UNITS
  DATABASE MICRONS 1000 ;
END UNITS


VERSION 5.7 ;
NAMESCASESENSITIVE ON ;
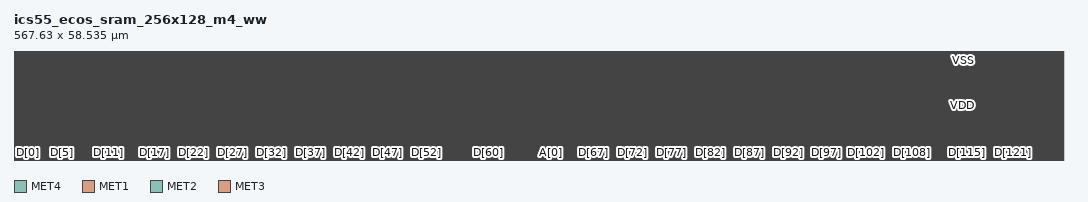
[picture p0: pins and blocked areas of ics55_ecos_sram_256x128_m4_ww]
MACRO ics55_ecos_sram_256x128_m4_ww
CLASS BLOCK ;
FOREIGN ics55_ecos_sram_256x128_m4_ww 0.000 0.000 ;
ORIGIN 0.000 0.000 ;
SIZE 567.630 BY 58.535 ;
SYMMETRY X Y R90 ;

PIN VDD
  DIRECTION INOUT ;
  USE POWER ;
  PORT
    LAYER MET4 ;
    RECT 0.605 0.000 1.015 58.535 ;
    RECT 1.735 0.000 2.145 58.535 ;
    RECT 2.335 0.000 2.745 58.535 ;
    RECT 3.535 0.000 3.945 58.535 ;
    RECT 4.135 0.000 4.545 58.535 ;
    RECT 4.735 0.000 5.145 58.535 ;
    RECT 5.935 0.000 6.345 58.535 ;
    RECT 6.535 0.000 6.945 58.535 ;
    RECT 7.735 0.000 8.145 58.535 ;
    RECT 8.335 0.000 8.745 58.535 ;
    RECT 8.935 0.000 9.345 58.535 ;
    RECT 10.135 0.000 10.545 58.535 ;
    RECT 10.735 0.000 11.145 58.535 ;
    RECT 11.935 0.000 12.345 58.535 ;
    RECT 12.535 0.000 12.945 58.535 ;
    RECT 13.135 0.000 13.545 58.535 ;
    RECT 14.335 0.000 14.745 58.535 ;
    RECT 14.935 0.000 15.345 58.535 ;
    RECT 16.135 0.000 16.545 58.535 ;
    RECT 16.735 0.000 17.145 58.535 ;
    RECT 17.335 0.000 17.745 58.535 ;
    RECT 18.535 0.000 18.945 58.535 ;
    RECT 19.135 0.000 19.545 58.535 ;
    RECT 20.335 0.000 20.745 58.535 ;
    RECT 20.935 0.000 21.345 58.535 ;
    RECT 21.535 0.000 21.945 58.535 ;
    RECT 22.735 0.000 23.145 58.535 ;
    RECT 23.335 0.000 23.745 58.535 ;
    RECT 24.535 0.000 24.945 58.535 ;
    RECT 25.135 0.000 25.545 58.535 ;
    RECT 25.735 0.000 26.145 58.535 ;
    RECT 26.935 0.000 27.345 58.535 ;
    RECT 27.535 0.000 27.945 58.535 ;
    RECT 28.735 0.000 29.145 58.535 ;
    RECT 29.335 0.000 29.745 58.535 ;
    RECT 29.935 0.000 30.345 58.535 ;
    RECT 31.135 0.000 31.545 58.535 ;
    RECT 31.735 0.000 32.145 58.535 ;
    RECT 32.935 0.000 33.345 58.535 ;
    RECT 33.535 0.000 33.945 58.535 ;
    RECT 34.135 0.000 34.545 58.535 ;
    RECT 35.335 0.000 35.745 58.535 ;
    RECT 35.935 0.000 36.345 58.535 ;
    RECT 37.135 0.000 37.545 58.535 ;
    RECT 37.735 0.000 38.145 58.535 ;
    RECT 38.335 0.000 38.745 58.535 ;
    RECT 39.535 0.000 39.945 58.535 ;
    RECT 40.135 0.000 40.545 58.535 ;
    RECT 41.335 0.000 41.745 58.535 ;
    RECT 41.935 0.000 42.345 58.535 ;
    RECT 42.535 0.000 42.945 58.535 ;
    RECT 43.735 0.000 44.145 58.535 ;
    RECT 44.335 0.000 44.745 58.535 ;
    RECT 45.535 0.000 45.945 58.535 ;
    RECT 46.135 0.000 46.545 58.535 ;
    RECT 46.735 0.000 47.145 58.535 ;
    RECT 47.935 0.000 48.345 58.535 ;
    RECT 48.535 0.000 48.945 58.535 ;
    RECT 49.735 0.000 50.145 58.535 ;
    RECT 50.335 0.000 50.745 58.535 ;
    RECT 50.935 0.000 51.345 58.535 ;
    RECT 52.135 0.000 52.545 58.535 ;
    RECT 52.735 0.000 53.145 58.535 ;
    RECT 53.935 0.000 54.345 58.535 ;
    RECT 54.535 0.000 54.945 58.535 ;
    RECT 55.135 0.000 55.545 58.535 ;
    RECT 56.335 0.000 56.745 58.535 ;
    RECT 56.935 0.000 57.345 58.535 ;
    RECT 58.135 0.000 58.545 58.535 ;
    RECT 58.735 0.000 59.145 58.535 ;
    RECT 59.335 0.000 59.745 58.535 ;
    RECT 60.535 0.000 60.945 58.535 ;
    RECT 61.135 0.000 61.545 58.535 ;
    RECT 62.335 0.000 62.745 58.535 ;
    RECT 62.935 0.000 63.345 58.535 ;
    RECT 63.535 0.000 63.945 58.535 ;
    RECT 64.735 0.000 65.145 58.535 ;
    RECT 65.335 0.000 65.745 58.535 ;
    RECT 66.535 0.000 66.945 58.535 ;
    RECT 67.135 0.000 67.545 58.535 ;
    RECT 67.735 0.000 68.145 58.535 ;
    RECT 68.935 0.000 69.345 58.535 ;
    RECT 69.535 0.000 69.945 58.535 ;
    RECT 70.735 0.000 71.145 58.535 ;
    RECT 71.335 0.000 71.745 58.535 ;
    RECT 71.935 0.000 72.345 58.535 ;
    RECT 73.135 0.000 73.545 58.535 ;
    RECT 73.735 0.000 74.145 58.535 ;
    RECT 74.935 0.000 75.345 58.535 ;
    RECT 75.535 0.000 75.945 58.535 ;
    RECT 76.135 0.000 76.545 58.535 ;
    RECT 77.335 0.000 77.745 58.535 ;
    RECT 77.935 0.000 78.345 58.535 ;
    RECT 79.135 0.000 79.545 58.535 ;
    RECT 79.735 0.000 80.145 58.535 ;
    RECT 80.335 0.000 80.745 58.535 ;
    RECT 81.535 0.000 81.945 58.535 ;
    RECT 82.135 0.000 82.545 58.535 ;
    RECT 83.335 0.000 83.745 58.535 ;
    RECT 83.935 0.000 84.345 58.535 ;
    RECT 84.535 0.000 84.945 58.535 ;
    RECT 85.735 0.000 86.145 58.535 ;
    RECT 86.335 0.000 86.745 58.535 ;
    RECT 87.535 0.000 87.945 58.535 ;
    RECT 88.135 0.000 88.545 58.535 ;
    RECT 88.735 0.000 89.145 58.535 ;
    RECT 89.935 0.000 90.345 58.535 ;
    RECT 90.535 0.000 90.945 58.535 ;
    RECT 91.735 0.000 92.145 58.535 ;
    RECT 92.335 0.000 92.745 58.535 ;
    RECT 92.935 0.000 93.345 58.535 ;
    RECT 94.135 0.000 94.545 58.535 ;
    RECT 94.735 0.000 95.145 58.535 ;
    RECT 95.935 0.000 96.345 58.535 ;
    RECT 96.535 0.000 96.945 58.535 ;
    RECT 97.135 0.000 97.545 58.535 ;
    RECT 98.335 0.000 98.745 58.535 ;
    RECT 98.935 0.000 99.345 58.535 ;
    RECT 100.135 0.000 100.545 58.535 ;
    RECT 100.735 0.000 101.145 58.535 ;
    RECT 101.335 0.000 101.745 58.535 ;
    RECT 102.535 0.000 102.945 58.535 ;
    RECT 103.135 0.000 103.545 58.535 ;
    RECT 104.335 0.000 104.745 58.535 ;
    RECT 104.935 0.000 105.345 58.535 ;
    RECT 105.535 0.000 105.945 58.535 ;
    RECT 106.735 0.000 107.145 58.535 ;
    RECT 107.335 0.000 107.745 58.535 ;
    RECT 108.535 0.000 108.945 58.535 ;
    RECT 109.135 0.000 109.545 58.535 ;
    RECT 109.735 0.000 110.145 58.535 ;
    RECT 110.935 0.000 111.345 58.535 ;
    RECT 111.535 0.000 111.945 58.535 ;
    RECT 112.735 0.000 113.145 58.535 ;
    RECT 113.335 0.000 113.745 58.535 ;
    RECT 113.935 0.000 114.345 58.535 ;
    RECT 115.135 0.000 115.545 58.535 ;
    RECT 115.735 0.000 116.145 58.535 ;
    RECT 116.935 0.000 117.345 58.535 ;
    RECT 117.535 0.000 117.945 58.535 ;
    RECT 118.135 0.000 118.545 58.535 ;
    RECT 119.335 0.000 119.745 58.535 ;
    RECT 119.935 0.000 120.345 58.535 ;
    RECT 121.135 0.000 121.545 58.535 ;
    RECT 121.735 0.000 122.145 58.535 ;
    RECT 122.335 0.000 122.745 58.535 ;
    RECT 123.535 0.000 123.945 58.535 ;
    RECT 124.135 0.000 124.545 58.535 ;
    RECT 125.335 0.000 125.745 58.535 ;
    RECT 125.935 0.000 126.345 58.535 ;
    RECT 126.535 0.000 126.945 58.535 ;
    RECT 127.735 0.000 128.145 58.535 ;
    RECT 128.335 0.000 128.745 58.535 ;
    RECT 129.535 0.000 129.945 58.535 ;
    RECT 130.135 0.000 130.545 58.535 ;
    RECT 130.735 0.000 131.145 58.535 ;
    RECT 131.935 0.000 132.345 58.535 ;
    RECT 132.535 0.000 132.945 58.535 ;
    RECT 133.735 0.000 134.145 58.535 ;
    RECT 134.335 0.000 134.745 58.535 ;
    RECT 134.935 0.000 135.345 58.535 ;
    RECT 136.135 0.000 136.545 58.535 ;
    RECT 136.735 0.000 137.145 58.535 ;
    RECT 137.935 0.000 138.345 58.535 ;
    RECT 138.535 0.000 138.945 58.535 ;
    RECT 139.135 0.000 139.545 58.535 ;
    RECT 140.335 0.000 140.745 58.535 ;
    RECT 140.935 0.000 141.345 58.535 ;
    RECT 142.135 0.000 142.545 58.535 ;
    RECT 142.735 0.000 143.145 58.535 ;
    RECT 143.335 0.000 143.745 58.535 ;
    RECT 144.535 0.000 144.945 58.535 ;
    RECT 145.135 0.000 145.545 58.535 ;
    RECT 146.335 0.000 146.745 58.535 ;
    RECT 146.935 0.000 147.345 58.535 ;
    RECT 147.535 0.000 147.945 58.535 ;
    RECT 148.735 0.000 149.145 58.535 ;
    RECT 149.335 0.000 149.745 58.535 ;
    RECT 150.535 0.000 150.945 58.535 ;
    RECT 151.135 0.000 151.545 58.535 ;
    RECT 151.735 0.000 152.145 58.535 ;
    RECT 152.935 0.000 153.345 58.535 ;
    RECT 153.535 0.000 153.945 58.535 ;
    RECT 154.735 0.000 155.145 58.535 ;
    RECT 155.335 0.000 155.745 58.535 ;
    RECT 155.935 0.000 156.345 58.535 ;
    RECT 157.135 0.000 157.545 58.535 ;
    RECT 157.735 0.000 158.145 58.535 ;
    RECT 158.935 0.000 159.345 58.535 ;
    RECT 159.535 0.000 159.945 58.535 ;
    RECT 160.135 0.000 160.545 58.535 ;
    RECT 161.335 0.000 161.745 58.535 ;
    RECT 161.935 0.000 162.345 58.535 ;
    RECT 163.135 0.000 163.545 58.535 ;
    RECT 163.735 0.000 164.145 58.535 ;
    RECT 164.335 0.000 164.745 58.535 ;
    RECT 165.535 0.000 165.945 58.535 ;
    RECT 166.135 0.000 166.545 58.535 ;
    RECT 167.335 0.000 167.745 58.535 ;
    RECT 167.935 0.000 168.345 58.535 ;
    RECT 168.535 0.000 168.945 58.535 ;
    RECT 169.735 0.000 170.145 58.535 ;
    RECT 170.335 0.000 170.745 58.535 ;
    RECT 171.535 0.000 171.945 58.535 ;
    RECT 172.135 0.000 172.545 58.535 ;
    RECT 172.735 0.000 173.145 58.535 ;
    RECT 173.935 0.000 174.345 58.535 ;
    RECT 174.535 0.000 174.945 58.535 ;
    RECT 175.735 0.000 176.145 58.535 ;
    RECT 176.335 0.000 176.745 58.535 ;
    RECT 176.935 0.000 177.345 58.535 ;
    RECT 178.135 0.000 178.545 58.535 ;
    RECT 178.735 0.000 179.145 58.535 ;
    RECT 179.935 0.000 180.345 58.535 ;
    RECT 180.535 0.000 180.945 58.535 ;
    RECT 181.135 0.000 181.545 58.535 ;
    RECT 182.335 0.000 182.745 58.535 ;
    RECT 182.935 0.000 183.345 58.535 ;
    RECT 184.135 0.000 184.545 58.535 ;
    RECT 184.735 0.000 185.145 58.535 ;
    RECT 185.335 0.000 185.745 58.535 ;
    RECT 186.535 0.000 186.945 58.535 ;
    RECT 187.135 0.000 187.545 58.535 ;
    RECT 188.335 0.000 188.745 58.535 ;
    RECT 188.935 0.000 189.345 58.535 ;
    RECT 189.535 0.000 189.945 58.535 ;
    RECT 190.735 0.000 191.145 58.535 ;
    RECT 191.335 0.000 191.745 58.535 ;
    RECT 192.535 0.000 192.945 58.535 ;
    RECT 193.135 0.000 193.545 58.535 ;
    RECT 193.735 0.000 194.145 58.535 ;
    RECT 194.935 0.000 195.345 58.535 ;
    RECT 195.535 0.000 195.945 58.535 ;
    RECT 196.735 0.000 197.145 58.535 ;
    RECT 197.335 0.000 197.745 58.535 ;
    RECT 197.935 0.000 198.345 58.535 ;
    RECT 199.135 0.000 199.545 58.535 ;
    RECT 199.735 0.000 200.145 58.535 ;
    RECT 200.935 0.000 201.345 58.535 ;
    RECT 201.535 0.000 201.945 58.535 ;
    RECT 202.135 0.000 202.545 58.535 ;
    RECT 203.335 0.000 203.745 58.535 ;
    RECT 203.935 0.000 204.345 58.535 ;
    RECT 205.135 0.000 205.545 58.535 ;
    RECT 205.735 0.000 206.145 58.535 ;
    RECT 206.335 0.000 206.745 58.535 ;
    RECT 207.535 0.000 207.945 58.535 ;
    RECT 208.135 0.000 208.545 58.535 ;
    RECT 209.335 0.000 209.745 58.535 ;
    RECT 209.935 0.000 210.345 58.535 ;
    RECT 210.535 0.000 210.945 58.535 ;
    RECT 211.735 0.000 212.145 58.535 ;
    RECT 212.335 0.000 212.745 58.535 ;
    RECT 213.535 0.000 213.945 58.535 ;
    RECT 214.135 0.000 214.545 58.535 ;
    RECT 214.735 0.000 215.145 58.535 ;
    RECT 215.935 0.000 216.345 58.535 ;
    RECT 216.535 0.000 216.945 58.535 ;
    RECT 217.735 0.000 218.145 58.535 ;
    RECT 218.335 0.000 218.745 58.535 ;
    RECT 218.935 0.000 219.345 58.535 ;
    RECT 220.135 0.000 220.545 58.535 ;
    RECT 220.735 0.000 221.145 58.535 ;
    RECT 221.935 0.000 222.345 58.535 ;
    RECT 222.535 0.000 222.945 58.535 ;
    RECT 223.135 0.000 223.545 58.535 ;
    RECT 224.335 0.000 224.745 58.535 ;
    RECT 224.935 0.000 225.345 58.535 ;
    RECT 226.135 0.000 226.545 58.535 ;
    RECT 226.735 0.000 227.145 58.535 ;
    RECT 227.335 0.000 227.745 58.535 ;
    RECT 228.535 0.000 228.945 58.535 ;
    RECT 229.135 0.000 229.545 58.535 ;
    RECT 230.335 0.000 230.745 58.535 ;
    RECT 230.935 0.000 231.345 58.535 ;
    RECT 231.535 0.000 231.945 58.535 ;
    RECT 232.735 0.000 233.145 58.535 ;
    RECT 233.335 0.000 233.745 58.535 ;
    RECT 234.535 0.000 234.945 58.535 ;
    RECT 235.135 0.000 235.545 58.535 ;
    RECT 235.735 0.000 236.145 58.535 ;
    RECT 236.935 0.000 237.345 58.535 ;
    RECT 237.535 0.000 237.945 58.535 ;
    RECT 238.735 0.000 239.145 58.535 ;
    RECT 239.335 0.000 239.745 58.535 ;
    RECT 239.935 0.000 240.345 58.535 ;
    RECT 241.135 0.000 241.545 58.535 ;
    RECT 241.735 0.000 242.145 58.535 ;
    RECT 242.935 0.000 243.345 58.535 ;
    RECT 243.535 0.000 243.945 58.535 ;
    RECT 244.135 0.000 244.545 58.535 ;
    RECT 245.335 0.000 245.745 58.535 ;
    RECT 245.935 0.000 246.345 58.535 ;
    RECT 247.135 0.000 247.545 58.535 ;
    RECT 247.735 0.000 248.145 58.535 ;
    RECT 248.335 0.000 248.745 58.535 ;
    RECT 249.535 0.000 249.945 58.535 ;
    RECT 250.135 0.000 250.545 58.535 ;
    RECT 251.335 0.000 251.745 58.535 ;
    RECT 251.935 0.000 252.345 58.535 ;
    RECT 252.535 0.000 252.945 58.535 ;
    RECT 253.735 0.000 254.145 58.535 ;
    RECT 254.335 0.000 254.745 58.535 ;
    RECT 255.535 0.000 255.945 58.535 ;
    RECT 256.135 0.000 256.545 58.535 ;
    RECT 256.735 0.000 257.145 58.535 ;
    RECT 257.935 0.000 258.345 58.535 ;
    RECT 258.535 0.000 258.945 58.535 ;
    RECT 259.735 0.000 260.145 58.535 ;
    RECT 260.335 0.000 260.745 58.535 ;
    RECT 260.935 0.000 261.345 58.535 ;
    RECT 262.135 0.000 262.545 58.535 ;
    RECT 262.735 0.000 263.145 58.535 ;
    RECT 263.935 0.000 264.345 58.535 ;
    RECT 264.535 0.000 264.945 58.535 ;
    RECT 265.135 0.000 265.545 58.535 ;
    RECT 266.335 0.000 266.745 58.535 ;
    RECT 266.935 0.000 267.345 58.535 ;
    RECT 268.135 0.000 268.545 58.535 ;
    RECT 268.735 0.000 269.145 58.535 ;
    RECT 269.335 0.000 269.745 58.535 ;
    RECT 270.465 0.000 270.875 58.535 ;
    RECT 272.360 0.000 272.770 58.535 ;
    RECT 272.890 0.000 273.300 58.535 ;
    RECT 273.950 0.000 274.360 58.535 ;
    RECT 274.480 0.000 274.890 58.535 ;
    RECT 275.540 0.000 275.950 58.535 ;
    RECT 276.070 0.000 276.480 58.535 ;
    RECT 277.130 0.000 277.540 58.535 ;
    RECT 277.660 0.000 278.070 58.535 ;
    RECT 278.720 0.000 279.130 58.535 ;
    RECT 279.250 0.000 279.660 58.535 ;
    RECT 280.310 0.000 280.720 58.535 ;
    RECT 280.840 0.000 281.250 58.535 ;
    RECT 281.900 0.000 282.310 58.535 ;
    RECT 282.430 0.000 282.840 58.535 ;
    RECT 283.490 0.000 283.900 58.535 ;
    RECT 284.020 0.000 284.430 58.535 ;
    RECT 285.080 0.000 285.490 58.535 ;
    RECT 285.610 0.000 286.020 58.535 ;
    RECT 286.670 0.000 287.080 58.535 ;
    RECT 287.200 0.000 287.610 58.535 ;
    RECT 288.260 0.000 288.670 58.535 ;
    RECT 288.790 0.000 289.200 58.535 ;
    RECT 289.850 0.000 290.260 58.535 ;
    RECT 290.380 0.000 290.790 58.535 ;
    RECT 291.440 0.000 291.850 58.535 ;
    RECT 291.970 0.000 292.380 58.535 ;
    RECT 293.030 0.000 293.440 58.535 ;
    RECT 293.560 0.000 293.970 58.535 ;
    RECT 294.620 0.000 295.030 58.535 ;
    RECT 295.150 0.000 295.560 58.535 ;
    RECT 296.755 0.000 297.165 58.535 ;
    RECT 297.885 0.000 298.295 58.535 ;
    RECT 298.485 0.000 298.895 58.535 ;
    RECT 299.685 0.000 300.095 58.535 ;
    RECT 300.285 0.000 300.695 58.535 ;
    RECT 300.885 0.000 301.295 58.535 ;
    RECT 302.085 0.000 302.495 58.535 ;
    RECT 302.685 0.000 303.095 58.535 ;
    RECT 303.885 0.000 304.295 58.535 ;
    RECT 304.485 0.000 304.895 58.535 ;
    RECT 305.085 0.000 305.495 58.535 ;
    RECT 306.285 0.000 306.695 58.535 ;
    RECT 306.885 0.000 307.295 58.535 ;
    RECT 308.085 0.000 308.495 58.535 ;
    RECT 308.685 0.000 309.095 58.535 ;
    RECT 309.285 0.000 309.695 58.535 ;
    RECT 310.485 0.000 310.895 58.535 ;
    RECT 311.085 0.000 311.495 58.535 ;
    RECT 312.285 0.000 312.695 58.535 ;
    RECT 312.885 0.000 313.295 58.535 ;
    RECT 313.485 0.000 313.895 58.535 ;
    RECT 314.685 0.000 315.095 58.535 ;
    RECT 315.285 0.000 315.695 58.535 ;
    RECT 316.485 0.000 316.895 58.535 ;
    RECT 317.085 0.000 317.495 58.535 ;
    RECT 317.685 0.000 318.095 58.535 ;
    RECT 318.885 0.000 319.295 58.535 ;
    RECT 319.485 0.000 319.895 58.535 ;
    RECT 320.685 0.000 321.095 58.535 ;
    RECT 321.285 0.000 321.695 58.535 ;
    RECT 321.885 0.000 322.295 58.535 ;
    RECT 323.085 0.000 323.495 58.535 ;
    RECT 323.685 0.000 324.095 58.535 ;
    RECT 324.885 0.000 325.295 58.535 ;
    RECT 325.485 0.000 325.895 58.535 ;
    RECT 326.085 0.000 326.495 58.535 ;
    RECT 327.285 0.000 327.695 58.535 ;
    RECT 327.885 0.000 328.295 58.535 ;
    RECT 329.085 0.000 329.495 58.535 ;
    RECT 329.685 0.000 330.095 58.535 ;
    RECT 330.285 0.000 330.695 58.535 ;
    RECT 331.485 0.000 331.895 58.535 ;
    RECT 332.085 0.000 332.495 58.535 ;
    RECT 333.285 0.000 333.695 58.535 ;
    RECT 333.885 0.000 334.295 58.535 ;
    RECT 334.485 0.000 334.895 58.535 ;
    RECT 335.685 0.000 336.095 58.535 ;
    RECT 336.285 0.000 336.695 58.535 ;
    RECT 337.485 0.000 337.895 58.535 ;
    RECT 338.085 0.000 338.495 58.535 ;
    RECT 338.685 0.000 339.095 58.535 ;
    RECT 339.885 0.000 340.295 58.535 ;
    RECT 340.485 0.000 340.895 58.535 ;
    RECT 341.685 0.000 342.095 58.535 ;
    RECT 342.285 0.000 342.695 58.535 ;
    RECT 342.885 0.000 343.295 58.535 ;
    RECT 344.085 0.000 344.495 58.535 ;
    RECT 344.685 0.000 345.095 58.535 ;
    RECT 345.885 0.000 346.295 58.535 ;
    RECT 346.485 0.000 346.895 58.535 ;
    RECT 347.085 0.000 347.495 58.535 ;
    RECT 348.285 0.000 348.695 58.535 ;
    RECT 348.885 0.000 349.295 58.535 ;
    RECT 350.085 0.000 350.495 58.535 ;
    RECT 350.685 0.000 351.095 58.535 ;
    RECT 351.285 0.000 351.695 58.535 ;
    RECT 352.485 0.000 352.895 58.535 ;
    RECT 353.085 0.000 353.495 58.535 ;
    RECT 354.285 0.000 354.695 58.535 ;
    RECT 354.885 0.000 355.295 58.535 ;
    RECT 355.485 0.000 355.895 58.535 ;
    RECT 356.685 0.000 357.095 58.535 ;
    RECT 357.285 0.000 357.695 58.535 ;
    RECT 358.485 0.000 358.895 58.535 ;
    RECT 359.085 0.000 359.495 58.535 ;
    RECT 359.685 0.000 360.095 58.535 ;
    RECT 360.885 0.000 361.295 58.535 ;
    RECT 361.485 0.000 361.895 58.535 ;
    RECT 362.685 0.000 363.095 58.535 ;
    RECT 363.285 0.000 363.695 58.535 ;
    RECT 363.885 0.000 364.295 58.535 ;
    RECT 365.085 0.000 365.495 58.535 ;
    RECT 365.685 0.000 366.095 58.535 ;
    RECT 366.885 0.000 367.295 58.535 ;
    RECT 367.485 0.000 367.895 58.535 ;
    RECT 368.085 0.000 368.495 58.535 ;
    RECT 369.285 0.000 369.695 58.535 ;
    RECT 369.885 0.000 370.295 58.535 ;
    RECT 371.085 0.000 371.495 58.535 ;
    RECT 371.685 0.000 372.095 58.535 ;
    RECT 372.285 0.000 372.695 58.535 ;
    RECT 373.485 0.000 373.895 58.535 ;
    RECT 374.085 0.000 374.495 58.535 ;
    RECT 375.285 0.000 375.695 58.535 ;
    RECT 375.885 0.000 376.295 58.535 ;
    RECT 376.485 0.000 376.895 58.535 ;
    RECT 377.685 0.000 378.095 58.535 ;
    RECT 378.285 0.000 378.695 58.535 ;
    RECT 379.485 0.000 379.895 58.535 ;
    RECT 380.085 0.000 380.495 58.535 ;
    RECT 380.685 0.000 381.095 58.535 ;
    RECT 381.885 0.000 382.295 58.535 ;
    RECT 382.485 0.000 382.895 58.535 ;
    RECT 383.685 0.000 384.095 58.535 ;
    RECT 384.285 0.000 384.695 58.535 ;
    RECT 384.885 0.000 385.295 58.535 ;
    RECT 386.085 0.000 386.495 58.535 ;
    RECT 386.685 0.000 387.095 58.535 ;
    RECT 387.885 0.000 388.295 58.535 ;
    RECT 388.485 0.000 388.895 58.535 ;
    RECT 389.085 0.000 389.495 58.535 ;
    RECT 390.285 0.000 390.695 58.535 ;
    RECT 390.885 0.000 391.295 58.535 ;
    RECT 392.085 0.000 392.495 58.535 ;
    RECT 392.685 0.000 393.095 58.535 ;
    RECT 393.285 0.000 393.695 58.535 ;
    RECT 394.485 0.000 394.895 58.535 ;
    RECT 395.085 0.000 395.495 58.535 ;
    RECT 396.285 0.000 396.695 58.535 ;
    RECT 396.885 0.000 397.295 58.535 ;
    RECT 397.485 0.000 397.895 58.535 ;
    RECT 398.685 0.000 399.095 58.535 ;
    RECT 399.285 0.000 399.695 58.535 ;
    RECT 400.485 0.000 400.895 58.535 ;
    RECT 401.085 0.000 401.495 58.535 ;
    RECT 401.685 0.000 402.095 58.535 ;
    RECT 402.885 0.000 403.295 58.535 ;
    RECT 403.485 0.000 403.895 58.535 ;
    RECT 404.685 0.000 405.095 58.535 ;
    RECT 405.285 0.000 405.695 58.535 ;
    RECT 405.885 0.000 406.295 58.535 ;
    RECT 407.085 0.000 407.495 58.535 ;
    RECT 407.685 0.000 408.095 58.535 ;
    RECT 408.885 0.000 409.295 58.535 ;
    RECT 409.485 0.000 409.895 58.535 ;
    RECT 410.085 0.000 410.495 58.535 ;
    RECT 411.285 0.000 411.695 58.535 ;
    RECT 411.885 0.000 412.295 58.535 ;
    RECT 413.085 0.000 413.495 58.535 ;
    RECT 413.685 0.000 414.095 58.535 ;
    RECT 414.285 0.000 414.695 58.535 ;
    RECT 415.485 0.000 415.895 58.535 ;
    RECT 416.085 0.000 416.495 58.535 ;
    RECT 417.285 0.000 417.695 58.535 ;
    RECT 417.885 0.000 418.295 58.535 ;
    RECT 418.485 0.000 418.895 58.535 ;
    RECT 419.685 0.000 420.095 58.535 ;
    RECT 420.285 0.000 420.695 58.535 ;
    RECT 421.485 0.000 421.895 58.535 ;
    RECT 422.085 0.000 422.495 58.535 ;
    RECT 422.685 0.000 423.095 58.535 ;
    RECT 423.885 0.000 424.295 58.535 ;
    RECT 424.485 0.000 424.895 58.535 ;
    RECT 425.685 0.000 426.095 58.535 ;
    RECT 426.285 0.000 426.695 58.535 ;
    RECT 426.885 0.000 427.295 58.535 ;
    RECT 428.085 0.000 428.495 58.535 ;
    RECT 428.685 0.000 429.095 58.535 ;
    RECT 429.885 0.000 430.295 58.535 ;
    RECT 430.485 0.000 430.895 58.535 ;
    RECT 431.085 0.000 431.495 58.535 ;
    RECT 432.285 0.000 432.695 58.535 ;
    RECT 432.885 0.000 433.295 58.535 ;
    RECT 434.085 0.000 434.495 58.535 ;
    RECT 434.685 0.000 435.095 58.535 ;
    RECT 435.285 0.000 435.695 58.535 ;
    RECT 436.485 0.000 436.895 58.535 ;
    RECT 437.085 0.000 437.495 58.535 ;
    RECT 438.285 0.000 438.695 58.535 ;
    RECT 438.885 0.000 439.295 58.535 ;
    RECT 439.485 0.000 439.895 58.535 ;
    RECT 440.685 0.000 441.095 58.535 ;
    RECT 441.285 0.000 441.695 58.535 ;
    RECT 442.485 0.000 442.895 58.535 ;
    RECT 443.085 0.000 443.495 58.535 ;
    RECT 443.685 0.000 444.095 58.535 ;
    RECT 444.885 0.000 445.295 58.535 ;
    RECT 445.485 0.000 445.895 58.535 ;
    RECT 446.685 0.000 447.095 58.535 ;
    RECT 447.285 0.000 447.695 58.535 ;
    RECT 447.885 0.000 448.295 58.535 ;
    RECT 449.085 0.000 449.495 58.535 ;
    RECT 449.685 0.000 450.095 58.535 ;
    RECT 450.885 0.000 451.295 58.535 ;
    RECT 451.485 0.000 451.895 58.535 ;
    RECT 452.085 0.000 452.495 58.535 ;
    RECT 453.285 0.000 453.695 58.535 ;
    RECT 453.885 0.000 454.295 58.535 ;
    RECT 455.085 0.000 455.495 58.535 ;
    RECT 455.685 0.000 456.095 58.535 ;
    RECT 456.285 0.000 456.695 58.535 ;
    RECT 457.485 0.000 457.895 58.535 ;
    RECT 458.085 0.000 458.495 58.535 ;
    RECT 459.285 0.000 459.695 58.535 ;
    RECT 459.885 0.000 460.295 58.535 ;
    RECT 460.485 0.000 460.895 58.535 ;
    RECT 461.685 0.000 462.095 58.535 ;
    RECT 462.285 0.000 462.695 58.535 ;
    RECT 463.485 0.000 463.895 58.535 ;
    RECT 464.085 0.000 464.495 58.535 ;
    RECT 464.685 0.000 465.095 58.535 ;
    RECT 465.885 0.000 466.295 58.535 ;
    RECT 466.485 0.000 466.895 58.535 ;
    RECT 467.685 0.000 468.095 58.535 ;
    RECT 468.285 0.000 468.695 58.535 ;
    RECT 468.885 0.000 469.295 58.535 ;
    RECT 470.085 0.000 470.495 58.535 ;
    RECT 470.685 0.000 471.095 58.535 ;
    RECT 471.885 0.000 472.295 58.535 ;
    RECT 472.485 0.000 472.895 58.535 ;
    RECT 473.085 0.000 473.495 58.535 ;
    RECT 474.285 0.000 474.695 58.535 ;
    RECT 474.885 0.000 475.295 58.535 ;
    RECT 476.085 0.000 476.495 58.535 ;
    RECT 476.685 0.000 477.095 58.535 ;
    RECT 477.285 0.000 477.695 58.535 ;
    RECT 478.485 0.000 478.895 58.535 ;
    RECT 479.085 0.000 479.495 58.535 ;
    RECT 480.285 0.000 480.695 58.535 ;
    RECT 480.885 0.000 481.295 58.535 ;
    RECT 481.485 0.000 481.895 58.535 ;
    RECT 482.685 0.000 483.095 58.535 ;
    RECT 483.285 0.000 483.695 58.535 ;
    RECT 484.485 0.000 484.895 58.535 ;
    RECT 485.085 0.000 485.495 58.535 ;
    RECT 485.685 0.000 486.095 58.535 ;
    RECT 486.885 0.000 487.295 58.535 ;
    RECT 487.485 0.000 487.895 58.535 ;
    RECT 488.685 0.000 489.095 58.535 ;
    RECT 489.285 0.000 489.695 58.535 ;
    RECT 489.885 0.000 490.295 58.535 ;
    RECT 491.085 0.000 491.495 58.535 ;
    RECT 491.685 0.000 492.095 58.535 ;
    RECT 492.885 0.000 493.295 58.535 ;
    RECT 493.485 0.000 493.895 58.535 ;
    RECT 494.085 0.000 494.495 58.535 ;
    RECT 495.285 0.000 495.695 58.535 ;
    RECT 495.885 0.000 496.295 58.535 ;
    RECT 497.085 0.000 497.495 58.535 ;
    RECT 497.685 0.000 498.095 58.535 ;
    RECT 498.285 0.000 498.695 58.535 ;
    RECT 499.485 0.000 499.895 58.535 ;
    RECT 500.085 0.000 500.495 58.535 ;
    RECT 501.285 0.000 501.695 58.535 ;
    RECT 501.885 0.000 502.295 58.535 ;
    RECT 502.485 0.000 502.895 58.535 ;
    RECT 503.685 0.000 504.095 58.535 ;
    RECT 504.285 0.000 504.695 58.535 ;
    RECT 505.485 0.000 505.895 58.535 ;
    RECT 506.085 0.000 506.495 58.535 ;
    RECT 506.685 0.000 507.095 58.535 ;
    RECT 507.885 0.000 508.295 58.535 ;
    RECT 508.485 0.000 508.895 58.535 ;
    RECT 509.685 0.000 510.095 58.535 ;
    RECT 510.285 0.000 510.695 58.535 ;
    RECT 510.885 0.000 511.295 58.535 ;
    RECT 512.085 0.000 512.495 58.535 ;
    RECT 512.685 0.000 513.095 58.535 ;
    RECT 513.885 0.000 514.295 58.535 ;
    RECT 514.485 0.000 514.895 58.535 ;
    RECT 515.085 0.000 515.495 58.535 ;
    RECT 516.285 0.000 516.695 58.535 ;
    RECT 516.885 0.000 517.295 58.535 ;
    RECT 518.085 0.000 518.495 58.535 ;
    RECT 518.685 0.000 519.095 58.535 ;
    RECT 519.285 0.000 519.695 58.535 ;
    RECT 520.485 0.000 520.895 58.535 ;
    RECT 521.085 0.000 521.495 58.535 ;
    RECT 522.285 0.000 522.695 58.535 ;
    RECT 522.885 0.000 523.295 58.535 ;
    RECT 523.485 0.000 523.895 58.535 ;
    RECT 524.685 0.000 525.095 58.535 ;
    RECT 525.285 0.000 525.695 58.535 ;
    RECT 526.485 0.000 526.895 58.535 ;
    RECT 527.085 0.000 527.495 58.535 ;
    RECT 527.685 0.000 528.095 58.535 ;
    RECT 528.885 0.000 529.295 58.535 ;
    RECT 529.485 0.000 529.895 58.535 ;
    RECT 530.685 0.000 531.095 58.535 ;
    RECT 531.285 0.000 531.695 58.535 ;
    RECT 531.885 0.000 532.295 58.535 ;
    RECT 533.085 0.000 533.495 58.535 ;
    RECT 533.685 0.000 534.095 58.535 ;
    RECT 534.885 0.000 535.295 58.535 ;
    RECT 535.485 0.000 535.895 58.535 ;
    RECT 536.085 0.000 536.495 58.535 ;
    RECT 537.285 0.000 537.695 58.535 ;
    RECT 537.885 0.000 538.295 58.535 ;
    RECT 539.085 0.000 539.495 58.535 ;
    RECT 539.685 0.000 540.095 58.535 ;
    RECT 540.285 0.000 540.695 58.535 ;
    RECT 541.485 0.000 541.895 58.535 ;
    RECT 542.085 0.000 542.495 58.535 ;
    RECT 543.285 0.000 543.695 58.535 ;
    RECT 543.885 0.000 544.295 58.535 ;
    RECT 544.485 0.000 544.895 58.535 ;
    RECT 545.685 0.000 546.095 58.535 ;
    RECT 546.285 0.000 546.695 58.535 ;
    RECT 547.485 0.000 547.895 58.535 ;
    RECT 548.085 0.000 548.495 58.535 ;
    RECT 548.685 0.000 549.095 58.535 ;
    RECT 549.885 0.000 550.295 58.535 ;
    RECT 550.485 0.000 550.895 58.535 ;
    RECT 551.685 0.000 552.095 58.535 ;
    RECT 552.285 0.000 552.695 58.535 ;
    RECT 552.885 0.000 553.295 58.535 ;
    RECT 554.085 0.000 554.495 58.535 ;
    RECT 554.685 0.000 555.095 58.535 ;
    RECT 555.885 0.000 556.295 58.535 ;
    RECT 556.485 0.000 556.895 58.535 ;
    RECT 557.085 0.000 557.495 58.535 ;
    RECT 558.285 0.000 558.695 58.535 ;
    RECT 558.885 0.000 559.295 58.535 ;
    RECT 560.085 0.000 560.495 58.535 ;
    RECT 560.685 0.000 561.095 58.535 ;
    RECT 561.285 0.000 561.695 58.535 ;
    RECT 562.485 0.000 562.895 58.535 ;
    RECT 563.085 0.000 563.495 58.535 ;
    RECT 564.285 0.000 564.695 58.535 ;
    RECT 564.885 0.000 565.295 58.535 ;
    RECT 565.485 0.000 565.895 58.535 ;
    RECT 566.615 0.000 567.025 58.535 ;
  END
END VDD

PIN VSS
  DIRECTION INOUT ;
  USE GROUND ;
  PORT
    LAYER MET4 ;
    RECT 0.075 0.000 0.485 58.535 ;
    RECT 1.135 0.000 1.545 58.535 ;
    RECT 2.935 0.000 3.345 58.535 ;
    RECT 5.335 0.000 5.745 58.535 ;
    RECT 7.135 0.000 7.545 58.535 ;
    RECT 9.535 0.000 9.945 58.535 ;
    RECT 11.335 0.000 11.745 58.535 ;
    RECT 13.735 0.000 14.145 58.535 ;
    RECT 15.535 0.000 15.945 58.535 ;
    RECT 17.935 0.000 18.345 58.535 ;
    RECT 19.735 0.000 20.145 58.535 ;
    RECT 22.135 0.000 22.545 58.535 ;
    RECT 23.935 0.000 24.345 58.535 ;
    RECT 26.335 0.000 26.745 58.535 ;
    RECT 28.135 0.000 28.545 58.535 ;
    RECT 30.535 0.000 30.945 58.535 ;
    RECT 32.335 0.000 32.745 58.535 ;
    RECT 34.735 0.000 35.145 58.535 ;
    RECT 36.535 0.000 36.945 58.535 ;
    RECT 38.935 0.000 39.345 58.535 ;
    RECT 40.735 0.000 41.145 58.535 ;
    RECT 43.135 0.000 43.545 58.535 ;
    RECT 44.935 0.000 45.345 58.535 ;
    RECT 47.335 0.000 47.745 58.535 ;
    RECT 49.135 0.000 49.545 58.535 ;
    RECT 51.535 0.000 51.945 58.535 ;
    RECT 53.335 0.000 53.745 58.535 ;
    RECT 55.735 0.000 56.145 58.535 ;
    RECT 57.535 0.000 57.945 58.535 ;
    RECT 59.935 0.000 60.345 58.535 ;
    RECT 61.735 0.000 62.145 58.535 ;
    RECT 64.135 0.000 64.545 58.535 ;
    RECT 65.935 0.000 66.345 58.535 ;
    RECT 68.335 0.000 68.745 58.535 ;
    RECT 70.135 0.000 70.545 58.535 ;
    RECT 72.535 0.000 72.945 58.535 ;
    RECT 74.335 0.000 74.745 58.535 ;
    RECT 76.735 0.000 77.145 58.535 ;
    RECT 78.535 0.000 78.945 58.535 ;
    RECT 80.935 0.000 81.345 58.535 ;
    RECT 82.735 0.000 83.145 58.535 ;
    RECT 85.135 0.000 85.545 58.535 ;
    RECT 86.935 0.000 87.345 58.535 ;
    RECT 89.335 0.000 89.745 58.535 ;
    RECT 91.135 0.000 91.545 58.535 ;
    RECT 93.535 0.000 93.945 58.535 ;
    RECT 95.335 0.000 95.745 58.535 ;
    RECT 97.735 0.000 98.145 58.535 ;
    RECT 99.535 0.000 99.945 58.535 ;
    RECT 101.935 0.000 102.345 58.535 ;
    RECT 103.735 0.000 104.145 58.535 ;
    RECT 106.135 0.000 106.545 58.535 ;
    RECT 107.935 0.000 108.345 58.535 ;
    RECT 110.335 0.000 110.745 58.535 ;
    RECT 112.135 0.000 112.545 58.535 ;
    RECT 114.535 0.000 114.945 58.535 ;
    RECT 116.335 0.000 116.745 58.535 ;
    RECT 118.735 0.000 119.145 58.535 ;
    RECT 120.535 0.000 120.945 58.535 ;
    RECT 122.935 0.000 123.345 58.535 ;
    RECT 124.735 0.000 125.145 58.535 ;
    RECT 127.135 0.000 127.545 58.535 ;
    RECT 128.935 0.000 129.345 58.535 ;
    RECT 131.335 0.000 131.745 58.535 ;
    RECT 133.135 0.000 133.545 58.535 ;
    RECT 135.535 0.000 135.945 58.535 ;
    RECT 137.335 0.000 137.745 58.535 ;
    RECT 139.735 0.000 140.145 58.535 ;
    RECT 141.535 0.000 141.945 58.535 ;
    RECT 143.935 0.000 144.345 58.535 ;
    RECT 145.735 0.000 146.145 58.535 ;
    RECT 148.135 0.000 148.545 58.535 ;
    RECT 149.935 0.000 150.345 58.535 ;
    RECT 152.335 0.000 152.745 58.535 ;
    RECT 154.135 0.000 154.545 58.535 ;
    RECT 156.535 0.000 156.945 58.535 ;
    RECT 158.335 0.000 158.745 58.535 ;
    RECT 160.735 0.000 161.145 58.535 ;
    RECT 162.535 0.000 162.945 58.535 ;
    RECT 164.935 0.000 165.345 58.535 ;
    RECT 166.735 0.000 167.145 58.535 ;
    RECT 169.135 0.000 169.545 58.535 ;
    RECT 170.935 0.000 171.345 58.535 ;
    RECT 173.335 0.000 173.745 58.535 ;
    RECT 175.135 0.000 175.545 58.535 ;
    RECT 177.535 0.000 177.945 58.535 ;
    RECT 179.335 0.000 179.745 58.535 ;
    RECT 181.735 0.000 182.145 58.535 ;
    RECT 183.535 0.000 183.945 58.535 ;
    RECT 185.935 0.000 186.345 58.535 ;
    RECT 187.735 0.000 188.145 58.535 ;
    RECT 190.135 0.000 190.545 58.535 ;
    RECT 191.935 0.000 192.345 58.535 ;
    RECT 194.335 0.000 194.745 58.535 ;
    RECT 196.135 0.000 196.545 58.535 ;
    RECT 198.535 0.000 198.945 58.535 ;
    RECT 200.335 0.000 200.745 58.535 ;
    RECT 202.735 0.000 203.145 58.535 ;
    RECT 204.535 0.000 204.945 58.535 ;
    RECT 206.935 0.000 207.345 58.535 ;
    RECT 208.735 0.000 209.145 58.535 ;
    RECT 211.135 0.000 211.545 58.535 ;
    RECT 212.935 0.000 213.345 58.535 ;
    RECT 215.335 0.000 215.745 58.535 ;
    RECT 217.135 0.000 217.545 58.535 ;
    RECT 219.535 0.000 219.945 58.535 ;
    RECT 221.335 0.000 221.745 58.535 ;
    RECT 223.735 0.000 224.145 58.535 ;
    RECT 225.535 0.000 225.945 58.535 ;
    RECT 227.935 0.000 228.345 58.535 ;
    RECT 229.735 0.000 230.145 58.535 ;
    RECT 232.135 0.000 232.545 58.535 ;
    RECT 233.935 0.000 234.345 58.535 ;
    RECT 236.335 0.000 236.745 58.535 ;
    RECT 238.135 0.000 238.545 58.535 ;
    RECT 240.535 0.000 240.945 58.535 ;
    RECT 242.335 0.000 242.745 58.535 ;
    RECT 244.735 0.000 245.145 58.535 ;
    RECT 246.535 0.000 246.945 58.535 ;
    RECT 248.935 0.000 249.345 58.535 ;
    RECT 250.735 0.000 251.145 58.535 ;
    RECT 253.135 0.000 253.545 58.535 ;
    RECT 254.935 0.000 255.345 58.535 ;
    RECT 257.335 0.000 257.745 58.535 ;
    RECT 259.135 0.000 259.545 58.535 ;
    RECT 261.535 0.000 261.945 58.535 ;
    RECT 263.335 0.000 263.745 58.535 ;
    RECT 265.735 0.000 266.145 58.535 ;
    RECT 267.535 0.000 267.945 58.535 ;
    RECT 269.935 0.000 270.345 58.535 ;
    RECT 270.995 0.000 271.405 58.535 ;
    RECT 271.830 0.000 272.240 58.535 ;
    RECT 273.420 0.000 273.830 58.535 ;
    RECT 275.010 0.000 275.420 58.535 ;
    RECT 276.600 0.000 277.010 58.535 ;
    RECT 278.190 0.000 278.600 58.535 ;
    RECT 279.780 0.000 280.190 58.535 ;
    RECT 281.370 0.000 281.780 58.535 ;
    RECT 282.960 0.000 283.370 58.535 ;
    RECT 284.550 0.000 284.960 58.535 ;
    RECT 286.140 0.000 286.550 58.535 ;
    RECT 287.730 0.000 288.140 58.535 ;
    RECT 289.320 0.000 289.730 58.535 ;
    RECT 290.910 0.000 291.320 58.535 ;
    RECT 292.500 0.000 292.910 58.535 ;
    RECT 294.090 0.000 294.500 58.535 ;
    RECT 295.680 0.000 296.090 58.535 ;
    RECT 296.225 0.000 296.635 58.535 ;
    RECT 297.285 0.000 297.695 58.535 ;
    RECT 299.085 0.000 299.495 58.535 ;
    RECT 301.485 0.000 301.895 58.535 ;
    RECT 303.285 0.000 303.695 58.535 ;
    RECT 305.685 0.000 306.095 58.535 ;
    RECT 307.485 0.000 307.895 58.535 ;
    RECT 309.885 0.000 310.295 58.535 ;
    RECT 311.685 0.000 312.095 58.535 ;
    RECT 314.085 0.000 314.495 58.535 ;
    RECT 315.885 0.000 316.295 58.535 ;
    RECT 318.285 0.000 318.695 58.535 ;
    RECT 320.085 0.000 320.495 58.535 ;
    RECT 322.485 0.000 322.895 58.535 ;
    RECT 324.285 0.000 324.695 58.535 ;
    RECT 326.685 0.000 327.095 58.535 ;
    RECT 328.485 0.000 328.895 58.535 ;
    RECT 330.885 0.000 331.295 58.535 ;
    RECT 332.685 0.000 333.095 58.535 ;
    RECT 335.085 0.000 335.495 58.535 ;
    RECT 336.885 0.000 337.295 58.535 ;
    RECT 339.285 0.000 339.695 58.535 ;
    RECT 341.085 0.000 341.495 58.535 ;
    RECT 343.485 0.000 343.895 58.535 ;
    RECT 345.285 0.000 345.695 58.535 ;
    RECT 347.685 0.000 348.095 58.535 ;
    RECT 349.485 0.000 349.895 58.535 ;
    RECT 351.885 0.000 352.295 58.535 ;
    RECT 353.685 0.000 354.095 58.535 ;
    RECT 356.085 0.000 356.495 58.535 ;
    RECT 357.885 0.000 358.295 58.535 ;
    RECT 360.285 0.000 360.695 58.535 ;
    RECT 362.085 0.000 362.495 58.535 ;
    RECT 364.485 0.000 364.895 58.535 ;
    RECT 366.285 0.000 366.695 58.535 ;
    RECT 368.685 0.000 369.095 58.535 ;
    RECT 370.485 0.000 370.895 58.535 ;
    RECT 372.885 0.000 373.295 58.535 ;
    RECT 374.685 0.000 375.095 58.535 ;
    RECT 377.085 0.000 377.495 58.535 ;
    RECT 378.885 0.000 379.295 58.535 ;
    RECT 381.285 0.000 381.695 58.535 ;
    RECT 383.085 0.000 383.495 58.535 ;
    RECT 385.485 0.000 385.895 58.535 ;
    RECT 387.285 0.000 387.695 58.535 ;
    RECT 389.685 0.000 390.095 58.535 ;
    RECT 391.485 0.000 391.895 58.535 ;
    RECT 393.885 0.000 394.295 58.535 ;
    RECT 395.685 0.000 396.095 58.535 ;
    RECT 398.085 0.000 398.495 58.535 ;
    RECT 399.885 0.000 400.295 58.535 ;
    RECT 402.285 0.000 402.695 58.535 ;
    RECT 404.085 0.000 404.495 58.535 ;
    RECT 406.485 0.000 406.895 58.535 ;
    RECT 408.285 0.000 408.695 58.535 ;
    RECT 410.685 0.000 411.095 58.535 ;
    RECT 412.485 0.000 412.895 58.535 ;
    RECT 414.885 0.000 415.295 58.535 ;
    RECT 416.685 0.000 417.095 58.535 ;
    RECT 419.085 0.000 419.495 58.535 ;
    RECT 420.885 0.000 421.295 58.535 ;
    RECT 423.285 0.000 423.695 58.535 ;
    RECT 425.085 0.000 425.495 58.535 ;
    RECT 427.485 0.000 427.895 58.535 ;
    RECT 429.285 0.000 429.695 58.535 ;
    RECT 431.685 0.000 432.095 58.535 ;
    RECT 433.485 0.000 433.895 58.535 ;
    RECT 435.885 0.000 436.295 58.535 ;
    RECT 437.685 0.000 438.095 58.535 ;
    RECT 440.085 0.000 440.495 58.535 ;
    RECT 441.885 0.000 442.295 58.535 ;
    RECT 444.285 0.000 444.695 58.535 ;
    RECT 446.085 0.000 446.495 58.535 ;
    RECT 448.485 0.000 448.895 58.535 ;
    RECT 450.285 0.000 450.695 58.535 ;
    RECT 452.685 0.000 453.095 58.535 ;
    RECT 454.485 0.000 454.895 58.535 ;
    RECT 456.885 0.000 457.295 58.535 ;
    RECT 458.685 0.000 459.095 58.535 ;
    RECT 461.085 0.000 461.495 58.535 ;
    RECT 462.885 0.000 463.295 58.535 ;
    RECT 465.285 0.000 465.695 58.535 ;
    RECT 467.085 0.000 467.495 58.535 ;
    RECT 469.485 0.000 469.895 58.535 ;
    RECT 471.285 0.000 471.695 58.535 ;
    RECT 473.685 0.000 474.095 58.535 ;
    RECT 475.485 0.000 475.895 58.535 ;
    RECT 477.885 0.000 478.295 58.535 ;
    RECT 479.685 0.000 480.095 58.535 ;
    RECT 482.085 0.000 482.495 58.535 ;
    RECT 483.885 0.000 484.295 58.535 ;
    RECT 486.285 0.000 486.695 58.535 ;
    RECT 488.085 0.000 488.495 58.535 ;
    RECT 490.485 0.000 490.895 58.535 ;
    RECT 492.285 0.000 492.695 58.535 ;
    RECT 494.685 0.000 495.095 58.535 ;
    RECT 496.485 0.000 496.895 58.535 ;
    RECT 498.885 0.000 499.295 58.535 ;
    RECT 500.685 0.000 501.095 58.535 ;
    RECT 503.085 0.000 503.495 58.535 ;
    RECT 504.885 0.000 505.295 58.535 ;
    RECT 507.285 0.000 507.695 58.535 ;
    RECT 509.085 0.000 509.495 58.535 ;
    RECT 511.485 0.000 511.895 58.535 ;
    RECT 513.285 0.000 513.695 58.535 ;
    RECT 515.685 0.000 516.095 58.535 ;
    RECT 517.485 0.000 517.895 58.535 ;
    RECT 519.885 0.000 520.295 58.535 ;
    RECT 521.685 0.000 522.095 58.535 ;
    RECT 524.085 0.000 524.495 58.535 ;
    RECT 525.885 0.000 526.295 58.535 ;
    RECT 528.285 0.000 528.695 58.535 ;
    RECT 530.085 0.000 530.495 58.535 ;
    RECT 532.485 0.000 532.895 58.535 ;
    RECT 534.285 0.000 534.695 58.535 ;
    RECT 536.685 0.000 537.095 58.535 ;
    RECT 538.485 0.000 538.895 58.535 ;
    RECT 540.885 0.000 541.295 58.535 ;
    RECT 542.685 0.000 543.095 58.535 ;
    RECT 545.085 0.000 545.495 58.535 ;
    RECT 546.885 0.000 547.295 58.535 ;
    RECT 549.285 0.000 549.695 58.535 ;
    RECT 551.085 0.000 551.495 58.535 ;
    RECT 553.485 0.000 553.895 58.535 ;
    RECT 555.285 0.000 555.695 58.535 ;
    RECT 557.685 0.000 558.095 58.535 ;
    RECT 559.485 0.000 559.895 58.535 ;
    RECT 561.885 0.000 562.295 58.535 ;
    RECT 563.685 0.000 564.095 58.535 ;
    RECT 566.085 0.000 566.495 58.535 ;
    RECT 567.145 0.000 567.555 58.535 ;
  END
END VSS

PIN D[0]
  DIRECTION INPUT ;
  PORT
    LAYER MET1 ;
    RECT 4.540 0.000 4.950 0.180 ;
    LAYER MET2 ;
    RECT 4.540 0.000 4.950 0.180 ;
    LAYER MET3 ;
    RECT 4.540 0.000 4.950 0.180 ;
  END
  ANTENNADIFFAREA                0.38930         LAYER MET1 ;
  ANTENNADIFFAREA                0.38930         LAYER MET2 ;
  ANTENNADIFFAREA                0.38930         LAYER MET3 ;
  ANTENNAGATEAREA                0.06300         LAYER MET1 ;
  ANTENNAGATEAREA                0.06300         LAYER MET2 ;
  ANTENNAGATEAREA                0.06300         LAYER MET3 ;
  ANTENNAPARTIALMETALAREA        0.09890         LAYER MET1 ;
  ANTENNAPARTIALMETALAREA        0.10380         LAYER MET2 ;
  ANTENNAMAXAREACAR              0.72381         LAYER MET1 ;
  ANTENNAMAXAREACAR              3.54286         LAYER MET2 ;
  ANTENNAMAXAREACAR              4.71429         LAYER MET3 ;
END D[0]
PIN D[1]
  DIRECTION INPUT ;
  PORT
    LAYER MET1 ;
    RECT 8.740 0.000 9.150 0.180 ;
    LAYER MET2 ;
    RECT 8.740 0.000 9.150 0.180 ;
    LAYER MET3 ;
    RECT 8.740 0.000 9.150 0.180 ;
  END
  ANTENNADIFFAREA                0.38930         LAYER MET1 ;
  ANTENNADIFFAREA                0.38930         LAYER MET2 ;
  ANTENNADIFFAREA                0.38930         LAYER MET3 ;
  ANTENNAGATEAREA                0.06300         LAYER MET1 ;
  ANTENNAGATEAREA                0.06300         LAYER MET2 ;
  ANTENNAGATEAREA                0.06300         LAYER MET3 ;
  ANTENNAPARTIALMETALAREA        0.09890         LAYER MET1 ;
  ANTENNAPARTIALMETALAREA        0.10380         LAYER MET2 ;
  ANTENNAMAXAREACAR              0.72381         LAYER MET1 ;
  ANTENNAMAXAREACAR              3.54286         LAYER MET2 ;
  ANTENNAMAXAREACAR              4.71429         LAYER MET3 ;
END D[1]
PIN Q[0]
  DIRECTION OUTPUT ;
  PORT
    LAYER MET1 ;
    RECT 3.000 0.000 3.410 0.180 ;
    LAYER MET2 ;
    RECT 3.000 0.000 3.410 0.180 ;
    LAYER MET3 ;
    RECT 3.000 0.000 3.410 0.180 ;
  END
  ANTENNADIFFAREA                0.60000         LAYER MET1 ;
  ANTENNADIFFAREA                0.60000         LAYER MET2 ;
  ANTENNADIFFAREA                0.60000         LAYER MET3 ;
  ANTENNAPARTIALMETALAREA        0.94400         LAYER MET1 ;
  ANTENNAPARTIALMETALAREA        1.33320         LAYER MET2 ;
END Q[0]
PIN Q[1]
  DIRECTION OUTPUT ;
  PORT
    LAYER MET1 ;
    RECT 7.200 0.000 7.610 0.180 ;
    LAYER MET2 ;
    RECT 7.200 0.000 7.610 0.180 ;
    LAYER MET3 ;
    RECT 7.200 0.000 7.610 0.180 ;
  END
  ANTENNADIFFAREA                0.60000         LAYER MET1 ;
  ANTENNADIFFAREA                0.60000         LAYER MET2 ;
  ANTENNADIFFAREA                0.60000         LAYER MET3 ;
  ANTENNAPARTIALMETALAREA        0.94400         LAYER MET1 ;
  ANTENNAPARTIALMETALAREA        1.33320         LAYER MET2 ;
END Q[1]
PIN D[2]
  DIRECTION INPUT ;
  PORT
    LAYER MET1 ;
    RECT 12.940 0.000 13.350 0.180 ;
    LAYER MET2 ;
    RECT 12.940 0.000 13.350 0.180 ;
    LAYER MET3 ;
    RECT 12.940 0.000 13.350 0.180 ;
  END
  ANTENNADIFFAREA                0.38930         LAYER MET1 ;
  ANTENNADIFFAREA                0.38930         LAYER MET2 ;
  ANTENNADIFFAREA                0.38930         LAYER MET3 ;
  ANTENNAGATEAREA                0.06300         LAYER MET1 ;
  ANTENNAGATEAREA                0.06300         LAYER MET2 ;
  ANTENNAGATEAREA                0.06300         LAYER MET3 ;
  ANTENNAPARTIALMETALAREA        0.09890         LAYER MET1 ;
  ANTENNAPARTIALMETALAREA        0.10380         LAYER MET2 ;
  ANTENNAMAXAREACAR              0.72381         LAYER MET1 ;
  ANTENNAMAXAREACAR              3.54286         LAYER MET2 ;
  ANTENNAMAXAREACAR              4.71429         LAYER MET3 ;
END D[2]
PIN Q[2]
  DIRECTION OUTPUT ;
  PORT
    LAYER MET1 ;
    RECT 11.400 0.000 11.810 0.180 ;
    LAYER MET2 ;
    RECT 11.400 0.000 11.810 0.180 ;
    LAYER MET3 ;
    RECT 11.400 0.000 11.810 0.180 ;
  END
  ANTENNADIFFAREA                0.60000         LAYER MET1 ;
  ANTENNADIFFAREA                0.60000         LAYER MET2 ;
  ANTENNADIFFAREA                0.60000         LAYER MET3 ;
  ANTENNAPARTIALMETALAREA        0.94400         LAYER MET1 ;
  ANTENNAPARTIALMETALAREA        1.33320         LAYER MET2 ;
END Q[2]
PIN D[3]
  DIRECTION INPUT ;
  PORT
    LAYER MET1 ;
    RECT 17.140 0.000 17.550 0.180 ;
    LAYER MET2 ;
    RECT 17.140 0.000 17.550 0.180 ;
    LAYER MET3 ;
    RECT 17.140 0.000 17.550 0.180 ;
  END
  ANTENNADIFFAREA                0.38930         LAYER MET1 ;
  ANTENNADIFFAREA                0.38930         LAYER MET2 ;
  ANTENNADIFFAREA                0.38930         LAYER MET3 ;
  ANTENNAGATEAREA                0.06300         LAYER MET1 ;
  ANTENNAGATEAREA                0.06300         LAYER MET2 ;
  ANTENNAGATEAREA                0.06300         LAYER MET3 ;
  ANTENNAPARTIALMETALAREA        0.09890         LAYER MET1 ;
  ANTENNAPARTIALMETALAREA        0.10380         LAYER MET2 ;
  ANTENNAMAXAREACAR              0.72381         LAYER MET1 ;
  ANTENNAMAXAREACAR              3.54286         LAYER MET2 ;
  ANTENNAMAXAREACAR              4.71429         LAYER MET3 ;
END D[3]
PIN Q[3]
  DIRECTION OUTPUT ;
  PORT
    LAYER MET1 ;
    RECT 15.600 0.000 16.010 0.180 ;
    LAYER MET2 ;
    RECT 15.600 0.000 16.010 0.180 ;
    LAYER MET3 ;
    RECT 15.600 0.000 16.010 0.180 ;
  END
  ANTENNADIFFAREA                0.60000         LAYER MET1 ;
  ANTENNADIFFAREA                0.60000         LAYER MET2 ;
  ANTENNADIFFAREA                0.60000         LAYER MET3 ;
  ANTENNAPARTIALMETALAREA        0.94400         LAYER MET1 ;
  ANTENNAPARTIALMETALAREA        1.33320         LAYER MET2 ;
END Q[3]
PIN D[4]
  DIRECTION INPUT ;
  PORT
    LAYER MET1 ;
    RECT 21.340 0.000 21.750 0.180 ;
    LAYER MET2 ;
    RECT 21.340 0.000 21.750 0.180 ;
    LAYER MET3 ;
    RECT 21.340 0.000 21.750 0.180 ;
  END
  ANTENNADIFFAREA                0.38930         LAYER MET1 ;
  ANTENNADIFFAREA                0.38930         LAYER MET2 ;
  ANTENNADIFFAREA                0.38930         LAYER MET3 ;
  ANTENNAGATEAREA                0.06300         LAYER MET1 ;
  ANTENNAGATEAREA                0.06300         LAYER MET2 ;
  ANTENNAGATEAREA                0.06300         LAYER MET3 ;
  ANTENNAPARTIALMETALAREA        0.09890         LAYER MET1 ;
  ANTENNAPARTIALMETALAREA        0.10380         LAYER MET2 ;
  ANTENNAMAXAREACAR              0.72381         LAYER MET1 ;
  ANTENNAMAXAREACAR              3.54286         LAYER MET2 ;
  ANTENNAMAXAREACAR              4.71429         LAYER MET3 ;
END D[4]
PIN Q[8]
  DIRECTION OUTPUT ;
  PORT
    LAYER MET1 ;
    RECT 36.600 0.000 37.010 0.180 ;
    LAYER MET2 ;
    RECT 36.600 0.000 37.010 0.180 ;
    LAYER MET3 ;
    RECT 36.600 0.000 37.010 0.180 ;
  END
  ANTENNADIFFAREA                0.60000         LAYER MET1 ;
  ANTENNADIFFAREA                0.60000         LAYER MET2 ;
  ANTENNADIFFAREA                0.60000         LAYER MET3 ;
  ANTENNAPARTIALMETALAREA        0.94400         LAYER MET1 ;
  ANTENNAPARTIALMETALAREA        1.33320         LAYER MET2 ;
END Q[8]
PIN D[9]
  DIRECTION INPUT ;
  PORT
    LAYER MET1 ;
    RECT 42.340 0.000 42.750 0.180 ;
    LAYER MET2 ;
    RECT 42.340 0.000 42.750 0.180 ;
    LAYER MET3 ;
    RECT 42.340 0.000 42.750 0.180 ;
  END
  ANTENNADIFFAREA                0.38930         LAYER MET1 ;
  ANTENNADIFFAREA                0.38930         LAYER MET2 ;
  ANTENNADIFFAREA                0.38930         LAYER MET3 ;
  ANTENNAGATEAREA                0.06300         LAYER MET1 ;
  ANTENNAGATEAREA                0.06300         LAYER MET2 ;
  ANTENNAGATEAREA                0.06300         LAYER MET3 ;
  ANTENNAPARTIALMETALAREA        0.09890         LAYER MET1 ;
  ANTENNAPARTIALMETALAREA        0.10380         LAYER MET2 ;
  ANTENNAMAXAREACAR              0.72381         LAYER MET1 ;
  ANTENNAMAXAREACAR              3.54286         LAYER MET2 ;
  ANTENNAMAXAREACAR              4.71429         LAYER MET3 ;
END D[9]
PIN Q[4]
  DIRECTION OUTPUT ;
  PORT
    LAYER MET1 ;
    RECT 19.800 0.000 20.210 0.180 ;
    LAYER MET2 ;
    RECT 19.800 0.000 20.210 0.180 ;
    LAYER MET3 ;
    RECT 19.800 0.000 20.210 0.180 ;
  END
  ANTENNADIFFAREA                0.60000         LAYER MET1 ;
  ANTENNADIFFAREA                0.60000         LAYER MET2 ;
  ANTENNADIFFAREA                0.60000         LAYER MET3 ;
  ANTENNAPARTIALMETALAREA        0.94400         LAYER MET1 ;
  ANTENNAPARTIALMETALAREA        1.33320         LAYER MET2 ;
END Q[4]
PIN D[5]
  DIRECTION INPUT ;
  PORT
    LAYER MET1 ;
    RECT 25.540 0.000 25.950 0.180 ;
    LAYER MET2 ;
    RECT 25.540 0.000 25.950 0.180 ;
    LAYER MET3 ;
    RECT 25.540 0.000 25.950 0.180 ;
  END
  ANTENNADIFFAREA                0.38930         LAYER MET1 ;
  ANTENNADIFFAREA                0.38930         LAYER MET2 ;
  ANTENNADIFFAREA                0.38930         LAYER MET3 ;
  ANTENNAGATEAREA                0.06300         LAYER MET1 ;
  ANTENNAGATEAREA                0.06300         LAYER MET2 ;
  ANTENNAGATEAREA                0.06300         LAYER MET3 ;
  ANTENNAPARTIALMETALAREA        0.09890         LAYER MET1 ;
  ANTENNAPARTIALMETALAREA        0.10380         LAYER MET2 ;
  ANTENNAMAXAREACAR              0.72381         LAYER MET1 ;
  ANTENNAMAXAREACAR              3.54286         LAYER MET2 ;
  ANTENNAMAXAREACAR              4.71429         LAYER MET3 ;
END D[5]
PIN Q[5]
  DIRECTION OUTPUT ;
  PORT
    LAYER MET1 ;
    RECT 24.000 0.000 24.410 0.180 ;
    LAYER MET2 ;
    RECT 24.000 0.000 24.410 0.180 ;
    LAYER MET3 ;
    RECT 24.000 0.000 24.410 0.180 ;
  END
  ANTENNADIFFAREA                0.60000         LAYER MET1 ;
  ANTENNADIFFAREA                0.60000         LAYER MET2 ;
  ANTENNADIFFAREA                0.60000         LAYER MET3 ;
  ANTENNAPARTIALMETALAREA        0.94400         LAYER MET1 ;
  ANTENNAPARTIALMETALAREA        1.33320         LAYER MET2 ;
END Q[5]
PIN D[6]
  DIRECTION INPUT ;
  PORT
    LAYER MET1 ;
    RECT 29.740 0.000 30.150 0.180 ;
    LAYER MET2 ;
    RECT 29.740 0.000 30.150 0.180 ;
    LAYER MET3 ;
    RECT 29.740 0.000 30.150 0.180 ;
  END
  ANTENNADIFFAREA                0.38930         LAYER MET1 ;
  ANTENNADIFFAREA                0.38930         LAYER MET2 ;
  ANTENNADIFFAREA                0.38930         LAYER MET3 ;
  ANTENNAGATEAREA                0.06300         LAYER MET1 ;
  ANTENNAGATEAREA                0.06300         LAYER MET2 ;
  ANTENNAGATEAREA                0.06300         LAYER MET3 ;
  ANTENNAPARTIALMETALAREA        0.09890         LAYER MET1 ;
  ANTENNAPARTIALMETALAREA        0.10380         LAYER MET2 ;
  ANTENNAMAXAREACAR              0.72381         LAYER MET1 ;
  ANTENNAMAXAREACAR              3.54286         LAYER MET2 ;
  ANTENNAMAXAREACAR              4.71429         LAYER MET3 ;
END D[6]
PIN Q[6]
  DIRECTION OUTPUT ;
  PORT
    LAYER MET1 ;
    RECT 28.200 0.000 28.610 0.180 ;
    LAYER MET2 ;
    RECT 28.200 0.000 28.610 0.180 ;
    LAYER MET3 ;
    RECT 28.200 0.000 28.610 0.180 ;
  END
  ANTENNADIFFAREA                0.60000         LAYER MET1 ;
  ANTENNADIFFAREA                0.60000         LAYER MET2 ;
  ANTENNADIFFAREA                0.60000         LAYER MET3 ;
  ANTENNAPARTIALMETALAREA        0.94400         LAYER MET1 ;
  ANTENNAPARTIALMETALAREA        1.33320         LAYER MET2 ;
END Q[6]
PIN D[7]
  DIRECTION INPUT ;
  PORT
    LAYER MET1 ;
    RECT 33.940 0.000 34.350 0.180 ;
    LAYER MET2 ;
    RECT 33.940 0.000 34.350 0.180 ;
    LAYER MET3 ;
    RECT 33.940 0.000 34.350 0.180 ;
  END
  ANTENNADIFFAREA                0.38930         LAYER MET1 ;
  ANTENNADIFFAREA                0.38930         LAYER MET2 ;
  ANTENNADIFFAREA                0.38930         LAYER MET3 ;
  ANTENNAGATEAREA                0.06300         LAYER MET1 ;
  ANTENNAGATEAREA                0.06300         LAYER MET2 ;
  ANTENNAGATEAREA                0.06300         LAYER MET3 ;
  ANTENNAPARTIALMETALAREA        0.09890         LAYER MET1 ;
  ANTENNAPARTIALMETALAREA        0.10380         LAYER MET2 ;
  ANTENNAMAXAREACAR              0.72381         LAYER MET1 ;
  ANTENNAMAXAREACAR              3.54286         LAYER MET2 ;
  ANTENNAMAXAREACAR              4.71429         LAYER MET3 ;
END D[7]
PIN Q[7]
  DIRECTION OUTPUT ;
  PORT
    LAYER MET1 ;
    RECT 32.400 0.000 32.810 0.180 ;
    LAYER MET2 ;
    RECT 32.400 0.000 32.810 0.180 ;
    LAYER MET3 ;
    RECT 32.400 0.000 32.810 0.180 ;
  END
  ANTENNADIFFAREA                0.60000         LAYER MET1 ;
  ANTENNADIFFAREA                0.60000         LAYER MET2 ;
  ANTENNADIFFAREA                0.60000         LAYER MET3 ;
  ANTENNAPARTIALMETALAREA        0.94400         LAYER MET1 ;
  ANTENNAPARTIALMETALAREA        1.33320         LAYER MET2 ;
END Q[7]
PIN D[8]
  DIRECTION INPUT ;
  PORT
    LAYER MET1 ;
    RECT 38.140 0.000 38.550 0.180 ;
    LAYER MET2 ;
    RECT 38.140 0.000 38.550 0.180 ;
    LAYER MET3 ;
    RECT 38.140 0.000 38.550 0.180 ;
  END
  ANTENNADIFFAREA                0.38930         LAYER MET1 ;
  ANTENNADIFFAREA                0.38930         LAYER MET2 ;
  ANTENNADIFFAREA                0.38930         LAYER MET3 ;
  ANTENNAGATEAREA                0.06300         LAYER MET1 ;
  ANTENNAGATEAREA                0.06300         LAYER MET2 ;
  ANTENNAGATEAREA                0.06300         LAYER MET3 ;
  ANTENNAPARTIALMETALAREA        0.09890         LAYER MET1 ;
  ANTENNAPARTIALMETALAREA        0.10380         LAYER MET2 ;
  ANTENNAMAXAREACAR              0.72381         LAYER MET1 ;
  ANTENNAMAXAREACAR              3.54286         LAYER MET2 ;
  ANTENNAMAXAREACAR              4.71429         LAYER MET3 ;
END D[8]
PIN Q[16]
  DIRECTION OUTPUT ;
  PORT
    LAYER MET1 ;
    RECT 70.200 0.000 70.610 0.180 ;
    LAYER MET2 ;
    RECT 70.200 0.000 70.610 0.180 ;
    LAYER MET3 ;
    RECT 70.200 0.000 70.610 0.180 ;
  END
  ANTENNADIFFAREA                0.60000         LAYER MET1 ;
  ANTENNADIFFAREA                0.60000         LAYER MET2 ;
  ANTENNADIFFAREA                0.60000         LAYER MET3 ;
  ANTENNAPARTIALMETALAREA        0.94400         LAYER MET1 ;
  ANTENNAPARTIALMETALAREA        1.33320         LAYER MET2 ;
END Q[16]
PIN Q[9]
  DIRECTION OUTPUT ;
  PORT
    LAYER MET1 ;
    RECT 40.800 0.000 41.210 0.180 ;
    LAYER MET2 ;
    RECT 40.800 0.000 41.210 0.180 ;
    LAYER MET3 ;
    RECT 40.800 0.000 41.210 0.180 ;
  END
  ANTENNADIFFAREA                0.60000         LAYER MET1 ;
  ANTENNADIFFAREA                0.60000         LAYER MET2 ;
  ANTENNADIFFAREA                0.60000         LAYER MET3 ;
  ANTENNAPARTIALMETALAREA        0.94400         LAYER MET1 ;
  ANTENNAPARTIALMETALAREA        1.33320         LAYER MET2 ;
END Q[9]
PIN D[10]
  DIRECTION INPUT ;
  PORT
    LAYER MET1 ;
    RECT 46.540 0.000 46.950 0.180 ;
    LAYER MET2 ;
    RECT 46.540 0.000 46.950 0.180 ;
    LAYER MET3 ;
    RECT 46.540 0.000 46.950 0.180 ;
  END
  ANTENNADIFFAREA                0.38930         LAYER MET1 ;
  ANTENNADIFFAREA                0.38930         LAYER MET2 ;
  ANTENNADIFFAREA                0.38930         LAYER MET3 ;
  ANTENNAGATEAREA                0.06300         LAYER MET1 ;
  ANTENNAGATEAREA                0.06300         LAYER MET2 ;
  ANTENNAGATEAREA                0.06300         LAYER MET3 ;
  ANTENNAPARTIALMETALAREA        0.09890         LAYER MET1 ;
  ANTENNAPARTIALMETALAREA        0.10380         LAYER MET2 ;
  ANTENNAMAXAREACAR              0.72381         LAYER MET1 ;
  ANTENNAMAXAREACAR              3.54286         LAYER MET2 ;
  ANTENNAMAXAREACAR              4.71429         LAYER MET3 ;
END D[10]
PIN Q[10]
  DIRECTION OUTPUT ;
  PORT
    LAYER MET1 ;
    RECT 45.000 0.000 45.410 0.180 ;
    LAYER MET2 ;
    RECT 45.000 0.000 45.410 0.180 ;
    LAYER MET3 ;
    RECT 45.000 0.000 45.410 0.180 ;
  END
  ANTENNADIFFAREA                0.60000         LAYER MET1 ;
  ANTENNADIFFAREA                0.60000         LAYER MET2 ;
  ANTENNADIFFAREA                0.60000         LAYER MET3 ;
  ANTENNAPARTIALMETALAREA        0.94400         LAYER MET1 ;
  ANTENNAPARTIALMETALAREA        1.33320         LAYER MET2 ;
END Q[10]
PIN D[11]
  DIRECTION INPUT ;
  PORT
    LAYER MET1 ;
    RECT 50.740 0.000 51.150 0.180 ;
    LAYER MET2 ;
    RECT 50.740 0.000 51.150 0.180 ;
    LAYER MET3 ;
    RECT 50.740 0.000 51.150 0.180 ;
  END
  ANTENNADIFFAREA                0.38930         LAYER MET1 ;
  ANTENNADIFFAREA                0.38930         LAYER MET2 ;
  ANTENNADIFFAREA                0.38930         LAYER MET3 ;
  ANTENNAGATEAREA                0.06300         LAYER MET1 ;
  ANTENNAGATEAREA                0.06300         LAYER MET2 ;
  ANTENNAGATEAREA                0.06300         LAYER MET3 ;
  ANTENNAPARTIALMETALAREA        0.09890         LAYER MET1 ;
  ANTENNAPARTIALMETALAREA        0.10380         LAYER MET2 ;
  ANTENNAMAXAREACAR              0.72381         LAYER MET1 ;
  ANTENNAMAXAREACAR              3.54286         LAYER MET2 ;
  ANTENNAMAXAREACAR              4.71429         LAYER MET3 ;
END D[11]
PIN Q[11]
  DIRECTION OUTPUT ;
  PORT
    LAYER MET1 ;
    RECT 49.200 0.000 49.610 0.180 ;
    LAYER MET2 ;
    RECT 49.200 0.000 49.610 0.180 ;
    LAYER MET3 ;
    RECT 49.200 0.000 49.610 0.180 ;
  END
  ANTENNADIFFAREA                0.60000         LAYER MET1 ;
  ANTENNADIFFAREA                0.60000         LAYER MET2 ;
  ANTENNADIFFAREA                0.60000         LAYER MET3 ;
  ANTENNAPARTIALMETALAREA        0.94400         LAYER MET1 ;
  ANTENNAPARTIALMETALAREA        1.33320         LAYER MET2 ;
END Q[11]
PIN D[12]
  DIRECTION INPUT ;
  PORT
    LAYER MET1 ;
    RECT 54.940 0.000 55.350 0.180 ;
    LAYER MET2 ;
    RECT 54.940 0.000 55.350 0.180 ;
    LAYER MET3 ;
    RECT 54.940 0.000 55.350 0.180 ;
  END
  ANTENNADIFFAREA                0.38930         LAYER MET1 ;
  ANTENNADIFFAREA                0.38930         LAYER MET2 ;
  ANTENNADIFFAREA                0.38930         LAYER MET3 ;
  ANTENNAGATEAREA                0.06300         LAYER MET1 ;
  ANTENNAGATEAREA                0.06300         LAYER MET2 ;
  ANTENNAGATEAREA                0.06300         LAYER MET3 ;
  ANTENNAPARTIALMETALAREA        0.09890         LAYER MET1 ;
  ANTENNAPARTIALMETALAREA        0.10380         LAYER MET2 ;
  ANTENNAMAXAREACAR              0.72381         LAYER MET1 ;
  ANTENNAMAXAREACAR              3.54286         LAYER MET2 ;
  ANTENNAMAXAREACAR              4.71429         LAYER MET3 ;
END D[12]
PIN Q[12]
  DIRECTION OUTPUT ;
  PORT
    LAYER MET1 ;
    RECT 53.400 0.000 53.810 0.180 ;
    LAYER MET2 ;
    RECT 53.400 0.000 53.810 0.180 ;
    LAYER MET3 ;
    RECT 53.400 0.000 53.810 0.180 ;
  END
  ANTENNADIFFAREA                0.60000         LAYER MET1 ;
  ANTENNADIFFAREA                0.60000         LAYER MET2 ;
  ANTENNADIFFAREA                0.60000         LAYER MET3 ;
  ANTENNAPARTIALMETALAREA        0.94400         LAYER MET1 ;
  ANTENNAPARTIALMETALAREA        1.33320         LAYER MET2 ;
END Q[12]
PIN D[13]
  DIRECTION INPUT ;
  PORT
    LAYER MET1 ;
    RECT 59.140 0.000 59.550 0.180 ;
    LAYER MET2 ;
    RECT 59.140 0.000 59.550 0.180 ;
    LAYER MET3 ;
    RECT 59.140 0.000 59.550 0.180 ;
  END
  ANTENNADIFFAREA                0.38930         LAYER MET1 ;
  ANTENNADIFFAREA                0.38930         LAYER MET2 ;
  ANTENNADIFFAREA                0.38930         LAYER MET3 ;
  ANTENNAGATEAREA                0.06300         LAYER MET1 ;
  ANTENNAGATEAREA                0.06300         LAYER MET2 ;
  ANTENNAGATEAREA                0.06300         LAYER MET3 ;
  ANTENNAPARTIALMETALAREA        0.09890         LAYER MET1 ;
  ANTENNAPARTIALMETALAREA        0.10380         LAYER MET2 ;
  ANTENNAMAXAREACAR              0.72381         LAYER MET1 ;
  ANTENNAMAXAREACAR              3.54286         LAYER MET2 ;
  ANTENNAMAXAREACAR              4.71429         LAYER MET3 ;
END D[13]
PIN Q[13]
  DIRECTION OUTPUT ;
  PORT
    LAYER MET1 ;
    RECT 57.600 0.000 58.010 0.180 ;
    LAYER MET2 ;
    RECT 57.600 0.000 58.010 0.180 ;
    LAYER MET3 ;
    RECT 57.600 0.000 58.010 0.180 ;
  END
  ANTENNADIFFAREA                0.60000         LAYER MET1 ;
  ANTENNADIFFAREA                0.60000         LAYER MET2 ;
  ANTENNADIFFAREA                0.60000         LAYER MET3 ;
  ANTENNAPARTIALMETALAREA        0.94400         LAYER MET1 ;
  ANTENNAPARTIALMETALAREA        1.33320         LAYER MET2 ;
END Q[13]
PIN D[14]
  DIRECTION INPUT ;
  PORT
    LAYER MET1 ;
    RECT 63.340 0.000 63.750 0.180 ;
    LAYER MET2 ;
    RECT 63.340 0.000 63.750 0.180 ;
    LAYER MET3 ;
    RECT 63.340 0.000 63.750 0.180 ;
  END
  ANTENNADIFFAREA                0.38930         LAYER MET1 ;
  ANTENNADIFFAREA                0.38930         LAYER MET2 ;
  ANTENNADIFFAREA                0.38930         LAYER MET3 ;
  ANTENNAGATEAREA                0.06300         LAYER MET1 ;
  ANTENNAGATEAREA                0.06300         LAYER MET2 ;
  ANTENNAGATEAREA                0.06300         LAYER MET3 ;
  ANTENNAPARTIALMETALAREA        0.09890         LAYER MET1 ;
  ANTENNAPARTIALMETALAREA        0.10380         LAYER MET2 ;
  ANTENNAMAXAREACAR              0.72381         LAYER MET1 ;
  ANTENNAMAXAREACAR              3.54286         LAYER MET2 ;
  ANTENNAMAXAREACAR              4.71429         LAYER MET3 ;
END D[14]
PIN Q[14]
  DIRECTION OUTPUT ;
  PORT
    LAYER MET1 ;
    RECT 61.800 0.000 62.210 0.180 ;
    LAYER MET2 ;
    RECT 61.800 0.000 62.210 0.180 ;
    LAYER MET3 ;
    RECT 61.800 0.000 62.210 0.180 ;
  END
  ANTENNADIFFAREA                0.60000         LAYER MET1 ;
  ANTENNADIFFAREA                0.60000         LAYER MET2 ;
  ANTENNADIFFAREA                0.60000         LAYER MET3 ;
  ANTENNAPARTIALMETALAREA        0.94400         LAYER MET1 ;
  ANTENNAPARTIALMETALAREA        1.33320         LAYER MET2 ;
END Q[14]
PIN D[15]
  DIRECTION INPUT ;
  PORT
    LAYER MET1 ;
    RECT 67.540 0.000 67.950 0.180 ;
    LAYER MET2 ;
    RECT 67.540 0.000 67.950 0.180 ;
    LAYER MET3 ;
    RECT 67.540 0.000 67.950 0.180 ;
  END
  ANTENNADIFFAREA                0.38930         LAYER MET1 ;
  ANTENNADIFFAREA                0.38930         LAYER MET2 ;
  ANTENNADIFFAREA                0.38930         LAYER MET3 ;
  ANTENNAGATEAREA                0.06300         LAYER MET1 ;
  ANTENNAGATEAREA                0.06300         LAYER MET2 ;
  ANTENNAGATEAREA                0.06300         LAYER MET3 ;
  ANTENNAPARTIALMETALAREA        0.09890         LAYER MET1 ;
  ANTENNAPARTIALMETALAREA        0.10380         LAYER MET2 ;
  ANTENNAMAXAREACAR              0.72381         LAYER MET1 ;
  ANTENNAMAXAREACAR              3.54286         LAYER MET2 ;
  ANTENNAMAXAREACAR              4.71429         LAYER MET3 ;
END D[15]
PIN Q[15]
  DIRECTION OUTPUT ;
  PORT
    LAYER MET1 ;
    RECT 66.000 0.000 66.410 0.180 ;
    LAYER MET2 ;
    RECT 66.000 0.000 66.410 0.180 ;
    LAYER MET3 ;
    RECT 66.000 0.000 66.410 0.180 ;
  END
  ANTENNADIFFAREA                0.60000         LAYER MET1 ;
  ANTENNADIFFAREA                0.60000         LAYER MET2 ;
  ANTENNADIFFAREA                0.60000         LAYER MET3 ;
  ANTENNAPARTIALMETALAREA        0.94400         LAYER MET1 ;
  ANTENNAPARTIALMETALAREA        1.33320         LAYER MET2 ;
END Q[15]
PIN D[16]
  DIRECTION INPUT ;
  PORT
    LAYER MET1 ;
    RECT 71.740 0.000 72.150 0.180 ;
    LAYER MET2 ;
    RECT 71.740 0.000 72.150 0.180 ;
    LAYER MET3 ;
    RECT 71.740 0.000 72.150 0.180 ;
  END
  ANTENNADIFFAREA                0.38930         LAYER MET1 ;
  ANTENNADIFFAREA                0.38930         LAYER MET2 ;
  ANTENNADIFFAREA                0.38930         LAYER MET3 ;
  ANTENNAGATEAREA                0.06300         LAYER MET1 ;
  ANTENNAGATEAREA                0.06300         LAYER MET2 ;
  ANTENNAGATEAREA                0.06300         LAYER MET3 ;
  ANTENNAPARTIALMETALAREA        0.09890         LAYER MET1 ;
  ANTENNAPARTIALMETALAREA        0.10380         LAYER MET2 ;
  ANTENNAMAXAREACAR              0.72381         LAYER MET1 ;
  ANTENNAMAXAREACAR              3.54286         LAYER MET2 ;
  ANTENNAMAXAREACAR              4.71429         LAYER MET3 ;
END D[16]
PIN D[17]
  DIRECTION INPUT ;
  PORT
    LAYER MET1 ;
    RECT 75.940 0.000 76.350 0.180 ;
    LAYER MET2 ;
    RECT 75.940 0.000 76.350 0.180 ;
    LAYER MET3 ;
    RECT 75.940 0.000 76.350 0.180 ;
  END
  ANTENNADIFFAREA                0.38930         LAYER MET1 ;
  ANTENNADIFFAREA                0.38930         LAYER MET2 ;
  ANTENNADIFFAREA                0.38930         LAYER MET3 ;
  ANTENNAGATEAREA                0.06300         LAYER MET1 ;
  ANTENNAGATEAREA                0.06300         LAYER MET2 ;
  ANTENNAGATEAREA                0.06300         LAYER MET3 ;
  ANTENNAPARTIALMETALAREA        0.09890         LAYER MET1 ;
  ANTENNAPARTIALMETALAREA        0.10380         LAYER MET2 ;
  ANTENNAMAXAREACAR              0.72381         LAYER MET1 ;
  ANTENNAMAXAREACAR              3.54286         LAYER MET2 ;
  ANTENNAMAXAREACAR              4.71429         LAYER MET3 ;
END D[17]
PIN Q[17]
  DIRECTION OUTPUT ;
  PORT
    LAYER MET1 ;
    RECT 74.400 0.000 74.810 0.180 ;
    LAYER MET2 ;
    RECT 74.400 0.000 74.810 0.180 ;
    LAYER MET3 ;
    RECT 74.400 0.000 74.810 0.180 ;
  END
  ANTENNADIFFAREA                0.60000         LAYER MET1 ;
  ANTENNADIFFAREA                0.60000         LAYER MET2 ;
  ANTENNADIFFAREA                0.60000         LAYER MET3 ;
  ANTENNAPARTIALMETALAREA        0.94400         LAYER MET1 ;
  ANTENNAPARTIALMETALAREA        1.33320         LAYER MET2 ;
END Q[17]
PIN D[18]
  DIRECTION INPUT ;
  PORT
    LAYER MET1 ;
    RECT 80.140 0.000 80.550 0.180 ;
    LAYER MET2 ;
    RECT 80.140 0.000 80.550 0.180 ;
    LAYER MET3 ;
    RECT 80.140 0.000 80.550 0.180 ;
  END
  ANTENNADIFFAREA                0.38930         LAYER MET1 ;
  ANTENNADIFFAREA                0.38930         LAYER MET2 ;
  ANTENNADIFFAREA                0.38930         LAYER MET3 ;
  ANTENNAGATEAREA                0.06300         LAYER MET1 ;
  ANTENNAGATEAREA                0.06300         LAYER MET2 ;
  ANTENNAGATEAREA                0.06300         LAYER MET3 ;
  ANTENNAPARTIALMETALAREA        0.09890         LAYER MET1 ;
  ANTENNAPARTIALMETALAREA        0.10380         LAYER MET2 ;
  ANTENNAMAXAREACAR              0.72381         LAYER MET1 ;
  ANTENNAMAXAREACAR              3.54286         LAYER MET2 ;
  ANTENNAMAXAREACAR              4.71429         LAYER MET3 ;
END D[18]
PIN Q[18]
  DIRECTION OUTPUT ;
  PORT
    LAYER MET1 ;
    RECT 78.600 0.000 79.010 0.180 ;
    LAYER MET2 ;
    RECT 78.600 0.000 79.010 0.180 ;
    LAYER MET3 ;
    RECT 78.600 0.000 79.010 0.180 ;
  END
  ANTENNADIFFAREA                0.60000         LAYER MET1 ;
  ANTENNADIFFAREA                0.60000         LAYER MET2 ;
  ANTENNADIFFAREA                0.60000         LAYER MET3 ;
  ANTENNAPARTIALMETALAREA        0.94400         LAYER MET1 ;
  ANTENNAPARTIALMETALAREA        1.33320         LAYER MET2 ;
END Q[18]
PIN D[19]
  DIRECTION INPUT ;
  PORT
    LAYER MET1 ;
    RECT 84.340 0.000 84.750 0.180 ;
    LAYER MET2 ;
    RECT 84.340 0.000 84.750 0.180 ;
    LAYER MET3 ;
    RECT 84.340 0.000 84.750 0.180 ;
  END
  ANTENNADIFFAREA                0.38930         LAYER MET1 ;
  ANTENNADIFFAREA                0.38930         LAYER MET2 ;
  ANTENNADIFFAREA                0.38930         LAYER MET3 ;
  ANTENNAGATEAREA                0.06300         LAYER MET1 ;
  ANTENNAGATEAREA                0.06300         LAYER MET2 ;
  ANTENNAGATEAREA                0.06300         LAYER MET3 ;
  ANTENNAPARTIALMETALAREA        0.09890         LAYER MET1 ;
  ANTENNAPARTIALMETALAREA        0.10380         LAYER MET2 ;
  ANTENNAMAXAREACAR              0.72381         LAYER MET1 ;
  ANTENNAMAXAREACAR              3.54286         LAYER MET2 ;
  ANTENNAMAXAREACAR              4.71429         LAYER MET3 ;
END D[19]
PIN Q[19]
  DIRECTION OUTPUT ;
  PORT
    LAYER MET1 ;
    RECT 82.800 0.000 83.210 0.180 ;
    LAYER MET2 ;
    RECT 82.800 0.000 83.210 0.180 ;
    LAYER MET3 ;
    RECT 82.800 0.000 83.210 0.180 ;
  END
  ANTENNADIFFAREA                0.60000         LAYER MET1 ;
  ANTENNADIFFAREA                0.60000         LAYER MET2 ;
  ANTENNADIFFAREA                0.60000         LAYER MET3 ;
  ANTENNAPARTIALMETALAREA        0.94400         LAYER MET1 ;
  ANTENNAPARTIALMETALAREA        1.33320         LAYER MET2 ;
END Q[19]
PIN D[20]
  DIRECTION INPUT ;
  PORT
    LAYER MET1 ;
    RECT 88.540 0.000 88.950 0.180 ;
    LAYER MET2 ;
    RECT 88.540 0.000 88.950 0.180 ;
    LAYER MET3 ;
    RECT 88.540 0.000 88.950 0.180 ;
  END
  ANTENNADIFFAREA                0.38930         LAYER MET1 ;
  ANTENNADIFFAREA                0.38930         LAYER MET2 ;
  ANTENNADIFFAREA                0.38930         LAYER MET3 ;
  ANTENNAGATEAREA                0.06300         LAYER MET1 ;
  ANTENNAGATEAREA                0.06300         LAYER MET2 ;
  ANTENNAGATEAREA                0.06300         LAYER MET3 ;
  ANTENNAPARTIALMETALAREA        0.09890         LAYER MET1 ;
  ANTENNAPARTIALMETALAREA        0.10380         LAYER MET2 ;
  ANTENNAMAXAREACAR              0.72381         LAYER MET1 ;
  ANTENNAMAXAREACAR              3.54286         LAYER MET2 ;
  ANTENNAMAXAREACAR              4.71429         LAYER MET3 ;
END D[20]
PIN Q[20]
  DIRECTION OUTPUT ;
  PORT
    LAYER MET1 ;
    RECT 87.000 0.000 87.410 0.180 ;
    LAYER MET2 ;
    RECT 87.000 0.000 87.410 0.180 ;
    LAYER MET3 ;
    RECT 87.000 0.000 87.410 0.180 ;
  END
  ANTENNADIFFAREA                0.60000         LAYER MET1 ;
  ANTENNADIFFAREA                0.60000         LAYER MET2 ;
  ANTENNADIFFAREA                0.60000         LAYER MET3 ;
  ANTENNAPARTIALMETALAREA        0.94400         LAYER MET1 ;
  ANTENNAPARTIALMETALAREA        1.33320         LAYER MET2 ;
END Q[20]
PIN D[21]
  DIRECTION INPUT ;
  PORT
    LAYER MET1 ;
    RECT 92.740 0.000 93.150 0.180 ;
    LAYER MET2 ;
    RECT 92.740 0.000 93.150 0.180 ;
    LAYER MET3 ;
    RECT 92.740 0.000 93.150 0.180 ;
  END
  ANTENNADIFFAREA                0.38930         LAYER MET1 ;
  ANTENNADIFFAREA                0.38930         LAYER MET2 ;
  ANTENNADIFFAREA                0.38930         LAYER MET3 ;
  ANTENNAGATEAREA                0.06300         LAYER MET1 ;
  ANTENNAGATEAREA                0.06300         LAYER MET2 ;
  ANTENNAGATEAREA                0.06300         LAYER MET3 ;
  ANTENNAPARTIALMETALAREA        0.09890         LAYER MET1 ;
  ANTENNAPARTIALMETALAREA        0.10380         LAYER MET2 ;
  ANTENNAMAXAREACAR              0.72381         LAYER MET1 ;
  ANTENNAMAXAREACAR              3.54286         LAYER MET2 ;
  ANTENNAMAXAREACAR              4.71429         LAYER MET3 ;
END D[21]
PIN Q[21]
  DIRECTION OUTPUT ;
  PORT
    LAYER MET1 ;
    RECT 91.200 0.000 91.610 0.180 ;
    LAYER MET2 ;
    RECT 91.200 0.000 91.610 0.180 ;
    LAYER MET3 ;
    RECT 91.200 0.000 91.610 0.180 ;
  END
  ANTENNADIFFAREA                0.60000         LAYER MET1 ;
  ANTENNADIFFAREA                0.60000         LAYER MET2 ;
  ANTENNADIFFAREA                0.60000         LAYER MET3 ;
  ANTENNAPARTIALMETALAREA        0.94400         LAYER MET1 ;
  ANTENNAPARTIALMETALAREA        1.33320         LAYER MET2 ;
END Q[21]
PIN D[22]
  DIRECTION INPUT ;
  PORT
    LAYER MET1 ;
    RECT 96.940 0.000 97.350 0.180 ;
    LAYER MET2 ;
    RECT 96.940 0.000 97.350 0.180 ;
    LAYER MET3 ;
    RECT 96.940 0.000 97.350 0.180 ;
  END
  ANTENNADIFFAREA                0.38930         LAYER MET1 ;
  ANTENNADIFFAREA                0.38930         LAYER MET2 ;
  ANTENNADIFFAREA                0.38930         LAYER MET3 ;
  ANTENNAGATEAREA                0.06300         LAYER MET1 ;
  ANTENNAGATEAREA                0.06300         LAYER MET2 ;
  ANTENNAGATEAREA                0.06300         LAYER MET3 ;
  ANTENNAPARTIALMETALAREA        0.09890         LAYER MET1 ;
  ANTENNAPARTIALMETALAREA        0.10380         LAYER MET2 ;
  ANTENNAMAXAREACAR              0.72381         LAYER MET1 ;
  ANTENNAMAXAREACAR              3.54286         LAYER MET2 ;
  ANTENNAMAXAREACAR              4.71429         LAYER MET3 ;
END D[22]
PIN Q[22]
  DIRECTION OUTPUT ;
  PORT
    LAYER MET1 ;
    RECT 95.400 0.000 95.810 0.180 ;
    LAYER MET2 ;
    RECT 95.400 0.000 95.810 0.180 ;
    LAYER MET3 ;
    RECT 95.400 0.000 95.810 0.180 ;
  END
  ANTENNADIFFAREA                0.60000         LAYER MET1 ;
  ANTENNADIFFAREA                0.60000         LAYER MET2 ;
  ANTENNADIFFAREA                0.60000         LAYER MET3 ;
  ANTENNAPARTIALMETALAREA        0.94400         LAYER MET1 ;
  ANTENNAPARTIALMETALAREA        1.33320         LAYER MET2 ;
END Q[22]
PIN D[23]
  DIRECTION INPUT ;
  PORT
    LAYER MET1 ;
    RECT 101.140 0.000 101.550 0.180 ;
    LAYER MET2 ;
    RECT 101.140 0.000 101.550 0.180 ;
    LAYER MET3 ;
    RECT 101.140 0.000 101.550 0.180 ;
  END
  ANTENNADIFFAREA                0.38930         LAYER MET1 ;
  ANTENNADIFFAREA                0.38930         LAYER MET2 ;
  ANTENNADIFFAREA                0.38930         LAYER MET3 ;
  ANTENNAGATEAREA                0.06300         LAYER MET1 ;
  ANTENNAGATEAREA                0.06300         LAYER MET2 ;
  ANTENNAGATEAREA                0.06300         LAYER MET3 ;
  ANTENNAPARTIALMETALAREA        0.09890         LAYER MET1 ;
  ANTENNAPARTIALMETALAREA        0.10380         LAYER MET2 ;
  ANTENNAMAXAREACAR              0.72381         LAYER MET1 ;
  ANTENNAMAXAREACAR              3.54286         LAYER MET2 ;
  ANTENNAMAXAREACAR              4.71429         LAYER MET3 ;
END D[23]
PIN Q[23]
  DIRECTION OUTPUT ;
  PORT
    LAYER MET1 ;
    RECT 99.600 0.000 100.010 0.180 ;
    LAYER MET2 ;
    RECT 99.600 0.000 100.010 0.180 ;
    LAYER MET3 ;
    RECT 99.600 0.000 100.010 0.180 ;
  END
  ANTENNADIFFAREA                0.60000         LAYER MET1 ;
  ANTENNADIFFAREA                0.60000         LAYER MET2 ;
  ANTENNADIFFAREA                0.60000         LAYER MET3 ;
  ANTENNAPARTIALMETALAREA        0.94400         LAYER MET1 ;
  ANTENNAPARTIALMETALAREA        1.33320         LAYER MET2 ;
END Q[23]
PIN D[24]
  DIRECTION INPUT ;
  PORT
    LAYER MET1 ;
    RECT 105.340 0.000 105.750 0.180 ;
    LAYER MET2 ;
    RECT 105.340 0.000 105.750 0.180 ;
    LAYER MET3 ;
    RECT 105.340 0.000 105.750 0.180 ;
  END
  ANTENNADIFFAREA                0.38930         LAYER MET1 ;
  ANTENNADIFFAREA                0.38930         LAYER MET2 ;
  ANTENNADIFFAREA                0.38930         LAYER MET3 ;
  ANTENNAGATEAREA                0.06300         LAYER MET1 ;
  ANTENNAGATEAREA                0.06300         LAYER MET2 ;
  ANTENNAGATEAREA                0.06300         LAYER MET3 ;
  ANTENNAPARTIALMETALAREA        0.09890         LAYER MET1 ;
  ANTENNAPARTIALMETALAREA        0.10380         LAYER MET2 ;
  ANTENNAMAXAREACAR              0.72381         LAYER MET1 ;
  ANTENNAMAXAREACAR              3.54286         LAYER MET2 ;
  ANTENNAMAXAREACAR              4.71429         LAYER MET3 ;
END D[24]
PIN Q[24]
  DIRECTION OUTPUT ;
  PORT
    LAYER MET1 ;
    RECT 103.800 0.000 104.210 0.180 ;
    LAYER MET2 ;
    RECT 103.800 0.000 104.210 0.180 ;
    LAYER MET3 ;
    RECT 103.800 0.000 104.210 0.180 ;
  END
  ANTENNADIFFAREA                0.60000         LAYER MET1 ;
  ANTENNADIFFAREA                0.60000         LAYER MET2 ;
  ANTENNADIFFAREA                0.60000         LAYER MET3 ;
  ANTENNAPARTIALMETALAREA        0.94400         LAYER MET1 ;
  ANTENNAPARTIALMETALAREA        1.33320         LAYER MET2 ;
END Q[24]
PIN D[25]
  DIRECTION INPUT ;
  PORT
    LAYER MET1 ;
    RECT 109.540 0.000 109.950 0.180 ;
    LAYER MET2 ;
    RECT 109.540 0.000 109.950 0.180 ;
    LAYER MET3 ;
    RECT 109.540 0.000 109.950 0.180 ;
  END
  ANTENNADIFFAREA                0.38930         LAYER MET1 ;
  ANTENNADIFFAREA                0.38930         LAYER MET2 ;
  ANTENNADIFFAREA                0.38930         LAYER MET3 ;
  ANTENNAGATEAREA                0.06300         LAYER MET1 ;
  ANTENNAGATEAREA                0.06300         LAYER MET2 ;
  ANTENNAGATEAREA                0.06300         LAYER MET3 ;
  ANTENNAPARTIALMETALAREA        0.09890         LAYER MET1 ;
  ANTENNAPARTIALMETALAREA        0.10380         LAYER MET2 ;
  ANTENNAMAXAREACAR              0.72381         LAYER MET1 ;
  ANTENNAMAXAREACAR              3.54286         LAYER MET2 ;
  ANTENNAMAXAREACAR              4.71429         LAYER MET3 ;
END D[25]
PIN Q[25]
  DIRECTION OUTPUT ;
  PORT
    LAYER MET1 ;
    RECT 108.000 0.000 108.410 0.180 ;
    LAYER MET2 ;
    RECT 108.000 0.000 108.410 0.180 ;
    LAYER MET3 ;
    RECT 108.000 0.000 108.410 0.180 ;
  END
  ANTENNADIFFAREA                0.60000         LAYER MET1 ;
  ANTENNADIFFAREA                0.60000         LAYER MET2 ;
  ANTENNADIFFAREA                0.60000         LAYER MET3 ;
  ANTENNAPARTIALMETALAREA        0.94400         LAYER MET1 ;
  ANTENNAPARTIALMETALAREA        1.33320         LAYER MET2 ;
END Q[25]
PIN D[26]
  DIRECTION INPUT ;
  PORT
    LAYER MET1 ;
    RECT 113.740 0.000 114.150 0.180 ;
    LAYER MET2 ;
    RECT 113.740 0.000 114.150 0.180 ;
    LAYER MET3 ;
    RECT 113.740 0.000 114.150 0.180 ;
  END
  ANTENNADIFFAREA                0.38930         LAYER MET1 ;
  ANTENNADIFFAREA                0.38930         LAYER MET2 ;
  ANTENNADIFFAREA                0.38930         LAYER MET3 ;
  ANTENNAGATEAREA                0.06300         LAYER MET1 ;
  ANTENNAGATEAREA                0.06300         LAYER MET2 ;
  ANTENNAGATEAREA                0.06300         LAYER MET3 ;
  ANTENNAPARTIALMETALAREA        0.09890         LAYER MET1 ;
  ANTENNAPARTIALMETALAREA        0.10380         LAYER MET2 ;
  ANTENNAMAXAREACAR              0.72381         LAYER MET1 ;
  ANTENNAMAXAREACAR              3.54286         LAYER MET2 ;
  ANTENNAMAXAREACAR              4.71429         LAYER MET3 ;
END D[26]
PIN Q[26]
  DIRECTION OUTPUT ;
  PORT
    LAYER MET1 ;
    RECT 112.200 0.000 112.610 0.180 ;
    LAYER MET2 ;
    RECT 112.200 0.000 112.610 0.180 ;
    LAYER MET3 ;
    RECT 112.200 0.000 112.610 0.180 ;
  END
  ANTENNADIFFAREA                0.60000         LAYER MET1 ;
  ANTENNADIFFAREA                0.60000         LAYER MET2 ;
  ANTENNADIFFAREA                0.60000         LAYER MET3 ;
  ANTENNAPARTIALMETALAREA        0.94400         LAYER MET1 ;
  ANTENNAPARTIALMETALAREA        1.33320         LAYER MET2 ;
END Q[26]
PIN D[27]
  DIRECTION INPUT ;
  PORT
    LAYER MET1 ;
    RECT 117.940 0.000 118.350 0.180 ;
    LAYER MET2 ;
    RECT 117.940 0.000 118.350 0.180 ;
    LAYER MET3 ;
    RECT 117.940 0.000 118.350 0.180 ;
  END
  ANTENNADIFFAREA                0.38930         LAYER MET1 ;
  ANTENNADIFFAREA                0.38930         LAYER MET2 ;
  ANTENNADIFFAREA                0.38930         LAYER MET3 ;
  ANTENNAGATEAREA                0.06300         LAYER MET1 ;
  ANTENNAGATEAREA                0.06300         LAYER MET2 ;
  ANTENNAGATEAREA                0.06300         LAYER MET3 ;
  ANTENNAPARTIALMETALAREA        0.09890         LAYER MET1 ;
  ANTENNAPARTIALMETALAREA        0.10380         LAYER MET2 ;
  ANTENNAMAXAREACAR              0.72381         LAYER MET1 ;
  ANTENNAMAXAREACAR              3.54286         LAYER MET2 ;
  ANTENNAMAXAREACAR              4.71429         LAYER MET3 ;
END D[27]
PIN Q[27]
  DIRECTION OUTPUT ;
  PORT
    LAYER MET1 ;
    RECT 116.400 0.000 116.810 0.180 ;
    LAYER MET2 ;
    RECT 116.400 0.000 116.810 0.180 ;
    LAYER MET3 ;
    RECT 116.400 0.000 116.810 0.180 ;
  END
  ANTENNADIFFAREA                0.60000         LAYER MET1 ;
  ANTENNADIFFAREA                0.60000         LAYER MET2 ;
  ANTENNADIFFAREA                0.60000         LAYER MET3 ;
  ANTENNAPARTIALMETALAREA        0.94400         LAYER MET1 ;
  ANTENNAPARTIALMETALAREA        1.33320         LAYER MET2 ;
END Q[27]
PIN D[28]
  DIRECTION INPUT ;
  PORT
    LAYER MET1 ;
    RECT 122.140 0.000 122.550 0.180 ;
    LAYER MET2 ;
    RECT 122.140 0.000 122.550 0.180 ;
    LAYER MET3 ;
    RECT 122.140 0.000 122.550 0.180 ;
  END
  ANTENNADIFFAREA                0.38930         LAYER MET1 ;
  ANTENNADIFFAREA                0.38930         LAYER MET2 ;
  ANTENNADIFFAREA                0.38930         LAYER MET3 ;
  ANTENNAGATEAREA                0.06300         LAYER MET1 ;
  ANTENNAGATEAREA                0.06300         LAYER MET2 ;
  ANTENNAGATEAREA                0.06300         LAYER MET3 ;
  ANTENNAPARTIALMETALAREA        0.09890         LAYER MET1 ;
  ANTENNAPARTIALMETALAREA        0.10380         LAYER MET2 ;
  ANTENNAMAXAREACAR              0.72381         LAYER MET1 ;
  ANTENNAMAXAREACAR              3.54286         LAYER MET2 ;
  ANTENNAMAXAREACAR              4.71429         LAYER MET3 ;
END D[28]
PIN Q[28]
  DIRECTION OUTPUT ;
  PORT
    LAYER MET1 ;
    RECT 120.600 0.000 121.010 0.180 ;
    LAYER MET2 ;
    RECT 120.600 0.000 121.010 0.180 ;
    LAYER MET3 ;
    RECT 120.600 0.000 121.010 0.180 ;
  END
  ANTENNADIFFAREA                0.60000         LAYER MET1 ;
  ANTENNADIFFAREA                0.60000         LAYER MET2 ;
  ANTENNADIFFAREA                0.60000         LAYER MET3 ;
  ANTENNAPARTIALMETALAREA        0.94400         LAYER MET1 ;
  ANTENNAPARTIALMETALAREA        1.33320         LAYER MET2 ;
END Q[28]
PIN D[29]
  DIRECTION INPUT ;
  PORT
    LAYER MET1 ;
    RECT 126.340 0.000 126.750 0.180 ;
    LAYER MET2 ;
    RECT 126.340 0.000 126.750 0.180 ;
    LAYER MET3 ;
    RECT 126.340 0.000 126.750 0.180 ;
  END
  ANTENNADIFFAREA                0.38930         LAYER MET1 ;
  ANTENNADIFFAREA                0.38930         LAYER MET2 ;
  ANTENNADIFFAREA                0.38930         LAYER MET3 ;
  ANTENNAGATEAREA                0.06300         LAYER MET1 ;
  ANTENNAGATEAREA                0.06300         LAYER MET2 ;
  ANTENNAGATEAREA                0.06300         LAYER MET3 ;
  ANTENNAPARTIALMETALAREA        0.09890         LAYER MET1 ;
  ANTENNAPARTIALMETALAREA        0.10380         LAYER MET2 ;
  ANTENNAMAXAREACAR              0.72381         LAYER MET1 ;
  ANTENNAMAXAREACAR              3.54286         LAYER MET2 ;
  ANTENNAMAXAREACAR              4.71429         LAYER MET3 ;
END D[29]
PIN Q[29]
  DIRECTION OUTPUT ;
  PORT
    LAYER MET1 ;
    RECT 124.800 0.000 125.210 0.180 ;
    LAYER MET2 ;
    RECT 124.800 0.000 125.210 0.180 ;
    LAYER MET3 ;
    RECT 124.800 0.000 125.210 0.180 ;
  END
  ANTENNADIFFAREA                0.60000         LAYER MET1 ;
  ANTENNADIFFAREA                0.60000         LAYER MET2 ;
  ANTENNADIFFAREA                0.60000         LAYER MET3 ;
  ANTENNAPARTIALMETALAREA        0.94400         LAYER MET1 ;
  ANTENNAPARTIALMETALAREA        1.33320         LAYER MET2 ;
END Q[29]
PIN D[30]
  DIRECTION INPUT ;
  PORT
    LAYER MET1 ;
    RECT 130.540 0.000 130.950 0.180 ;
    LAYER MET2 ;
    RECT 130.540 0.000 130.950 0.180 ;
    LAYER MET3 ;
    RECT 130.540 0.000 130.950 0.180 ;
  END
  ANTENNADIFFAREA                0.38930         LAYER MET1 ;
  ANTENNADIFFAREA                0.38930         LAYER MET2 ;
  ANTENNADIFFAREA                0.38930         LAYER MET3 ;
  ANTENNAGATEAREA                0.06300         LAYER MET1 ;
  ANTENNAGATEAREA                0.06300         LAYER MET2 ;
  ANTENNAGATEAREA                0.06300         LAYER MET3 ;
  ANTENNAPARTIALMETALAREA        0.09890         LAYER MET1 ;
  ANTENNAPARTIALMETALAREA        0.10380         LAYER MET2 ;
  ANTENNAMAXAREACAR              0.72381         LAYER MET1 ;
  ANTENNAMAXAREACAR              3.54286         LAYER MET2 ;
  ANTENNAMAXAREACAR              4.71429         LAYER MET3 ;
END D[30]
PIN Q[30]
  DIRECTION OUTPUT ;
  PORT
    LAYER MET1 ;
    RECT 129.000 0.000 129.410 0.180 ;
    LAYER MET2 ;
    RECT 129.000 0.000 129.410 0.180 ;
    LAYER MET3 ;
    RECT 129.000 0.000 129.410 0.180 ;
  END
  ANTENNADIFFAREA                0.60000         LAYER MET1 ;
  ANTENNADIFFAREA                0.60000         LAYER MET2 ;
  ANTENNADIFFAREA                0.60000         LAYER MET3 ;
  ANTENNAPARTIALMETALAREA        0.94400         LAYER MET1 ;
  ANTENNAPARTIALMETALAREA        1.33320         LAYER MET2 ;
END Q[30]
PIN D[31]
  DIRECTION INPUT ;
  PORT
    LAYER MET1 ;
    RECT 134.740 0.000 135.150 0.180 ;
    LAYER MET2 ;
    RECT 134.740 0.000 135.150 0.180 ;
    LAYER MET3 ;
    RECT 134.740 0.000 135.150 0.180 ;
  END
  ANTENNADIFFAREA                0.38930         LAYER MET1 ;
  ANTENNADIFFAREA                0.38930         LAYER MET2 ;
  ANTENNADIFFAREA                0.38930         LAYER MET3 ;
  ANTENNAGATEAREA                0.06300         LAYER MET1 ;
  ANTENNAGATEAREA                0.06300         LAYER MET2 ;
  ANTENNAGATEAREA                0.06300         LAYER MET3 ;
  ANTENNAPARTIALMETALAREA        0.09890         LAYER MET1 ;
  ANTENNAPARTIALMETALAREA        0.10380         LAYER MET2 ;
  ANTENNAMAXAREACAR              0.72381         LAYER MET1 ;
  ANTENNAMAXAREACAR              3.54286         LAYER MET2 ;
  ANTENNAMAXAREACAR              4.71429         LAYER MET3 ;
END D[31]
PIN Q[31]
  DIRECTION OUTPUT ;
  PORT
    LAYER MET1 ;
    RECT 133.200 0.000 133.610 0.180 ;
    LAYER MET2 ;
    RECT 133.200 0.000 133.610 0.180 ;
    LAYER MET3 ;
    RECT 133.200 0.000 133.610 0.180 ;
  END
  ANTENNADIFFAREA                0.60000         LAYER MET1 ;
  ANTENNADIFFAREA                0.60000         LAYER MET2 ;
  ANTENNADIFFAREA                0.60000         LAYER MET3 ;
  ANTENNAPARTIALMETALAREA        0.94400         LAYER MET1 ;
  ANTENNAPARTIALMETALAREA        1.33320         LAYER MET2 ;
END Q[31]
PIN D[32]
  DIRECTION INPUT ;
  PORT
    LAYER MET1 ;
    RECT 138.940 0.000 139.350 0.180 ;
    LAYER MET2 ;
    RECT 138.940 0.000 139.350 0.180 ;
    LAYER MET3 ;
    RECT 138.940 0.000 139.350 0.180 ;
  END
  ANTENNADIFFAREA                0.38930         LAYER MET1 ;
  ANTENNADIFFAREA                0.38930         LAYER MET2 ;
  ANTENNADIFFAREA                0.38930         LAYER MET3 ;
  ANTENNAGATEAREA                0.06300         LAYER MET1 ;
  ANTENNAGATEAREA                0.06300         LAYER MET2 ;
  ANTENNAGATEAREA                0.06300         LAYER MET3 ;
  ANTENNAPARTIALMETALAREA        0.09890         LAYER MET1 ;
  ANTENNAPARTIALMETALAREA        0.10380         LAYER MET2 ;
  ANTENNAMAXAREACAR              0.72381         LAYER MET1 ;
  ANTENNAMAXAREACAR              3.54286         LAYER MET2 ;
  ANTENNAMAXAREACAR              4.71429         LAYER MET3 ;
END D[32]
PIN Q[32]
  DIRECTION OUTPUT ;
  PORT
    LAYER MET1 ;
    RECT 137.400 0.000 137.810 0.180 ;
    LAYER MET2 ;
    RECT 137.400 0.000 137.810 0.180 ;
    LAYER MET3 ;
    RECT 137.400 0.000 137.810 0.180 ;
  END
  ANTENNADIFFAREA                0.60000         LAYER MET1 ;
  ANTENNADIFFAREA                0.60000         LAYER MET2 ;
  ANTENNADIFFAREA                0.60000         LAYER MET3 ;
  ANTENNAPARTIALMETALAREA        0.94400         LAYER MET1 ;
  ANTENNAPARTIALMETALAREA        1.33320         LAYER MET2 ;
END Q[32]
PIN GWEB
  DIRECTION INPUT ;
  PORT
    LAYER MET1 ;
    RECT 279.675 0.000 280.085 0.180 ;
    LAYER MET2 ;
    RECT 279.675 0.000 280.085 0.180 ;
    LAYER MET3 ;
    RECT 279.675 0.000 280.085 0.180 ;
  END
  ANTENNADIFFAREA                0.47330         LAYER MET1 ;
  ANTENNADIFFAREA                0.47330         LAYER MET2 ;
  ANTENNADIFFAREA                0.47330         LAYER MET3 ;
  ANTENNAGATEAREA                0.06300         LAYER MET1 ;
  ANTENNAGATEAREA                0.06300         LAYER MET2 ;
  ANTENNAGATEAREA                0.06300         LAYER MET3 ;
  ANTENNAPARTIALMETALAREA        0.13280         LAYER MET1 ;
  ANTENNAPARTIALMETALAREA        0.98400         LAYER MET2 ;
  ANTENNAMAXAREACAR              1.26190         LAYER MET1 ;
  ANTENNAMAXAREACAR              18.05238        LAYER MET2 ;
  ANTENNAMAXAREACAR              19.22381        LAYER MET3 ;
END GWEB
PIN MARE
  DIRECTION INPUT ;
  PORT
    LAYER MET1 ;
    RECT 275.080 0.000 275.490 0.180 ;
    LAYER MET2 ;
    RECT 275.080 0.000 275.490 0.180 ;
    LAYER MET3 ;
    RECT 275.080 0.000 275.490 0.180 ;
  END
  ANTENNADIFFAREA                0.27730         LAYER MET1 ;
  ANTENNADIFFAREA                0.27730         LAYER MET2 ;
  ANTENNADIFFAREA                0.27730         LAYER MET3 ;
  ANTENNAGATEAREA                0.04200         LAYER MET1 ;
  ANTENNAGATEAREA                0.04200         LAYER MET2 ;
  ANTENNAGATEAREA                0.04200         LAYER MET3 ;
  ANTENNAPARTIALMETALAREA        0.11830         LAYER MET1 ;
  ANTENNAPARTIALMETALAREA        1.73460         LAYER MET2 ;
  ANTENNAPARTIALMETALAREA        0.36060         LAYER MET3 ;
  ANTENNAMAXAREACAR              1.54762         LAYER MET1 ;
  ANTENNAMAXAREACAR              6.99048         LAYER MET2 ;
  ANTENNAMAXAREACAR              15.57619        LAYER MET3 ;
END MARE
PIN D[33]
  DIRECTION INPUT ;
  PORT
    LAYER MET1 ;
    RECT 143.140 0.000 143.550 0.180 ;
    LAYER MET2 ;
    RECT 143.140 0.000 143.550 0.180 ;
    LAYER MET3 ;
    RECT 143.140 0.000 143.550 0.180 ;
  END
  ANTENNADIFFAREA                0.38930         LAYER MET1 ;
  ANTENNADIFFAREA                0.38930         LAYER MET2 ;
  ANTENNADIFFAREA                0.38930         LAYER MET3 ;
  ANTENNAGATEAREA                0.06300         LAYER MET1 ;
  ANTENNAGATEAREA                0.06300         LAYER MET2 ;
  ANTENNAGATEAREA                0.06300         LAYER MET3 ;
  ANTENNAPARTIALMETALAREA        0.09890         LAYER MET1 ;
  ANTENNAPARTIALMETALAREA        0.10380         LAYER MET2 ;
  ANTENNAMAXAREACAR              0.72381         LAYER MET1 ;
  ANTENNAMAXAREACAR              3.54286         LAYER MET2 ;
  ANTENNAMAXAREACAR              4.71429         LAYER MET3 ;
END D[33]
PIN Q[33]
  DIRECTION OUTPUT ;
  PORT
    LAYER MET1 ;
    RECT 141.600 0.000 142.010 0.180 ;
    LAYER MET2 ;
    RECT 141.600 0.000 142.010 0.180 ;
    LAYER MET3 ;
    RECT 141.600 0.000 142.010 0.180 ;
  END
  ANTENNADIFFAREA                0.60000         LAYER MET1 ;
  ANTENNADIFFAREA                0.60000         LAYER MET2 ;
  ANTENNADIFFAREA                0.60000         LAYER MET3 ;
  ANTENNAPARTIALMETALAREA        0.94400         LAYER MET1 ;
  ANTENNAPARTIALMETALAREA        1.33320         LAYER MET2 ;
END Q[33]
PIN D[34]
  DIRECTION INPUT ;
  PORT
    LAYER MET1 ;
    RECT 147.340 0.000 147.750 0.180 ;
    LAYER MET2 ;
    RECT 147.340 0.000 147.750 0.180 ;
    LAYER MET3 ;
    RECT 147.340 0.000 147.750 0.180 ;
  END
  ANTENNADIFFAREA                0.38930         LAYER MET1 ;
  ANTENNADIFFAREA                0.38930         LAYER MET2 ;
  ANTENNADIFFAREA                0.38930         LAYER MET3 ;
  ANTENNAGATEAREA                0.06300         LAYER MET1 ;
  ANTENNAGATEAREA                0.06300         LAYER MET2 ;
  ANTENNAGATEAREA                0.06300         LAYER MET3 ;
  ANTENNAPARTIALMETALAREA        0.09890         LAYER MET1 ;
  ANTENNAPARTIALMETALAREA        0.10380         LAYER MET2 ;
  ANTENNAMAXAREACAR              0.72381         LAYER MET1 ;
  ANTENNAMAXAREACAR              3.54286         LAYER MET2 ;
  ANTENNAMAXAREACAR              4.71429         LAYER MET3 ;
END D[34]
PIN Q[34]
  DIRECTION OUTPUT ;
  PORT
    LAYER MET1 ;
    RECT 145.800 0.000 146.210 0.180 ;
    LAYER MET2 ;
    RECT 145.800 0.000 146.210 0.180 ;
    LAYER MET3 ;
    RECT 145.800 0.000 146.210 0.180 ;
  END
  ANTENNADIFFAREA                0.60000         LAYER MET1 ;
  ANTENNADIFFAREA                0.60000         LAYER MET2 ;
  ANTENNADIFFAREA                0.60000         LAYER MET3 ;
  ANTENNAPARTIALMETALAREA        0.94400         LAYER MET1 ;
  ANTENNAPARTIALMETALAREA        1.33320         LAYER MET2 ;
END Q[34]
PIN D[35]
  DIRECTION INPUT ;
  PORT
    LAYER MET1 ;
    RECT 151.540 0.000 151.950 0.180 ;
    LAYER MET2 ;
    RECT 151.540 0.000 151.950 0.180 ;
    LAYER MET3 ;
    RECT 151.540 0.000 151.950 0.180 ;
  END
  ANTENNADIFFAREA                0.38930         LAYER MET1 ;
  ANTENNADIFFAREA                0.38930         LAYER MET2 ;
  ANTENNADIFFAREA                0.38930         LAYER MET3 ;
  ANTENNAGATEAREA                0.06300         LAYER MET1 ;
  ANTENNAGATEAREA                0.06300         LAYER MET2 ;
  ANTENNAGATEAREA                0.06300         LAYER MET3 ;
  ANTENNAPARTIALMETALAREA        0.09890         LAYER MET1 ;
  ANTENNAPARTIALMETALAREA        0.10380         LAYER MET2 ;
  ANTENNAMAXAREACAR              0.72381         LAYER MET1 ;
  ANTENNAMAXAREACAR              3.54286         LAYER MET2 ;
  ANTENNAMAXAREACAR              4.71429         LAYER MET3 ;
END D[35]
PIN Q[35]
  DIRECTION OUTPUT ;
  PORT
    LAYER MET1 ;
    RECT 150.000 0.000 150.410 0.180 ;
    LAYER MET2 ;
    RECT 150.000 0.000 150.410 0.180 ;
    LAYER MET3 ;
    RECT 150.000 0.000 150.410 0.180 ;
  END
  ANTENNADIFFAREA                0.60000         LAYER MET1 ;
  ANTENNADIFFAREA                0.60000         LAYER MET2 ;
  ANTENNADIFFAREA                0.60000         LAYER MET3 ;
  ANTENNAPARTIALMETALAREA        0.94400         LAYER MET1 ;
  ANTENNAPARTIALMETALAREA        1.33320         LAYER MET2 ;
END Q[35]
PIN D[36]
  DIRECTION INPUT ;
  PORT
    LAYER MET1 ;
    RECT 155.740 0.000 156.150 0.180 ;
    LAYER MET2 ;
    RECT 155.740 0.000 156.150 0.180 ;
    LAYER MET3 ;
    RECT 155.740 0.000 156.150 0.180 ;
  END
  ANTENNADIFFAREA                0.38930         LAYER MET1 ;
  ANTENNADIFFAREA                0.38930         LAYER MET2 ;
  ANTENNADIFFAREA                0.38930         LAYER MET3 ;
  ANTENNAGATEAREA                0.06300         LAYER MET1 ;
  ANTENNAGATEAREA                0.06300         LAYER MET2 ;
  ANTENNAGATEAREA                0.06300         LAYER MET3 ;
  ANTENNAPARTIALMETALAREA        0.09890         LAYER MET1 ;
  ANTENNAPARTIALMETALAREA        0.10380         LAYER MET2 ;
  ANTENNAMAXAREACAR              0.72381         LAYER MET1 ;
  ANTENNAMAXAREACAR              3.54286         LAYER MET2 ;
  ANTENNAMAXAREACAR              4.71429         LAYER MET3 ;
END D[36]
PIN Q[36]
  DIRECTION OUTPUT ;
  PORT
    LAYER MET1 ;
    RECT 154.200 0.000 154.610 0.180 ;
    LAYER MET2 ;
    RECT 154.200 0.000 154.610 0.180 ;
    LAYER MET3 ;
    RECT 154.200 0.000 154.610 0.180 ;
  END
  ANTENNADIFFAREA                0.60000         LAYER MET1 ;
  ANTENNADIFFAREA                0.60000         LAYER MET2 ;
  ANTENNADIFFAREA                0.60000         LAYER MET3 ;
  ANTENNAPARTIALMETALAREA        0.94400         LAYER MET1 ;
  ANTENNAPARTIALMETALAREA        1.33320         LAYER MET2 ;
END Q[36]
PIN D[37]
  DIRECTION INPUT ;
  PORT
    LAYER MET1 ;
    RECT 159.940 0.000 160.350 0.180 ;
    LAYER MET2 ;
    RECT 159.940 0.000 160.350 0.180 ;
    LAYER MET3 ;
    RECT 159.940 0.000 160.350 0.180 ;
  END
  ANTENNADIFFAREA                0.38930         LAYER MET1 ;
  ANTENNADIFFAREA                0.38930         LAYER MET2 ;
  ANTENNADIFFAREA                0.38930         LAYER MET3 ;
  ANTENNAGATEAREA                0.06300         LAYER MET1 ;
  ANTENNAGATEAREA                0.06300         LAYER MET2 ;
  ANTENNAGATEAREA                0.06300         LAYER MET3 ;
  ANTENNAPARTIALMETALAREA        0.09890         LAYER MET1 ;
  ANTENNAPARTIALMETALAREA        0.10380         LAYER MET2 ;
  ANTENNAMAXAREACAR              0.72381         LAYER MET1 ;
  ANTENNAMAXAREACAR              3.54286         LAYER MET2 ;
  ANTENNAMAXAREACAR              4.71429         LAYER MET3 ;
END D[37]
PIN Q[37]
  DIRECTION OUTPUT ;
  PORT
    LAYER MET1 ;
    RECT 158.400 0.000 158.810 0.180 ;
    LAYER MET2 ;
    RECT 158.400 0.000 158.810 0.180 ;
    LAYER MET3 ;
    RECT 158.400 0.000 158.810 0.180 ;
  END
  ANTENNADIFFAREA                0.60000         LAYER MET1 ;
  ANTENNADIFFAREA                0.60000         LAYER MET2 ;
  ANTENNADIFFAREA                0.60000         LAYER MET3 ;
  ANTENNAPARTIALMETALAREA        0.94400         LAYER MET1 ;
  ANTENNAPARTIALMETALAREA        1.33320         LAYER MET2 ;
END Q[37]
PIN D[38]
  DIRECTION INPUT ;
  PORT
    LAYER MET1 ;
    RECT 164.140 0.000 164.550 0.180 ;
    LAYER MET2 ;
    RECT 164.140 0.000 164.550 0.180 ;
    LAYER MET3 ;
    RECT 164.140 0.000 164.550 0.180 ;
  END
  ANTENNADIFFAREA                0.38930         LAYER MET1 ;
  ANTENNADIFFAREA                0.38930         LAYER MET2 ;
  ANTENNADIFFAREA                0.38930         LAYER MET3 ;
  ANTENNAGATEAREA                0.06300         LAYER MET1 ;
  ANTENNAGATEAREA                0.06300         LAYER MET2 ;
  ANTENNAGATEAREA                0.06300         LAYER MET3 ;
  ANTENNAPARTIALMETALAREA        0.09890         LAYER MET1 ;
  ANTENNAPARTIALMETALAREA        0.10380         LAYER MET2 ;
  ANTENNAMAXAREACAR              0.72381         LAYER MET1 ;
  ANTENNAMAXAREACAR              3.54286         LAYER MET2 ;
  ANTENNAMAXAREACAR              4.71429         LAYER MET3 ;
END D[38]
PIN Q[38]
  DIRECTION OUTPUT ;
  PORT
    LAYER MET1 ;
    RECT 162.600 0.000 163.010 0.180 ;
    LAYER MET2 ;
    RECT 162.600 0.000 163.010 0.180 ;
    LAYER MET3 ;
    RECT 162.600 0.000 163.010 0.180 ;
  END
  ANTENNADIFFAREA                0.60000         LAYER MET1 ;
  ANTENNADIFFAREA                0.60000         LAYER MET2 ;
  ANTENNADIFFAREA                0.60000         LAYER MET3 ;
  ANTENNAPARTIALMETALAREA        0.94400         LAYER MET1 ;
  ANTENNAPARTIALMETALAREA        1.33320         LAYER MET2 ;
END Q[38]
PIN D[39]
  DIRECTION INPUT ;
  PORT
    LAYER MET1 ;
    RECT 168.340 0.000 168.750 0.180 ;
    LAYER MET2 ;
    RECT 168.340 0.000 168.750 0.180 ;
    LAYER MET3 ;
    RECT 168.340 0.000 168.750 0.180 ;
  END
  ANTENNADIFFAREA                0.38930         LAYER MET1 ;
  ANTENNADIFFAREA                0.38930         LAYER MET2 ;
  ANTENNADIFFAREA                0.38930         LAYER MET3 ;
  ANTENNAGATEAREA                0.06300         LAYER MET1 ;
  ANTENNAGATEAREA                0.06300         LAYER MET2 ;
  ANTENNAGATEAREA                0.06300         LAYER MET3 ;
  ANTENNAPARTIALMETALAREA        0.09890         LAYER MET1 ;
  ANTENNAPARTIALMETALAREA        0.10380         LAYER MET2 ;
  ANTENNAMAXAREACAR              0.72381         LAYER MET1 ;
  ANTENNAMAXAREACAR              3.54286         LAYER MET2 ;
  ANTENNAMAXAREACAR              4.71429         LAYER MET3 ;
END D[39]
PIN Q[39]
  DIRECTION OUTPUT ;
  PORT
    LAYER MET1 ;
    RECT 166.800 0.000 167.210 0.180 ;
    LAYER MET2 ;
    RECT 166.800 0.000 167.210 0.180 ;
    LAYER MET3 ;
    RECT 166.800 0.000 167.210 0.180 ;
  END
  ANTENNADIFFAREA                0.60000         LAYER MET1 ;
  ANTENNADIFFAREA                0.60000         LAYER MET2 ;
  ANTENNADIFFAREA                0.60000         LAYER MET3 ;
  ANTENNAPARTIALMETALAREA        0.94400         LAYER MET1 ;
  ANTENNAPARTIALMETALAREA        1.33320         LAYER MET2 ;
END Q[39]
PIN D[40]
  DIRECTION INPUT ;
  PORT
    LAYER MET1 ;
    RECT 172.540 0.000 172.950 0.180 ;
    LAYER MET2 ;
    RECT 172.540 0.000 172.950 0.180 ;
    LAYER MET3 ;
    RECT 172.540 0.000 172.950 0.180 ;
  END
  ANTENNADIFFAREA                0.38930         LAYER MET1 ;
  ANTENNADIFFAREA                0.38930         LAYER MET2 ;
  ANTENNADIFFAREA                0.38930         LAYER MET3 ;
  ANTENNAGATEAREA                0.06300         LAYER MET1 ;
  ANTENNAGATEAREA                0.06300         LAYER MET2 ;
  ANTENNAGATEAREA                0.06300         LAYER MET3 ;
  ANTENNAPARTIALMETALAREA        0.09890         LAYER MET1 ;
  ANTENNAPARTIALMETALAREA        0.10380         LAYER MET2 ;
  ANTENNAMAXAREACAR              0.72381         LAYER MET1 ;
  ANTENNAMAXAREACAR              3.54286         LAYER MET2 ;
  ANTENNAMAXAREACAR              4.71429         LAYER MET3 ;
END D[40]
PIN Q[40]
  DIRECTION OUTPUT ;
  PORT
    LAYER MET1 ;
    RECT 171.000 0.000 171.410 0.180 ;
    LAYER MET2 ;
    RECT 171.000 0.000 171.410 0.180 ;
    LAYER MET3 ;
    RECT 171.000 0.000 171.410 0.180 ;
  END
  ANTENNADIFFAREA                0.60000         LAYER MET1 ;
  ANTENNADIFFAREA                0.60000         LAYER MET2 ;
  ANTENNADIFFAREA                0.60000         LAYER MET3 ;
  ANTENNAPARTIALMETALAREA        0.94400         LAYER MET1 ;
  ANTENNAPARTIALMETALAREA        1.33320         LAYER MET2 ;
END Q[40]
PIN D[41]
  DIRECTION INPUT ;
  PORT
    LAYER MET1 ;
    RECT 176.740 0.000 177.150 0.180 ;
    LAYER MET2 ;
    RECT 176.740 0.000 177.150 0.180 ;
    LAYER MET3 ;
    RECT 176.740 0.000 177.150 0.180 ;
  END
  ANTENNADIFFAREA                0.38930         LAYER MET1 ;
  ANTENNADIFFAREA                0.38930         LAYER MET2 ;
  ANTENNADIFFAREA                0.38930         LAYER MET3 ;
  ANTENNAGATEAREA                0.06300         LAYER MET1 ;
  ANTENNAGATEAREA                0.06300         LAYER MET2 ;
  ANTENNAGATEAREA                0.06300         LAYER MET3 ;
  ANTENNAPARTIALMETALAREA        0.09890         LAYER MET1 ;
  ANTENNAPARTIALMETALAREA        0.10380         LAYER MET2 ;
  ANTENNAMAXAREACAR              0.72381         LAYER MET1 ;
  ANTENNAMAXAREACAR              3.54286         LAYER MET2 ;
  ANTENNAMAXAREACAR              4.71429         LAYER MET3 ;
END D[41]
PIN Q[41]
  DIRECTION OUTPUT ;
  PORT
    LAYER MET1 ;
    RECT 175.200 0.000 175.610 0.180 ;
    LAYER MET2 ;
    RECT 175.200 0.000 175.610 0.180 ;
    LAYER MET3 ;
    RECT 175.200 0.000 175.610 0.180 ;
  END
  ANTENNADIFFAREA                0.60000         LAYER MET1 ;
  ANTENNADIFFAREA                0.60000         LAYER MET2 ;
  ANTENNADIFFAREA                0.60000         LAYER MET3 ;
  ANTENNAPARTIALMETALAREA        0.94400         LAYER MET1 ;
  ANTENNAPARTIALMETALAREA        1.33320         LAYER MET2 ;
END Q[41]
PIN D[42]
  DIRECTION INPUT ;
  PORT
    LAYER MET1 ;
    RECT 180.940 0.000 181.350 0.180 ;
    LAYER MET2 ;
    RECT 180.940 0.000 181.350 0.180 ;
    LAYER MET3 ;
    RECT 180.940 0.000 181.350 0.180 ;
  END
  ANTENNADIFFAREA                0.38930         LAYER MET1 ;
  ANTENNADIFFAREA                0.38930         LAYER MET2 ;
  ANTENNADIFFAREA                0.38930         LAYER MET3 ;
  ANTENNAGATEAREA                0.06300         LAYER MET1 ;
  ANTENNAGATEAREA                0.06300         LAYER MET2 ;
  ANTENNAGATEAREA                0.06300         LAYER MET3 ;
  ANTENNAPARTIALMETALAREA        0.09890         LAYER MET1 ;
  ANTENNAPARTIALMETALAREA        0.10380         LAYER MET2 ;
  ANTENNAMAXAREACAR              0.72381         LAYER MET1 ;
  ANTENNAMAXAREACAR              3.54286         LAYER MET2 ;
  ANTENNAMAXAREACAR              4.71429         LAYER MET3 ;
END D[42]
PIN Q[42]
  DIRECTION OUTPUT ;
  PORT
    LAYER MET1 ;
    RECT 179.400 0.000 179.810 0.180 ;
    LAYER MET2 ;
    RECT 179.400 0.000 179.810 0.180 ;
    LAYER MET3 ;
    RECT 179.400 0.000 179.810 0.180 ;
  END
  ANTENNADIFFAREA                0.60000         LAYER MET1 ;
  ANTENNADIFFAREA                0.60000         LAYER MET2 ;
  ANTENNADIFFAREA                0.60000         LAYER MET3 ;
  ANTENNAPARTIALMETALAREA        0.94400         LAYER MET1 ;
  ANTENNAPARTIALMETALAREA        1.33320         LAYER MET2 ;
END Q[42]
PIN D[43]
  DIRECTION INPUT ;
  PORT
    LAYER MET1 ;
    RECT 185.140 0.000 185.550 0.180 ;
    LAYER MET2 ;
    RECT 185.140 0.000 185.550 0.180 ;
    LAYER MET3 ;
    RECT 185.140 0.000 185.550 0.180 ;
  END
  ANTENNADIFFAREA                0.38930         LAYER MET1 ;
  ANTENNADIFFAREA                0.38930         LAYER MET2 ;
  ANTENNADIFFAREA                0.38930         LAYER MET3 ;
  ANTENNAGATEAREA                0.06300         LAYER MET1 ;
  ANTENNAGATEAREA                0.06300         LAYER MET2 ;
  ANTENNAGATEAREA                0.06300         LAYER MET3 ;
  ANTENNAPARTIALMETALAREA        0.09890         LAYER MET1 ;
  ANTENNAPARTIALMETALAREA        0.10380         LAYER MET2 ;
  ANTENNAMAXAREACAR              0.72381         LAYER MET1 ;
  ANTENNAMAXAREACAR              3.54286         LAYER MET2 ;
  ANTENNAMAXAREACAR              4.71429         LAYER MET3 ;
END D[43]
PIN Q[43]
  DIRECTION OUTPUT ;
  PORT
    LAYER MET1 ;
    RECT 183.600 0.000 184.010 0.180 ;
    LAYER MET2 ;
    RECT 183.600 0.000 184.010 0.180 ;
    LAYER MET3 ;
    RECT 183.600 0.000 184.010 0.180 ;
  END
  ANTENNADIFFAREA                0.60000         LAYER MET1 ;
  ANTENNADIFFAREA                0.60000         LAYER MET2 ;
  ANTENNADIFFAREA                0.60000         LAYER MET3 ;
  ANTENNAPARTIALMETALAREA        0.94400         LAYER MET1 ;
  ANTENNAPARTIALMETALAREA        1.33320         LAYER MET2 ;
END Q[43]
PIN D[44]
  DIRECTION INPUT ;
  PORT
    LAYER MET1 ;
    RECT 189.340 0.000 189.750 0.180 ;
    LAYER MET2 ;
    RECT 189.340 0.000 189.750 0.180 ;
    LAYER MET3 ;
    RECT 189.340 0.000 189.750 0.180 ;
  END
  ANTENNADIFFAREA                0.38930         LAYER MET1 ;
  ANTENNADIFFAREA                0.38930         LAYER MET2 ;
  ANTENNADIFFAREA                0.38930         LAYER MET3 ;
  ANTENNAGATEAREA                0.06300         LAYER MET1 ;
  ANTENNAGATEAREA                0.06300         LAYER MET2 ;
  ANTENNAGATEAREA                0.06300         LAYER MET3 ;
  ANTENNAPARTIALMETALAREA        0.09890         LAYER MET1 ;
  ANTENNAPARTIALMETALAREA        0.10380         LAYER MET2 ;
  ANTENNAMAXAREACAR              0.72381         LAYER MET1 ;
  ANTENNAMAXAREACAR              3.54286         LAYER MET2 ;
  ANTENNAMAXAREACAR              4.71429         LAYER MET3 ;
END D[44]
PIN Q[44]
  DIRECTION OUTPUT ;
  PORT
    LAYER MET1 ;
    RECT 187.800 0.000 188.210 0.180 ;
    LAYER MET2 ;
    RECT 187.800 0.000 188.210 0.180 ;
    LAYER MET3 ;
    RECT 187.800 0.000 188.210 0.180 ;
  END
  ANTENNADIFFAREA                0.60000         LAYER MET1 ;
  ANTENNADIFFAREA                0.60000         LAYER MET2 ;
  ANTENNADIFFAREA                0.60000         LAYER MET3 ;
  ANTENNAPARTIALMETALAREA        0.94400         LAYER MET1 ;
  ANTENNAPARTIALMETALAREA        1.33320         LAYER MET2 ;
END Q[44]
PIN D[45]
  DIRECTION INPUT ;
  PORT
    LAYER MET1 ;
    RECT 193.540 0.000 193.950 0.180 ;
    LAYER MET2 ;
    RECT 193.540 0.000 193.950 0.180 ;
    LAYER MET3 ;
    RECT 193.540 0.000 193.950 0.180 ;
  END
  ANTENNADIFFAREA                0.38930         LAYER MET1 ;
  ANTENNADIFFAREA                0.38930         LAYER MET2 ;
  ANTENNADIFFAREA                0.38930         LAYER MET3 ;
  ANTENNAGATEAREA                0.06300         LAYER MET1 ;
  ANTENNAGATEAREA                0.06300         LAYER MET2 ;
  ANTENNAGATEAREA                0.06300         LAYER MET3 ;
  ANTENNAPARTIALMETALAREA        0.09890         LAYER MET1 ;
  ANTENNAPARTIALMETALAREA        0.10380         LAYER MET2 ;
  ANTENNAMAXAREACAR              0.72381         LAYER MET1 ;
  ANTENNAMAXAREACAR              3.54286         LAYER MET2 ;
  ANTENNAMAXAREACAR              4.71429         LAYER MET3 ;
END D[45]
PIN Q[45]
  DIRECTION OUTPUT ;
  PORT
    LAYER MET1 ;
    RECT 192.000 0.000 192.410 0.180 ;
    LAYER MET2 ;
    RECT 192.000 0.000 192.410 0.180 ;
    LAYER MET3 ;
    RECT 192.000 0.000 192.410 0.180 ;
  END
  ANTENNADIFFAREA                0.60000         LAYER MET1 ;
  ANTENNADIFFAREA                0.60000         LAYER MET2 ;
  ANTENNADIFFAREA                0.60000         LAYER MET3 ;
  ANTENNAPARTIALMETALAREA        0.94400         LAYER MET1 ;
  ANTENNAPARTIALMETALAREA        1.33320         LAYER MET2 ;
END Q[45]
PIN D[46]
  DIRECTION INPUT ;
  PORT
    LAYER MET1 ;
    RECT 197.740 0.000 198.150 0.180 ;
    LAYER MET2 ;
    RECT 197.740 0.000 198.150 0.180 ;
    LAYER MET3 ;
    RECT 197.740 0.000 198.150 0.180 ;
  END
  ANTENNADIFFAREA                0.38930         LAYER MET1 ;
  ANTENNADIFFAREA                0.38930         LAYER MET2 ;
  ANTENNADIFFAREA                0.38930         LAYER MET3 ;
  ANTENNAGATEAREA                0.06300         LAYER MET1 ;
  ANTENNAGATEAREA                0.06300         LAYER MET2 ;
  ANTENNAGATEAREA                0.06300         LAYER MET3 ;
  ANTENNAPARTIALMETALAREA        0.09890         LAYER MET1 ;
  ANTENNAPARTIALMETALAREA        0.10380         LAYER MET2 ;
  ANTENNAMAXAREACAR              0.72381         LAYER MET1 ;
  ANTENNAMAXAREACAR              3.54286         LAYER MET2 ;
  ANTENNAMAXAREACAR              4.71429         LAYER MET3 ;
END D[46]
PIN Q[46]
  DIRECTION OUTPUT ;
  PORT
    LAYER MET1 ;
    RECT 196.200 0.000 196.610 0.180 ;
    LAYER MET2 ;
    RECT 196.200 0.000 196.610 0.180 ;
    LAYER MET3 ;
    RECT 196.200 0.000 196.610 0.180 ;
  END
  ANTENNADIFFAREA                0.60000         LAYER MET1 ;
  ANTENNADIFFAREA                0.60000         LAYER MET2 ;
  ANTENNADIFFAREA                0.60000         LAYER MET3 ;
  ANTENNAPARTIALMETALAREA        0.94400         LAYER MET1 ;
  ANTENNAPARTIALMETALAREA        1.33320         LAYER MET2 ;
END Q[46]
PIN D[47]
  DIRECTION INPUT ;
  PORT
    LAYER MET1 ;
    RECT 201.940 0.000 202.350 0.180 ;
    LAYER MET2 ;
    RECT 201.940 0.000 202.350 0.180 ;
    LAYER MET3 ;
    RECT 201.940 0.000 202.350 0.180 ;
  END
  ANTENNADIFFAREA                0.38930         LAYER MET1 ;
  ANTENNADIFFAREA                0.38930         LAYER MET2 ;
  ANTENNADIFFAREA                0.38930         LAYER MET3 ;
  ANTENNAGATEAREA                0.06300         LAYER MET1 ;
  ANTENNAGATEAREA                0.06300         LAYER MET2 ;
  ANTENNAGATEAREA                0.06300         LAYER MET3 ;
  ANTENNAPARTIALMETALAREA        0.09890         LAYER MET1 ;
  ANTENNAPARTIALMETALAREA        0.10380         LAYER MET2 ;
  ANTENNAMAXAREACAR              0.72381         LAYER MET1 ;
  ANTENNAMAXAREACAR              3.54286         LAYER MET2 ;
  ANTENNAMAXAREACAR              4.71429         LAYER MET3 ;
END D[47]
PIN Q[47]
  DIRECTION OUTPUT ;
  PORT
    LAYER MET1 ;
    RECT 200.400 0.000 200.810 0.180 ;
    LAYER MET2 ;
    RECT 200.400 0.000 200.810 0.180 ;
    LAYER MET3 ;
    RECT 200.400 0.000 200.810 0.180 ;
  END
  ANTENNADIFFAREA                0.60000         LAYER MET1 ;
  ANTENNADIFFAREA                0.60000         LAYER MET2 ;
  ANTENNADIFFAREA                0.60000         LAYER MET3 ;
  ANTENNAPARTIALMETALAREA        0.94400         LAYER MET1 ;
  ANTENNAPARTIALMETALAREA        1.33320         LAYER MET2 ;
END Q[47]
PIN D[48]
  DIRECTION INPUT ;
  PORT
    LAYER MET1 ;
    RECT 206.140 0.000 206.550 0.180 ;
    LAYER MET2 ;
    RECT 206.140 0.000 206.550 0.180 ;
    LAYER MET3 ;
    RECT 206.140 0.000 206.550 0.180 ;
  END
  ANTENNADIFFAREA                0.38930         LAYER MET1 ;
  ANTENNADIFFAREA                0.38930         LAYER MET2 ;
  ANTENNADIFFAREA                0.38930         LAYER MET3 ;
  ANTENNAGATEAREA                0.06300         LAYER MET1 ;
  ANTENNAGATEAREA                0.06300         LAYER MET2 ;
  ANTENNAGATEAREA                0.06300         LAYER MET3 ;
  ANTENNAPARTIALMETALAREA        0.09890         LAYER MET1 ;
  ANTENNAPARTIALMETALAREA        0.10380         LAYER MET2 ;
  ANTENNAMAXAREACAR              0.72381         LAYER MET1 ;
  ANTENNAMAXAREACAR              3.54286         LAYER MET2 ;
  ANTENNAMAXAREACAR              4.71429         LAYER MET3 ;
END D[48]
PIN Q[48]
  DIRECTION OUTPUT ;
  PORT
    LAYER MET1 ;
    RECT 204.600 0.000 205.010 0.180 ;
    LAYER MET2 ;
    RECT 204.600 0.000 205.010 0.180 ;
    LAYER MET3 ;
    RECT 204.600 0.000 205.010 0.180 ;
  END
  ANTENNADIFFAREA                0.60000         LAYER MET1 ;
  ANTENNADIFFAREA                0.60000         LAYER MET2 ;
  ANTENNADIFFAREA                0.60000         LAYER MET3 ;
  ANTENNAPARTIALMETALAREA        0.94400         LAYER MET1 ;
  ANTENNAPARTIALMETALAREA        1.33320         LAYER MET2 ;
END Q[48]
PIN D[49]
  DIRECTION INPUT ;
  PORT
    LAYER MET1 ;
    RECT 210.340 0.000 210.750 0.180 ;
    LAYER MET2 ;
    RECT 210.340 0.000 210.750 0.180 ;
    LAYER MET3 ;
    RECT 210.340 0.000 210.750 0.180 ;
  END
  ANTENNADIFFAREA                0.38930         LAYER MET1 ;
  ANTENNADIFFAREA                0.38930         LAYER MET2 ;
  ANTENNADIFFAREA                0.38930         LAYER MET3 ;
  ANTENNAGATEAREA                0.06300         LAYER MET1 ;
  ANTENNAGATEAREA                0.06300         LAYER MET2 ;
  ANTENNAGATEAREA                0.06300         LAYER MET3 ;
  ANTENNAPARTIALMETALAREA        0.09890         LAYER MET1 ;
  ANTENNAPARTIALMETALAREA        0.10380         LAYER MET2 ;
  ANTENNAMAXAREACAR              0.72381         LAYER MET1 ;
  ANTENNAMAXAREACAR              3.54286         LAYER MET2 ;
  ANTENNAMAXAREACAR              4.71429         LAYER MET3 ;
END D[49]
PIN Q[49]
  DIRECTION OUTPUT ;
  PORT
    LAYER MET1 ;
    RECT 208.800 0.000 209.210 0.180 ;
    LAYER MET2 ;
    RECT 208.800 0.000 209.210 0.180 ;
    LAYER MET3 ;
    RECT 208.800 0.000 209.210 0.180 ;
  END
  ANTENNADIFFAREA                0.60000         LAYER MET1 ;
  ANTENNADIFFAREA                0.60000         LAYER MET2 ;
  ANTENNADIFFAREA                0.60000         LAYER MET3 ;
  ANTENNAPARTIALMETALAREA        0.94400         LAYER MET1 ;
  ANTENNAPARTIALMETALAREA        1.33320         LAYER MET2 ;
END Q[49]
PIN D[50]
  DIRECTION INPUT ;
  PORT
    LAYER MET1 ;
    RECT 214.540 0.000 214.950 0.180 ;
    LAYER MET2 ;
    RECT 214.540 0.000 214.950 0.180 ;
    LAYER MET3 ;
    RECT 214.540 0.000 214.950 0.180 ;
  END
  ANTENNADIFFAREA                0.38930         LAYER MET1 ;
  ANTENNADIFFAREA                0.38930         LAYER MET2 ;
  ANTENNADIFFAREA                0.38930         LAYER MET3 ;
  ANTENNAGATEAREA                0.06300         LAYER MET1 ;
  ANTENNAGATEAREA                0.06300         LAYER MET2 ;
  ANTENNAGATEAREA                0.06300         LAYER MET3 ;
  ANTENNAPARTIALMETALAREA        0.09890         LAYER MET1 ;
  ANTENNAPARTIALMETALAREA        0.10380         LAYER MET2 ;
  ANTENNAMAXAREACAR              0.72381         LAYER MET1 ;
  ANTENNAMAXAREACAR              3.54286         LAYER MET2 ;
  ANTENNAMAXAREACAR              4.71429         LAYER MET3 ;
END D[50]
PIN Q[50]
  DIRECTION OUTPUT ;
  PORT
    LAYER MET1 ;
    RECT 213.000 0.000 213.410 0.180 ;
    LAYER MET2 ;
    RECT 213.000 0.000 213.410 0.180 ;
    LAYER MET3 ;
    RECT 213.000 0.000 213.410 0.180 ;
  END
  ANTENNADIFFAREA                0.60000         LAYER MET1 ;
  ANTENNADIFFAREA                0.60000         LAYER MET2 ;
  ANTENNADIFFAREA                0.60000         LAYER MET3 ;
  ANTENNAPARTIALMETALAREA        0.94400         LAYER MET1 ;
  ANTENNAPARTIALMETALAREA        1.33320         LAYER MET2 ;
END Q[50]
PIN D[51]
  DIRECTION INPUT ;
  PORT
    LAYER MET1 ;
    RECT 218.740 0.000 219.150 0.180 ;
    LAYER MET2 ;
    RECT 218.740 0.000 219.150 0.180 ;
    LAYER MET3 ;
    RECT 218.740 0.000 219.150 0.180 ;
  END
  ANTENNADIFFAREA                0.38930         LAYER MET1 ;
  ANTENNADIFFAREA                0.38930         LAYER MET2 ;
  ANTENNADIFFAREA                0.38930         LAYER MET3 ;
  ANTENNAGATEAREA                0.06300         LAYER MET1 ;
  ANTENNAGATEAREA                0.06300         LAYER MET2 ;
  ANTENNAGATEAREA                0.06300         LAYER MET3 ;
  ANTENNAPARTIALMETALAREA        0.09890         LAYER MET1 ;
  ANTENNAPARTIALMETALAREA        0.10380         LAYER MET2 ;
  ANTENNAMAXAREACAR              0.72381         LAYER MET1 ;
  ANTENNAMAXAREACAR              3.54286         LAYER MET2 ;
  ANTENNAMAXAREACAR              4.71429         LAYER MET3 ;
END D[51]
PIN Q[51]
  DIRECTION OUTPUT ;
  PORT
    LAYER MET1 ;
    RECT 217.200 0.000 217.610 0.180 ;
    LAYER MET2 ;
    RECT 217.200 0.000 217.610 0.180 ;
    LAYER MET3 ;
    RECT 217.200 0.000 217.610 0.180 ;
  END
  ANTENNADIFFAREA                0.60000         LAYER MET1 ;
  ANTENNADIFFAREA                0.60000         LAYER MET2 ;
  ANTENNADIFFAREA                0.60000         LAYER MET3 ;
  ANTENNAPARTIALMETALAREA        0.94400         LAYER MET1 ;
  ANTENNAPARTIALMETALAREA        1.33320         LAYER MET2 ;
END Q[51]
PIN D[52]
  DIRECTION INPUT ;
  PORT
    LAYER MET1 ;
    RECT 222.940 0.000 223.350 0.180 ;
    LAYER MET2 ;
    RECT 222.940 0.000 223.350 0.180 ;
    LAYER MET3 ;
    RECT 222.940 0.000 223.350 0.180 ;
  END
  ANTENNADIFFAREA                0.38930         LAYER MET1 ;
  ANTENNADIFFAREA                0.38930         LAYER MET2 ;
  ANTENNADIFFAREA                0.38930         LAYER MET3 ;
  ANTENNAGATEAREA                0.06300         LAYER MET1 ;
  ANTENNAGATEAREA                0.06300         LAYER MET2 ;
  ANTENNAGATEAREA                0.06300         LAYER MET3 ;
  ANTENNAPARTIALMETALAREA        0.09890         LAYER MET1 ;
  ANTENNAPARTIALMETALAREA        0.10380         LAYER MET2 ;
  ANTENNAMAXAREACAR              0.72381         LAYER MET1 ;
  ANTENNAMAXAREACAR              3.54286         LAYER MET2 ;
  ANTENNAMAXAREACAR              4.71429         LAYER MET3 ;
END D[52]
PIN Q[52]
  DIRECTION OUTPUT ;
  PORT
    LAYER MET1 ;
    RECT 221.400 0.000 221.810 0.180 ;
    LAYER MET2 ;
    RECT 221.400 0.000 221.810 0.180 ;
    LAYER MET3 ;
    RECT 221.400 0.000 221.810 0.180 ;
  END
  ANTENNADIFFAREA                0.60000         LAYER MET1 ;
  ANTENNADIFFAREA                0.60000         LAYER MET2 ;
  ANTENNADIFFAREA                0.60000         LAYER MET3 ;
  ANTENNAPARTIALMETALAREA        0.94400         LAYER MET1 ;
  ANTENNAPARTIALMETALAREA        1.33320         LAYER MET2 ;
END Q[52]
PIN D[53]
  DIRECTION INPUT ;
  PORT
    LAYER MET1 ;
    RECT 227.140 0.000 227.550 0.180 ;
    LAYER MET2 ;
    RECT 227.140 0.000 227.550 0.180 ;
    LAYER MET3 ;
    RECT 227.140 0.000 227.550 0.180 ;
  END
  ANTENNADIFFAREA                0.38930         LAYER MET1 ;
  ANTENNADIFFAREA                0.38930         LAYER MET2 ;
  ANTENNADIFFAREA                0.38930         LAYER MET3 ;
  ANTENNAGATEAREA                0.06300         LAYER MET1 ;
  ANTENNAGATEAREA                0.06300         LAYER MET2 ;
  ANTENNAGATEAREA                0.06300         LAYER MET3 ;
  ANTENNAPARTIALMETALAREA        0.09890         LAYER MET1 ;
  ANTENNAPARTIALMETALAREA        0.10380         LAYER MET2 ;
  ANTENNAMAXAREACAR              0.72381         LAYER MET1 ;
  ANTENNAMAXAREACAR              3.54286         LAYER MET2 ;
  ANTENNAMAXAREACAR              4.71429         LAYER MET3 ;
END D[53]
PIN Q[53]
  DIRECTION OUTPUT ;
  PORT
    LAYER MET1 ;
    RECT 225.600 0.000 226.010 0.180 ;
    LAYER MET2 ;
    RECT 225.600 0.000 226.010 0.180 ;
    LAYER MET3 ;
    RECT 225.600 0.000 226.010 0.180 ;
  END
  ANTENNADIFFAREA                0.60000         LAYER MET1 ;
  ANTENNADIFFAREA                0.60000         LAYER MET2 ;
  ANTENNADIFFAREA                0.60000         LAYER MET3 ;
  ANTENNAPARTIALMETALAREA        0.94400         LAYER MET1 ;
  ANTENNAPARTIALMETALAREA        1.33320         LAYER MET2 ;
END Q[53]
PIN D[54]
  DIRECTION INPUT ;
  PORT
    LAYER MET1 ;
    RECT 231.340 0.000 231.750 0.180 ;
    LAYER MET2 ;
    RECT 231.340 0.000 231.750 0.180 ;
    LAYER MET3 ;
    RECT 231.340 0.000 231.750 0.180 ;
  END
  ANTENNADIFFAREA                0.38930         LAYER MET1 ;
  ANTENNADIFFAREA                0.38930         LAYER MET2 ;
  ANTENNADIFFAREA                0.38930         LAYER MET3 ;
  ANTENNAGATEAREA                0.06300         LAYER MET1 ;
  ANTENNAGATEAREA                0.06300         LAYER MET2 ;
  ANTENNAGATEAREA                0.06300         LAYER MET3 ;
  ANTENNAPARTIALMETALAREA        0.09890         LAYER MET1 ;
  ANTENNAPARTIALMETALAREA        0.10380         LAYER MET2 ;
  ANTENNAMAXAREACAR              0.72381         LAYER MET1 ;
  ANTENNAMAXAREACAR              3.54286         LAYER MET2 ;
  ANTENNAMAXAREACAR              4.71429         LAYER MET3 ;
END D[54]
PIN Q[54]
  DIRECTION OUTPUT ;
  PORT
    LAYER MET1 ;
    RECT 229.800 0.000 230.210 0.180 ;
    LAYER MET2 ;
    RECT 229.800 0.000 230.210 0.180 ;
    LAYER MET3 ;
    RECT 229.800 0.000 230.210 0.180 ;
  END
  ANTENNADIFFAREA                0.60000         LAYER MET1 ;
  ANTENNADIFFAREA                0.60000         LAYER MET2 ;
  ANTENNADIFFAREA                0.60000         LAYER MET3 ;
  ANTENNAPARTIALMETALAREA        0.94400         LAYER MET1 ;
  ANTENNAPARTIALMETALAREA        1.33320         LAYER MET2 ;
END Q[54]
PIN D[55]
  DIRECTION INPUT ;
  PORT
    LAYER MET1 ;
    RECT 235.540 0.000 235.950 0.180 ;
    LAYER MET2 ;
    RECT 235.540 0.000 235.950 0.180 ;
    LAYER MET3 ;
    RECT 235.540 0.000 235.950 0.180 ;
  END
  ANTENNADIFFAREA                0.38930         LAYER MET1 ;
  ANTENNADIFFAREA                0.38930         LAYER MET2 ;
  ANTENNADIFFAREA                0.38930         LAYER MET3 ;
  ANTENNAGATEAREA                0.06300         LAYER MET1 ;
  ANTENNAGATEAREA                0.06300         LAYER MET2 ;
  ANTENNAGATEAREA                0.06300         LAYER MET3 ;
  ANTENNAPARTIALMETALAREA        0.09890         LAYER MET1 ;
  ANTENNAPARTIALMETALAREA        0.10380         LAYER MET2 ;
  ANTENNAMAXAREACAR              0.72381         LAYER MET1 ;
  ANTENNAMAXAREACAR              3.54286         LAYER MET2 ;
  ANTENNAMAXAREACAR              4.71429         LAYER MET3 ;
END D[55]
PIN Q[55]
  DIRECTION OUTPUT ;
  PORT
    LAYER MET1 ;
    RECT 234.000 0.000 234.410 0.180 ;
    LAYER MET2 ;
    RECT 234.000 0.000 234.410 0.180 ;
    LAYER MET3 ;
    RECT 234.000 0.000 234.410 0.180 ;
  END
  ANTENNADIFFAREA                0.60000         LAYER MET1 ;
  ANTENNADIFFAREA                0.60000         LAYER MET2 ;
  ANTENNADIFFAREA                0.60000         LAYER MET3 ;
  ANTENNAPARTIALMETALAREA        0.94400         LAYER MET1 ;
  ANTENNAPARTIALMETALAREA        1.33320         LAYER MET2 ;
END Q[55]
PIN D[56]
  DIRECTION INPUT ;
  PORT
    LAYER MET1 ;
    RECT 239.740 0.000 240.150 0.180 ;
    LAYER MET2 ;
    RECT 239.740 0.000 240.150 0.180 ;
    LAYER MET3 ;
    RECT 239.740 0.000 240.150 0.180 ;
  END
  ANTENNADIFFAREA                0.38930         LAYER MET1 ;
  ANTENNADIFFAREA                0.38930         LAYER MET2 ;
  ANTENNADIFFAREA                0.38930         LAYER MET3 ;
  ANTENNAGATEAREA                0.06300         LAYER MET1 ;
  ANTENNAGATEAREA                0.06300         LAYER MET2 ;
  ANTENNAGATEAREA                0.06300         LAYER MET3 ;
  ANTENNAPARTIALMETALAREA        0.09890         LAYER MET1 ;
  ANTENNAPARTIALMETALAREA        0.10380         LAYER MET2 ;
  ANTENNAMAXAREACAR              0.72381         LAYER MET1 ;
  ANTENNAMAXAREACAR              3.54286         LAYER MET2 ;
  ANTENNAMAXAREACAR              4.71429         LAYER MET3 ;
END D[56]
PIN Q[56]
  DIRECTION OUTPUT ;
  PORT
    LAYER MET1 ;
    RECT 238.200 0.000 238.610 0.180 ;
    LAYER MET2 ;
    RECT 238.200 0.000 238.610 0.180 ;
    LAYER MET3 ;
    RECT 238.200 0.000 238.610 0.180 ;
  END
  ANTENNADIFFAREA                0.60000         LAYER MET1 ;
  ANTENNADIFFAREA                0.60000         LAYER MET2 ;
  ANTENNADIFFAREA                0.60000         LAYER MET3 ;
  ANTENNAPARTIALMETALAREA        0.94400         LAYER MET1 ;
  ANTENNAPARTIALMETALAREA        1.33320         LAYER MET2 ;
END Q[56]
PIN D[57]
  DIRECTION INPUT ;
  PORT
    LAYER MET1 ;
    RECT 243.940 0.000 244.350 0.180 ;
    LAYER MET2 ;
    RECT 243.940 0.000 244.350 0.180 ;
    LAYER MET3 ;
    RECT 243.940 0.000 244.350 0.180 ;
  END
  ANTENNADIFFAREA                0.38930         LAYER MET1 ;
  ANTENNADIFFAREA                0.38930         LAYER MET2 ;
  ANTENNADIFFAREA                0.38930         LAYER MET3 ;
  ANTENNAGATEAREA                0.06300         LAYER MET1 ;
  ANTENNAGATEAREA                0.06300         LAYER MET2 ;
  ANTENNAGATEAREA                0.06300         LAYER MET3 ;
  ANTENNAPARTIALMETALAREA        0.09890         LAYER MET1 ;
  ANTENNAPARTIALMETALAREA        0.10380         LAYER MET2 ;
  ANTENNAMAXAREACAR              0.72381         LAYER MET1 ;
  ANTENNAMAXAREACAR              3.54286         LAYER MET2 ;
  ANTENNAMAXAREACAR              4.71429         LAYER MET3 ;
END D[57]
PIN Q[57]
  DIRECTION OUTPUT ;
  PORT
    LAYER MET1 ;
    RECT 242.400 0.000 242.810 0.180 ;
    LAYER MET2 ;
    RECT 242.400 0.000 242.810 0.180 ;
    LAYER MET3 ;
    RECT 242.400 0.000 242.810 0.180 ;
  END
  ANTENNADIFFAREA                0.60000         LAYER MET1 ;
  ANTENNADIFFAREA                0.60000         LAYER MET2 ;
  ANTENNADIFFAREA                0.60000         LAYER MET3 ;
  ANTENNAPARTIALMETALAREA        0.94400         LAYER MET1 ;
  ANTENNAPARTIALMETALAREA        1.33320         LAYER MET2 ;
END Q[57]
PIN D[58]
  DIRECTION INPUT ;
  PORT
    LAYER MET1 ;
    RECT 248.140 0.000 248.550 0.180 ;
    LAYER MET2 ;
    RECT 248.140 0.000 248.550 0.180 ;
    LAYER MET3 ;
    RECT 248.140 0.000 248.550 0.180 ;
  END
  ANTENNADIFFAREA                0.38930         LAYER MET1 ;
  ANTENNADIFFAREA                0.38930         LAYER MET2 ;
  ANTENNADIFFAREA                0.38930         LAYER MET3 ;
  ANTENNAGATEAREA                0.06300         LAYER MET1 ;
  ANTENNAGATEAREA                0.06300         LAYER MET2 ;
  ANTENNAGATEAREA                0.06300         LAYER MET3 ;
  ANTENNAPARTIALMETALAREA        0.09890         LAYER MET1 ;
  ANTENNAPARTIALMETALAREA        0.10380         LAYER MET2 ;
  ANTENNAMAXAREACAR              0.72381         LAYER MET1 ;
  ANTENNAMAXAREACAR              3.54286         LAYER MET2 ;
  ANTENNAMAXAREACAR              4.71429         LAYER MET3 ;
END D[58]
PIN Q[58]
  DIRECTION OUTPUT ;
  PORT
    LAYER MET1 ;
    RECT 246.600 0.000 247.010 0.180 ;
    LAYER MET2 ;
    RECT 246.600 0.000 247.010 0.180 ;
    LAYER MET3 ;
    RECT 246.600 0.000 247.010 0.180 ;
  END
  ANTENNADIFFAREA                0.60000         LAYER MET1 ;
  ANTENNADIFFAREA                0.60000         LAYER MET2 ;
  ANTENNADIFFAREA                0.60000         LAYER MET3 ;
  ANTENNAPARTIALMETALAREA        0.94400         LAYER MET1 ;
  ANTENNAPARTIALMETALAREA        1.33320         LAYER MET2 ;
END Q[58]
PIN D[59]
  DIRECTION INPUT ;
  PORT
    LAYER MET1 ;
    RECT 252.340 0.000 252.750 0.180 ;
    LAYER MET2 ;
    RECT 252.340 0.000 252.750 0.180 ;
    LAYER MET3 ;
    RECT 252.340 0.000 252.750 0.180 ;
  END
  ANTENNADIFFAREA                0.38930         LAYER MET1 ;
  ANTENNADIFFAREA                0.38930         LAYER MET2 ;
  ANTENNADIFFAREA                0.38930         LAYER MET3 ;
  ANTENNAGATEAREA                0.06300         LAYER MET1 ;
  ANTENNAGATEAREA                0.06300         LAYER MET2 ;
  ANTENNAGATEAREA                0.06300         LAYER MET3 ;
  ANTENNAPARTIALMETALAREA        0.09890         LAYER MET1 ;
  ANTENNAPARTIALMETALAREA        0.10380         LAYER MET2 ;
  ANTENNAMAXAREACAR              0.72381         LAYER MET1 ;
  ANTENNAMAXAREACAR              3.54286         LAYER MET2 ;
  ANTENNAMAXAREACAR              4.71429         LAYER MET3 ;
END D[59]
PIN Q[59]
  DIRECTION OUTPUT ;
  PORT
    LAYER MET1 ;
    RECT 250.800 0.000 251.210 0.180 ;
    LAYER MET2 ;
    RECT 250.800 0.000 251.210 0.180 ;
    LAYER MET3 ;
    RECT 250.800 0.000 251.210 0.180 ;
  END
  ANTENNADIFFAREA                0.60000         LAYER MET1 ;
  ANTENNADIFFAREA                0.60000         LAYER MET2 ;
  ANTENNADIFFAREA                0.60000         LAYER MET3 ;
  ANTENNAPARTIALMETALAREA        0.94400         LAYER MET1 ;
  ANTENNAPARTIALMETALAREA        1.33320         LAYER MET2 ;
END Q[59]
PIN D[60]
  DIRECTION INPUT ;
  PORT
    LAYER MET1 ;
    RECT 256.540 0.000 256.950 0.180 ;
    LAYER MET2 ;
    RECT 256.540 0.000 256.950 0.180 ;
    LAYER MET3 ;
    RECT 256.540 0.000 256.950 0.180 ;
  END
  ANTENNADIFFAREA                0.38930         LAYER MET1 ;
  ANTENNADIFFAREA                0.38930         LAYER MET2 ;
  ANTENNADIFFAREA                0.38930         LAYER MET3 ;
  ANTENNAGATEAREA                0.06300         LAYER MET1 ;
  ANTENNAGATEAREA                0.06300         LAYER MET2 ;
  ANTENNAGATEAREA                0.06300         LAYER MET3 ;
  ANTENNAPARTIALMETALAREA        0.09890         LAYER MET1 ;
  ANTENNAPARTIALMETALAREA        0.10380         LAYER MET2 ;
  ANTENNAMAXAREACAR              0.72381         LAYER MET1 ;
  ANTENNAMAXAREACAR              3.54286         LAYER MET2 ;
  ANTENNAMAXAREACAR              4.71429         LAYER MET3 ;
END D[60]
PIN Q[60]
  DIRECTION OUTPUT ;
  PORT
    LAYER MET1 ;
    RECT 255.000 0.000 255.410 0.180 ;
    LAYER MET2 ;
    RECT 255.000 0.000 255.410 0.180 ;
    LAYER MET3 ;
    RECT 255.000 0.000 255.410 0.180 ;
  END
  ANTENNADIFFAREA                0.60000         LAYER MET1 ;
  ANTENNADIFFAREA                0.60000         LAYER MET2 ;
  ANTENNADIFFAREA                0.60000         LAYER MET3 ;
  ANTENNAPARTIALMETALAREA        0.94400         LAYER MET1 ;
  ANTENNAPARTIALMETALAREA        1.33320         LAYER MET2 ;
END Q[60]
PIN D[61]
  DIRECTION INPUT ;
  PORT
    LAYER MET1 ;
    RECT 260.740 0.000 261.150 0.180 ;
    LAYER MET2 ;
    RECT 260.740 0.000 261.150 0.180 ;
    LAYER MET3 ;
    RECT 260.740 0.000 261.150 0.180 ;
  END
  ANTENNADIFFAREA                0.38930         LAYER MET1 ;
  ANTENNADIFFAREA                0.38930         LAYER MET2 ;
  ANTENNADIFFAREA                0.38930         LAYER MET3 ;
  ANTENNAGATEAREA                0.06300         LAYER MET1 ;
  ANTENNAGATEAREA                0.06300         LAYER MET2 ;
  ANTENNAGATEAREA                0.06300         LAYER MET3 ;
  ANTENNAPARTIALMETALAREA        0.09890         LAYER MET1 ;
  ANTENNAPARTIALMETALAREA        0.10380         LAYER MET2 ;
  ANTENNAMAXAREACAR              0.72381         LAYER MET1 ;
  ANTENNAMAXAREACAR              3.54286         LAYER MET2 ;
  ANTENNAMAXAREACAR              4.71429         LAYER MET3 ;
END D[61]
PIN Q[61]
  DIRECTION OUTPUT ;
  PORT
    LAYER MET1 ;
    RECT 259.200 0.000 259.610 0.180 ;
    LAYER MET2 ;
    RECT 259.200 0.000 259.610 0.180 ;
    LAYER MET3 ;
    RECT 259.200 0.000 259.610 0.180 ;
  END
  ANTENNADIFFAREA                0.60000         LAYER MET1 ;
  ANTENNADIFFAREA                0.60000         LAYER MET2 ;
  ANTENNADIFFAREA                0.60000         LAYER MET3 ;
  ANTENNAPARTIALMETALAREA        0.94400         LAYER MET1 ;
  ANTENNAPARTIALMETALAREA        1.33320         LAYER MET2 ;
END Q[61]
PIN D[62]
  DIRECTION INPUT ;
  PORT
    LAYER MET1 ;
    RECT 264.940 0.000 265.350 0.180 ;
    LAYER MET2 ;
    RECT 264.940 0.000 265.350 0.180 ;
    LAYER MET3 ;
    RECT 264.940 0.000 265.350 0.180 ;
  END
  ANTENNADIFFAREA                0.38930         LAYER MET1 ;
  ANTENNADIFFAREA                0.38930         LAYER MET2 ;
  ANTENNADIFFAREA                0.38930         LAYER MET3 ;
  ANTENNAGATEAREA                0.06300         LAYER MET1 ;
  ANTENNAGATEAREA                0.06300         LAYER MET2 ;
  ANTENNAGATEAREA                0.06300         LAYER MET3 ;
  ANTENNAPARTIALMETALAREA        0.09890         LAYER MET1 ;
  ANTENNAPARTIALMETALAREA        0.10380         LAYER MET2 ;
  ANTENNAMAXAREACAR              0.72381         LAYER MET1 ;
  ANTENNAMAXAREACAR              3.54286         LAYER MET2 ;
  ANTENNAMAXAREACAR              4.71429         LAYER MET3 ;
END D[62]
PIN Q[62]
  DIRECTION OUTPUT ;
  PORT
    LAYER MET1 ;
    RECT 263.400 0.000 263.810 0.180 ;
    LAYER MET2 ;
    RECT 263.400 0.000 263.810 0.180 ;
    LAYER MET3 ;
    RECT 263.400 0.000 263.810 0.180 ;
  END
  ANTENNADIFFAREA                0.60000         LAYER MET1 ;
  ANTENNADIFFAREA                0.60000         LAYER MET2 ;
  ANTENNADIFFAREA                0.60000         LAYER MET3 ;
  ANTENNAPARTIALMETALAREA        0.94400         LAYER MET1 ;
  ANTENNAPARTIALMETALAREA        1.33320         LAYER MET2 ;
END Q[62]
PIN D[63]
  DIRECTION INPUT ;
  PORT
    LAYER MET1 ;
    RECT 269.140 0.000 269.550 0.180 ;
    LAYER MET2 ;
    RECT 269.140 0.000 269.550 0.180 ;
    LAYER MET3 ;
    RECT 269.140 0.000 269.550 0.180 ;
  END
  ANTENNADIFFAREA                0.38930         LAYER MET1 ;
  ANTENNADIFFAREA                0.38930         LAYER MET2 ;
  ANTENNADIFFAREA                0.38930         LAYER MET3 ;
  ANTENNAGATEAREA                0.06300         LAYER MET1 ;
  ANTENNAGATEAREA                0.06300         LAYER MET2 ;
  ANTENNAGATEAREA                0.06300         LAYER MET3 ;
  ANTENNAPARTIALMETALAREA        0.09890         LAYER MET1 ;
  ANTENNAPARTIALMETALAREA        0.10380         LAYER MET2 ;
  ANTENNAMAXAREACAR              0.72381         LAYER MET1 ;
  ANTENNAMAXAREACAR              3.54286         LAYER MET2 ;
  ANTENNAMAXAREACAR              4.71429         LAYER MET3 ;
END D[63]
PIN Q[63]
  DIRECTION OUTPUT ;
  PORT
    LAYER MET1 ;
    RECT 267.600 0.000 268.010 0.180 ;
    LAYER MET2 ;
    RECT 267.600 0.000 268.010 0.180 ;
    LAYER MET3 ;
    RECT 267.600 0.000 268.010 0.180 ;
  END
  ANTENNADIFFAREA                0.60000         LAYER MET1 ;
  ANTENNADIFFAREA                0.60000         LAYER MET2 ;
  ANTENNADIFFAREA                0.60000         LAYER MET3 ;
  ANTENNAPARTIALMETALAREA        0.94400         LAYER MET1 ;
  ANTENNAPARTIALMETALAREA        1.33320         LAYER MET2 ;
END Q[63]
PIN CLK
  DIRECTION INPUT ;
  PORT
    LAYER MET1 ;
    RECT 281.990 0.000 282.400 0.180 ;
    LAYER MET2 ;
    RECT 281.990 0.000 282.400 0.180 ;
    LAYER MET3 ;
    RECT 281.990 0.000 282.400 0.180 ;
  END
  ANTENNADIFFAREA                0.68830         LAYER MET1 ;
  ANTENNADIFFAREA                0.68830         LAYER MET2 ;
  ANTENNADIFFAREA                0.68830         LAYER MET3 ;
  ANTENNAGATEAREA                0.09000         LAYER MET1 ;
  ANTENNAGATEAREA                0.09000         LAYER MET2 ;
  ANTENNAGATEAREA                0.09000         LAYER MET3 ;
  ANTENNAPARTIALMETALAREA        0.11410         LAYER MET1 ;
  ANTENNAPARTIALMETALAREA        0.92700         LAYER MET2 ;
  ANTENNAMAXAREACAR              0.67556         LAYER MET1 ;
  ANTENNAMAXAREACAR              11.79556        LAYER MET2 ;
  ANTENNAMAXAREACAR              12.61556        LAYER MET3 ;
END CLK
PIN CEB
  DIRECTION INPUT ;
  PORT
    LAYER MET1 ;
    RECT 280.205 0.000 280.615 0.180 ;
    LAYER MET2 ;
    RECT 280.205 0.000 280.615 0.180 ;
    LAYER MET3 ;
    RECT 280.205 0.000 280.615 0.180 ;
  END
  ANTENNADIFFAREA                2.40880         LAYER MET1 ;
  ANTENNADIFFAREA                2.40880         LAYER MET2 ;
  ANTENNADIFFAREA                2.40880         LAYER MET3 ;
  ANTENNAGATEAREA                0.37800         LAYER MET1 ;
  ANTENNAGATEAREA                0.37800         LAYER MET2 ;
  ANTENNAGATEAREA                0.37800         LAYER MET3 ;
  ANTENNAPARTIALMETALAREA        0.26510         LAYER MET1 ;
  ANTENNAPARTIALMETALAREA        1.07760         LAYER MET2 ;
  ANTENNAMAXAREACAR              3.36190         LAYER MET1 ;
  ANTENNAMAXAREACAR              21.63810        LAYER MET2 ;
  ANTENNAMAXAREACAR              22.80952        LAYER MET3 ;
END CEB
PIN D[121]
  DIRECTION INPUT ;
  PORT
    LAYER MET1 ;
    RECT 540.090 0.000 540.500 0.180 ;
    LAYER MET2 ;
    RECT 540.090 0.000 540.500 0.180 ;
    LAYER MET3 ;
    RECT 540.090 0.000 540.500 0.180 ;
  END
  ANTENNADIFFAREA                0.38930         LAYER MET1 ;
  ANTENNADIFFAREA                0.38930         LAYER MET2 ;
  ANTENNADIFFAREA                0.38930         LAYER MET3 ;
  ANTENNAGATEAREA                0.06300         LAYER MET1 ;
  ANTENNAGATEAREA                0.06300         LAYER MET2 ;
  ANTENNAGATEAREA                0.06300         LAYER MET3 ;
  ANTENNAPARTIALMETALAREA        0.09890         LAYER MET1 ;
  ANTENNAPARTIALMETALAREA        0.10380         LAYER MET2 ;
  ANTENNAMAXAREACAR              0.72381         LAYER MET1 ;
  ANTENNAMAXAREACAR              3.54286         LAYER MET2 ;
  ANTENNAMAXAREACAR              4.71429         LAYER MET3 ;
END D[121]
PIN Q[121]
  DIRECTION OUTPUT ;
  PORT
    LAYER MET1 ;
    RECT 538.550 0.000 538.960 0.180 ;
    LAYER MET2 ;
    RECT 538.550 0.000 538.960 0.180 ;
    LAYER MET3 ;
    RECT 538.550 0.000 538.960 0.180 ;
  END
  ANTENNADIFFAREA                0.60000         LAYER MET1 ;
  ANTENNADIFFAREA                0.60000         LAYER MET2 ;
  ANTENNADIFFAREA                0.60000         LAYER MET3 ;
  ANTENNAPARTIALMETALAREA        0.94400         LAYER MET1 ;
  ANTENNAPARTIALMETALAREA        1.33320         LAYER MET2 ;
END Q[121]
PIN MAR[0]
  DIRECTION INPUT ;
  PORT
    LAYER MET1 ;
    RECT 274.550 0.000 274.960 0.180 ;
    LAYER MET2 ;
    RECT 274.550 0.000 274.960 0.180 ;
    LAYER MET3 ;
    RECT 274.550 0.000 274.960 0.180 ;
  END
  ANTENNADIFFAREA                0.30530         LAYER MET1 ;
  ANTENNADIFFAREA                0.30530         LAYER MET2 ;
  ANTENNADIFFAREA                0.30530         LAYER MET3 ;
  ANTENNAGATEAREA                0.04200         LAYER MET1 ;
  ANTENNAGATEAREA                0.04200         LAYER MET2 ;
  ANTENNAGATEAREA                0.04200         LAYER MET3 ;
  ANTENNAPARTIALMETALAREA        0.40280         LAYER MET1 ;
  ANTENNAPARTIALMETALAREA        1.19340         LAYER MET2 ;
  ANTENNAMAXAREACAR              8.32143         LAYER MET1 ;
  ANTENNAMAXAREACAR              38.49286        LAYER MET2 ;
  ANTENNAMAXAREACAR              40.25000        LAYER MET3 ;
END MAR[0]
PIN MAR[1]
  DIRECTION INPUT ;
  PORT
    LAYER MET1 ;
    RECT 279.145 0.000 279.555 0.180 ;
    LAYER MET2 ;
    RECT 279.145 0.000 279.555 0.180 ;
    LAYER MET3 ;
    RECT 279.145 0.000 279.555 0.180 ;
  END
  ANTENNADIFFAREA                0.30530         LAYER MET1 ;
  ANTENNADIFFAREA                0.30530         LAYER MET2 ;
  ANTENNADIFFAREA                0.30530         LAYER MET3 ;
  ANTENNAGATEAREA                0.04200         LAYER MET1 ;
  ANTENNAGATEAREA                0.04200         LAYER MET2 ;
  ANTENNAGATEAREA                0.04200         LAYER MET3 ;
  ANTENNAPARTIALMETALAREA        0.29630         LAYER MET1 ;
  ANTENNAPARTIALMETALAREA        1.11780         LAYER MET2 ;
  ANTENNAMAXAREACAR              5.78571         LAYER MET1 ;
  ANTENNAMAXAREACAR              34.15714        LAYER MET2 ;
  ANTENNAMAXAREACAR              35.91429        LAYER MET3 ;
END MAR[1]
PIN MAR[2]
  DIRECTION INPUT ;
  PORT
    LAYER MET1 ;
    RECT 277.540 0.000 277.950 0.180 ;
    LAYER MET2 ;
    RECT 277.540 0.000 277.950 0.180 ;
    LAYER MET3 ;
    RECT 277.540 0.000 277.950 0.180 ;
  END
  ANTENNADIFFAREA                0.30530         LAYER MET1 ;
  ANTENNADIFFAREA                0.30530         LAYER MET2 ;
  ANTENNADIFFAREA                0.30530         LAYER MET3 ;
  ANTENNAGATEAREA                0.04200         LAYER MET1 ;
  ANTENNAGATEAREA                0.04200         LAYER MET2 ;
  ANTENNAGATEAREA                0.04200         LAYER MET3 ;
  ANTENNAPARTIALMETALAREA        0.12430         LAYER MET1 ;
  ANTENNAPARTIALMETALAREA        1.22700         LAYER MET2 ;
  ANTENNAMAXAREACAR              1.69048         LAYER MET1 ;
  ANTENNAMAXAREACAR              32.66190        LAYER MET2 ;
  ANTENNAMAXAREACAR              34.41905        LAYER MET3 ;
END MAR[2]
PIN MAR[3]
  DIRECTION INPUT ;
  PORT
    LAYER MET1 ;
    RECT 275.900 0.000 276.310 0.180 ;
    LAYER MET2 ;
    RECT 275.900 0.000 276.310 0.180 ;
    LAYER MET3 ;
    RECT 275.900 0.000 276.310 0.180 ;
  END
  ANTENNADIFFAREA                0.30530         LAYER MET1 ;
  ANTENNADIFFAREA                0.30530         LAYER MET2 ;
  ANTENNADIFFAREA                0.30530         LAYER MET3 ;
  ANTENNAGATEAREA                0.04200         LAYER MET1 ;
  ANTENNAGATEAREA                0.04200         LAYER MET2 ;
  ANTENNAGATEAREA                0.04200         LAYER MET3 ;
  ANTENNAPARTIALMETALAREA        0.32880         LAYER MET1 ;
  ANTENNAPARTIALMETALAREA        1.21620         LAYER MET2 ;
  ANTENNAMAXAREACAR              6.55952         LAYER MET1 ;
  ANTENNAMAXAREACAR              37.27381        LAYER MET2 ;
  ANTENNAMAXAREACAR              39.03095        LAYER MET3 ;
END MAR[3]
PIN A[0]
  DIRECTION INPUT ;
  PORT
    LAYER MET1 ;
    RECT 290.300 0.000 290.710 0.180 ;
    LAYER MET2 ;
    RECT 290.300 0.000 290.710 0.180 ;
    LAYER MET3 ;
    RECT 290.300 0.000 290.710 0.180 ;
  END
  ANTENNADIFFAREA                0.43130         LAYER MET1 ;
  ANTENNADIFFAREA                0.43130         LAYER MET2 ;
  ANTENNADIFFAREA                0.43130         LAYER MET3 ;
  ANTENNAGATEAREA                0.06300         LAYER MET1 ;
  ANTENNAGATEAREA                0.06300         LAYER MET2 ;
  ANTENNAGATEAREA                0.06300         LAYER MET3 ;
  ANTENNAPARTIALMETALAREA        0.11990         LAYER MET1 ;
  ANTENNAPARTIALMETALAREA        1.91700         LAYER MET2 ;
  ANTENNAMAXAREACAR              1.05714         LAYER MET1 ;
  ANTENNAMAXAREACAR              32.65714        LAYER MET2 ;
  ANTENNAMAXAREACAR              33.82857        LAYER MET3 ;
END A[0]
PIN A[1]
  DIRECTION INPUT ;
  PORT
    LAYER MET1 ;
    RECT 289.610 0.000 290.020 0.180 ;
    LAYER MET2 ;
    RECT 289.610 0.000 290.020 0.180 ;
    LAYER MET3 ;
    RECT 289.610 0.000 290.020 0.180 ;
  END
  ANTENNADIFFAREA                0.43130         LAYER MET1 ;
  ANTENNADIFFAREA                0.43130         LAYER MET2 ;
  ANTENNADIFFAREA                0.43130         LAYER MET3 ;
  ANTENNAGATEAREA                0.06300         LAYER MET1 ;
  ANTENNAGATEAREA                0.06300         LAYER MET2 ;
  ANTENNAGATEAREA                0.06300         LAYER MET3 ;
  ANTENNAPARTIALMETALAREA        0.09890         LAYER MET1 ;
  ANTENNAPARTIALMETALAREA        1.65700         LAYER MET2 ;
  ANTENNAMAXAREACAR              0.72381         LAYER MET1 ;
  ANTENNAMAXAREACAR              28.19683        LAYER MET2 ;
  ANTENNAMAXAREACAR              29.36825        LAYER MET3 ;
END A[1]
PIN A[2]
  DIRECTION INPUT ;
  PORT
    LAYER MET1 ;
    RECT 293.990 0.000 294.400 0.180 ;
    LAYER MET2 ;
    RECT 293.990 0.000 294.400 0.180 ;
    LAYER MET3 ;
    RECT 293.990 0.000 294.400 0.180 ;
  END
  ANTENNADIFFAREA                0.43130         LAYER MET1 ;
  ANTENNADIFFAREA                0.43130         LAYER MET2 ;
  ANTENNADIFFAREA                0.43130         LAYER MET3 ;
  ANTENNAGATEAREA                0.06300         LAYER MET1 ;
  ANTENNAGATEAREA                0.06300         LAYER MET2 ;
  ANTENNAGATEAREA                0.06300         LAYER MET3 ;
  ANTENNAPARTIALMETALAREA        0.11990         LAYER MET1 ;
  ANTENNAPARTIALMETALAREA        2.04550         LAYER MET2 ;
  ANTENNAMAXAREACAR              1.05714         LAYER MET1 ;
  ANTENNAMAXAREACAR              34.69683        LAYER MET2 ;
  ANTENNAMAXAREACAR              35.86825        LAYER MET3 ;
END A[2]
PIN A[3]
  DIRECTION INPUT ;
  PORT
    LAYER MET1 ;
    RECT 293.275 0.000 293.685 0.180 ;
    LAYER MET2 ;
    RECT 293.275 0.000 293.685 0.180 ;
    LAYER MET3 ;
    RECT 293.275 0.000 293.685 0.180 ;
  END
  ANTENNADIFFAREA                0.43130         LAYER MET1 ;
  ANTENNADIFFAREA                0.43130         LAYER MET2 ;
  ANTENNADIFFAREA                0.43130         LAYER MET3 ;
  ANTENNAGATEAREA                0.06300         LAYER MET1 ;
  ANTENNAGATEAREA                0.06300         LAYER MET2 ;
  ANTENNAGATEAREA                0.06300         LAYER MET3 ;
  ANTENNAPARTIALMETALAREA        0.09890         LAYER MET1 ;
  ANTENNAPARTIALMETALAREA        2.09300         LAYER MET2 ;
  ANTENNAMAXAREACAR              0.72381         LAYER MET1 ;
  ANTENNAMAXAREACAR              35.11746        LAYER MET2 ;
  ANTENNAMAXAREACAR              36.28889        LAYER MET3 ;
END A[3]
PIN A[4]
  DIRECTION INPUT ;
  PORT
    LAYER MET1 ;
    RECT 278.085 0.000 278.495 0.180 ;
    LAYER MET2 ;
    RECT 278.085 0.000 278.495 0.180 ;
    LAYER MET3 ;
    RECT 278.085 0.000 278.495 0.180 ;
  END
  ANTENNADIFFAREA                0.68330         LAYER MET1 ;
  ANTENNADIFFAREA                0.68330         LAYER MET2 ;
  ANTENNADIFFAREA                0.68330         LAYER MET3 ;
  ANTENNAGATEAREA                0.06300         LAYER MET1 ;
  ANTENNAGATEAREA                0.06300         LAYER MET2 ;
  ANTENNAGATEAREA                0.06300         LAYER MET3 ;
  ANTENNAPARTIALMETALAREA        0.09890         LAYER MET1 ;
  ANTENNAPARTIALMETALAREA        2.08200         LAYER MET2 ;
  ANTENNAMAXAREACAR              0.72381         LAYER MET1 ;
  ANTENNAMAXAREACAR              34.94286        LAYER MET2 ;
  ANTENNAMAXAREACAR              36.11429        LAYER MET3 ;
END A[4]
PIN A[5]
  DIRECTION INPUT ;
  PORT
    LAYER MET1 ;
    RECT 280.865 0.000 281.275 0.180 ;
    LAYER MET2 ;
    RECT 280.865 0.000 281.275 0.180 ;
    LAYER MET3 ;
    RECT 280.865 0.000 281.275 0.180 ;
  END
  ANTENNADIFFAREA                0.43130         LAYER MET1 ;
  ANTENNADIFFAREA                0.43130         LAYER MET2 ;
  ANTENNADIFFAREA                0.43130         LAYER MET3 ;
  ANTENNAGATEAREA                0.06300         LAYER MET1 ;
  ANTENNAGATEAREA                0.06300         LAYER MET2 ;
  ANTENNAGATEAREA                0.06300         LAYER MET3 ;
  ANTENNAPARTIALMETALAREA        0.17870         LAYER MET1 ;
  ANTENNAPARTIALMETALAREA        1.26000         LAYER MET2 ;
  ANTENNAMAXAREACAR              1.99048         LAYER MET1 ;
  ANTENNAMAXAREACAR              23.16190        LAYER MET2 ;
  ANTENNAMAXAREACAR              24.33333        LAYER MET3 ;
END A[5]
PIN A[6]
  DIRECTION INPUT ;
  PORT
    LAYER MET1 ;
    RECT 278.615 0.000 279.025 0.180 ;
    LAYER MET2 ;
    RECT 278.615 0.000 279.025 0.180 ;
    LAYER MET3 ;
    RECT 278.615 0.000 279.025 0.180 ;
  END
  ANTENNADIFFAREA                0.68330         LAYER MET1 ;
  ANTENNADIFFAREA                0.68330         LAYER MET2 ;
  ANTENNADIFFAREA                0.68330         LAYER MET3 ;
  ANTENNAGATEAREA                0.06300         LAYER MET1 ;
  ANTENNAGATEAREA                0.06300         LAYER MET2 ;
  ANTENNAGATEAREA                0.06300         LAYER MET3 ;
  ANTENNAPARTIALMETALAREA        0.09890         LAYER MET1 ;
  ANTENNAPARTIALMETALAREA        1.99560         LAYER MET2 ;
  ANTENNAMAXAREACAR              0.72381         LAYER MET1 ;
  ANTENNAMAXAREACAR              33.57143        LAYER MET2 ;
  ANTENNAMAXAREACAR              34.74286        LAYER MET3 ;
END A[6]
PIN A[7]
  DIRECTION INPUT ;
  PORT
    LAYER MET1 ;
    RECT 276.480 0.000 276.890 0.180 ;
    LAYER MET2 ;
    RECT 276.480 0.000 276.890 0.180 ;
    LAYER MET3 ;
    RECT 276.480 0.000 276.890 0.180 ;
  END
  ANTENNADIFFAREA                0.43130         LAYER MET1 ;
  ANTENNADIFFAREA                0.43130         LAYER MET2 ;
  ANTENNADIFFAREA                0.43130         LAYER MET3 ;
  ANTENNAGATEAREA                0.06300         LAYER MET1 ;
  ANTENNAGATEAREA                0.06300         LAYER MET2 ;
  ANTENNAGATEAREA                0.06300         LAYER MET3 ;
  ANTENNAPARTIALMETALAREA        0.14330         LAYER MET1 ;
  ANTENNAPARTIALMETALAREA        2.29080         LAYER MET2 ;
  ANTENNAMAXAREACAR              1.42857         LAYER MET1 ;
  ANTENNAMAXAREACAR              38.96190        LAYER MET2 ;
  ANTENNAMAXAREACAR              40.13333        LAYER MET3 ;
END A[7]
PIN D[64]
  DIRECTION INPUT ;
  PORT
    LAYER MET1 ;
    RECT 300.690 0.000 301.100 0.180 ;
    LAYER MET2 ;
    RECT 300.690 0.000 301.100 0.180 ;
    LAYER MET3 ;
    RECT 300.690 0.000 301.100 0.180 ;
  END
  ANTENNADIFFAREA                0.38930         LAYER MET1 ;
  ANTENNADIFFAREA                0.38930         LAYER MET2 ;
  ANTENNADIFFAREA                0.38930         LAYER MET3 ;
  ANTENNAGATEAREA                0.06300         LAYER MET1 ;
  ANTENNAGATEAREA                0.06300         LAYER MET2 ;
  ANTENNAGATEAREA                0.06300         LAYER MET3 ;
  ANTENNAPARTIALMETALAREA        0.09890         LAYER MET1 ;
  ANTENNAPARTIALMETALAREA        0.10380         LAYER MET2 ;
  ANTENNAMAXAREACAR              0.72381         LAYER MET1 ;
  ANTENNAMAXAREACAR              3.54286         LAYER MET2 ;
  ANTENNAMAXAREACAR              4.71429         LAYER MET3 ;
END D[64]
PIN Q[64]
  DIRECTION OUTPUT ;
  PORT
    LAYER MET1 ;
    RECT 299.150 0.000 299.560 0.180 ;
    LAYER MET2 ;
    RECT 299.150 0.000 299.560 0.180 ;
    LAYER MET3 ;
    RECT 299.150 0.000 299.560 0.180 ;
  END
  ANTENNADIFFAREA                0.60000         LAYER MET1 ;
  ANTENNADIFFAREA                0.60000         LAYER MET2 ;
  ANTENNADIFFAREA                0.60000         LAYER MET3 ;
  ANTENNAPARTIALMETALAREA        0.94400         LAYER MET1 ;
  ANTENNAPARTIALMETALAREA        1.33320         LAYER MET2 ;
END Q[64]
PIN D[65]
  DIRECTION INPUT ;
  PORT
    LAYER MET1 ;
    RECT 304.890 0.000 305.300 0.180 ;
    LAYER MET2 ;
    RECT 304.890 0.000 305.300 0.180 ;
    LAYER MET3 ;
    RECT 304.890 0.000 305.300 0.180 ;
  END
  ANTENNADIFFAREA                0.38930         LAYER MET1 ;
  ANTENNADIFFAREA                0.38930         LAYER MET2 ;
  ANTENNADIFFAREA                0.38930         LAYER MET3 ;
  ANTENNAGATEAREA                0.06300         LAYER MET1 ;
  ANTENNAGATEAREA                0.06300         LAYER MET2 ;
  ANTENNAGATEAREA                0.06300         LAYER MET3 ;
  ANTENNAPARTIALMETALAREA        0.09890         LAYER MET1 ;
  ANTENNAPARTIALMETALAREA        0.10380         LAYER MET2 ;
  ANTENNAMAXAREACAR              0.72381         LAYER MET1 ;
  ANTENNAMAXAREACAR              3.54286         LAYER MET2 ;
  ANTENNAMAXAREACAR              4.71429         LAYER MET3 ;
END D[65]
PIN Q[65]
  DIRECTION OUTPUT ;
  PORT
    LAYER MET1 ;
    RECT 303.350 0.000 303.760 0.180 ;
    LAYER MET2 ;
    RECT 303.350 0.000 303.760 0.180 ;
    LAYER MET3 ;
    RECT 303.350 0.000 303.760 0.180 ;
  END
  ANTENNADIFFAREA                0.60000         LAYER MET1 ;
  ANTENNADIFFAREA                0.60000         LAYER MET2 ;
  ANTENNADIFFAREA                0.60000         LAYER MET3 ;
  ANTENNAPARTIALMETALAREA        0.94400         LAYER MET1 ;
  ANTENNAPARTIALMETALAREA        1.33320         LAYER MET2 ;
END Q[65]
PIN D[66]
  DIRECTION INPUT ;
  PORT
    LAYER MET1 ;
    RECT 309.090 0.000 309.500 0.180 ;
    LAYER MET2 ;
    RECT 309.090 0.000 309.500 0.180 ;
    LAYER MET3 ;
    RECT 309.090 0.000 309.500 0.180 ;
  END
  ANTENNADIFFAREA                0.38930         LAYER MET1 ;
  ANTENNADIFFAREA                0.38930         LAYER MET2 ;
  ANTENNADIFFAREA                0.38930         LAYER MET3 ;
  ANTENNAGATEAREA                0.06300         LAYER MET1 ;
  ANTENNAGATEAREA                0.06300         LAYER MET2 ;
  ANTENNAGATEAREA                0.06300         LAYER MET3 ;
  ANTENNAPARTIALMETALAREA        0.09890         LAYER MET1 ;
  ANTENNAPARTIALMETALAREA        0.10380         LAYER MET2 ;
  ANTENNAMAXAREACAR              0.72381         LAYER MET1 ;
  ANTENNAMAXAREACAR              3.54286         LAYER MET2 ;
  ANTENNAMAXAREACAR              4.71429         LAYER MET3 ;
END D[66]
PIN Q[66]
  DIRECTION OUTPUT ;
  PORT
    LAYER MET1 ;
    RECT 307.550 0.000 307.960 0.180 ;
    LAYER MET2 ;
    RECT 307.550 0.000 307.960 0.180 ;
    LAYER MET3 ;
    RECT 307.550 0.000 307.960 0.180 ;
  END
  ANTENNADIFFAREA                0.60000         LAYER MET1 ;
  ANTENNADIFFAREA                0.60000         LAYER MET2 ;
  ANTENNADIFFAREA                0.60000         LAYER MET3 ;
  ANTENNAPARTIALMETALAREA        0.94400         LAYER MET1 ;
  ANTENNAPARTIALMETALAREA        1.33320         LAYER MET2 ;
END Q[66]
PIN D[67]
  DIRECTION INPUT ;
  PORT
    LAYER MET1 ;
    RECT 313.290 0.000 313.700 0.180 ;
    LAYER MET2 ;
    RECT 313.290 0.000 313.700 0.180 ;
    LAYER MET3 ;
    RECT 313.290 0.000 313.700 0.180 ;
  END
  ANTENNADIFFAREA                0.38930         LAYER MET1 ;
  ANTENNADIFFAREA                0.38930         LAYER MET2 ;
  ANTENNADIFFAREA                0.38930         LAYER MET3 ;
  ANTENNAGATEAREA                0.06300         LAYER MET1 ;
  ANTENNAGATEAREA                0.06300         LAYER MET2 ;
  ANTENNAGATEAREA                0.06300         LAYER MET3 ;
  ANTENNAPARTIALMETALAREA        0.09890         LAYER MET1 ;
  ANTENNAPARTIALMETALAREA        0.10380         LAYER MET2 ;
  ANTENNAMAXAREACAR              0.72381         LAYER MET1 ;
  ANTENNAMAXAREACAR              3.54286         LAYER MET2 ;
  ANTENNAMAXAREACAR              4.71429         LAYER MET3 ;
END D[67]
PIN Q[67]
  DIRECTION OUTPUT ;
  PORT
    LAYER MET1 ;
    RECT 311.750 0.000 312.160 0.180 ;
    LAYER MET2 ;
    RECT 311.750 0.000 312.160 0.180 ;
    LAYER MET3 ;
    RECT 311.750 0.000 312.160 0.180 ;
  END
  ANTENNADIFFAREA                0.60000         LAYER MET1 ;
  ANTENNADIFFAREA                0.60000         LAYER MET2 ;
  ANTENNADIFFAREA                0.60000         LAYER MET3 ;
  ANTENNAPARTIALMETALAREA        0.94400         LAYER MET1 ;
  ANTENNAPARTIALMETALAREA        1.33320         LAYER MET2 ;
END Q[67]
PIN D[68]
  DIRECTION INPUT ;
  PORT
    LAYER MET1 ;
    RECT 317.490 0.000 317.900 0.180 ;
    LAYER MET2 ;
    RECT 317.490 0.000 317.900 0.180 ;
    LAYER MET3 ;
    RECT 317.490 0.000 317.900 0.180 ;
  END
  ANTENNADIFFAREA                0.38930         LAYER MET1 ;
  ANTENNADIFFAREA                0.38930         LAYER MET2 ;
  ANTENNADIFFAREA                0.38930         LAYER MET3 ;
  ANTENNAGATEAREA                0.06300         LAYER MET1 ;
  ANTENNAGATEAREA                0.06300         LAYER MET2 ;
  ANTENNAGATEAREA                0.06300         LAYER MET3 ;
  ANTENNAPARTIALMETALAREA        0.09890         LAYER MET1 ;
  ANTENNAPARTIALMETALAREA        0.10380         LAYER MET2 ;
  ANTENNAMAXAREACAR              0.72381         LAYER MET1 ;
  ANTENNAMAXAREACAR              3.54286         LAYER MET2 ;
  ANTENNAMAXAREACAR              4.71429         LAYER MET3 ;
END D[68]
PIN Q[68]
  DIRECTION OUTPUT ;
  PORT
    LAYER MET1 ;
    RECT 315.950 0.000 316.360 0.180 ;
    LAYER MET2 ;
    RECT 315.950 0.000 316.360 0.180 ;
    LAYER MET3 ;
    RECT 315.950 0.000 316.360 0.180 ;
  END
  ANTENNADIFFAREA                0.60000         LAYER MET1 ;
  ANTENNADIFFAREA                0.60000         LAYER MET2 ;
  ANTENNADIFFAREA                0.60000         LAYER MET3 ;
  ANTENNAPARTIALMETALAREA        0.94400         LAYER MET1 ;
  ANTENNAPARTIALMETALAREA        1.33320         LAYER MET2 ;
END Q[68]
PIN D[69]
  DIRECTION INPUT ;
  PORT
    LAYER MET1 ;
    RECT 321.690 0.000 322.100 0.180 ;
    LAYER MET2 ;
    RECT 321.690 0.000 322.100 0.180 ;
    LAYER MET3 ;
    RECT 321.690 0.000 322.100 0.180 ;
  END
  ANTENNADIFFAREA                0.38930         LAYER MET1 ;
  ANTENNADIFFAREA                0.38930         LAYER MET2 ;
  ANTENNADIFFAREA                0.38930         LAYER MET3 ;
  ANTENNAGATEAREA                0.06300         LAYER MET1 ;
  ANTENNAGATEAREA                0.06300         LAYER MET2 ;
  ANTENNAGATEAREA                0.06300         LAYER MET3 ;
  ANTENNAPARTIALMETALAREA        0.09890         LAYER MET1 ;
  ANTENNAPARTIALMETALAREA        0.10380         LAYER MET2 ;
  ANTENNAMAXAREACAR              0.72381         LAYER MET1 ;
  ANTENNAMAXAREACAR              3.54286         LAYER MET2 ;
  ANTENNAMAXAREACAR              4.71429         LAYER MET3 ;
END D[69]
PIN Q[69]
  DIRECTION OUTPUT ;
  PORT
    LAYER MET1 ;
    RECT 320.150 0.000 320.560 0.180 ;
    LAYER MET2 ;
    RECT 320.150 0.000 320.560 0.180 ;
    LAYER MET3 ;
    RECT 320.150 0.000 320.560 0.180 ;
  END
  ANTENNADIFFAREA                0.60000         LAYER MET1 ;
  ANTENNADIFFAREA                0.60000         LAYER MET2 ;
  ANTENNADIFFAREA                0.60000         LAYER MET3 ;
  ANTENNAPARTIALMETALAREA        0.94400         LAYER MET1 ;
  ANTENNAPARTIALMETALAREA        1.33320         LAYER MET2 ;
END Q[69]
PIN D[70]
  DIRECTION INPUT ;
  PORT
    LAYER MET1 ;
    RECT 325.890 0.000 326.300 0.180 ;
    LAYER MET2 ;
    RECT 325.890 0.000 326.300 0.180 ;
    LAYER MET3 ;
    RECT 325.890 0.000 326.300 0.180 ;
  END
  ANTENNADIFFAREA                0.38930         LAYER MET1 ;
  ANTENNADIFFAREA                0.38930         LAYER MET2 ;
  ANTENNADIFFAREA                0.38930         LAYER MET3 ;
  ANTENNAGATEAREA                0.06300         LAYER MET1 ;
  ANTENNAGATEAREA                0.06300         LAYER MET2 ;
  ANTENNAGATEAREA                0.06300         LAYER MET3 ;
  ANTENNAPARTIALMETALAREA        0.09890         LAYER MET1 ;
  ANTENNAPARTIALMETALAREA        0.10380         LAYER MET2 ;
  ANTENNAMAXAREACAR              0.72381         LAYER MET1 ;
  ANTENNAMAXAREACAR              3.54286         LAYER MET2 ;
  ANTENNAMAXAREACAR              4.71429         LAYER MET3 ;
END D[70]
PIN Q[70]
  DIRECTION OUTPUT ;
  PORT
    LAYER MET1 ;
    RECT 324.350 0.000 324.760 0.180 ;
    LAYER MET2 ;
    RECT 324.350 0.000 324.760 0.180 ;
    LAYER MET3 ;
    RECT 324.350 0.000 324.760 0.180 ;
  END
  ANTENNADIFFAREA                0.60000         LAYER MET1 ;
  ANTENNADIFFAREA                0.60000         LAYER MET2 ;
  ANTENNADIFFAREA                0.60000         LAYER MET3 ;
  ANTENNAPARTIALMETALAREA        0.94400         LAYER MET1 ;
  ANTENNAPARTIALMETALAREA        1.33320         LAYER MET2 ;
END Q[70]
PIN D[71]
  DIRECTION INPUT ;
  PORT
    LAYER MET1 ;
    RECT 330.090 0.000 330.500 0.180 ;
    LAYER MET2 ;
    RECT 330.090 0.000 330.500 0.180 ;
    LAYER MET3 ;
    RECT 330.090 0.000 330.500 0.180 ;
  END
  ANTENNADIFFAREA                0.38930         LAYER MET1 ;
  ANTENNADIFFAREA                0.38930         LAYER MET2 ;
  ANTENNADIFFAREA                0.38930         LAYER MET3 ;
  ANTENNAGATEAREA                0.06300         LAYER MET1 ;
  ANTENNAGATEAREA                0.06300         LAYER MET2 ;
  ANTENNAGATEAREA                0.06300         LAYER MET3 ;
  ANTENNAPARTIALMETALAREA        0.09890         LAYER MET1 ;
  ANTENNAPARTIALMETALAREA        0.10380         LAYER MET2 ;
  ANTENNAMAXAREACAR              0.72381         LAYER MET1 ;
  ANTENNAMAXAREACAR              3.54286         LAYER MET2 ;
  ANTENNAMAXAREACAR              4.71429         LAYER MET3 ;
END D[71]
PIN Q[71]
  DIRECTION OUTPUT ;
  PORT
    LAYER MET1 ;
    RECT 328.550 0.000 328.960 0.180 ;
    LAYER MET2 ;
    RECT 328.550 0.000 328.960 0.180 ;
    LAYER MET3 ;
    RECT 328.550 0.000 328.960 0.180 ;
  END
  ANTENNADIFFAREA                0.60000         LAYER MET1 ;
  ANTENNADIFFAREA                0.60000         LAYER MET2 ;
  ANTENNADIFFAREA                0.60000         LAYER MET3 ;
  ANTENNAPARTIALMETALAREA        0.94400         LAYER MET1 ;
  ANTENNAPARTIALMETALAREA        1.33320         LAYER MET2 ;
END Q[71]
PIN D[72]
  DIRECTION INPUT ;
  PORT
    LAYER MET1 ;
    RECT 334.290 0.000 334.700 0.180 ;
    LAYER MET2 ;
    RECT 334.290 0.000 334.700 0.180 ;
    LAYER MET3 ;
    RECT 334.290 0.000 334.700 0.180 ;
  END
  ANTENNADIFFAREA                0.38930         LAYER MET1 ;
  ANTENNADIFFAREA                0.38930         LAYER MET2 ;
  ANTENNADIFFAREA                0.38930         LAYER MET3 ;
  ANTENNAGATEAREA                0.06300         LAYER MET1 ;
  ANTENNAGATEAREA                0.06300         LAYER MET2 ;
  ANTENNAGATEAREA                0.06300         LAYER MET3 ;
  ANTENNAPARTIALMETALAREA        0.09890         LAYER MET1 ;
  ANTENNAPARTIALMETALAREA        0.10380         LAYER MET2 ;
  ANTENNAMAXAREACAR              0.72381         LAYER MET1 ;
  ANTENNAMAXAREACAR              3.54286         LAYER MET2 ;
  ANTENNAMAXAREACAR              4.71429         LAYER MET3 ;
END D[72]
PIN Q[72]
  DIRECTION OUTPUT ;
  PORT
    LAYER MET1 ;
    RECT 332.750 0.000 333.160 0.180 ;
    LAYER MET2 ;
    RECT 332.750 0.000 333.160 0.180 ;
    LAYER MET3 ;
    RECT 332.750 0.000 333.160 0.180 ;
  END
  ANTENNADIFFAREA                0.60000         LAYER MET1 ;
  ANTENNADIFFAREA                0.60000         LAYER MET2 ;
  ANTENNADIFFAREA                0.60000         LAYER MET3 ;
  ANTENNAPARTIALMETALAREA        0.94400         LAYER MET1 ;
  ANTENNAPARTIALMETALAREA        1.33320         LAYER MET2 ;
END Q[72]
PIN D[73]
  DIRECTION INPUT ;
  PORT
    LAYER MET1 ;
    RECT 338.490 0.000 338.900 0.180 ;
    LAYER MET2 ;
    RECT 338.490 0.000 338.900 0.180 ;
    LAYER MET3 ;
    RECT 338.490 0.000 338.900 0.180 ;
  END
  ANTENNADIFFAREA                0.38930         LAYER MET1 ;
  ANTENNADIFFAREA                0.38930         LAYER MET2 ;
  ANTENNADIFFAREA                0.38930         LAYER MET3 ;
  ANTENNAGATEAREA                0.06300         LAYER MET1 ;
  ANTENNAGATEAREA                0.06300         LAYER MET2 ;
  ANTENNAGATEAREA                0.06300         LAYER MET3 ;
  ANTENNAPARTIALMETALAREA        0.09890         LAYER MET1 ;
  ANTENNAPARTIALMETALAREA        0.10380         LAYER MET2 ;
  ANTENNAMAXAREACAR              0.72381         LAYER MET1 ;
  ANTENNAMAXAREACAR              3.54286         LAYER MET2 ;
  ANTENNAMAXAREACAR              4.71429         LAYER MET3 ;
END D[73]
PIN Q[73]
  DIRECTION OUTPUT ;
  PORT
    LAYER MET1 ;
    RECT 336.950 0.000 337.360 0.180 ;
    LAYER MET2 ;
    RECT 336.950 0.000 337.360 0.180 ;
    LAYER MET3 ;
    RECT 336.950 0.000 337.360 0.180 ;
  END
  ANTENNADIFFAREA                0.60000         LAYER MET1 ;
  ANTENNADIFFAREA                0.60000         LAYER MET2 ;
  ANTENNADIFFAREA                0.60000         LAYER MET3 ;
  ANTENNAPARTIALMETALAREA        0.94400         LAYER MET1 ;
  ANTENNAPARTIALMETALAREA        1.33320         LAYER MET2 ;
END Q[73]
PIN D[74]
  DIRECTION INPUT ;
  PORT
    LAYER MET1 ;
    RECT 342.690 0.000 343.100 0.180 ;
    LAYER MET2 ;
    RECT 342.690 0.000 343.100 0.180 ;
    LAYER MET3 ;
    RECT 342.690 0.000 343.100 0.180 ;
  END
  ANTENNADIFFAREA                0.38930         LAYER MET1 ;
  ANTENNADIFFAREA                0.38930         LAYER MET2 ;
  ANTENNADIFFAREA                0.38930         LAYER MET3 ;
  ANTENNAGATEAREA                0.06300         LAYER MET1 ;
  ANTENNAGATEAREA                0.06300         LAYER MET2 ;
  ANTENNAGATEAREA                0.06300         LAYER MET3 ;
  ANTENNAPARTIALMETALAREA        0.09890         LAYER MET1 ;
  ANTENNAPARTIALMETALAREA        0.10380         LAYER MET2 ;
  ANTENNAMAXAREACAR              0.72381         LAYER MET1 ;
  ANTENNAMAXAREACAR              3.54286         LAYER MET2 ;
  ANTENNAMAXAREACAR              4.71429         LAYER MET3 ;
END D[74]
PIN Q[74]
  DIRECTION OUTPUT ;
  PORT
    LAYER MET1 ;
    RECT 341.150 0.000 341.560 0.180 ;
    LAYER MET2 ;
    RECT 341.150 0.000 341.560 0.180 ;
    LAYER MET3 ;
    RECT 341.150 0.000 341.560 0.180 ;
  END
  ANTENNADIFFAREA                0.60000         LAYER MET1 ;
  ANTENNADIFFAREA                0.60000         LAYER MET2 ;
  ANTENNADIFFAREA                0.60000         LAYER MET3 ;
  ANTENNAPARTIALMETALAREA        0.94400         LAYER MET1 ;
  ANTENNAPARTIALMETALAREA        1.33320         LAYER MET2 ;
END Q[74]
PIN D[75]
  DIRECTION INPUT ;
  PORT
    LAYER MET1 ;
    RECT 346.890 0.000 347.300 0.180 ;
    LAYER MET2 ;
    RECT 346.890 0.000 347.300 0.180 ;
    LAYER MET3 ;
    RECT 346.890 0.000 347.300 0.180 ;
  END
  ANTENNADIFFAREA                0.38930         LAYER MET1 ;
  ANTENNADIFFAREA                0.38930         LAYER MET2 ;
  ANTENNADIFFAREA                0.38930         LAYER MET3 ;
  ANTENNAGATEAREA                0.06300         LAYER MET1 ;
  ANTENNAGATEAREA                0.06300         LAYER MET2 ;
  ANTENNAGATEAREA                0.06300         LAYER MET3 ;
  ANTENNAPARTIALMETALAREA        0.09890         LAYER MET1 ;
  ANTENNAPARTIALMETALAREA        0.10380         LAYER MET2 ;
  ANTENNAMAXAREACAR              0.72381         LAYER MET1 ;
  ANTENNAMAXAREACAR              3.54286         LAYER MET2 ;
  ANTENNAMAXAREACAR              4.71429         LAYER MET3 ;
END D[75]
PIN Q[75]
  DIRECTION OUTPUT ;
  PORT
    LAYER MET1 ;
    RECT 345.350 0.000 345.760 0.180 ;
    LAYER MET2 ;
    RECT 345.350 0.000 345.760 0.180 ;
    LAYER MET3 ;
    RECT 345.350 0.000 345.760 0.180 ;
  END
  ANTENNADIFFAREA                0.60000         LAYER MET1 ;
  ANTENNADIFFAREA                0.60000         LAYER MET2 ;
  ANTENNADIFFAREA                0.60000         LAYER MET3 ;
  ANTENNAPARTIALMETALAREA        0.94400         LAYER MET1 ;
  ANTENNAPARTIALMETALAREA        1.33320         LAYER MET2 ;
END Q[75]
PIN D[76]
  DIRECTION INPUT ;
  PORT
    LAYER MET1 ;
    RECT 351.090 0.000 351.500 0.180 ;
    LAYER MET2 ;
    RECT 351.090 0.000 351.500 0.180 ;
    LAYER MET3 ;
    RECT 351.090 0.000 351.500 0.180 ;
  END
  ANTENNADIFFAREA                0.38930         LAYER MET1 ;
  ANTENNADIFFAREA                0.38930         LAYER MET2 ;
  ANTENNADIFFAREA                0.38930         LAYER MET3 ;
  ANTENNAGATEAREA                0.06300         LAYER MET1 ;
  ANTENNAGATEAREA                0.06300         LAYER MET2 ;
  ANTENNAGATEAREA                0.06300         LAYER MET3 ;
  ANTENNAPARTIALMETALAREA        0.09890         LAYER MET1 ;
  ANTENNAPARTIALMETALAREA        0.10380         LAYER MET2 ;
  ANTENNAMAXAREACAR              0.72381         LAYER MET1 ;
  ANTENNAMAXAREACAR              3.54286         LAYER MET2 ;
  ANTENNAMAXAREACAR              4.71429         LAYER MET3 ;
END D[76]
PIN Q[76]
  DIRECTION OUTPUT ;
  PORT
    LAYER MET1 ;
    RECT 349.550 0.000 349.960 0.180 ;
    LAYER MET2 ;
    RECT 349.550 0.000 349.960 0.180 ;
    LAYER MET3 ;
    RECT 349.550 0.000 349.960 0.180 ;
  END
  ANTENNADIFFAREA                0.60000         LAYER MET1 ;
  ANTENNADIFFAREA                0.60000         LAYER MET2 ;
  ANTENNADIFFAREA                0.60000         LAYER MET3 ;
  ANTENNAPARTIALMETALAREA        0.94400         LAYER MET1 ;
  ANTENNAPARTIALMETALAREA        1.33320         LAYER MET2 ;
END Q[76]
PIN D[77]
  DIRECTION INPUT ;
  PORT
    LAYER MET1 ;
    RECT 355.290 0.000 355.700 0.180 ;
    LAYER MET2 ;
    RECT 355.290 0.000 355.700 0.180 ;
    LAYER MET3 ;
    RECT 355.290 0.000 355.700 0.180 ;
  END
  ANTENNADIFFAREA                0.38930         LAYER MET1 ;
  ANTENNADIFFAREA                0.38930         LAYER MET2 ;
  ANTENNADIFFAREA                0.38930         LAYER MET3 ;
  ANTENNAGATEAREA                0.06300         LAYER MET1 ;
  ANTENNAGATEAREA                0.06300         LAYER MET2 ;
  ANTENNAGATEAREA                0.06300         LAYER MET3 ;
  ANTENNAPARTIALMETALAREA        0.09890         LAYER MET1 ;
  ANTENNAPARTIALMETALAREA        0.10380         LAYER MET2 ;
  ANTENNAMAXAREACAR              0.72381         LAYER MET1 ;
  ANTENNAMAXAREACAR              3.54286         LAYER MET2 ;
  ANTENNAMAXAREACAR              4.71429         LAYER MET3 ;
END D[77]
PIN Q[77]
  DIRECTION OUTPUT ;
  PORT
    LAYER MET1 ;
    RECT 353.750 0.000 354.160 0.180 ;
    LAYER MET2 ;
    RECT 353.750 0.000 354.160 0.180 ;
    LAYER MET3 ;
    RECT 353.750 0.000 354.160 0.180 ;
  END
  ANTENNADIFFAREA                0.60000         LAYER MET1 ;
  ANTENNADIFFAREA                0.60000         LAYER MET2 ;
  ANTENNADIFFAREA                0.60000         LAYER MET3 ;
  ANTENNAPARTIALMETALAREA        0.94400         LAYER MET1 ;
  ANTENNAPARTIALMETALAREA        1.33320         LAYER MET2 ;
END Q[77]
PIN D[78]
  DIRECTION INPUT ;
  PORT
    LAYER MET1 ;
    RECT 359.490 0.000 359.900 0.180 ;
    LAYER MET2 ;
    RECT 359.490 0.000 359.900 0.180 ;
    LAYER MET3 ;
    RECT 359.490 0.000 359.900 0.180 ;
  END
  ANTENNADIFFAREA                0.38930         LAYER MET1 ;
  ANTENNADIFFAREA                0.38930         LAYER MET2 ;
  ANTENNADIFFAREA                0.38930         LAYER MET3 ;
  ANTENNAGATEAREA                0.06300         LAYER MET1 ;
  ANTENNAGATEAREA                0.06300         LAYER MET2 ;
  ANTENNAGATEAREA                0.06300         LAYER MET3 ;
  ANTENNAPARTIALMETALAREA        0.09890         LAYER MET1 ;
  ANTENNAPARTIALMETALAREA        0.10380         LAYER MET2 ;
  ANTENNAMAXAREACAR              0.72381         LAYER MET1 ;
  ANTENNAMAXAREACAR              3.54286         LAYER MET2 ;
  ANTENNAMAXAREACAR              4.71429         LAYER MET3 ;
END D[78]
PIN Q[78]
  DIRECTION OUTPUT ;
  PORT
    LAYER MET1 ;
    RECT 357.950 0.000 358.360 0.180 ;
    LAYER MET2 ;
    RECT 357.950 0.000 358.360 0.180 ;
    LAYER MET3 ;
    RECT 357.950 0.000 358.360 0.180 ;
  END
  ANTENNADIFFAREA                0.60000         LAYER MET1 ;
  ANTENNADIFFAREA                0.60000         LAYER MET2 ;
  ANTENNADIFFAREA                0.60000         LAYER MET3 ;
  ANTENNAPARTIALMETALAREA        0.94400         LAYER MET1 ;
  ANTENNAPARTIALMETALAREA        1.33320         LAYER MET2 ;
END Q[78]
PIN D[79]
  DIRECTION INPUT ;
  PORT
    LAYER MET1 ;
    RECT 363.690 0.000 364.100 0.180 ;
    LAYER MET2 ;
    RECT 363.690 0.000 364.100 0.180 ;
    LAYER MET3 ;
    RECT 363.690 0.000 364.100 0.180 ;
  END
  ANTENNADIFFAREA                0.38930         LAYER MET1 ;
  ANTENNADIFFAREA                0.38930         LAYER MET2 ;
  ANTENNADIFFAREA                0.38930         LAYER MET3 ;
  ANTENNAGATEAREA                0.06300         LAYER MET1 ;
  ANTENNAGATEAREA                0.06300         LAYER MET2 ;
  ANTENNAGATEAREA                0.06300         LAYER MET3 ;
  ANTENNAPARTIALMETALAREA        0.09890         LAYER MET1 ;
  ANTENNAPARTIALMETALAREA        0.10380         LAYER MET2 ;
  ANTENNAMAXAREACAR              0.72381         LAYER MET1 ;
  ANTENNAMAXAREACAR              3.54286         LAYER MET2 ;
  ANTENNAMAXAREACAR              4.71429         LAYER MET3 ;
END D[79]
PIN Q[79]
  DIRECTION OUTPUT ;
  PORT
    LAYER MET1 ;
    RECT 362.150 0.000 362.560 0.180 ;
    LAYER MET2 ;
    RECT 362.150 0.000 362.560 0.180 ;
    LAYER MET3 ;
    RECT 362.150 0.000 362.560 0.180 ;
  END
  ANTENNADIFFAREA                0.60000         LAYER MET1 ;
  ANTENNADIFFAREA                0.60000         LAYER MET2 ;
  ANTENNADIFFAREA                0.60000         LAYER MET3 ;
  ANTENNAPARTIALMETALAREA        0.94400         LAYER MET1 ;
  ANTENNAPARTIALMETALAREA        1.33320         LAYER MET2 ;
END Q[79]
PIN D[80]
  DIRECTION INPUT ;
  PORT
    LAYER MET1 ;
    RECT 367.890 0.000 368.300 0.180 ;
    LAYER MET2 ;
    RECT 367.890 0.000 368.300 0.180 ;
    LAYER MET3 ;
    RECT 367.890 0.000 368.300 0.180 ;
  END
  ANTENNADIFFAREA                0.38930         LAYER MET1 ;
  ANTENNADIFFAREA                0.38930         LAYER MET2 ;
  ANTENNADIFFAREA                0.38930         LAYER MET3 ;
  ANTENNAGATEAREA                0.06300         LAYER MET1 ;
  ANTENNAGATEAREA                0.06300         LAYER MET2 ;
  ANTENNAGATEAREA                0.06300         LAYER MET3 ;
  ANTENNAPARTIALMETALAREA        0.09890         LAYER MET1 ;
  ANTENNAPARTIALMETALAREA        0.10380         LAYER MET2 ;
  ANTENNAMAXAREACAR              0.72381         LAYER MET1 ;
  ANTENNAMAXAREACAR              3.54286         LAYER MET2 ;
  ANTENNAMAXAREACAR              4.71429         LAYER MET3 ;
END D[80]
PIN Q[80]
  DIRECTION OUTPUT ;
  PORT
    LAYER MET1 ;
    RECT 366.350 0.000 366.760 0.180 ;
    LAYER MET2 ;
    RECT 366.350 0.000 366.760 0.180 ;
    LAYER MET3 ;
    RECT 366.350 0.000 366.760 0.180 ;
  END
  ANTENNADIFFAREA                0.60000         LAYER MET1 ;
  ANTENNADIFFAREA                0.60000         LAYER MET2 ;
  ANTENNADIFFAREA                0.60000         LAYER MET3 ;
  ANTENNAPARTIALMETALAREA        0.94400         LAYER MET1 ;
  ANTENNAPARTIALMETALAREA        1.33320         LAYER MET2 ;
END Q[80]
PIN D[81]
  DIRECTION INPUT ;
  PORT
    LAYER MET1 ;
    RECT 372.090 0.000 372.500 0.180 ;
    LAYER MET2 ;
    RECT 372.090 0.000 372.500 0.180 ;
    LAYER MET3 ;
    RECT 372.090 0.000 372.500 0.180 ;
  END
  ANTENNADIFFAREA                0.38930         LAYER MET1 ;
  ANTENNADIFFAREA                0.38930         LAYER MET2 ;
  ANTENNADIFFAREA                0.38930         LAYER MET3 ;
  ANTENNAGATEAREA                0.06300         LAYER MET1 ;
  ANTENNAGATEAREA                0.06300         LAYER MET2 ;
  ANTENNAGATEAREA                0.06300         LAYER MET3 ;
  ANTENNAPARTIALMETALAREA        0.09890         LAYER MET1 ;
  ANTENNAPARTIALMETALAREA        0.10380         LAYER MET2 ;
  ANTENNAMAXAREACAR              0.72381         LAYER MET1 ;
  ANTENNAMAXAREACAR              3.54286         LAYER MET2 ;
  ANTENNAMAXAREACAR              4.71429         LAYER MET3 ;
END D[81]
PIN Q[81]
  DIRECTION OUTPUT ;
  PORT
    LAYER MET1 ;
    RECT 370.550 0.000 370.960 0.180 ;
    LAYER MET2 ;
    RECT 370.550 0.000 370.960 0.180 ;
    LAYER MET3 ;
    RECT 370.550 0.000 370.960 0.180 ;
  END
  ANTENNADIFFAREA                0.60000         LAYER MET1 ;
  ANTENNADIFFAREA                0.60000         LAYER MET2 ;
  ANTENNADIFFAREA                0.60000         LAYER MET3 ;
  ANTENNAPARTIALMETALAREA        0.94400         LAYER MET1 ;
  ANTENNAPARTIALMETALAREA        1.33320         LAYER MET2 ;
END Q[81]
PIN D[82]
  DIRECTION INPUT ;
  PORT
    LAYER MET1 ;
    RECT 376.290 0.000 376.700 0.180 ;
    LAYER MET2 ;
    RECT 376.290 0.000 376.700 0.180 ;
    LAYER MET3 ;
    RECT 376.290 0.000 376.700 0.180 ;
  END
  ANTENNADIFFAREA                0.38930         LAYER MET1 ;
  ANTENNADIFFAREA                0.38930         LAYER MET2 ;
  ANTENNADIFFAREA                0.38930         LAYER MET3 ;
  ANTENNAGATEAREA                0.06300         LAYER MET1 ;
  ANTENNAGATEAREA                0.06300         LAYER MET2 ;
  ANTENNAGATEAREA                0.06300         LAYER MET3 ;
  ANTENNAPARTIALMETALAREA        0.09890         LAYER MET1 ;
  ANTENNAPARTIALMETALAREA        0.10380         LAYER MET2 ;
  ANTENNAMAXAREACAR              0.72381         LAYER MET1 ;
  ANTENNAMAXAREACAR              3.54286         LAYER MET2 ;
  ANTENNAMAXAREACAR              4.71429         LAYER MET3 ;
END D[82]
PIN Q[82]
  DIRECTION OUTPUT ;
  PORT
    LAYER MET1 ;
    RECT 374.750 0.000 375.160 0.180 ;
    LAYER MET2 ;
    RECT 374.750 0.000 375.160 0.180 ;
    LAYER MET3 ;
    RECT 374.750 0.000 375.160 0.180 ;
  END
  ANTENNADIFFAREA                0.60000         LAYER MET1 ;
  ANTENNADIFFAREA                0.60000         LAYER MET2 ;
  ANTENNADIFFAREA                0.60000         LAYER MET3 ;
  ANTENNAPARTIALMETALAREA        0.94400         LAYER MET1 ;
  ANTENNAPARTIALMETALAREA        1.33320         LAYER MET2 ;
END Q[82]
PIN D[83]
  DIRECTION INPUT ;
  PORT
    LAYER MET1 ;
    RECT 380.490 0.000 380.900 0.180 ;
    LAYER MET2 ;
    RECT 380.490 0.000 380.900 0.180 ;
    LAYER MET3 ;
    RECT 380.490 0.000 380.900 0.180 ;
  END
  ANTENNADIFFAREA                0.38930         LAYER MET1 ;
  ANTENNADIFFAREA                0.38930         LAYER MET2 ;
  ANTENNADIFFAREA                0.38930         LAYER MET3 ;
  ANTENNAGATEAREA                0.06300         LAYER MET1 ;
  ANTENNAGATEAREA                0.06300         LAYER MET2 ;
  ANTENNAGATEAREA                0.06300         LAYER MET3 ;
  ANTENNAPARTIALMETALAREA        0.09890         LAYER MET1 ;
  ANTENNAPARTIALMETALAREA        0.10380         LAYER MET2 ;
  ANTENNAMAXAREACAR              0.72381         LAYER MET1 ;
  ANTENNAMAXAREACAR              3.54286         LAYER MET2 ;
  ANTENNAMAXAREACAR              4.71429         LAYER MET3 ;
END D[83]
PIN Q[83]
  DIRECTION OUTPUT ;
  PORT
    LAYER MET1 ;
    RECT 378.950 0.000 379.360 0.180 ;
    LAYER MET2 ;
    RECT 378.950 0.000 379.360 0.180 ;
    LAYER MET3 ;
    RECT 378.950 0.000 379.360 0.180 ;
  END
  ANTENNADIFFAREA                0.60000         LAYER MET1 ;
  ANTENNADIFFAREA                0.60000         LAYER MET2 ;
  ANTENNADIFFAREA                0.60000         LAYER MET3 ;
  ANTENNAPARTIALMETALAREA        0.94400         LAYER MET1 ;
  ANTENNAPARTIALMETALAREA        1.33320         LAYER MET2 ;
END Q[83]
PIN D[84]
  DIRECTION INPUT ;
  PORT
    LAYER MET1 ;
    RECT 384.690 0.000 385.100 0.180 ;
    LAYER MET2 ;
    RECT 384.690 0.000 385.100 0.180 ;
    LAYER MET3 ;
    RECT 384.690 0.000 385.100 0.180 ;
  END
  ANTENNADIFFAREA                0.38930         LAYER MET1 ;
  ANTENNADIFFAREA                0.38930         LAYER MET2 ;
  ANTENNADIFFAREA                0.38930         LAYER MET3 ;
  ANTENNAGATEAREA                0.06300         LAYER MET1 ;
  ANTENNAGATEAREA                0.06300         LAYER MET2 ;
  ANTENNAGATEAREA                0.06300         LAYER MET3 ;
  ANTENNAPARTIALMETALAREA        0.09890         LAYER MET1 ;
  ANTENNAPARTIALMETALAREA        0.10380         LAYER MET2 ;
  ANTENNAMAXAREACAR              0.72381         LAYER MET1 ;
  ANTENNAMAXAREACAR              3.54286         LAYER MET2 ;
  ANTENNAMAXAREACAR              4.71429         LAYER MET3 ;
END D[84]
PIN Q[84]
  DIRECTION OUTPUT ;
  PORT
    LAYER MET1 ;
    RECT 383.150 0.000 383.560 0.180 ;
    LAYER MET2 ;
    RECT 383.150 0.000 383.560 0.180 ;
    LAYER MET3 ;
    RECT 383.150 0.000 383.560 0.180 ;
  END
  ANTENNADIFFAREA                0.60000         LAYER MET1 ;
  ANTENNADIFFAREA                0.60000         LAYER MET2 ;
  ANTENNADIFFAREA                0.60000         LAYER MET3 ;
  ANTENNAPARTIALMETALAREA        0.94400         LAYER MET1 ;
  ANTENNAPARTIALMETALAREA        1.33320         LAYER MET2 ;
END Q[84]
PIN D[85]
  DIRECTION INPUT ;
  PORT
    LAYER MET1 ;
    RECT 388.890 0.000 389.300 0.180 ;
    LAYER MET2 ;
    RECT 388.890 0.000 389.300 0.180 ;
    LAYER MET3 ;
    RECT 388.890 0.000 389.300 0.180 ;
  END
  ANTENNADIFFAREA                0.38930         LAYER MET1 ;
  ANTENNADIFFAREA                0.38930         LAYER MET2 ;
  ANTENNADIFFAREA                0.38930         LAYER MET3 ;
  ANTENNAGATEAREA                0.06300         LAYER MET1 ;
  ANTENNAGATEAREA                0.06300         LAYER MET2 ;
  ANTENNAGATEAREA                0.06300         LAYER MET3 ;
  ANTENNAPARTIALMETALAREA        0.09890         LAYER MET1 ;
  ANTENNAPARTIALMETALAREA        0.10380         LAYER MET2 ;
  ANTENNAMAXAREACAR              0.72381         LAYER MET1 ;
  ANTENNAMAXAREACAR              3.54286         LAYER MET2 ;
  ANTENNAMAXAREACAR              4.71429         LAYER MET3 ;
END D[85]
PIN Q[85]
  DIRECTION OUTPUT ;
  PORT
    LAYER MET1 ;
    RECT 387.350 0.000 387.760 0.180 ;
    LAYER MET2 ;
    RECT 387.350 0.000 387.760 0.180 ;
    LAYER MET3 ;
    RECT 387.350 0.000 387.760 0.180 ;
  END
  ANTENNADIFFAREA                0.60000         LAYER MET1 ;
  ANTENNADIFFAREA                0.60000         LAYER MET2 ;
  ANTENNADIFFAREA                0.60000         LAYER MET3 ;
  ANTENNAPARTIALMETALAREA        0.94400         LAYER MET1 ;
  ANTENNAPARTIALMETALAREA        1.33320         LAYER MET2 ;
END Q[85]
PIN D[86]
  DIRECTION INPUT ;
  PORT
    LAYER MET1 ;
    RECT 393.090 0.000 393.500 0.180 ;
    LAYER MET2 ;
    RECT 393.090 0.000 393.500 0.180 ;
    LAYER MET3 ;
    RECT 393.090 0.000 393.500 0.180 ;
  END
  ANTENNADIFFAREA                0.38930         LAYER MET1 ;
  ANTENNADIFFAREA                0.38930         LAYER MET2 ;
  ANTENNADIFFAREA                0.38930         LAYER MET3 ;
  ANTENNAGATEAREA                0.06300         LAYER MET1 ;
  ANTENNAGATEAREA                0.06300         LAYER MET2 ;
  ANTENNAGATEAREA                0.06300         LAYER MET3 ;
  ANTENNAPARTIALMETALAREA        0.09890         LAYER MET1 ;
  ANTENNAPARTIALMETALAREA        0.10380         LAYER MET2 ;
  ANTENNAMAXAREACAR              0.72381         LAYER MET1 ;
  ANTENNAMAXAREACAR              3.54286         LAYER MET2 ;
  ANTENNAMAXAREACAR              4.71429         LAYER MET3 ;
END D[86]
PIN Q[86]
  DIRECTION OUTPUT ;
  PORT
    LAYER MET1 ;
    RECT 391.550 0.000 391.960 0.180 ;
    LAYER MET2 ;
    RECT 391.550 0.000 391.960 0.180 ;
    LAYER MET3 ;
    RECT 391.550 0.000 391.960 0.180 ;
  END
  ANTENNADIFFAREA                0.60000         LAYER MET1 ;
  ANTENNADIFFAREA                0.60000         LAYER MET2 ;
  ANTENNADIFFAREA                0.60000         LAYER MET3 ;
  ANTENNAPARTIALMETALAREA        0.94400         LAYER MET1 ;
  ANTENNAPARTIALMETALAREA        1.33320         LAYER MET2 ;
END Q[86]
PIN D[87]
  DIRECTION INPUT ;
  PORT
    LAYER MET1 ;
    RECT 397.290 0.000 397.700 0.180 ;
    LAYER MET2 ;
    RECT 397.290 0.000 397.700 0.180 ;
    LAYER MET3 ;
    RECT 397.290 0.000 397.700 0.180 ;
  END
  ANTENNADIFFAREA                0.38930         LAYER MET1 ;
  ANTENNADIFFAREA                0.38930         LAYER MET2 ;
  ANTENNADIFFAREA                0.38930         LAYER MET3 ;
  ANTENNAGATEAREA                0.06300         LAYER MET1 ;
  ANTENNAGATEAREA                0.06300         LAYER MET2 ;
  ANTENNAGATEAREA                0.06300         LAYER MET3 ;
  ANTENNAPARTIALMETALAREA        0.09890         LAYER MET1 ;
  ANTENNAPARTIALMETALAREA        0.10380         LAYER MET2 ;
  ANTENNAMAXAREACAR              0.72381         LAYER MET1 ;
  ANTENNAMAXAREACAR              3.54286         LAYER MET2 ;
  ANTENNAMAXAREACAR              4.71429         LAYER MET3 ;
END D[87]
PIN Q[87]
  DIRECTION OUTPUT ;
  PORT
    LAYER MET1 ;
    RECT 395.750 0.000 396.160 0.180 ;
    LAYER MET2 ;
    RECT 395.750 0.000 396.160 0.180 ;
    LAYER MET3 ;
    RECT 395.750 0.000 396.160 0.180 ;
  END
  ANTENNADIFFAREA                0.60000         LAYER MET1 ;
  ANTENNADIFFAREA                0.60000         LAYER MET2 ;
  ANTENNADIFFAREA                0.60000         LAYER MET3 ;
  ANTENNAPARTIALMETALAREA        0.94400         LAYER MET1 ;
  ANTENNAPARTIALMETALAREA        1.33320         LAYER MET2 ;
END Q[87]
PIN D[88]
  DIRECTION INPUT ;
  PORT
    LAYER MET1 ;
    RECT 401.490 0.000 401.900 0.180 ;
    LAYER MET2 ;
    RECT 401.490 0.000 401.900 0.180 ;
    LAYER MET3 ;
    RECT 401.490 0.000 401.900 0.180 ;
  END
  ANTENNADIFFAREA                0.38930         LAYER MET1 ;
  ANTENNADIFFAREA                0.38930         LAYER MET2 ;
  ANTENNADIFFAREA                0.38930         LAYER MET3 ;
  ANTENNAGATEAREA                0.06300         LAYER MET1 ;
  ANTENNAGATEAREA                0.06300         LAYER MET2 ;
  ANTENNAGATEAREA                0.06300         LAYER MET3 ;
  ANTENNAPARTIALMETALAREA        0.09890         LAYER MET1 ;
  ANTENNAPARTIALMETALAREA        0.10380         LAYER MET2 ;
  ANTENNAMAXAREACAR              0.72381         LAYER MET1 ;
  ANTENNAMAXAREACAR              3.54286         LAYER MET2 ;
  ANTENNAMAXAREACAR              4.71429         LAYER MET3 ;
END D[88]
PIN Q[88]
  DIRECTION OUTPUT ;
  PORT
    LAYER MET1 ;
    RECT 399.950 0.000 400.360 0.180 ;
    LAYER MET2 ;
    RECT 399.950 0.000 400.360 0.180 ;
    LAYER MET3 ;
    RECT 399.950 0.000 400.360 0.180 ;
  END
  ANTENNADIFFAREA                0.60000         LAYER MET1 ;
  ANTENNADIFFAREA                0.60000         LAYER MET2 ;
  ANTENNADIFFAREA                0.60000         LAYER MET3 ;
  ANTENNAPARTIALMETALAREA        0.94400         LAYER MET1 ;
  ANTENNAPARTIALMETALAREA        1.33320         LAYER MET2 ;
END Q[88]
PIN D[89]
  DIRECTION INPUT ;
  PORT
    LAYER MET1 ;
    RECT 405.690 0.000 406.100 0.180 ;
    LAYER MET2 ;
    RECT 405.690 0.000 406.100 0.180 ;
    LAYER MET3 ;
    RECT 405.690 0.000 406.100 0.180 ;
  END
  ANTENNADIFFAREA                0.38930         LAYER MET1 ;
  ANTENNADIFFAREA                0.38930         LAYER MET2 ;
  ANTENNADIFFAREA                0.38930         LAYER MET3 ;
  ANTENNAGATEAREA                0.06300         LAYER MET1 ;
  ANTENNAGATEAREA                0.06300         LAYER MET2 ;
  ANTENNAGATEAREA                0.06300         LAYER MET3 ;
  ANTENNAPARTIALMETALAREA        0.09890         LAYER MET1 ;
  ANTENNAPARTIALMETALAREA        0.10380         LAYER MET2 ;
  ANTENNAMAXAREACAR              0.72381         LAYER MET1 ;
  ANTENNAMAXAREACAR              3.54286         LAYER MET2 ;
  ANTENNAMAXAREACAR              4.71429         LAYER MET3 ;
END D[89]
PIN Q[89]
  DIRECTION OUTPUT ;
  PORT
    LAYER MET1 ;
    RECT 404.150 0.000 404.560 0.180 ;
    LAYER MET2 ;
    RECT 404.150 0.000 404.560 0.180 ;
    LAYER MET3 ;
    RECT 404.150 0.000 404.560 0.180 ;
  END
  ANTENNADIFFAREA                0.60000         LAYER MET1 ;
  ANTENNADIFFAREA                0.60000         LAYER MET2 ;
  ANTENNADIFFAREA                0.60000         LAYER MET3 ;
  ANTENNAPARTIALMETALAREA        0.94400         LAYER MET1 ;
  ANTENNAPARTIALMETALAREA        1.33320         LAYER MET2 ;
END Q[89]
PIN D[90]
  DIRECTION INPUT ;
  PORT
    LAYER MET1 ;
    RECT 409.890 0.000 410.300 0.180 ;
    LAYER MET2 ;
    RECT 409.890 0.000 410.300 0.180 ;
    LAYER MET3 ;
    RECT 409.890 0.000 410.300 0.180 ;
  END
  ANTENNADIFFAREA                0.38930         LAYER MET1 ;
  ANTENNADIFFAREA                0.38930         LAYER MET2 ;
  ANTENNADIFFAREA                0.38930         LAYER MET3 ;
  ANTENNAGATEAREA                0.06300         LAYER MET1 ;
  ANTENNAGATEAREA                0.06300         LAYER MET2 ;
  ANTENNAGATEAREA                0.06300         LAYER MET3 ;
  ANTENNAPARTIALMETALAREA        0.09890         LAYER MET1 ;
  ANTENNAPARTIALMETALAREA        0.10380         LAYER MET2 ;
  ANTENNAMAXAREACAR              0.72381         LAYER MET1 ;
  ANTENNAMAXAREACAR              3.54286         LAYER MET2 ;
  ANTENNAMAXAREACAR              4.71429         LAYER MET3 ;
END D[90]
PIN Q[90]
  DIRECTION OUTPUT ;
  PORT
    LAYER MET1 ;
    RECT 408.350 0.000 408.760 0.180 ;
    LAYER MET2 ;
    RECT 408.350 0.000 408.760 0.180 ;
    LAYER MET3 ;
    RECT 408.350 0.000 408.760 0.180 ;
  END
  ANTENNADIFFAREA                0.60000         LAYER MET1 ;
  ANTENNADIFFAREA                0.60000         LAYER MET2 ;
  ANTENNADIFFAREA                0.60000         LAYER MET3 ;
  ANTENNAPARTIALMETALAREA        0.94400         LAYER MET1 ;
  ANTENNAPARTIALMETALAREA        1.33320         LAYER MET2 ;
END Q[90]
PIN D[91]
  DIRECTION INPUT ;
  PORT
    LAYER MET1 ;
    RECT 414.090 0.000 414.500 0.180 ;
    LAYER MET2 ;
    RECT 414.090 0.000 414.500 0.180 ;
    LAYER MET3 ;
    RECT 414.090 0.000 414.500 0.180 ;
  END
  ANTENNADIFFAREA                0.38930         LAYER MET1 ;
  ANTENNADIFFAREA                0.38930         LAYER MET2 ;
  ANTENNADIFFAREA                0.38930         LAYER MET3 ;
  ANTENNAGATEAREA                0.06300         LAYER MET1 ;
  ANTENNAGATEAREA                0.06300         LAYER MET2 ;
  ANTENNAGATEAREA                0.06300         LAYER MET3 ;
  ANTENNAPARTIALMETALAREA        0.09890         LAYER MET1 ;
  ANTENNAPARTIALMETALAREA        0.10380         LAYER MET2 ;
  ANTENNAMAXAREACAR              0.72381         LAYER MET1 ;
  ANTENNAMAXAREACAR              3.54286         LAYER MET2 ;
  ANTENNAMAXAREACAR              4.71429         LAYER MET3 ;
END D[91]
PIN Q[91]
  DIRECTION OUTPUT ;
  PORT
    LAYER MET1 ;
    RECT 412.550 0.000 412.960 0.180 ;
    LAYER MET2 ;
    RECT 412.550 0.000 412.960 0.180 ;
    LAYER MET3 ;
    RECT 412.550 0.000 412.960 0.180 ;
  END
  ANTENNADIFFAREA                0.60000         LAYER MET1 ;
  ANTENNADIFFAREA                0.60000         LAYER MET2 ;
  ANTENNADIFFAREA                0.60000         LAYER MET3 ;
  ANTENNAPARTIALMETALAREA        0.94400         LAYER MET1 ;
  ANTENNAPARTIALMETALAREA        1.33320         LAYER MET2 ;
END Q[91]
PIN D[92]
  DIRECTION INPUT ;
  PORT
    LAYER MET1 ;
    RECT 418.290 0.000 418.700 0.180 ;
    LAYER MET2 ;
    RECT 418.290 0.000 418.700 0.180 ;
    LAYER MET3 ;
    RECT 418.290 0.000 418.700 0.180 ;
  END
  ANTENNADIFFAREA                0.38930         LAYER MET1 ;
  ANTENNADIFFAREA                0.38930         LAYER MET2 ;
  ANTENNADIFFAREA                0.38930         LAYER MET3 ;
  ANTENNAGATEAREA                0.06300         LAYER MET1 ;
  ANTENNAGATEAREA                0.06300         LAYER MET2 ;
  ANTENNAGATEAREA                0.06300         LAYER MET3 ;
  ANTENNAPARTIALMETALAREA        0.09890         LAYER MET1 ;
  ANTENNAPARTIALMETALAREA        0.10380         LAYER MET2 ;
  ANTENNAMAXAREACAR              0.72381         LAYER MET1 ;
  ANTENNAMAXAREACAR              3.54286         LAYER MET2 ;
  ANTENNAMAXAREACAR              4.71429         LAYER MET3 ;
END D[92]
PIN Q[92]
  DIRECTION OUTPUT ;
  PORT
    LAYER MET1 ;
    RECT 416.750 0.000 417.160 0.180 ;
    LAYER MET2 ;
    RECT 416.750 0.000 417.160 0.180 ;
    LAYER MET3 ;
    RECT 416.750 0.000 417.160 0.180 ;
  END
  ANTENNADIFFAREA                0.60000         LAYER MET1 ;
  ANTENNADIFFAREA                0.60000         LAYER MET2 ;
  ANTENNADIFFAREA                0.60000         LAYER MET3 ;
  ANTENNAPARTIALMETALAREA        0.94400         LAYER MET1 ;
  ANTENNAPARTIALMETALAREA        1.33320         LAYER MET2 ;
END Q[92]
PIN D[93]
  DIRECTION INPUT ;
  PORT
    LAYER MET1 ;
    RECT 422.490 0.000 422.900 0.180 ;
    LAYER MET2 ;
    RECT 422.490 0.000 422.900 0.180 ;
    LAYER MET3 ;
    RECT 422.490 0.000 422.900 0.180 ;
  END
  ANTENNADIFFAREA                0.38930         LAYER MET1 ;
  ANTENNADIFFAREA                0.38930         LAYER MET2 ;
  ANTENNADIFFAREA                0.38930         LAYER MET3 ;
  ANTENNAGATEAREA                0.06300         LAYER MET1 ;
  ANTENNAGATEAREA                0.06300         LAYER MET2 ;
  ANTENNAGATEAREA                0.06300         LAYER MET3 ;
  ANTENNAPARTIALMETALAREA        0.09890         LAYER MET1 ;
  ANTENNAPARTIALMETALAREA        0.10380         LAYER MET2 ;
  ANTENNAMAXAREACAR              0.72381         LAYER MET1 ;
  ANTENNAMAXAREACAR              3.54286         LAYER MET2 ;
  ANTENNAMAXAREACAR              4.71429         LAYER MET3 ;
END D[93]
PIN Q[93]
  DIRECTION OUTPUT ;
  PORT
    LAYER MET1 ;
    RECT 420.950 0.000 421.360 0.180 ;
    LAYER MET2 ;
    RECT 420.950 0.000 421.360 0.180 ;
    LAYER MET3 ;
    RECT 420.950 0.000 421.360 0.180 ;
  END
  ANTENNADIFFAREA                0.60000         LAYER MET1 ;
  ANTENNADIFFAREA                0.60000         LAYER MET2 ;
  ANTENNADIFFAREA                0.60000         LAYER MET3 ;
  ANTENNAPARTIALMETALAREA        0.94400         LAYER MET1 ;
  ANTENNAPARTIALMETALAREA        1.33320         LAYER MET2 ;
END Q[93]
PIN D[94]
  DIRECTION INPUT ;
  PORT
    LAYER MET1 ;
    RECT 426.690 0.000 427.100 0.180 ;
    LAYER MET2 ;
    RECT 426.690 0.000 427.100 0.180 ;
    LAYER MET3 ;
    RECT 426.690 0.000 427.100 0.180 ;
  END
  ANTENNADIFFAREA                0.38930         LAYER MET1 ;
  ANTENNADIFFAREA                0.38930         LAYER MET2 ;
  ANTENNADIFFAREA                0.38930         LAYER MET3 ;
  ANTENNAGATEAREA                0.06300         LAYER MET1 ;
  ANTENNAGATEAREA                0.06300         LAYER MET2 ;
  ANTENNAGATEAREA                0.06300         LAYER MET3 ;
  ANTENNAPARTIALMETALAREA        0.09890         LAYER MET1 ;
  ANTENNAPARTIALMETALAREA        0.10380         LAYER MET2 ;
  ANTENNAMAXAREACAR              0.72381         LAYER MET1 ;
  ANTENNAMAXAREACAR              3.54286         LAYER MET2 ;
  ANTENNAMAXAREACAR              4.71429         LAYER MET3 ;
END D[94]
PIN Q[94]
  DIRECTION OUTPUT ;
  PORT
    LAYER MET1 ;
    RECT 425.150 0.000 425.560 0.180 ;
    LAYER MET2 ;
    RECT 425.150 0.000 425.560 0.180 ;
    LAYER MET3 ;
    RECT 425.150 0.000 425.560 0.180 ;
  END
  ANTENNADIFFAREA                0.60000         LAYER MET1 ;
  ANTENNADIFFAREA                0.60000         LAYER MET2 ;
  ANTENNADIFFAREA                0.60000         LAYER MET3 ;
  ANTENNAPARTIALMETALAREA        0.94400         LAYER MET1 ;
  ANTENNAPARTIALMETALAREA        1.33320         LAYER MET2 ;
END Q[94]
PIN D[95]
  DIRECTION INPUT ;
  PORT
    LAYER MET1 ;
    RECT 430.890 0.000 431.300 0.180 ;
    LAYER MET2 ;
    RECT 430.890 0.000 431.300 0.180 ;
    LAYER MET3 ;
    RECT 430.890 0.000 431.300 0.180 ;
  END
  ANTENNADIFFAREA                0.38930         LAYER MET1 ;
  ANTENNADIFFAREA                0.38930         LAYER MET2 ;
  ANTENNADIFFAREA                0.38930         LAYER MET3 ;
  ANTENNAGATEAREA                0.06300         LAYER MET1 ;
  ANTENNAGATEAREA                0.06300         LAYER MET2 ;
  ANTENNAGATEAREA                0.06300         LAYER MET3 ;
  ANTENNAPARTIALMETALAREA        0.09890         LAYER MET1 ;
  ANTENNAPARTIALMETALAREA        0.10380         LAYER MET2 ;
  ANTENNAMAXAREACAR              0.72381         LAYER MET1 ;
  ANTENNAMAXAREACAR              3.54286         LAYER MET2 ;
  ANTENNAMAXAREACAR              4.71429         LAYER MET3 ;
END D[95]
PIN Q[95]
  DIRECTION OUTPUT ;
  PORT
    LAYER MET1 ;
    RECT 429.350 0.000 429.760 0.180 ;
    LAYER MET2 ;
    RECT 429.350 0.000 429.760 0.180 ;
    LAYER MET3 ;
    RECT 429.350 0.000 429.760 0.180 ;
  END
  ANTENNADIFFAREA                0.60000         LAYER MET1 ;
  ANTENNADIFFAREA                0.60000         LAYER MET2 ;
  ANTENNADIFFAREA                0.60000         LAYER MET3 ;
  ANTENNAPARTIALMETALAREA        0.94400         LAYER MET1 ;
  ANTENNAPARTIALMETALAREA        1.33320         LAYER MET2 ;
END Q[95]
PIN D[96]
  DIRECTION INPUT ;
  PORT
    LAYER MET1 ;
    RECT 435.090 0.000 435.500 0.180 ;
    LAYER MET2 ;
    RECT 435.090 0.000 435.500 0.180 ;
    LAYER MET3 ;
    RECT 435.090 0.000 435.500 0.180 ;
  END
  ANTENNADIFFAREA                0.38930         LAYER MET1 ;
  ANTENNADIFFAREA                0.38930         LAYER MET2 ;
  ANTENNADIFFAREA                0.38930         LAYER MET3 ;
  ANTENNAGATEAREA                0.06300         LAYER MET1 ;
  ANTENNAGATEAREA                0.06300         LAYER MET2 ;
  ANTENNAGATEAREA                0.06300         LAYER MET3 ;
  ANTENNAPARTIALMETALAREA        0.09890         LAYER MET1 ;
  ANTENNAPARTIALMETALAREA        0.10380         LAYER MET2 ;
  ANTENNAMAXAREACAR              0.72381         LAYER MET1 ;
  ANTENNAMAXAREACAR              3.54286         LAYER MET2 ;
  ANTENNAMAXAREACAR              4.71429         LAYER MET3 ;
END D[96]
PIN Q[96]
  DIRECTION OUTPUT ;
  PORT
    LAYER MET1 ;
    RECT 433.550 0.000 433.960 0.180 ;
    LAYER MET2 ;
    RECT 433.550 0.000 433.960 0.180 ;
    LAYER MET3 ;
    RECT 433.550 0.000 433.960 0.180 ;
  END
  ANTENNADIFFAREA                0.60000         LAYER MET1 ;
  ANTENNADIFFAREA                0.60000         LAYER MET2 ;
  ANTENNADIFFAREA                0.60000         LAYER MET3 ;
  ANTENNAPARTIALMETALAREA        0.94400         LAYER MET1 ;
  ANTENNAPARTIALMETALAREA        1.33320         LAYER MET2 ;
END Q[96]
PIN D[97]
  DIRECTION INPUT ;
  PORT
    LAYER MET1 ;
    RECT 439.290 0.000 439.700 0.180 ;
    LAYER MET2 ;
    RECT 439.290 0.000 439.700 0.180 ;
    LAYER MET3 ;
    RECT 439.290 0.000 439.700 0.180 ;
  END
  ANTENNADIFFAREA                0.38930         LAYER MET1 ;
  ANTENNADIFFAREA                0.38930         LAYER MET2 ;
  ANTENNADIFFAREA                0.38930         LAYER MET3 ;
  ANTENNAGATEAREA                0.06300         LAYER MET1 ;
  ANTENNAGATEAREA                0.06300         LAYER MET2 ;
  ANTENNAGATEAREA                0.06300         LAYER MET3 ;
  ANTENNAPARTIALMETALAREA        0.09890         LAYER MET1 ;
  ANTENNAPARTIALMETALAREA        0.10380         LAYER MET2 ;
  ANTENNAMAXAREACAR              0.72381         LAYER MET1 ;
  ANTENNAMAXAREACAR              3.54286         LAYER MET2 ;
  ANTENNAMAXAREACAR              4.71429         LAYER MET3 ;
END D[97]
PIN Q[97]
  DIRECTION OUTPUT ;
  PORT
    LAYER MET1 ;
    RECT 437.750 0.000 438.160 0.180 ;
    LAYER MET2 ;
    RECT 437.750 0.000 438.160 0.180 ;
    LAYER MET3 ;
    RECT 437.750 0.000 438.160 0.180 ;
  END
  ANTENNADIFFAREA                0.60000         LAYER MET1 ;
  ANTENNADIFFAREA                0.60000         LAYER MET2 ;
  ANTENNADIFFAREA                0.60000         LAYER MET3 ;
  ANTENNAPARTIALMETALAREA        0.94400         LAYER MET1 ;
  ANTENNAPARTIALMETALAREA        1.33320         LAYER MET2 ;
END Q[97]
PIN D[98]
  DIRECTION INPUT ;
  PORT
    LAYER MET1 ;
    RECT 443.490 0.000 443.900 0.180 ;
    LAYER MET2 ;
    RECT 443.490 0.000 443.900 0.180 ;
    LAYER MET3 ;
    RECT 443.490 0.000 443.900 0.180 ;
  END
  ANTENNADIFFAREA                0.38930         LAYER MET1 ;
  ANTENNADIFFAREA                0.38930         LAYER MET2 ;
  ANTENNADIFFAREA                0.38930         LAYER MET3 ;
  ANTENNAGATEAREA                0.06300         LAYER MET1 ;
  ANTENNAGATEAREA                0.06300         LAYER MET2 ;
  ANTENNAGATEAREA                0.06300         LAYER MET3 ;
  ANTENNAPARTIALMETALAREA        0.09890         LAYER MET1 ;
  ANTENNAPARTIALMETALAREA        0.10380         LAYER MET2 ;
  ANTENNAMAXAREACAR              0.72381         LAYER MET1 ;
  ANTENNAMAXAREACAR              3.54286         LAYER MET2 ;
  ANTENNAMAXAREACAR              4.71429         LAYER MET3 ;
END D[98]
PIN Q[98]
  DIRECTION OUTPUT ;
  PORT
    LAYER MET1 ;
    RECT 441.950 0.000 442.360 0.180 ;
    LAYER MET2 ;
    RECT 441.950 0.000 442.360 0.180 ;
    LAYER MET3 ;
    RECT 441.950 0.000 442.360 0.180 ;
  END
  ANTENNADIFFAREA                0.60000         LAYER MET1 ;
  ANTENNADIFFAREA                0.60000         LAYER MET2 ;
  ANTENNADIFFAREA                0.60000         LAYER MET3 ;
  ANTENNAPARTIALMETALAREA        0.94400         LAYER MET1 ;
  ANTENNAPARTIALMETALAREA        1.33320         LAYER MET2 ;
END Q[98]
PIN D[99]
  DIRECTION INPUT ;
  PORT
    LAYER MET1 ;
    RECT 447.690 0.000 448.100 0.180 ;
    LAYER MET2 ;
    RECT 447.690 0.000 448.100 0.180 ;
    LAYER MET3 ;
    RECT 447.690 0.000 448.100 0.180 ;
  END
  ANTENNADIFFAREA                0.38930         LAYER MET1 ;
  ANTENNADIFFAREA                0.38930         LAYER MET2 ;
  ANTENNADIFFAREA                0.38930         LAYER MET3 ;
  ANTENNAGATEAREA                0.06300         LAYER MET1 ;
  ANTENNAGATEAREA                0.06300         LAYER MET2 ;
  ANTENNAGATEAREA                0.06300         LAYER MET3 ;
  ANTENNAPARTIALMETALAREA        0.09890         LAYER MET1 ;
  ANTENNAPARTIALMETALAREA        0.10380         LAYER MET2 ;
  ANTENNAMAXAREACAR              0.72381         LAYER MET1 ;
  ANTENNAMAXAREACAR              3.54286         LAYER MET2 ;
  ANTENNAMAXAREACAR              4.71429         LAYER MET3 ;
END D[99]
PIN Q[99]
  DIRECTION OUTPUT ;
  PORT
    LAYER MET1 ;
    RECT 446.150 0.000 446.560 0.180 ;
    LAYER MET2 ;
    RECT 446.150 0.000 446.560 0.180 ;
    LAYER MET3 ;
    RECT 446.150 0.000 446.560 0.180 ;
  END
  ANTENNADIFFAREA                0.60000         LAYER MET1 ;
  ANTENNADIFFAREA                0.60000         LAYER MET2 ;
  ANTENNADIFFAREA                0.60000         LAYER MET3 ;
  ANTENNAPARTIALMETALAREA        0.94400         LAYER MET1 ;
  ANTENNAPARTIALMETALAREA        1.33320         LAYER MET2 ;
END Q[99]
PIN D[100]
  DIRECTION INPUT ;
  PORT
    LAYER MET1 ;
    RECT 451.890 0.000 452.300 0.180 ;
    LAYER MET2 ;
    RECT 451.890 0.000 452.300 0.180 ;
    LAYER MET3 ;
    RECT 451.890 0.000 452.300 0.180 ;
  END
  ANTENNADIFFAREA                0.38930         LAYER MET1 ;
  ANTENNADIFFAREA                0.38930         LAYER MET2 ;
  ANTENNADIFFAREA                0.38930         LAYER MET3 ;
  ANTENNAGATEAREA                0.06300         LAYER MET1 ;
  ANTENNAGATEAREA                0.06300         LAYER MET2 ;
  ANTENNAGATEAREA                0.06300         LAYER MET3 ;
  ANTENNAPARTIALMETALAREA        0.09890         LAYER MET1 ;
  ANTENNAPARTIALMETALAREA        0.10380         LAYER MET2 ;
  ANTENNAMAXAREACAR              0.72381         LAYER MET1 ;
  ANTENNAMAXAREACAR              3.54286         LAYER MET2 ;
  ANTENNAMAXAREACAR              4.71429         LAYER MET3 ;
END D[100]
PIN Q[100]
  DIRECTION OUTPUT ;
  PORT
    LAYER MET1 ;
    RECT 450.350 0.000 450.760 0.180 ;
    LAYER MET2 ;
    RECT 450.350 0.000 450.760 0.180 ;
    LAYER MET3 ;
    RECT 450.350 0.000 450.760 0.180 ;
  END
  ANTENNADIFFAREA                0.60000         LAYER MET1 ;
  ANTENNADIFFAREA                0.60000         LAYER MET2 ;
  ANTENNADIFFAREA                0.60000         LAYER MET3 ;
  ANTENNAPARTIALMETALAREA        0.94400         LAYER MET1 ;
  ANTENNAPARTIALMETALAREA        1.33320         LAYER MET2 ;
END Q[100]
PIN D[101]
  DIRECTION INPUT ;
  PORT
    LAYER MET1 ;
    RECT 456.090 0.000 456.500 0.180 ;
    LAYER MET2 ;
    RECT 456.090 0.000 456.500 0.180 ;
    LAYER MET3 ;
    RECT 456.090 0.000 456.500 0.180 ;
  END
  ANTENNADIFFAREA                0.38930         LAYER MET1 ;
  ANTENNADIFFAREA                0.38930         LAYER MET2 ;
  ANTENNADIFFAREA                0.38930         LAYER MET3 ;
  ANTENNAGATEAREA                0.06300         LAYER MET1 ;
  ANTENNAGATEAREA                0.06300         LAYER MET2 ;
  ANTENNAGATEAREA                0.06300         LAYER MET3 ;
  ANTENNAPARTIALMETALAREA        0.09890         LAYER MET1 ;
  ANTENNAPARTIALMETALAREA        0.10380         LAYER MET2 ;
  ANTENNAMAXAREACAR              0.72381         LAYER MET1 ;
  ANTENNAMAXAREACAR              3.54286         LAYER MET2 ;
  ANTENNAMAXAREACAR              4.71429         LAYER MET3 ;
END D[101]
PIN Q[101]
  DIRECTION OUTPUT ;
  PORT
    LAYER MET1 ;
    RECT 454.550 0.000 454.960 0.180 ;
    LAYER MET2 ;
    RECT 454.550 0.000 454.960 0.180 ;
    LAYER MET3 ;
    RECT 454.550 0.000 454.960 0.180 ;
  END
  ANTENNADIFFAREA                0.60000         LAYER MET1 ;
  ANTENNADIFFAREA                0.60000         LAYER MET2 ;
  ANTENNADIFFAREA                0.60000         LAYER MET3 ;
  ANTENNAPARTIALMETALAREA        0.94400         LAYER MET1 ;
  ANTENNAPARTIALMETALAREA        1.33320         LAYER MET2 ;
END Q[101]
PIN D[102]
  DIRECTION INPUT ;
  PORT
    LAYER MET1 ;
    RECT 460.290 0.000 460.700 0.180 ;
    LAYER MET2 ;
    RECT 460.290 0.000 460.700 0.180 ;
    LAYER MET3 ;
    RECT 460.290 0.000 460.700 0.180 ;
  END
  ANTENNADIFFAREA                0.38930         LAYER MET1 ;
  ANTENNADIFFAREA                0.38930         LAYER MET2 ;
  ANTENNADIFFAREA                0.38930         LAYER MET3 ;
  ANTENNAGATEAREA                0.06300         LAYER MET1 ;
  ANTENNAGATEAREA                0.06300         LAYER MET2 ;
  ANTENNAGATEAREA                0.06300         LAYER MET3 ;
  ANTENNAPARTIALMETALAREA        0.09890         LAYER MET1 ;
  ANTENNAPARTIALMETALAREA        0.10380         LAYER MET2 ;
  ANTENNAMAXAREACAR              0.72381         LAYER MET1 ;
  ANTENNAMAXAREACAR              3.54286         LAYER MET2 ;
  ANTENNAMAXAREACAR              4.71429         LAYER MET3 ;
END D[102]
PIN Q[102]
  DIRECTION OUTPUT ;
  PORT
    LAYER MET1 ;
    RECT 458.750 0.000 459.160 0.180 ;
    LAYER MET2 ;
    RECT 458.750 0.000 459.160 0.180 ;
    LAYER MET3 ;
    RECT 458.750 0.000 459.160 0.180 ;
  END
  ANTENNADIFFAREA                0.60000         LAYER MET1 ;
  ANTENNADIFFAREA                0.60000         LAYER MET2 ;
  ANTENNADIFFAREA                0.60000         LAYER MET3 ;
  ANTENNAPARTIALMETALAREA        0.94400         LAYER MET1 ;
  ANTENNAPARTIALMETALAREA        1.33320         LAYER MET2 ;
END Q[102]
PIN D[103]
  DIRECTION INPUT ;
  PORT
    LAYER MET1 ;
    RECT 464.490 0.000 464.900 0.180 ;
    LAYER MET2 ;
    RECT 464.490 0.000 464.900 0.180 ;
    LAYER MET3 ;
    RECT 464.490 0.000 464.900 0.180 ;
  END
  ANTENNADIFFAREA                0.38930         LAYER MET1 ;
  ANTENNADIFFAREA                0.38930         LAYER MET2 ;
  ANTENNADIFFAREA                0.38930         LAYER MET3 ;
  ANTENNAGATEAREA                0.06300         LAYER MET1 ;
  ANTENNAGATEAREA                0.06300         LAYER MET2 ;
  ANTENNAGATEAREA                0.06300         LAYER MET3 ;
  ANTENNAPARTIALMETALAREA        0.09890         LAYER MET1 ;
  ANTENNAPARTIALMETALAREA        0.10380         LAYER MET2 ;
  ANTENNAMAXAREACAR              0.72381         LAYER MET1 ;
  ANTENNAMAXAREACAR              3.54286         LAYER MET2 ;
  ANTENNAMAXAREACAR              4.71429         LAYER MET3 ;
END D[103]
PIN Q[103]
  DIRECTION OUTPUT ;
  PORT
    LAYER MET1 ;
    RECT 462.950 0.000 463.360 0.180 ;
    LAYER MET2 ;
    RECT 462.950 0.000 463.360 0.180 ;
    LAYER MET3 ;
    RECT 462.950 0.000 463.360 0.180 ;
  END
  ANTENNADIFFAREA                0.60000         LAYER MET1 ;
  ANTENNADIFFAREA                0.60000         LAYER MET2 ;
  ANTENNADIFFAREA                0.60000         LAYER MET3 ;
  ANTENNAPARTIALMETALAREA        0.94400         LAYER MET1 ;
  ANTENNAPARTIALMETALAREA        1.33320         LAYER MET2 ;
END Q[103]
PIN D[104]
  DIRECTION INPUT ;
  PORT
    LAYER MET1 ;
    RECT 468.690 0.000 469.100 0.180 ;
    LAYER MET2 ;
    RECT 468.690 0.000 469.100 0.180 ;
    LAYER MET3 ;
    RECT 468.690 0.000 469.100 0.180 ;
  END
  ANTENNADIFFAREA                0.38930         LAYER MET1 ;
  ANTENNADIFFAREA                0.38930         LAYER MET2 ;
  ANTENNADIFFAREA                0.38930         LAYER MET3 ;
  ANTENNAGATEAREA                0.06300         LAYER MET1 ;
  ANTENNAGATEAREA                0.06300         LAYER MET2 ;
  ANTENNAGATEAREA                0.06300         LAYER MET3 ;
  ANTENNAPARTIALMETALAREA        0.09890         LAYER MET1 ;
  ANTENNAPARTIALMETALAREA        0.10380         LAYER MET2 ;
  ANTENNAMAXAREACAR              0.72381         LAYER MET1 ;
  ANTENNAMAXAREACAR              3.54286         LAYER MET2 ;
  ANTENNAMAXAREACAR              4.71429         LAYER MET3 ;
END D[104]
PIN Q[104]
  DIRECTION OUTPUT ;
  PORT
    LAYER MET1 ;
    RECT 467.150 0.000 467.560 0.180 ;
    LAYER MET2 ;
    RECT 467.150 0.000 467.560 0.180 ;
    LAYER MET3 ;
    RECT 467.150 0.000 467.560 0.180 ;
  END
  ANTENNADIFFAREA                0.60000         LAYER MET1 ;
  ANTENNADIFFAREA                0.60000         LAYER MET2 ;
  ANTENNADIFFAREA                0.60000         LAYER MET3 ;
  ANTENNAPARTIALMETALAREA        0.94400         LAYER MET1 ;
  ANTENNAPARTIALMETALAREA        1.33320         LAYER MET2 ;
END Q[104]
PIN D[105]
  DIRECTION INPUT ;
  PORT
    LAYER MET1 ;
    RECT 472.890 0.000 473.300 0.180 ;
    LAYER MET2 ;
    RECT 472.890 0.000 473.300 0.180 ;
    LAYER MET3 ;
    RECT 472.890 0.000 473.300 0.180 ;
  END
  ANTENNADIFFAREA                0.38930         LAYER MET1 ;
  ANTENNADIFFAREA                0.38930         LAYER MET2 ;
  ANTENNADIFFAREA                0.38930         LAYER MET3 ;
  ANTENNAGATEAREA                0.06300         LAYER MET1 ;
  ANTENNAGATEAREA                0.06300         LAYER MET2 ;
  ANTENNAGATEAREA                0.06300         LAYER MET3 ;
  ANTENNAPARTIALMETALAREA        0.09890         LAYER MET1 ;
  ANTENNAPARTIALMETALAREA        0.10380         LAYER MET2 ;
  ANTENNAMAXAREACAR              0.72381         LAYER MET1 ;
  ANTENNAMAXAREACAR              3.54286         LAYER MET2 ;
  ANTENNAMAXAREACAR              4.71429         LAYER MET3 ;
END D[105]
PIN Q[105]
  DIRECTION OUTPUT ;
  PORT
    LAYER MET1 ;
    RECT 471.350 0.000 471.760 0.180 ;
    LAYER MET2 ;
    RECT 471.350 0.000 471.760 0.180 ;
    LAYER MET3 ;
    RECT 471.350 0.000 471.760 0.180 ;
  END
  ANTENNADIFFAREA                0.60000         LAYER MET1 ;
  ANTENNADIFFAREA                0.60000         LAYER MET2 ;
  ANTENNADIFFAREA                0.60000         LAYER MET3 ;
  ANTENNAPARTIALMETALAREA        0.94400         LAYER MET1 ;
  ANTENNAPARTIALMETALAREA        1.33320         LAYER MET2 ;
END Q[105]
PIN D[106]
  DIRECTION INPUT ;
  PORT
    LAYER MET1 ;
    RECT 477.090 0.000 477.500 0.180 ;
    LAYER MET2 ;
    RECT 477.090 0.000 477.500 0.180 ;
    LAYER MET3 ;
    RECT 477.090 0.000 477.500 0.180 ;
  END
  ANTENNADIFFAREA                0.38930         LAYER MET1 ;
  ANTENNADIFFAREA                0.38930         LAYER MET2 ;
  ANTENNADIFFAREA                0.38930         LAYER MET3 ;
  ANTENNAGATEAREA                0.06300         LAYER MET1 ;
  ANTENNAGATEAREA                0.06300         LAYER MET2 ;
  ANTENNAGATEAREA                0.06300         LAYER MET3 ;
  ANTENNAPARTIALMETALAREA        0.09890         LAYER MET1 ;
  ANTENNAPARTIALMETALAREA        0.10380         LAYER MET2 ;
  ANTENNAMAXAREACAR              0.72381         LAYER MET1 ;
  ANTENNAMAXAREACAR              3.54286         LAYER MET2 ;
  ANTENNAMAXAREACAR              4.71429         LAYER MET3 ;
END D[106]
PIN Q[106]
  DIRECTION OUTPUT ;
  PORT
    LAYER MET1 ;
    RECT 475.550 0.000 475.960 0.180 ;
    LAYER MET2 ;
    RECT 475.550 0.000 475.960 0.180 ;
    LAYER MET3 ;
    RECT 475.550 0.000 475.960 0.180 ;
  END
  ANTENNADIFFAREA                0.60000         LAYER MET1 ;
  ANTENNADIFFAREA                0.60000         LAYER MET2 ;
  ANTENNADIFFAREA                0.60000         LAYER MET3 ;
  ANTENNAPARTIALMETALAREA        0.94400         LAYER MET1 ;
  ANTENNAPARTIALMETALAREA        1.33320         LAYER MET2 ;
END Q[106]
PIN D[107]
  DIRECTION INPUT ;
  PORT
    LAYER MET1 ;
    RECT 481.290 0.000 481.700 0.180 ;
    LAYER MET2 ;
    RECT 481.290 0.000 481.700 0.180 ;
    LAYER MET3 ;
    RECT 481.290 0.000 481.700 0.180 ;
  END
  ANTENNADIFFAREA                0.38930         LAYER MET1 ;
  ANTENNADIFFAREA                0.38930         LAYER MET2 ;
  ANTENNADIFFAREA                0.38930         LAYER MET3 ;
  ANTENNAGATEAREA                0.06300         LAYER MET1 ;
  ANTENNAGATEAREA                0.06300         LAYER MET2 ;
  ANTENNAGATEAREA                0.06300         LAYER MET3 ;
  ANTENNAPARTIALMETALAREA        0.09890         LAYER MET1 ;
  ANTENNAPARTIALMETALAREA        0.10380         LAYER MET2 ;
  ANTENNAMAXAREACAR              0.72381         LAYER MET1 ;
  ANTENNAMAXAREACAR              3.54286         LAYER MET2 ;
  ANTENNAMAXAREACAR              4.71429         LAYER MET3 ;
END D[107]
PIN Q[107]
  DIRECTION OUTPUT ;
  PORT
    LAYER MET1 ;
    RECT 479.750 0.000 480.160 0.180 ;
    LAYER MET2 ;
    RECT 479.750 0.000 480.160 0.180 ;
    LAYER MET3 ;
    RECT 479.750 0.000 480.160 0.180 ;
  END
  ANTENNADIFFAREA                0.60000         LAYER MET1 ;
  ANTENNADIFFAREA                0.60000         LAYER MET2 ;
  ANTENNADIFFAREA                0.60000         LAYER MET3 ;
  ANTENNAPARTIALMETALAREA        0.94400         LAYER MET1 ;
  ANTENNAPARTIALMETALAREA        1.33320         LAYER MET2 ;
END Q[107]
PIN D[108]
  DIRECTION INPUT ;
  PORT
    LAYER MET1 ;
    RECT 485.490 0.000 485.900 0.180 ;
    LAYER MET2 ;
    RECT 485.490 0.000 485.900 0.180 ;
    LAYER MET3 ;
    RECT 485.490 0.000 485.900 0.180 ;
  END
  ANTENNADIFFAREA                0.38930         LAYER MET1 ;
  ANTENNADIFFAREA                0.38930         LAYER MET2 ;
  ANTENNADIFFAREA                0.38930         LAYER MET3 ;
  ANTENNAGATEAREA                0.06300         LAYER MET1 ;
  ANTENNAGATEAREA                0.06300         LAYER MET2 ;
  ANTENNAGATEAREA                0.06300         LAYER MET3 ;
  ANTENNAPARTIALMETALAREA        0.09890         LAYER MET1 ;
  ANTENNAPARTIALMETALAREA        0.10380         LAYER MET2 ;
  ANTENNAMAXAREACAR              0.72381         LAYER MET1 ;
  ANTENNAMAXAREACAR              3.54286         LAYER MET2 ;
  ANTENNAMAXAREACAR              4.71429         LAYER MET3 ;
END D[108]
PIN Q[108]
  DIRECTION OUTPUT ;
  PORT
    LAYER MET1 ;
    RECT 483.950 0.000 484.360 0.180 ;
    LAYER MET2 ;
    RECT 483.950 0.000 484.360 0.180 ;
    LAYER MET3 ;
    RECT 483.950 0.000 484.360 0.180 ;
  END
  ANTENNADIFFAREA                0.60000         LAYER MET1 ;
  ANTENNADIFFAREA                0.60000         LAYER MET2 ;
  ANTENNADIFFAREA                0.60000         LAYER MET3 ;
  ANTENNAPARTIALMETALAREA        0.94400         LAYER MET1 ;
  ANTENNAPARTIALMETALAREA        1.33320         LAYER MET2 ;
END Q[108]
PIN D[109]
  DIRECTION INPUT ;
  PORT
    LAYER MET1 ;
    RECT 489.690 0.000 490.100 0.180 ;
    LAYER MET2 ;
    RECT 489.690 0.000 490.100 0.180 ;
    LAYER MET3 ;
    RECT 489.690 0.000 490.100 0.180 ;
  END
  ANTENNADIFFAREA                0.38930         LAYER MET1 ;
  ANTENNADIFFAREA                0.38930         LAYER MET2 ;
  ANTENNADIFFAREA                0.38930         LAYER MET3 ;
  ANTENNAGATEAREA                0.06300         LAYER MET1 ;
  ANTENNAGATEAREA                0.06300         LAYER MET2 ;
  ANTENNAGATEAREA                0.06300         LAYER MET3 ;
  ANTENNAPARTIALMETALAREA        0.09890         LAYER MET1 ;
  ANTENNAPARTIALMETALAREA        0.10380         LAYER MET2 ;
  ANTENNAMAXAREACAR              0.72381         LAYER MET1 ;
  ANTENNAMAXAREACAR              3.54286         LAYER MET2 ;
  ANTENNAMAXAREACAR              4.71429         LAYER MET3 ;
END D[109]
PIN Q[109]
  DIRECTION OUTPUT ;
  PORT
    LAYER MET1 ;
    RECT 488.150 0.000 488.560 0.180 ;
    LAYER MET2 ;
    RECT 488.150 0.000 488.560 0.180 ;
    LAYER MET3 ;
    RECT 488.150 0.000 488.560 0.180 ;
  END
  ANTENNADIFFAREA                0.60000         LAYER MET1 ;
  ANTENNADIFFAREA                0.60000         LAYER MET2 ;
  ANTENNADIFFAREA                0.60000         LAYER MET3 ;
  ANTENNAPARTIALMETALAREA        0.94400         LAYER MET1 ;
  ANTENNAPARTIALMETALAREA        1.33320         LAYER MET2 ;
END Q[109]
PIN D[110]
  DIRECTION INPUT ;
  PORT
    LAYER MET1 ;
    RECT 493.890 0.000 494.300 0.180 ;
    LAYER MET2 ;
    RECT 493.890 0.000 494.300 0.180 ;
    LAYER MET3 ;
    RECT 493.890 0.000 494.300 0.180 ;
  END
  ANTENNADIFFAREA                0.38930         LAYER MET1 ;
  ANTENNADIFFAREA                0.38930         LAYER MET2 ;
  ANTENNADIFFAREA                0.38930         LAYER MET3 ;
  ANTENNAGATEAREA                0.06300         LAYER MET1 ;
  ANTENNAGATEAREA                0.06300         LAYER MET2 ;
  ANTENNAGATEAREA                0.06300         LAYER MET3 ;
  ANTENNAPARTIALMETALAREA        0.09890         LAYER MET1 ;
  ANTENNAPARTIALMETALAREA        0.10380         LAYER MET2 ;
  ANTENNAMAXAREACAR              0.72381         LAYER MET1 ;
  ANTENNAMAXAREACAR              3.54286         LAYER MET2 ;
  ANTENNAMAXAREACAR              4.71429         LAYER MET3 ;
END D[110]
PIN Q[110]
  DIRECTION OUTPUT ;
  PORT
    LAYER MET1 ;
    RECT 492.350 0.000 492.760 0.180 ;
    LAYER MET2 ;
    RECT 492.350 0.000 492.760 0.180 ;
    LAYER MET3 ;
    RECT 492.350 0.000 492.760 0.180 ;
  END
  ANTENNADIFFAREA                0.60000         LAYER MET1 ;
  ANTENNADIFFAREA                0.60000         LAYER MET2 ;
  ANTENNADIFFAREA                0.60000         LAYER MET3 ;
  ANTENNAPARTIALMETALAREA        0.94400         LAYER MET1 ;
  ANTENNAPARTIALMETALAREA        1.33320         LAYER MET2 ;
END Q[110]
PIN D[111]
  DIRECTION INPUT ;
  PORT
    LAYER MET1 ;
    RECT 498.090 0.000 498.500 0.180 ;
    LAYER MET2 ;
    RECT 498.090 0.000 498.500 0.180 ;
    LAYER MET3 ;
    RECT 498.090 0.000 498.500 0.180 ;
  END
  ANTENNADIFFAREA                0.38930         LAYER MET1 ;
  ANTENNADIFFAREA                0.38930         LAYER MET2 ;
  ANTENNADIFFAREA                0.38930         LAYER MET3 ;
  ANTENNAGATEAREA                0.06300         LAYER MET1 ;
  ANTENNAGATEAREA                0.06300         LAYER MET2 ;
  ANTENNAGATEAREA                0.06300         LAYER MET3 ;
  ANTENNAPARTIALMETALAREA        0.09890         LAYER MET1 ;
  ANTENNAPARTIALMETALAREA        0.10380         LAYER MET2 ;
  ANTENNAMAXAREACAR              0.72381         LAYER MET1 ;
  ANTENNAMAXAREACAR              3.54286         LAYER MET2 ;
  ANTENNAMAXAREACAR              4.71429         LAYER MET3 ;
END D[111]
PIN Q[111]
  DIRECTION OUTPUT ;
  PORT
    LAYER MET1 ;
    RECT 496.550 0.000 496.960 0.180 ;
    LAYER MET2 ;
    RECT 496.550 0.000 496.960 0.180 ;
    LAYER MET3 ;
    RECT 496.550 0.000 496.960 0.180 ;
  END
  ANTENNADIFFAREA                0.60000         LAYER MET1 ;
  ANTENNADIFFAREA                0.60000         LAYER MET2 ;
  ANTENNADIFFAREA                0.60000         LAYER MET3 ;
  ANTENNAPARTIALMETALAREA        0.94400         LAYER MET1 ;
  ANTENNAPARTIALMETALAREA        1.33320         LAYER MET2 ;
END Q[111]
PIN D[112]
  DIRECTION INPUT ;
  PORT
    LAYER MET1 ;
    RECT 502.290 0.000 502.700 0.180 ;
    LAYER MET2 ;
    RECT 502.290 0.000 502.700 0.180 ;
    LAYER MET3 ;
    RECT 502.290 0.000 502.700 0.180 ;
  END
  ANTENNADIFFAREA                0.38930         LAYER MET1 ;
  ANTENNADIFFAREA                0.38930         LAYER MET2 ;
  ANTENNADIFFAREA                0.38930         LAYER MET3 ;
  ANTENNAGATEAREA                0.06300         LAYER MET1 ;
  ANTENNAGATEAREA                0.06300         LAYER MET2 ;
  ANTENNAGATEAREA                0.06300         LAYER MET3 ;
  ANTENNAPARTIALMETALAREA        0.09890         LAYER MET1 ;
  ANTENNAPARTIALMETALAREA        0.10380         LAYER MET2 ;
  ANTENNAMAXAREACAR              0.72381         LAYER MET1 ;
  ANTENNAMAXAREACAR              3.54286         LAYER MET2 ;
  ANTENNAMAXAREACAR              4.71429         LAYER MET3 ;
END D[112]
PIN Q[112]
  DIRECTION OUTPUT ;
  PORT
    LAYER MET1 ;
    RECT 500.750 0.000 501.160 0.180 ;
    LAYER MET2 ;
    RECT 500.750 0.000 501.160 0.180 ;
    LAYER MET3 ;
    RECT 500.750 0.000 501.160 0.180 ;
  END
  ANTENNADIFFAREA                0.60000         LAYER MET1 ;
  ANTENNADIFFAREA                0.60000         LAYER MET2 ;
  ANTENNADIFFAREA                0.60000         LAYER MET3 ;
  ANTENNAPARTIALMETALAREA        0.94400         LAYER MET1 ;
  ANTENNAPARTIALMETALAREA        1.33320         LAYER MET2 ;
END Q[112]
PIN D[113]
  DIRECTION INPUT ;
  PORT
    LAYER MET1 ;
    RECT 506.490 0.000 506.900 0.180 ;
    LAYER MET2 ;
    RECT 506.490 0.000 506.900 0.180 ;
    LAYER MET3 ;
    RECT 506.490 0.000 506.900 0.180 ;
  END
  ANTENNADIFFAREA                0.38930         LAYER MET1 ;
  ANTENNADIFFAREA                0.38930         LAYER MET2 ;
  ANTENNADIFFAREA                0.38930         LAYER MET3 ;
  ANTENNAGATEAREA                0.06300         LAYER MET1 ;
  ANTENNAGATEAREA                0.06300         LAYER MET2 ;
  ANTENNAGATEAREA                0.06300         LAYER MET3 ;
  ANTENNAPARTIALMETALAREA        0.09890         LAYER MET1 ;
  ANTENNAPARTIALMETALAREA        0.10380         LAYER MET2 ;
  ANTENNAMAXAREACAR              0.72381         LAYER MET1 ;
  ANTENNAMAXAREACAR              3.54286         LAYER MET2 ;
  ANTENNAMAXAREACAR              4.71429         LAYER MET3 ;
END D[113]
PIN Q[113]
  DIRECTION OUTPUT ;
  PORT
    LAYER MET1 ;
    RECT 504.950 0.000 505.360 0.180 ;
    LAYER MET2 ;
    RECT 504.950 0.000 505.360 0.180 ;
    LAYER MET3 ;
    RECT 504.950 0.000 505.360 0.180 ;
  END
  ANTENNADIFFAREA                0.60000         LAYER MET1 ;
  ANTENNADIFFAREA                0.60000         LAYER MET2 ;
  ANTENNADIFFAREA                0.60000         LAYER MET3 ;
  ANTENNAPARTIALMETALAREA        0.94400         LAYER MET1 ;
  ANTENNAPARTIALMETALAREA        1.33320         LAYER MET2 ;
END Q[113]
PIN D[114]
  DIRECTION INPUT ;
  PORT
    LAYER MET1 ;
    RECT 510.690 0.000 511.100 0.180 ;
    LAYER MET2 ;
    RECT 510.690 0.000 511.100 0.180 ;
    LAYER MET3 ;
    RECT 510.690 0.000 511.100 0.180 ;
  END
  ANTENNADIFFAREA                0.38930         LAYER MET1 ;
  ANTENNADIFFAREA                0.38930         LAYER MET2 ;
  ANTENNADIFFAREA                0.38930         LAYER MET3 ;
  ANTENNAGATEAREA                0.06300         LAYER MET1 ;
  ANTENNAGATEAREA                0.06300         LAYER MET2 ;
  ANTENNAGATEAREA                0.06300         LAYER MET3 ;
  ANTENNAPARTIALMETALAREA        0.09890         LAYER MET1 ;
  ANTENNAPARTIALMETALAREA        0.10380         LAYER MET2 ;
  ANTENNAMAXAREACAR              0.72381         LAYER MET1 ;
  ANTENNAMAXAREACAR              3.54286         LAYER MET2 ;
  ANTENNAMAXAREACAR              4.71429         LAYER MET3 ;
END D[114]
PIN Q[114]
  DIRECTION OUTPUT ;
  PORT
    LAYER MET1 ;
    RECT 509.150 0.000 509.560 0.180 ;
    LAYER MET2 ;
    RECT 509.150 0.000 509.560 0.180 ;
    LAYER MET3 ;
    RECT 509.150 0.000 509.560 0.180 ;
  END
  ANTENNADIFFAREA                0.60000         LAYER MET1 ;
  ANTENNADIFFAREA                0.60000         LAYER MET2 ;
  ANTENNADIFFAREA                0.60000         LAYER MET3 ;
  ANTENNAPARTIALMETALAREA        0.94400         LAYER MET1 ;
  ANTENNAPARTIALMETALAREA        1.33320         LAYER MET2 ;
END Q[114]
PIN D[115]
  DIRECTION INPUT ;
  PORT
    LAYER MET1 ;
    RECT 514.890 0.000 515.300 0.180 ;
    LAYER MET2 ;
    RECT 514.890 0.000 515.300 0.180 ;
    LAYER MET3 ;
    RECT 514.890 0.000 515.300 0.180 ;
  END
  ANTENNADIFFAREA                0.38930         LAYER MET1 ;
  ANTENNADIFFAREA                0.38930         LAYER MET2 ;
  ANTENNADIFFAREA                0.38930         LAYER MET3 ;
  ANTENNAGATEAREA                0.06300         LAYER MET1 ;
  ANTENNAGATEAREA                0.06300         LAYER MET2 ;
  ANTENNAGATEAREA                0.06300         LAYER MET3 ;
  ANTENNAPARTIALMETALAREA        0.09890         LAYER MET1 ;
  ANTENNAPARTIALMETALAREA        0.10380         LAYER MET2 ;
  ANTENNAMAXAREACAR              0.72381         LAYER MET1 ;
  ANTENNAMAXAREACAR              3.54286         LAYER MET2 ;
  ANTENNAMAXAREACAR              4.71429         LAYER MET3 ;
END D[115]
PIN Q[115]
  DIRECTION OUTPUT ;
  PORT
    LAYER MET1 ;
    RECT 513.350 0.000 513.760 0.180 ;
    LAYER MET2 ;
    RECT 513.350 0.000 513.760 0.180 ;
    LAYER MET3 ;
    RECT 513.350 0.000 513.760 0.180 ;
  END
  ANTENNADIFFAREA                0.60000         LAYER MET1 ;
  ANTENNADIFFAREA                0.60000         LAYER MET2 ;
  ANTENNADIFFAREA                0.60000         LAYER MET3 ;
  ANTENNAPARTIALMETALAREA        0.94400         LAYER MET1 ;
  ANTENNAPARTIALMETALAREA        1.33320         LAYER MET2 ;
END Q[115]
PIN D[116]
  DIRECTION INPUT ;
  PORT
    LAYER MET1 ;
    RECT 519.090 0.000 519.500 0.180 ;
    LAYER MET2 ;
    RECT 519.090 0.000 519.500 0.180 ;
    LAYER MET3 ;
    RECT 519.090 0.000 519.500 0.180 ;
  END
  ANTENNADIFFAREA                0.38930         LAYER MET1 ;
  ANTENNADIFFAREA                0.38930         LAYER MET2 ;
  ANTENNADIFFAREA                0.38930         LAYER MET3 ;
  ANTENNAGATEAREA                0.06300         LAYER MET1 ;
  ANTENNAGATEAREA                0.06300         LAYER MET2 ;
  ANTENNAGATEAREA                0.06300         LAYER MET3 ;
  ANTENNAPARTIALMETALAREA        0.09890         LAYER MET1 ;
  ANTENNAPARTIALMETALAREA        0.10380         LAYER MET2 ;
  ANTENNAMAXAREACAR              0.72381         LAYER MET1 ;
  ANTENNAMAXAREACAR              3.54286         LAYER MET2 ;
  ANTENNAMAXAREACAR              4.71429         LAYER MET3 ;
END D[116]
PIN Q[116]
  DIRECTION OUTPUT ;
  PORT
    LAYER MET1 ;
    RECT 517.550 0.000 517.960 0.180 ;
    LAYER MET2 ;
    RECT 517.550 0.000 517.960 0.180 ;
    LAYER MET3 ;
    RECT 517.550 0.000 517.960 0.180 ;
  END
  ANTENNADIFFAREA                0.60000         LAYER MET1 ;
  ANTENNADIFFAREA                0.60000         LAYER MET2 ;
  ANTENNADIFFAREA                0.60000         LAYER MET3 ;
  ANTENNAPARTIALMETALAREA        0.94400         LAYER MET1 ;
  ANTENNAPARTIALMETALAREA        1.33320         LAYER MET2 ;
END Q[116]
PIN D[117]
  DIRECTION INPUT ;
  PORT
    LAYER MET1 ;
    RECT 523.290 0.000 523.700 0.180 ;
    LAYER MET2 ;
    RECT 523.290 0.000 523.700 0.180 ;
    LAYER MET3 ;
    RECT 523.290 0.000 523.700 0.180 ;
  END
  ANTENNADIFFAREA                0.38930         LAYER MET1 ;
  ANTENNADIFFAREA                0.38930         LAYER MET2 ;
  ANTENNADIFFAREA                0.38930         LAYER MET3 ;
  ANTENNAGATEAREA                0.06300         LAYER MET1 ;
  ANTENNAGATEAREA                0.06300         LAYER MET2 ;
  ANTENNAGATEAREA                0.06300         LAYER MET3 ;
  ANTENNAPARTIALMETALAREA        0.09890         LAYER MET1 ;
  ANTENNAPARTIALMETALAREA        0.10380         LAYER MET2 ;
  ANTENNAMAXAREACAR              0.72381         LAYER MET1 ;
  ANTENNAMAXAREACAR              3.54286         LAYER MET2 ;
  ANTENNAMAXAREACAR              4.71429         LAYER MET3 ;
END D[117]
PIN Q[117]
  DIRECTION OUTPUT ;
  PORT
    LAYER MET1 ;
    RECT 521.750 0.000 522.160 0.180 ;
    LAYER MET2 ;
    RECT 521.750 0.000 522.160 0.180 ;
    LAYER MET3 ;
    RECT 521.750 0.000 522.160 0.180 ;
  END
  ANTENNADIFFAREA                0.60000         LAYER MET1 ;
  ANTENNADIFFAREA                0.60000         LAYER MET2 ;
  ANTENNADIFFAREA                0.60000         LAYER MET3 ;
  ANTENNAPARTIALMETALAREA        0.94400         LAYER MET1 ;
  ANTENNAPARTIALMETALAREA        1.33320         LAYER MET2 ;
END Q[117]
PIN D[118]
  DIRECTION INPUT ;
  PORT
    LAYER MET1 ;
    RECT 527.490 0.000 527.900 0.180 ;
    LAYER MET2 ;
    RECT 527.490 0.000 527.900 0.180 ;
    LAYER MET3 ;
    RECT 527.490 0.000 527.900 0.180 ;
  END
  ANTENNADIFFAREA                0.38930         LAYER MET1 ;
  ANTENNADIFFAREA                0.38930         LAYER MET2 ;
  ANTENNADIFFAREA                0.38930         LAYER MET3 ;
  ANTENNAGATEAREA                0.06300         LAYER MET1 ;
  ANTENNAGATEAREA                0.06300         LAYER MET2 ;
  ANTENNAGATEAREA                0.06300         LAYER MET3 ;
  ANTENNAPARTIALMETALAREA        0.09890         LAYER MET1 ;
  ANTENNAPARTIALMETALAREA        0.10380         LAYER MET2 ;
  ANTENNAMAXAREACAR              0.72381         LAYER MET1 ;
  ANTENNAMAXAREACAR              3.54286         LAYER MET2 ;
  ANTENNAMAXAREACAR              4.71429         LAYER MET3 ;
END D[118]
PIN Q[118]
  DIRECTION OUTPUT ;
  PORT
    LAYER MET1 ;
    RECT 525.950 0.000 526.360 0.180 ;
    LAYER MET2 ;
    RECT 525.950 0.000 526.360 0.180 ;
    LAYER MET3 ;
    RECT 525.950 0.000 526.360 0.180 ;
  END
  ANTENNADIFFAREA                0.60000         LAYER MET1 ;
  ANTENNADIFFAREA                0.60000         LAYER MET2 ;
  ANTENNADIFFAREA                0.60000         LAYER MET3 ;
  ANTENNAPARTIALMETALAREA        0.94400         LAYER MET1 ;
  ANTENNAPARTIALMETALAREA        1.33320         LAYER MET2 ;
END Q[118]
PIN D[119]
  DIRECTION INPUT ;
  PORT
    LAYER MET1 ;
    RECT 531.690 0.000 532.100 0.180 ;
    LAYER MET2 ;
    RECT 531.690 0.000 532.100 0.180 ;
    LAYER MET3 ;
    RECT 531.690 0.000 532.100 0.180 ;
  END
  ANTENNADIFFAREA                0.38930         LAYER MET1 ;
  ANTENNADIFFAREA                0.38930         LAYER MET2 ;
  ANTENNADIFFAREA                0.38930         LAYER MET3 ;
  ANTENNAGATEAREA                0.06300         LAYER MET1 ;
  ANTENNAGATEAREA                0.06300         LAYER MET2 ;
  ANTENNAGATEAREA                0.06300         LAYER MET3 ;
  ANTENNAPARTIALMETALAREA        0.09890         LAYER MET1 ;
  ANTENNAPARTIALMETALAREA        0.10380         LAYER MET2 ;
  ANTENNAMAXAREACAR              0.72381         LAYER MET1 ;
  ANTENNAMAXAREACAR              3.54286         LAYER MET2 ;
  ANTENNAMAXAREACAR              4.71429         LAYER MET3 ;
END D[119]
PIN Q[119]
  DIRECTION OUTPUT ;
  PORT
    LAYER MET1 ;
    RECT 530.150 0.000 530.560 0.180 ;
    LAYER MET2 ;
    RECT 530.150 0.000 530.560 0.180 ;
    LAYER MET3 ;
    RECT 530.150 0.000 530.560 0.180 ;
  END
  ANTENNADIFFAREA                0.60000         LAYER MET1 ;
  ANTENNADIFFAREA                0.60000         LAYER MET2 ;
  ANTENNADIFFAREA                0.60000         LAYER MET3 ;
  ANTENNAPARTIALMETALAREA        0.94400         LAYER MET1 ;
  ANTENNAPARTIALMETALAREA        1.33320         LAYER MET2 ;
END Q[119]
PIN D[120]
  DIRECTION INPUT ;
  PORT
    LAYER MET1 ;
    RECT 535.890 0.000 536.300 0.180 ;
    LAYER MET2 ;
    RECT 535.890 0.000 536.300 0.180 ;
    LAYER MET3 ;
    RECT 535.890 0.000 536.300 0.180 ;
  END
  ANTENNADIFFAREA                0.38930         LAYER MET1 ;
  ANTENNADIFFAREA                0.38930         LAYER MET2 ;
  ANTENNADIFFAREA                0.38930         LAYER MET3 ;
  ANTENNAGATEAREA                0.06300         LAYER MET1 ;
  ANTENNAGATEAREA                0.06300         LAYER MET2 ;
  ANTENNAGATEAREA                0.06300         LAYER MET3 ;
  ANTENNAPARTIALMETALAREA        0.09890         LAYER MET1 ;
  ANTENNAPARTIALMETALAREA        0.10380         LAYER MET2 ;
  ANTENNAMAXAREACAR              0.72381         LAYER MET1 ;
  ANTENNAMAXAREACAR              3.54286         LAYER MET2 ;
  ANTENNAMAXAREACAR              4.71429         LAYER MET3 ;
END D[120]
PIN Q[120]
  DIRECTION OUTPUT ;
  PORT
    LAYER MET1 ;
    RECT 534.350 0.000 534.760 0.180 ;
    LAYER MET2 ;
    RECT 534.350 0.000 534.760 0.180 ;
    LAYER MET3 ;
    RECT 534.350 0.000 534.760 0.180 ;
  END
  ANTENNADIFFAREA                0.60000         LAYER MET1 ;
  ANTENNADIFFAREA                0.60000         LAYER MET2 ;
  ANTENNADIFFAREA                0.60000         LAYER MET3 ;
  ANTENNAPARTIALMETALAREA        0.94400         LAYER MET1 ;
  ANTENNAPARTIALMETALAREA        1.33320         LAYER MET2 ;
END Q[120]
PIN D[122]
  DIRECTION INPUT ;
  PORT
    LAYER MET1 ;
    RECT 544.290 0.000 544.700 0.180 ;
    LAYER MET2 ;
    RECT 544.290 0.000 544.700 0.180 ;
    LAYER MET3 ;
    RECT 544.290 0.000 544.700 0.180 ;
  END
  ANTENNADIFFAREA                0.38930         LAYER MET1 ;
  ANTENNADIFFAREA                0.38930         LAYER MET2 ;
  ANTENNADIFFAREA                0.38930         LAYER MET3 ;
  ANTENNAGATEAREA                0.06300         LAYER MET1 ;
  ANTENNAGATEAREA                0.06300         LAYER MET2 ;
  ANTENNAGATEAREA                0.06300         LAYER MET3 ;
  ANTENNAPARTIALMETALAREA        0.09890         LAYER MET1 ;
  ANTENNAPARTIALMETALAREA        0.10380         LAYER MET2 ;
  ANTENNAMAXAREACAR              0.72381         LAYER MET1 ;
  ANTENNAMAXAREACAR              3.54286         LAYER MET2 ;
  ANTENNAMAXAREACAR              4.71429         LAYER MET3 ;
END D[122]
PIN Q[122]
  DIRECTION OUTPUT ;
  PORT
    LAYER MET1 ;
    RECT 542.750 0.000 543.160 0.180 ;
    LAYER MET2 ;
    RECT 542.750 0.000 543.160 0.180 ;
    LAYER MET3 ;
    RECT 542.750 0.000 543.160 0.180 ;
  END
  ANTENNADIFFAREA                0.60000         LAYER MET1 ;
  ANTENNADIFFAREA                0.60000         LAYER MET2 ;
  ANTENNADIFFAREA                0.60000         LAYER MET3 ;
  ANTENNAPARTIALMETALAREA        0.94400         LAYER MET1 ;
  ANTENNAPARTIALMETALAREA        1.33320         LAYER MET2 ;
END Q[122]
PIN D[123]
  DIRECTION INPUT ;
  PORT
    LAYER MET1 ;
    RECT 548.490 0.000 548.900 0.180 ;
    LAYER MET2 ;
    RECT 548.490 0.000 548.900 0.180 ;
    LAYER MET3 ;
    RECT 548.490 0.000 548.900 0.180 ;
  END
  ANTENNADIFFAREA                0.38930         LAYER MET1 ;
  ANTENNADIFFAREA                0.38930         LAYER MET2 ;
  ANTENNADIFFAREA                0.38930         LAYER MET3 ;
  ANTENNAGATEAREA                0.06300         LAYER MET1 ;
  ANTENNAGATEAREA                0.06300         LAYER MET2 ;
  ANTENNAGATEAREA                0.06300         LAYER MET3 ;
  ANTENNAPARTIALMETALAREA        0.09890         LAYER MET1 ;
  ANTENNAPARTIALMETALAREA        0.10380         LAYER MET2 ;
  ANTENNAMAXAREACAR              0.72381         LAYER MET1 ;
  ANTENNAMAXAREACAR              3.54286         LAYER MET2 ;
  ANTENNAMAXAREACAR              4.71429         LAYER MET3 ;
END D[123]
PIN Q[123]
  DIRECTION OUTPUT ;
  PORT
    LAYER MET1 ;
    RECT 546.950 0.000 547.360 0.180 ;
    LAYER MET2 ;
    RECT 546.950 0.000 547.360 0.180 ;
    LAYER MET3 ;
    RECT 546.950 0.000 547.360 0.180 ;
  END
  ANTENNADIFFAREA                0.60000         LAYER MET1 ;
  ANTENNADIFFAREA                0.60000         LAYER MET2 ;
  ANTENNADIFFAREA                0.60000         LAYER MET3 ;
  ANTENNAPARTIALMETALAREA        0.94400         LAYER MET1 ;
  ANTENNAPARTIALMETALAREA        1.33320         LAYER MET2 ;
END Q[123]
PIN D[124]
  DIRECTION INPUT ;
  PORT
    LAYER MET1 ;
    RECT 552.690 0.000 553.100 0.180 ;
    LAYER MET2 ;
    RECT 552.690 0.000 553.100 0.180 ;
    LAYER MET3 ;
    RECT 552.690 0.000 553.100 0.180 ;
  END
  ANTENNADIFFAREA                0.38930         LAYER MET1 ;
  ANTENNADIFFAREA                0.38930         LAYER MET2 ;
  ANTENNADIFFAREA                0.38930         LAYER MET3 ;
  ANTENNAGATEAREA                0.06300         LAYER MET1 ;
  ANTENNAGATEAREA                0.06300         LAYER MET2 ;
  ANTENNAGATEAREA                0.06300         LAYER MET3 ;
  ANTENNAPARTIALMETALAREA        0.09890         LAYER MET1 ;
  ANTENNAPARTIALMETALAREA        0.10380         LAYER MET2 ;
  ANTENNAMAXAREACAR              0.72381         LAYER MET1 ;
  ANTENNAMAXAREACAR              3.54286         LAYER MET2 ;
  ANTENNAMAXAREACAR              4.71429         LAYER MET3 ;
END D[124]
PIN Q[124]
  DIRECTION OUTPUT ;
  PORT
    LAYER MET1 ;
    RECT 551.150 0.000 551.560 0.180 ;
    LAYER MET2 ;
    RECT 551.150 0.000 551.560 0.180 ;
    LAYER MET3 ;
    RECT 551.150 0.000 551.560 0.180 ;
  END
  ANTENNADIFFAREA                0.60000         LAYER MET1 ;
  ANTENNADIFFAREA                0.60000         LAYER MET2 ;
  ANTENNADIFFAREA                0.60000         LAYER MET3 ;
  ANTENNAPARTIALMETALAREA        0.94400         LAYER MET1 ;
  ANTENNAPARTIALMETALAREA        1.33320         LAYER MET2 ;
END Q[124]
PIN D[125]
  DIRECTION INPUT ;
  PORT
    LAYER MET1 ;
    RECT 556.890 0.000 557.300 0.180 ;
    LAYER MET2 ;
    RECT 556.890 0.000 557.300 0.180 ;
    LAYER MET3 ;
    RECT 556.890 0.000 557.300 0.180 ;
  END
  ANTENNADIFFAREA                0.38930         LAYER MET1 ;
  ANTENNADIFFAREA                0.38930         LAYER MET2 ;
  ANTENNADIFFAREA                0.38930         LAYER MET3 ;
  ANTENNAGATEAREA                0.06300         LAYER MET1 ;
  ANTENNAGATEAREA                0.06300         LAYER MET2 ;
  ANTENNAGATEAREA                0.06300         LAYER MET3 ;
  ANTENNAPARTIALMETALAREA        0.09890         LAYER MET1 ;
  ANTENNAPARTIALMETALAREA        0.10380         LAYER MET2 ;
  ANTENNAMAXAREACAR              0.72381         LAYER MET1 ;
  ANTENNAMAXAREACAR              3.54286         LAYER MET2 ;
  ANTENNAMAXAREACAR              4.71429         LAYER MET3 ;
END D[125]
PIN Q[125]
  DIRECTION OUTPUT ;
  PORT
    LAYER MET1 ;
    RECT 555.350 0.000 555.760 0.180 ;
    LAYER MET2 ;
    RECT 555.350 0.000 555.760 0.180 ;
    LAYER MET3 ;
    RECT 555.350 0.000 555.760 0.180 ;
  END
  ANTENNADIFFAREA                0.60000         LAYER MET1 ;
  ANTENNADIFFAREA                0.60000         LAYER MET2 ;
  ANTENNADIFFAREA                0.60000         LAYER MET3 ;
  ANTENNAPARTIALMETALAREA        0.94400         LAYER MET1 ;
  ANTENNAPARTIALMETALAREA        1.33320         LAYER MET2 ;
END Q[125]
PIN D[126]
  DIRECTION INPUT ;
  PORT
    LAYER MET1 ;
    RECT 561.090 0.000 561.500 0.180 ;
    LAYER MET2 ;
    RECT 561.090 0.000 561.500 0.180 ;
    LAYER MET3 ;
    RECT 561.090 0.000 561.500 0.180 ;
  END
  ANTENNADIFFAREA                0.38930         LAYER MET1 ;
  ANTENNADIFFAREA                0.38930         LAYER MET2 ;
  ANTENNADIFFAREA                0.38930         LAYER MET3 ;
  ANTENNAGATEAREA                0.06300         LAYER MET1 ;
  ANTENNAGATEAREA                0.06300         LAYER MET2 ;
  ANTENNAGATEAREA                0.06300         LAYER MET3 ;
  ANTENNAPARTIALMETALAREA        0.09890         LAYER MET1 ;
  ANTENNAPARTIALMETALAREA        0.10380         LAYER MET2 ;
  ANTENNAMAXAREACAR              0.72381         LAYER MET1 ;
  ANTENNAMAXAREACAR              3.54286         LAYER MET2 ;
  ANTENNAMAXAREACAR              4.71429         LAYER MET3 ;
END D[126]
PIN Q[126]
  DIRECTION OUTPUT ;
  PORT
    LAYER MET1 ;
    RECT 559.550 0.000 559.960 0.180 ;
    LAYER MET2 ;
    RECT 559.550 0.000 559.960 0.180 ;
    LAYER MET3 ;
    RECT 559.550 0.000 559.960 0.180 ;
  END
  ANTENNADIFFAREA                0.60000         LAYER MET1 ;
  ANTENNADIFFAREA                0.60000         LAYER MET2 ;
  ANTENNADIFFAREA                0.60000         LAYER MET3 ;
  ANTENNAPARTIALMETALAREA        0.94400         LAYER MET1 ;
  ANTENNAPARTIALMETALAREA        1.33320         LAYER MET2 ;
END Q[126]
PIN D[127]
  DIRECTION INPUT ;
  PORT
    LAYER MET1 ;
    RECT 565.290 0.000 565.700 0.180 ;
    LAYER MET2 ;
    RECT 565.290 0.000 565.700 0.180 ;
    LAYER MET3 ;
    RECT 565.290 0.000 565.700 0.180 ;
  END
  ANTENNADIFFAREA                0.38930         LAYER MET1 ;
  ANTENNADIFFAREA                0.38930         LAYER MET2 ;
  ANTENNADIFFAREA                0.38930         LAYER MET3 ;
  ANTENNAGATEAREA                0.06300         LAYER MET1 ;
  ANTENNAGATEAREA                0.06300         LAYER MET2 ;
  ANTENNAGATEAREA                0.06300         LAYER MET3 ;
  ANTENNAPARTIALMETALAREA        0.09890         LAYER MET1 ;
  ANTENNAPARTIALMETALAREA        0.10380         LAYER MET2 ;
  ANTENNAMAXAREACAR              0.72381         LAYER MET1 ;
  ANTENNAMAXAREACAR              3.54286         LAYER MET2 ;
  ANTENNAMAXAREACAR              4.71429         LAYER MET3 ;
END D[127]
PIN Q[127]
  DIRECTION OUTPUT ;
  PORT
    LAYER MET1 ;
    RECT 563.750 0.000 564.160 0.180 ;
    LAYER MET2 ;
    RECT 563.750 0.000 564.160 0.180 ;
    LAYER MET3 ;
    RECT 563.750 0.000 564.160 0.180 ;
  END
  ANTENNADIFFAREA                0.60000         LAYER MET1 ;
  ANTENNADIFFAREA                0.60000         LAYER MET2 ;
  ANTENNADIFFAREA                0.60000         LAYER MET3 ;
  ANTENNAPARTIALMETALAREA        0.94400         LAYER MET1 ;
  ANTENNAPARTIALMETALAREA        1.33320         LAYER MET2 ;
END Q[127]
OBS
  LAYER MET1 SPACING 0.090 ;
    POLYGON 567.630 0.000 567.630 58.535 
            0.000 58.535 0.000 0.000 
            3.000 0.000 3.000 0.180 
            3.410 0.180 3.410 0.000 
            4.540 0.000 4.540 0.180 
            4.950 0.180 4.950 0.000 
            7.200 0.000 7.200 0.180 
            7.610 0.180 7.610 0.000 
            8.740 0.000 8.740 0.180 
            9.150 0.180 9.150 0.000 
            11.400 0.000 11.400 0.180 
            11.810 0.180 11.810 0.000 
            12.940 0.000 12.940 0.180 
            13.350 0.180 13.350 0.000 
            15.600 0.000 15.600 0.180 
            16.010 0.180 16.010 0.000 
            17.140 0.000 17.140 0.180 
            17.550 0.180 17.550 0.000 
            19.800 0.000 19.800 0.180 
            20.210 0.180 20.210 0.000 
            21.340 0.000 21.340 0.180 
            21.750 0.180 21.750 0.000 
            24.000 0.000 24.000 0.180 
            24.410 0.180 24.410 0.000 
            25.540 0.000 25.540 0.180 
            25.950 0.180 25.950 0.000 
            28.200 0.000 28.200 0.180 
            28.610 0.180 28.610 0.000 
            29.740 0.000 29.740 0.180 
            30.150 0.180 30.150 0.000 
            32.400 0.000 32.400 0.180 
            32.810 0.180 32.810 0.000 
            33.940 0.000 33.940 0.180 
            34.350 0.180 34.350 0.000 
            36.600 0.000 36.600 0.180 
            37.010 0.180 37.010 0.000 
            38.140 0.000 38.140 0.180 
            38.550 0.180 38.550 0.000 
            40.800 0.000 40.800 0.180 
            41.210 0.180 41.210 0.000 
            42.340 0.000 42.340 0.180 
            42.750 0.180 42.750 0.000 
            45.000 0.000 45.000 0.180 
            45.410 0.180 45.410 0.000 
            46.540 0.000 46.540 0.180 
            46.950 0.180 46.950 0.000 
            49.200 0.000 49.200 0.180 
            49.610 0.180 49.610 0.000 
            50.740 0.000 50.740 0.180 
            51.150 0.180 51.150 0.000 
            53.400 0.000 53.400 0.180 
            53.810 0.180 53.810 0.000 
            54.940 0.000 54.940 0.180 
            55.350 0.180 55.350 0.000 
            57.600 0.000 57.600 0.180 
            58.010 0.180 58.010 0.000 
            59.140 0.000 59.140 0.180 
            59.550 0.180 59.550 0.000 
            61.800 0.000 61.800 0.180 
            62.210 0.180 62.210 0.000 
            63.340 0.000 63.340 0.180 
            63.750 0.180 63.750 0.000 
            66.000 0.000 66.000 0.180 
            66.410 0.180 66.410 0.000 
            67.540 0.000 67.540 0.180 
            67.950 0.180 67.950 0.000 
            70.200 0.000 70.200 0.180 
            70.610 0.180 70.610 0.000 
            71.740 0.000 71.740 0.180 
            72.150 0.180 72.150 0.000 
            74.400 0.000 74.400 0.180 
            74.810 0.180 74.810 0.000 
            75.940 0.000 75.940 0.180 
            76.350 0.180 76.350 0.000 
            78.600 0.000 78.600 0.180 
            79.010 0.180 79.010 0.000 
            80.140 0.000 80.140 0.180 
            80.550 0.180 80.550 0.000 
            82.800 0.000 82.800 0.180 
            83.210 0.180 83.210 0.000 
            84.340 0.000 84.340 0.180 
            84.750 0.180 84.750 0.000 
            87.000 0.000 87.000 0.180 
            87.410 0.180 87.410 0.000 
            88.540 0.000 88.540 0.180 
            88.950 0.180 88.950 0.000 
            91.200 0.000 91.200 0.180 
            91.610 0.180 91.610 0.000 
            92.740 0.000 92.740 0.180 
            93.150 0.180 93.150 0.000 
            95.400 0.000 95.400 0.180 
            95.810 0.180 95.810 0.000 
            96.940 0.000 96.940 0.180 
            97.350 0.180 97.350 0.000 
            99.600 0.000 99.600 0.180 
            100.010 0.180 100.010 0.000 
            101.140 0.000 101.140 0.180 
            101.550 0.180 101.550 0.000 
            103.800 0.000 103.800 0.180 
            104.210 0.180 104.210 0.000 
            105.340 0.000 105.340 0.180 
            105.750 0.180 105.750 0.000 
            108.000 0.000 108.000 0.180 
            108.410 0.180 108.410 0.000 
            109.540 0.000 109.540 0.180 
            109.950 0.180 109.950 0.000 
            112.200 0.000 112.200 0.180 
            112.610 0.180 112.610 0.000 
            113.740 0.000 113.740 0.180 
            114.150 0.180 114.150 0.000 
            116.400 0.000 116.400 0.180 
            116.810 0.180 116.810 0.000 
            117.940 0.000 117.940 0.180 
            118.350 0.180 118.350 0.000 
            120.600 0.000 120.600 0.180 
            121.010 0.180 121.010 0.000 
            122.140 0.000 122.140 0.180 
            122.550 0.180 122.550 0.000 
            124.800 0.000 124.800 0.180 
            125.210 0.180 125.210 0.000 
            126.340 0.000 126.340 0.180 
            126.750 0.180 126.750 0.000 
            129.000 0.000 129.000 0.180 
            129.410 0.180 129.410 0.000 
            130.540 0.000 130.540 0.180 
            130.950 0.180 130.950 0.000 
            133.200 0.000 133.200 0.180 
            133.610 0.180 133.610 0.000 
            134.740 0.000 134.740 0.180 
            135.150 0.180 135.150 0.000 
            137.400 0.000 137.400 0.180 
            137.810 0.180 137.810 0.000 
            138.940 0.000 138.940 0.180 
            139.350 0.180 139.350 0.000 
            141.600 0.000 141.600 0.180 
            142.010 0.180 142.010 0.000 
            143.140 0.000 143.140 0.180 
            143.550 0.180 143.550 0.000 
            145.800 0.000 145.800 0.180 
            146.210 0.180 146.210 0.000 
            147.340 0.000 147.340 0.180 
            147.750 0.180 147.750 0.000 
            150.000 0.000 150.000 0.180 
            150.410 0.180 150.410 0.000 
            151.540 0.000 151.540 0.180 
            151.950 0.180 151.950 0.000 
            154.200 0.000 154.200 0.180 
            154.610 0.180 154.610 0.000 
            155.740 0.000 155.740 0.180 
            156.150 0.180 156.150 0.000 
            158.400 0.000 158.400 0.180 
            158.810 0.180 158.810 0.000 
            159.940 0.000 159.940 0.180 
            160.350 0.180 160.350 0.000 
            162.600 0.000 162.600 0.180 
            163.010 0.180 163.010 0.000 
            164.140 0.000 164.140 0.180 
            164.550 0.180 164.550 0.000 
            166.800 0.000 166.800 0.180 
            167.210 0.180 167.210 0.000 
            168.340 0.000 168.340 0.180 
            168.750 0.180 168.750 0.000 
            171.000 0.000 171.000 0.180 
            171.410 0.180 171.410 0.000 
            172.540 0.000 172.540 0.180 
            172.950 0.180 172.950 0.000 
            175.200 0.000 175.200 0.180 
            175.610 0.180 175.610 0.000 
            176.740 0.000 176.740 0.180 
            177.150 0.180 177.150 0.000 
            179.400 0.000 179.400 0.180 
            179.810 0.180 179.810 0.000 
            180.940 0.000 180.940 0.180 
            181.350 0.180 181.350 0.000 
            183.600 0.000 183.600 0.180 
            184.010 0.180 184.010 0.000 
            185.140 0.000 185.140 0.180 
            185.550 0.180 185.550 0.000 
            187.800 0.000 187.800 0.180 
            188.210 0.180 188.210 0.000 
            189.340 0.000 189.340 0.180 
            189.750 0.180 189.750 0.000 
            192.000 0.000 192.000 0.180 
            192.410 0.180 192.410 0.000 
            193.540 0.000 193.540 0.180 
            193.950 0.180 193.950 0.000 
            196.200 0.000 196.200 0.180 
            196.610 0.180 196.610 0.000 
            197.740 0.000 197.740 0.180 
            198.150 0.180 198.150 0.000 
            200.400 0.000 200.400 0.180 
            200.810 0.180 200.810 0.000 
            201.940 0.000 201.940 0.180 
            202.350 0.180 202.350 0.000 
            204.600 0.000 204.600 0.180 
            205.010 0.180 205.010 0.000 
            206.140 0.000 206.140 0.180 
            206.550 0.180 206.550 0.000 
            208.800 0.000 208.800 0.180 
            209.210 0.180 209.210 0.000 
            210.340 0.000 210.340 0.180 
            210.750 0.180 210.750 0.000 
            213.000 0.000 213.000 0.180 
            213.410 0.180 213.410 0.000 
            214.540 0.000 214.540 0.180 
            214.950 0.180 214.950 0.000 
            217.200 0.000 217.200 0.180 
            217.610 0.180 217.610 0.000 
            218.740 0.000 218.740 0.180 
            219.150 0.180 219.150 0.000 
            221.400 0.000 221.400 0.180 
            221.810 0.180 221.810 0.000 
            222.940 0.000 222.940 0.180 
            223.350 0.180 223.350 0.000 
            225.600 0.000 225.600 0.180 
            226.010 0.180 226.010 0.000 
            227.140 0.000 227.140 0.180 
            227.550 0.180 227.550 0.000 
            229.800 0.000 229.800 0.180 
            230.210 0.180 230.210 0.000 
            231.340 0.000 231.340 0.180 
            231.750 0.180 231.750 0.000 
            234.000 0.000 234.000 0.180 
            234.410 0.180 234.410 0.000 
            235.540 0.000 235.540 0.180 
            235.950 0.180 235.950 0.000 
            238.200 0.000 238.200 0.180 
            238.610 0.180 238.610 0.000 
            239.740 0.000 239.740 0.180 
            240.150 0.180 240.150 0.000 
            242.400 0.000 242.400 0.180 
            242.810 0.180 242.810 0.000 
            243.940 0.000 243.940 0.180 
            244.350 0.180 244.350 0.000 
            246.600 0.000 246.600 0.180 
            247.010 0.180 247.010 0.000 
            248.140 0.000 248.140 0.180 
            248.550 0.180 248.550 0.000 
            250.800 0.000 250.800 0.180 
            251.210 0.180 251.210 0.000 
            252.340 0.000 252.340 0.180 
            252.750 0.180 252.750 0.000 
            255.000 0.000 255.000 0.180 
            255.410 0.180 255.410 0.000 
            256.540 0.000 256.540 0.180 
            256.950 0.180 256.950 0.000 
            259.200 0.000 259.200 0.180 
            259.610 0.180 259.610 0.000 
            260.740 0.000 260.740 0.180 
            261.150 0.180 261.150 0.000 
            263.400 0.000 263.400 0.180 
            263.810 0.180 263.810 0.000 
            264.940 0.000 264.940 0.180 
            265.350 0.180 265.350 0.000 
            267.600 0.000 267.600 0.180 
            268.010 0.180 268.010 0.000 
            269.140 0.000 269.140 0.180 
            269.550 0.180 269.550 0.000 
            274.550 0.000 274.550 0.180 
            274.960 0.180 274.960 0.000 
            275.080 0.000 275.080 0.180 
            275.490 0.180 275.490 0.000 
            275.900 0.000 275.900 0.180 
            276.310 0.180 276.310 0.000 
            276.480 0.000 276.480 0.180 
            276.890 0.180 276.890 0.000 
            277.540 0.000 277.540 0.180 
            277.950 0.180 277.950 0.000 
            278.085 0.000 278.085 0.180 
            278.495 0.180 278.495 0.000 
            278.615 0.000 278.615 0.180 
            279.025 0.180 279.025 0.000 
            279.145 0.000 279.145 0.180 
            279.555 0.180 279.555 0.000 
            279.675 0.000 279.675 0.180 
            280.085 0.180 280.085 0.000 
            280.205 0.000 280.205 0.180 
            280.615 0.180 280.615 0.000 
            280.865 0.000 280.865 0.180 
            281.275 0.180 281.275 0.000 
            281.990 0.000 281.990 0.180 
            282.400 0.180 282.400 0.000 
            289.610 0.000 289.610 0.180 
            290.020 0.180 290.020 0.000 
            290.300 0.000 290.300 0.180 
            290.710 0.180 290.710 0.000 
            293.275 0.000 293.275 0.180 
            293.685 0.180 293.685 0.000 
            293.990 0.000 293.990 0.180 
            294.400 0.180 294.400 0.000 
            299.150 0.000 299.150 0.180 
            299.560 0.180 299.560 0.000 
            300.690 0.000 300.690 0.180 
            301.100 0.180 301.100 0.000 
            303.350 0.000 303.350 0.180 
            303.760 0.180 303.760 0.000 
            304.890 0.000 304.890 0.180 
            305.300 0.180 305.300 0.000 
            307.550 0.000 307.550 0.180 
            307.960 0.180 307.960 0.000 
            309.090 0.000 309.090 0.180 
            309.500 0.180 309.500 0.000 
            311.750 0.000 311.750 0.180 
            312.160 0.180 312.160 0.000 
            313.290 0.000 313.290 0.180 
            313.700 0.180 313.700 0.000 
            315.950 0.000 315.950 0.180 
            316.360 0.180 316.360 0.000 
            317.490 0.000 317.490 0.180 
            317.900 0.180 317.900 0.000 
            320.150 0.000 320.150 0.180 
            320.560 0.180 320.560 0.000 
            321.690 0.000 321.690 0.180 
            322.100 0.180 322.100 0.000 
            324.350 0.000 324.350 0.180 
            324.760 0.180 324.760 0.000 
            325.890 0.000 325.890 0.180 
            326.300 0.180 326.300 0.000 
            328.550 0.000 328.550 0.180 
            328.960 0.180 328.960 0.000 
            330.090 0.000 330.090 0.180 
            330.500 0.180 330.500 0.000 
            332.750 0.000 332.750 0.180 
            333.160 0.180 333.160 0.000 
            334.290 0.000 334.290 0.180 
            334.700 0.180 334.700 0.000 
            336.950 0.000 336.950 0.180 
            337.360 0.180 337.360 0.000 
            338.490 0.000 338.490 0.180 
            338.900 0.180 338.900 0.000 
            341.150 0.000 341.150 0.180 
            341.560 0.180 341.560 0.000 
            342.690 0.000 342.690 0.180 
            343.100 0.180 343.100 0.000 
            345.350 0.000 345.350 0.180 
            345.760 0.180 345.760 0.000 
            346.890 0.000 346.890 0.180 
            347.300 0.180 347.300 0.000 
            349.550 0.000 349.550 0.180 
            349.960 0.180 349.960 0.000 
            351.090 0.000 351.090 0.180 
            351.500 0.180 351.500 0.000 
            353.750 0.000 353.750 0.180 
            354.160 0.180 354.160 0.000 
            355.290 0.000 355.290 0.180 
            355.700 0.180 355.700 0.000 
            357.950 0.000 357.950 0.180 
            358.360 0.180 358.360 0.000 
            359.490 0.000 359.490 0.180 
            359.900 0.180 359.900 0.000 
            362.150 0.000 362.150 0.180 
            362.560 0.180 362.560 0.000 
            363.690 0.000 363.690 0.180 
            364.100 0.180 364.100 0.000 
            366.350 0.000 366.350 0.180 
            366.760 0.180 366.760 0.000 
            367.890 0.000 367.890 0.180 
            368.300 0.180 368.300 0.000 
            370.550 0.000 370.550 0.180 
            370.960 0.180 370.960 0.000 
            372.090 0.000 372.090 0.180 
            372.500 0.180 372.500 0.000 
            374.750 0.000 374.750 0.180 
            375.160 0.180 375.160 0.000 
            376.290 0.000 376.290 0.180 
            376.700 0.180 376.700 0.000 
            378.950 0.000 378.950 0.180 
            379.360 0.180 379.360 0.000 
            380.490 0.000 380.490 0.180 
            380.900 0.180 380.900 0.000 
            383.150 0.000 383.150 0.180 
            383.560 0.180 383.560 0.000 
            384.690 0.000 384.690 0.180 
            385.100 0.180 385.100 0.000 
            387.350 0.000 387.350 0.180 
            387.760 0.180 387.760 0.000 
            388.890 0.000 388.890 0.180 
            389.300 0.180 389.300 0.000 
            391.550 0.000 391.550 0.180 
            391.960 0.180 391.960 0.000 
            393.090 0.000 393.090 0.180 
            393.500 0.180 393.500 0.000 
            395.750 0.000 395.750 0.180 
            396.160 0.180 396.160 0.000 
            397.290 0.000 397.290 0.180 
            397.700 0.180 397.700 0.000 
            399.950 0.000 399.950 0.180 
            400.360 0.180 400.360 0.000 
            401.490 0.000 401.490 0.180 
            401.900 0.180 401.900 0.000 
            404.150 0.000 404.150 0.180 
            404.560 0.180 404.560 0.000 
            405.690 0.000 405.690 0.180 
            406.100 0.180 406.100 0.000 
            408.350 0.000 408.350 0.180 
            408.760 0.180 408.760 0.000 
            409.890 0.000 409.890 0.180 
            410.300 0.180 410.300 0.000 
            412.550 0.000 412.550 0.180 
            412.960 0.180 412.960 0.000 
            414.090 0.000 414.090 0.180 
            414.500 0.180 414.500 0.000 
            416.750 0.000 416.750 0.180 
            417.160 0.180 417.160 0.000 
            418.290 0.000 418.290 0.180 
            418.700 0.180 418.700 0.000 
            420.950 0.000 420.950 0.180 
            421.360 0.180 421.360 0.000 
            422.490 0.000 422.490 0.180 
            422.900 0.180 422.900 0.000 
            425.150 0.000 425.150 0.180 
            425.560 0.180 425.560 0.000 
            426.690 0.000 426.690 0.180 
            427.100 0.180 427.100 0.000 
            429.350 0.000 429.350 0.180 
            429.760 0.180 429.760 0.000 
            430.890 0.000 430.890 0.180 
            431.300 0.180 431.300 0.000 
            433.550 0.000 433.550 0.180 
            433.960 0.180 433.960 0.000 
            435.090 0.000 435.090 0.180 
            435.500 0.180 435.500 0.000 
            437.750 0.000 437.750 0.180 
            438.160 0.180 438.160 0.000 
            439.290 0.000 439.290 0.180 
            439.700 0.180 439.700 0.000 
            441.950 0.000 441.950 0.180 
            442.360 0.180 442.360 0.000 
            443.490 0.000 443.490 0.180 
            443.900 0.180 443.900 0.000 
            446.150 0.000 446.150 0.180 
            446.560 0.180 446.560 0.000 
            447.690 0.000 447.690 0.180 
            448.100 0.180 448.100 0.000 
            450.350 0.000 450.350 0.180 
            450.760 0.180 450.760 0.000 
            451.890 0.000 451.890 0.180 
            452.300 0.180 452.300 0.000 
            454.550 0.000 454.550 0.180 
            454.960 0.180 454.960 0.000 
            456.090 0.000 456.090 0.180 
            456.500 0.180 456.500 0.000 
            458.750 0.000 458.750 0.180 
            459.160 0.180 459.160 0.000 
            460.290 0.000 460.290 0.180 
            460.700 0.180 460.700 0.000 
            462.950 0.000 462.950 0.180 
            463.360 0.180 463.360 0.000 
            464.490 0.000 464.490 0.180 
            464.900 0.180 464.900 0.000 
            467.150 0.000 467.150 0.180 
            467.560 0.180 467.560 0.000 
            468.690 0.000 468.690 0.180 
            469.100 0.180 469.100 0.000 
            471.350 0.000 471.350 0.180 
            471.760 0.180 471.760 0.000 
            472.890 0.000 472.890 0.180 
            473.300 0.180 473.300 0.000 
            475.550 0.000 475.550 0.180 
            475.960 0.180 475.960 0.000 
            477.090 0.000 477.090 0.180 
            477.500 0.180 477.500 0.000 
            479.750 0.000 479.750 0.180 
            480.160 0.180 480.160 0.000 
            481.290 0.000 481.290 0.180 
            481.700 0.180 481.700 0.000 
            483.950 0.000 483.950 0.180 
            484.360 0.180 484.360 0.000 
            485.490 0.000 485.490 0.180 
            485.900 0.180 485.900 0.000 
            488.150 0.000 488.150 0.180 
            488.560 0.180 488.560 0.000 
            489.690 0.000 489.690 0.180 
            490.100 0.180 490.100 0.000 
            492.350 0.000 492.350 0.180 
            492.760 0.180 492.760 0.000 
            493.890 0.000 493.890 0.180 
            494.300 0.180 494.300 0.000 
            496.550 0.000 496.550 0.180 
            496.960 0.180 496.960 0.000 
            498.090 0.000 498.090 0.180 
            498.500 0.180 498.500 0.000 
            500.750 0.000 500.750 0.180 
            501.160 0.180 501.160 0.000 
            502.290 0.000 502.290 0.180 
            502.700 0.180 502.700 0.000 
            504.950 0.000 504.950 0.180 
            505.360 0.180 505.360 0.000 
            506.490 0.000 506.490 0.180 
            506.900 0.180 506.900 0.000 
            509.150 0.000 509.150 0.180 
            509.560 0.180 509.560 0.000 
            510.690 0.000 510.690 0.180 
            511.100 0.180 511.100 0.000 
            513.350 0.000 513.350 0.180 
            513.760 0.180 513.760 0.000 
            514.890 0.000 514.890 0.180 
            515.300 0.180 515.300 0.000 
            517.550 0.000 517.550 0.180 
            517.960 0.180 517.960 0.000 
            519.090 0.000 519.090 0.180 
            519.500 0.180 519.500 0.000 
            521.750 0.000 521.750 0.180 
            522.160 0.180 522.160 0.000 
            523.290 0.000 523.290 0.180 
            523.700 0.180 523.700 0.000 
            525.950 0.000 525.950 0.180 
            526.360 0.180 526.360 0.000 
            527.490 0.000 527.490 0.180 
            527.900 0.180 527.900 0.000 
            530.150 0.000 530.150 0.180 
            530.560 0.180 530.560 0.000 
            531.690 0.000 531.690 0.180 
            532.100 0.180 532.100 0.000 
            534.350 0.000 534.350 0.180 
            534.760 0.180 534.760 0.000 
            535.890 0.000 535.890 0.180 
            536.300 0.180 536.300 0.000 
            538.550 0.000 538.550 0.180 
            538.960 0.180 538.960 0.000 
            540.090 0.000 540.090 0.180 
            540.500 0.180 540.500 0.000 
            542.750 0.000 542.750 0.180 
            543.160 0.180 543.160 0.000 
            544.290 0.000 544.290 0.180 
            544.700 0.180 544.700 0.000 
            546.950 0.000 546.950 0.180 
            547.360 0.180 547.360 0.000 
            548.490 0.000 548.490 0.180 
            548.900 0.180 548.900 0.000 
            551.150 0.000 551.150 0.180 
            551.560 0.180 551.560 0.000 
            552.690 0.000 552.690 0.180 
            553.100 0.180 553.100 0.000 
            555.350 0.000 555.350 0.180 
            555.760 0.180 555.760 0.000 
            556.890 0.000 556.890 0.180 
            557.300 0.180 557.300 0.000 
            559.550 0.000 559.550 0.180 
            559.960 0.180 559.960 0.000 
            561.090 0.000 561.090 0.180 
            561.500 0.180 561.500 0.000 
            563.750 0.000 563.750 0.180 
            564.160 0.180 564.160 0.000 
            565.290 0.000 565.290 0.180 
            565.700 0.180 565.700 0.000 
            567.630 0.000 ;
  LAYER VIA1 SPACING 0.110 ;
    RECT 0.000 0.000 567.630 58.535 ;
  LAYER MET2 SPACING 0.100 ;
    POLYGON 567.630 0.000 567.630 58.535 
            0.000 58.535 0.000 0.000 
            3.000 0.000 3.000 0.180 
            3.410 0.180 3.410 0.000 
            4.540 0.000 4.540 0.180 
            4.950 0.180 4.950 0.000 
            7.200 0.000 7.200 0.180 
            7.610 0.180 7.610 0.000 
            8.740 0.000 8.740 0.180 
            9.150 0.180 9.150 0.000 
            11.400 0.000 11.400 0.180 
            11.810 0.180 11.810 0.000 
            12.940 0.000 12.940 0.180 
            13.350 0.180 13.350 0.000 
            15.600 0.000 15.600 0.180 
            16.010 0.180 16.010 0.000 
            17.140 0.000 17.140 0.180 
            17.550 0.180 17.550 0.000 
            19.800 0.000 19.800 0.180 
            20.210 0.180 20.210 0.000 
            21.340 0.000 21.340 0.180 
            21.750 0.180 21.750 0.000 
            24.000 0.000 24.000 0.180 
            24.410 0.180 24.410 0.000 
            25.540 0.000 25.540 0.180 
            25.950 0.180 25.950 0.000 
            28.200 0.000 28.200 0.180 
            28.610 0.180 28.610 0.000 
            29.740 0.000 29.740 0.180 
            30.150 0.180 30.150 0.000 
            32.400 0.000 32.400 0.180 
            32.810 0.180 32.810 0.000 
            33.940 0.000 33.940 0.180 
            34.350 0.180 34.350 0.000 
            36.600 0.000 36.600 0.180 
            37.010 0.180 37.010 0.000 
            38.140 0.000 38.140 0.180 
            38.550 0.180 38.550 0.000 
            40.800 0.000 40.800 0.180 
            41.210 0.180 41.210 0.000 
            42.340 0.000 42.340 0.180 
            42.750 0.180 42.750 0.000 
            45.000 0.000 45.000 0.180 
            45.410 0.180 45.410 0.000 
            46.540 0.000 46.540 0.180 
            46.950 0.180 46.950 0.000 
            49.200 0.000 49.200 0.180 
            49.610 0.180 49.610 0.000 
            50.740 0.000 50.740 0.180 
            51.150 0.180 51.150 0.000 
            53.400 0.000 53.400 0.180 
            53.810 0.180 53.810 0.000 
            54.940 0.000 54.940 0.180 
            55.350 0.180 55.350 0.000 
            57.600 0.000 57.600 0.180 
            58.010 0.180 58.010 0.000 
            59.140 0.000 59.140 0.180 
            59.550 0.180 59.550 0.000 
            61.800 0.000 61.800 0.180 
            62.210 0.180 62.210 0.000 
            63.340 0.000 63.340 0.180 
            63.750 0.180 63.750 0.000 
            66.000 0.000 66.000 0.180 
            66.410 0.180 66.410 0.000 
            67.540 0.000 67.540 0.180 
            67.950 0.180 67.950 0.000 
            70.200 0.000 70.200 0.180 
            70.610 0.180 70.610 0.000 
            71.740 0.000 71.740 0.180 
            72.150 0.180 72.150 0.000 
            74.400 0.000 74.400 0.180 
            74.810 0.180 74.810 0.000 
            75.940 0.000 75.940 0.180 
            76.350 0.180 76.350 0.000 
            78.600 0.000 78.600 0.180 
            79.010 0.180 79.010 0.000 
            80.140 0.000 80.140 0.180 
            80.550 0.180 80.550 0.000 
            82.800 0.000 82.800 0.180 
            83.210 0.180 83.210 0.000 
            84.340 0.000 84.340 0.180 
            84.750 0.180 84.750 0.000 
            87.000 0.000 87.000 0.180 
            87.410 0.180 87.410 0.000 
            88.540 0.000 88.540 0.180 
            88.950 0.180 88.950 0.000 
            91.200 0.000 91.200 0.180 
            91.610 0.180 91.610 0.000 
            92.740 0.000 92.740 0.180 
            93.150 0.180 93.150 0.000 
            95.400 0.000 95.400 0.180 
            95.810 0.180 95.810 0.000 
            96.940 0.000 96.940 0.180 
            97.350 0.180 97.350 0.000 
            99.600 0.000 99.600 0.180 
            100.010 0.180 100.010 0.000 
            101.140 0.000 101.140 0.180 
            101.550 0.180 101.550 0.000 
            103.800 0.000 103.800 0.180 
            104.210 0.180 104.210 0.000 
            105.340 0.000 105.340 0.180 
            105.750 0.180 105.750 0.000 
            108.000 0.000 108.000 0.180 
            108.410 0.180 108.410 0.000 
            109.540 0.000 109.540 0.180 
            109.950 0.180 109.950 0.000 
            112.200 0.000 112.200 0.180 
            112.610 0.180 112.610 0.000 
            113.740 0.000 113.740 0.180 
            114.150 0.180 114.150 0.000 
            116.400 0.000 116.400 0.180 
            116.810 0.180 116.810 0.000 
            117.940 0.000 117.940 0.180 
            118.350 0.180 118.350 0.000 
            120.600 0.000 120.600 0.180 
            121.010 0.180 121.010 0.000 
            122.140 0.000 122.140 0.180 
            122.550 0.180 122.550 0.000 
            124.800 0.000 124.800 0.180 
            125.210 0.180 125.210 0.000 
            126.340 0.000 126.340 0.180 
            126.750 0.180 126.750 0.000 
            129.000 0.000 129.000 0.180 
            129.410 0.180 129.410 0.000 
            130.540 0.000 130.540 0.180 
            130.950 0.180 130.950 0.000 
            133.200 0.000 133.200 0.180 
            133.610 0.180 133.610 0.000 
            134.740 0.000 134.740 0.180 
            135.150 0.180 135.150 0.000 
            137.400 0.000 137.400 0.180 
            137.810 0.180 137.810 0.000 
            138.940 0.000 138.940 0.180 
            139.350 0.180 139.350 0.000 
            141.600 0.000 141.600 0.180 
            142.010 0.180 142.010 0.000 
            143.140 0.000 143.140 0.180 
            143.550 0.180 143.550 0.000 
            145.800 0.000 145.800 0.180 
            146.210 0.180 146.210 0.000 
            147.340 0.000 147.340 0.180 
            147.750 0.180 147.750 0.000 
            150.000 0.000 150.000 0.180 
            150.410 0.180 150.410 0.000 
            151.540 0.000 151.540 0.180 
            151.950 0.180 151.950 0.000 
            154.200 0.000 154.200 0.180 
            154.610 0.180 154.610 0.000 
            155.740 0.000 155.740 0.180 
            156.150 0.180 156.150 0.000 
            158.400 0.000 158.400 0.180 
            158.810 0.180 158.810 0.000 
            159.940 0.000 159.940 0.180 
            160.350 0.180 160.350 0.000 
            162.600 0.000 162.600 0.180 
            163.010 0.180 163.010 0.000 
            164.140 0.000 164.140 0.180 
            164.550 0.180 164.550 0.000 
            166.800 0.000 166.800 0.180 
            167.210 0.180 167.210 0.000 
            168.340 0.000 168.340 0.180 
            168.750 0.180 168.750 0.000 
            171.000 0.000 171.000 0.180 
            171.410 0.180 171.410 0.000 
            172.540 0.000 172.540 0.180 
            172.950 0.180 172.950 0.000 
            175.200 0.000 175.200 0.180 
            175.610 0.180 175.610 0.000 
            176.740 0.000 176.740 0.180 
            177.150 0.180 177.150 0.000 
            179.400 0.000 179.400 0.180 
            179.810 0.180 179.810 0.000 
            180.940 0.000 180.940 0.180 
            181.350 0.180 181.350 0.000 
            183.600 0.000 183.600 0.180 
            184.010 0.180 184.010 0.000 
            185.140 0.000 185.140 0.180 
            185.550 0.180 185.550 0.000 
            187.800 0.000 187.800 0.180 
            188.210 0.180 188.210 0.000 
            189.340 0.000 189.340 0.180 
            189.750 0.180 189.750 0.000 
            192.000 0.000 192.000 0.180 
            192.410 0.180 192.410 0.000 
            193.540 0.000 193.540 0.180 
            193.950 0.180 193.950 0.000 
            196.200 0.000 196.200 0.180 
            196.610 0.180 196.610 0.000 
            197.740 0.000 197.740 0.180 
            198.150 0.180 198.150 0.000 
            200.400 0.000 200.400 0.180 
            200.810 0.180 200.810 0.000 
            201.940 0.000 201.940 0.180 
            202.350 0.180 202.350 0.000 
            204.600 0.000 204.600 0.180 
            205.010 0.180 205.010 0.000 
            206.140 0.000 206.140 0.180 
            206.550 0.180 206.550 0.000 
            208.800 0.000 208.800 0.180 
            209.210 0.180 209.210 0.000 
            210.340 0.000 210.340 0.180 
            210.750 0.180 210.750 0.000 
            213.000 0.000 213.000 0.180 
            213.410 0.180 213.410 0.000 
            214.540 0.000 214.540 0.180 
            214.950 0.180 214.950 0.000 
            217.200 0.000 217.200 0.180 
            217.610 0.180 217.610 0.000 
            218.740 0.000 218.740 0.180 
            219.150 0.180 219.150 0.000 
            221.400 0.000 221.400 0.180 
            221.810 0.180 221.810 0.000 
            222.940 0.000 222.940 0.180 
            223.350 0.180 223.350 0.000 
            225.600 0.000 225.600 0.180 
            226.010 0.180 226.010 0.000 
            227.140 0.000 227.140 0.180 
            227.550 0.180 227.550 0.000 
            229.800 0.000 229.800 0.180 
            230.210 0.180 230.210 0.000 
            231.340 0.000 231.340 0.180 
            231.750 0.180 231.750 0.000 
            234.000 0.000 234.000 0.180 
            234.410 0.180 234.410 0.000 
            235.540 0.000 235.540 0.180 
            235.950 0.180 235.950 0.000 
            238.200 0.000 238.200 0.180 
            238.610 0.180 238.610 0.000 
            239.740 0.000 239.740 0.180 
            240.150 0.180 240.150 0.000 
            242.400 0.000 242.400 0.180 
            242.810 0.180 242.810 0.000 
            243.940 0.000 243.940 0.180 
            244.350 0.180 244.350 0.000 
            246.600 0.000 246.600 0.180 
            247.010 0.180 247.010 0.000 
            248.140 0.000 248.140 0.180 
            248.550 0.180 248.550 0.000 
            250.800 0.000 250.800 0.180 
            251.210 0.180 251.210 0.000 
            252.340 0.000 252.340 0.180 
            252.750 0.180 252.750 0.000 
            255.000 0.000 255.000 0.180 
            255.410 0.180 255.410 0.000 
            256.540 0.000 256.540 0.180 
            256.950 0.180 256.950 0.000 
            259.200 0.000 259.200 0.180 
            259.610 0.180 259.610 0.000 
            260.740 0.000 260.740 0.180 
            261.150 0.180 261.150 0.000 
            263.400 0.000 263.400 0.180 
            263.810 0.180 263.810 0.000 
            264.940 0.000 264.940 0.180 
            265.350 0.180 265.350 0.000 
            267.600 0.000 267.600 0.180 
            268.010 0.180 268.010 0.000 
            269.140 0.000 269.140 0.180 
            269.550 0.180 269.550 0.000 
            274.550 0.000 274.550 0.180 
            274.960 0.180 274.960 0.000 
            275.080 0.000 275.080 0.180 
            275.490 0.180 275.490 0.000 
            275.900 0.000 275.900 0.180 
            276.310 0.180 276.310 0.000 
            276.480 0.000 276.480 0.180 
            276.890 0.180 276.890 0.000 
            277.540 0.000 277.540 0.180 
            277.950 0.180 277.950 0.000 
            278.085 0.000 278.085 0.180 
            278.495 0.180 278.495 0.000 
            278.615 0.000 278.615 0.180 
            279.025 0.180 279.025 0.000 
            279.145 0.000 279.145 0.180 
            279.555 0.180 279.555 0.000 
            279.675 0.000 279.675 0.180 
            280.085 0.180 280.085 0.000 
            280.205 0.000 280.205 0.180 
            280.615 0.180 280.615 0.000 
            280.865 0.000 280.865 0.180 
            281.275 0.180 281.275 0.000 
            281.990 0.000 281.990 0.180 
            282.400 0.180 282.400 0.000 
            289.610 0.000 289.610 0.180 
            290.020 0.180 290.020 0.000 
            290.300 0.000 290.300 0.180 
            290.710 0.180 290.710 0.000 
            293.275 0.000 293.275 0.180 
            293.685 0.180 293.685 0.000 
            293.990 0.000 293.990 0.180 
            294.400 0.180 294.400 0.000 
            299.150 0.000 299.150 0.180 
            299.560 0.180 299.560 0.000 
            300.690 0.000 300.690 0.180 
            301.100 0.180 301.100 0.000 
            303.350 0.000 303.350 0.180 
            303.760 0.180 303.760 0.000 
            304.890 0.000 304.890 0.180 
            305.300 0.180 305.300 0.000 
            307.550 0.000 307.550 0.180 
            307.960 0.180 307.960 0.000 
            309.090 0.000 309.090 0.180 
            309.500 0.180 309.500 0.000 
            311.750 0.000 311.750 0.180 
            312.160 0.180 312.160 0.000 
            313.290 0.000 313.290 0.180 
            313.700 0.180 313.700 0.000 
            315.950 0.000 315.950 0.180 
            316.360 0.180 316.360 0.000 
            317.490 0.000 317.490 0.180 
            317.900 0.180 317.900 0.000 
            320.150 0.000 320.150 0.180 
            320.560 0.180 320.560 0.000 
            321.690 0.000 321.690 0.180 
            322.100 0.180 322.100 0.000 
            324.350 0.000 324.350 0.180 
            324.760 0.180 324.760 0.000 
            325.890 0.000 325.890 0.180 
            326.300 0.180 326.300 0.000 
            328.550 0.000 328.550 0.180 
            328.960 0.180 328.960 0.000 
            330.090 0.000 330.090 0.180 
            330.500 0.180 330.500 0.000 
            332.750 0.000 332.750 0.180 
            333.160 0.180 333.160 0.000 
            334.290 0.000 334.290 0.180 
            334.700 0.180 334.700 0.000 
            336.950 0.000 336.950 0.180 
            337.360 0.180 337.360 0.000 
            338.490 0.000 338.490 0.180 
            338.900 0.180 338.900 0.000 
            341.150 0.000 341.150 0.180 
            341.560 0.180 341.560 0.000 
            342.690 0.000 342.690 0.180 
            343.100 0.180 343.100 0.000 
            345.350 0.000 345.350 0.180 
            345.760 0.180 345.760 0.000 
            346.890 0.000 346.890 0.180 
            347.300 0.180 347.300 0.000 
            349.550 0.000 349.550 0.180 
            349.960 0.180 349.960 0.000 
            351.090 0.000 351.090 0.180 
            351.500 0.180 351.500 0.000 
            353.750 0.000 353.750 0.180 
            354.160 0.180 354.160 0.000 
            355.290 0.000 355.290 0.180 
            355.700 0.180 355.700 0.000 
            357.950 0.000 357.950 0.180 
            358.360 0.180 358.360 0.000 
            359.490 0.000 359.490 0.180 
            359.900 0.180 359.900 0.000 
            362.150 0.000 362.150 0.180 
            362.560 0.180 362.560 0.000 
            363.690 0.000 363.690 0.180 
            364.100 0.180 364.100 0.000 
            366.350 0.000 366.350 0.180 
            366.760 0.180 366.760 0.000 
            367.890 0.000 367.890 0.180 
            368.300 0.180 368.300 0.000 
            370.550 0.000 370.550 0.180 
            370.960 0.180 370.960 0.000 
            372.090 0.000 372.090 0.180 
            372.500 0.180 372.500 0.000 
            374.750 0.000 374.750 0.180 
            375.160 0.180 375.160 0.000 
            376.290 0.000 376.290 0.180 
            376.700 0.180 376.700 0.000 
            378.950 0.000 378.950 0.180 
            379.360 0.180 379.360 0.000 
            380.490 0.000 380.490 0.180 
            380.900 0.180 380.900 0.000 
            383.150 0.000 383.150 0.180 
            383.560 0.180 383.560 0.000 
            384.690 0.000 384.690 0.180 
            385.100 0.180 385.100 0.000 
            387.350 0.000 387.350 0.180 
            387.760 0.180 387.760 0.000 
            388.890 0.000 388.890 0.180 
            389.300 0.180 389.300 0.000 
            391.550 0.000 391.550 0.180 
            391.960 0.180 391.960 0.000 
            393.090 0.000 393.090 0.180 
            393.500 0.180 393.500 0.000 
            395.750 0.000 395.750 0.180 
            396.160 0.180 396.160 0.000 
            397.290 0.000 397.290 0.180 
            397.700 0.180 397.700 0.000 
            399.950 0.000 399.950 0.180 
            400.360 0.180 400.360 0.000 
            401.490 0.000 401.490 0.180 
            401.900 0.180 401.900 0.000 
            404.150 0.000 404.150 0.180 
            404.560 0.180 404.560 0.000 
            405.690 0.000 405.690 0.180 
            406.100 0.180 406.100 0.000 
            408.350 0.000 408.350 0.180 
            408.760 0.180 408.760 0.000 
            409.890 0.000 409.890 0.180 
            410.300 0.180 410.300 0.000 
            412.550 0.000 412.550 0.180 
            412.960 0.180 412.960 0.000 
            414.090 0.000 414.090 0.180 
            414.500 0.180 414.500 0.000 
            416.750 0.000 416.750 0.180 
            417.160 0.180 417.160 0.000 
            418.290 0.000 418.290 0.180 
            418.700 0.180 418.700 0.000 
            420.950 0.000 420.950 0.180 
            421.360 0.180 421.360 0.000 
            422.490 0.000 422.490 0.180 
            422.900 0.180 422.900 0.000 
            425.150 0.000 425.150 0.180 
            425.560 0.180 425.560 0.000 
            426.690 0.000 426.690 0.180 
            427.100 0.180 427.100 0.000 
            429.350 0.000 429.350 0.180 
            429.760 0.180 429.760 0.000 
            430.890 0.000 430.890 0.180 
            431.300 0.180 431.300 0.000 
            433.550 0.000 433.550 0.180 
            433.960 0.180 433.960 0.000 
            435.090 0.000 435.090 0.180 
            435.500 0.180 435.500 0.000 
            437.750 0.000 437.750 0.180 
            438.160 0.180 438.160 0.000 
            439.290 0.000 439.290 0.180 
            439.700 0.180 439.700 0.000 
            441.950 0.000 441.950 0.180 
            442.360 0.180 442.360 0.000 
            443.490 0.000 443.490 0.180 
            443.900 0.180 443.900 0.000 
            446.150 0.000 446.150 0.180 
            446.560 0.180 446.560 0.000 
            447.690 0.000 447.690 0.180 
            448.100 0.180 448.100 0.000 
            450.350 0.000 450.350 0.180 
            450.760 0.180 450.760 0.000 
            451.890 0.000 451.890 0.180 
            452.300 0.180 452.300 0.000 
            454.550 0.000 454.550 0.180 
            454.960 0.180 454.960 0.000 
            456.090 0.000 456.090 0.180 
            456.500 0.180 456.500 0.000 
            458.750 0.000 458.750 0.180 
            459.160 0.180 459.160 0.000 
            460.290 0.000 460.290 0.180 
            460.700 0.180 460.700 0.000 
            462.950 0.000 462.950 0.180 
            463.360 0.180 463.360 0.000 
            464.490 0.000 464.490 0.180 
            464.900 0.180 464.900 0.000 
            467.150 0.000 467.150 0.180 
            467.560 0.180 467.560 0.000 
            468.690 0.000 468.690 0.180 
            469.100 0.180 469.100 0.000 
            471.350 0.000 471.350 0.180 
            471.760 0.180 471.760 0.000 
            472.890 0.000 472.890 0.180 
            473.300 0.180 473.300 0.000 
            475.550 0.000 475.550 0.180 
            475.960 0.180 475.960 0.000 
            477.090 0.000 477.090 0.180 
            477.500 0.180 477.500 0.000 
            479.750 0.000 479.750 0.180 
            480.160 0.180 480.160 0.000 
            481.290 0.000 481.290 0.180 
            481.700 0.180 481.700 0.000 
            483.950 0.000 483.950 0.180 
            484.360 0.180 484.360 0.000 
            485.490 0.000 485.490 0.180 
            485.900 0.180 485.900 0.000 
            488.150 0.000 488.150 0.180 
            488.560 0.180 488.560 0.000 
            489.690 0.000 489.690 0.180 
            490.100 0.180 490.100 0.000 
            492.350 0.000 492.350 0.180 
            492.760 0.180 492.760 0.000 
            493.890 0.000 493.890 0.180 
            494.300 0.180 494.300 0.000 
            496.550 0.000 496.550 0.180 
            496.960 0.180 496.960 0.000 
            498.090 0.000 498.090 0.180 
            498.500 0.180 498.500 0.000 
            500.750 0.000 500.750 0.180 
            501.160 0.180 501.160 0.000 
            502.290 0.000 502.290 0.180 
            502.700 0.180 502.700 0.000 
            504.950 0.000 504.950 0.180 
            505.360 0.180 505.360 0.000 
            506.490 0.000 506.490 0.180 
            506.900 0.180 506.900 0.000 
            509.150 0.000 509.150 0.180 
            509.560 0.180 509.560 0.000 
            510.690 0.000 510.690 0.180 
            511.100 0.180 511.100 0.000 
            513.350 0.000 513.350 0.180 
            513.760 0.180 513.760 0.000 
            514.890 0.000 514.890 0.180 
            515.300 0.180 515.300 0.000 
            517.550 0.000 517.550 0.180 
            517.960 0.180 517.960 0.000 
            519.090 0.000 519.090 0.180 
            519.500 0.180 519.500 0.000 
            521.750 0.000 521.750 0.180 
            522.160 0.180 522.160 0.000 
            523.290 0.000 523.290 0.180 
            523.700 0.180 523.700 0.000 
            525.950 0.000 525.950 0.180 
            526.360 0.180 526.360 0.000 
            527.490 0.000 527.490 0.180 
            527.900 0.180 527.900 0.000 
            530.150 0.000 530.150 0.180 
            530.560 0.180 530.560 0.000 
            531.690 0.000 531.690 0.180 
            532.100 0.180 532.100 0.000 
            534.350 0.000 534.350 0.180 
            534.760 0.180 534.760 0.000 
            535.890 0.000 535.890 0.180 
            536.300 0.180 536.300 0.000 
            538.550 0.000 538.550 0.180 
            538.960 0.180 538.960 0.000 
            540.090 0.000 540.090 0.180 
            540.500 0.180 540.500 0.000 
            542.750 0.000 542.750 0.180 
            543.160 0.180 543.160 0.000 
            544.290 0.000 544.290 0.180 
            544.700 0.180 544.700 0.000 
            546.950 0.000 546.950 0.180 
            547.360 0.180 547.360 0.000 
            548.490 0.000 548.490 0.180 
            548.900 0.180 548.900 0.000 
            551.150 0.000 551.150 0.180 
            551.560 0.180 551.560 0.000 
            552.690 0.000 552.690 0.180 
            553.100 0.180 553.100 0.000 
            555.350 0.000 555.350 0.180 
            555.760 0.180 555.760 0.000 
            556.890 0.000 556.890 0.180 
            557.300 0.180 557.300 0.000 
            559.550 0.000 559.550 0.180 
            559.960 0.180 559.960 0.000 
            561.090 0.000 561.090 0.180 
            561.500 0.180 561.500 0.000 
            563.750 0.000 563.750 0.180 
            564.160 0.180 564.160 0.000 
            565.290 0.000 565.290 0.180 
            565.700 0.180 565.700 0.000 
            567.630 0.000 ;
  LAYER VIA2 SPACING 0.110 ;
    RECT 0.000 0.000 567.630 58.535 ;
  LAYER MET3 SPACING 0.150 ;
    POLYGON 567.630 0.000 567.630 58.535 
            0.000 58.535 0.000 0.000 
            3.000 0.000 3.000 0.180 
            3.410 0.180 3.410 0.000 
            4.540 0.000 4.540 0.180 
            4.950 0.180 4.950 0.000 
            7.200 0.000 7.200 0.180 
            7.610 0.180 7.610 0.000 
            8.740 0.000 8.740 0.180 
            9.150 0.180 9.150 0.000 
            11.400 0.000 11.400 0.180 
            11.810 0.180 11.810 0.000 
            12.940 0.000 12.940 0.180 
            13.350 0.180 13.350 0.000 
            15.600 0.000 15.600 0.180 
            16.010 0.180 16.010 0.000 
            17.140 0.000 17.140 0.180 
            17.550 0.180 17.550 0.000 
            19.800 0.000 19.800 0.180 
            20.210 0.180 20.210 0.000 
            21.340 0.000 21.340 0.180 
            21.750 0.180 21.750 0.000 
            24.000 0.000 24.000 0.180 
            24.410 0.180 24.410 0.000 
            25.540 0.000 25.540 0.180 
            25.950 0.180 25.950 0.000 
            28.200 0.000 28.200 0.180 
            28.610 0.180 28.610 0.000 
            29.740 0.000 29.740 0.180 
            30.150 0.180 30.150 0.000 
            32.400 0.000 32.400 0.180 
            32.810 0.180 32.810 0.000 
            33.940 0.000 33.940 0.180 
            34.350 0.180 34.350 0.000 
            36.600 0.000 36.600 0.180 
            37.010 0.180 37.010 0.000 
            38.140 0.000 38.140 0.180 
            38.550 0.180 38.550 0.000 
            40.800 0.000 40.800 0.180 
            41.210 0.180 41.210 0.000 
            42.340 0.000 42.340 0.180 
            42.750 0.180 42.750 0.000 
            45.000 0.000 45.000 0.180 
            45.410 0.180 45.410 0.000 
            46.540 0.000 46.540 0.180 
            46.950 0.180 46.950 0.000 
            49.200 0.000 49.200 0.180 
            49.610 0.180 49.610 0.000 
            50.740 0.000 50.740 0.180 
            51.150 0.180 51.150 0.000 
            53.400 0.000 53.400 0.180 
            53.810 0.180 53.810 0.000 
            54.940 0.000 54.940 0.180 
            55.350 0.180 55.350 0.000 
            57.600 0.000 57.600 0.180 
            58.010 0.180 58.010 0.000 
            59.140 0.000 59.140 0.180 
            59.550 0.180 59.550 0.000 
            61.800 0.000 61.800 0.180 
            62.210 0.180 62.210 0.000 
            63.340 0.000 63.340 0.180 
            63.750 0.180 63.750 0.000 
            66.000 0.000 66.000 0.180 
            66.410 0.180 66.410 0.000 
            67.540 0.000 67.540 0.180 
            67.950 0.180 67.950 0.000 
            70.200 0.000 70.200 0.180 
            70.610 0.180 70.610 0.000 
            71.740 0.000 71.740 0.180 
            72.150 0.180 72.150 0.000 
            74.400 0.000 74.400 0.180 
            74.810 0.180 74.810 0.000 
            75.940 0.000 75.940 0.180 
            76.350 0.180 76.350 0.000 
            78.600 0.000 78.600 0.180 
            79.010 0.180 79.010 0.000 
            80.140 0.000 80.140 0.180 
            80.550 0.180 80.550 0.000 
            82.800 0.000 82.800 0.180 
            83.210 0.180 83.210 0.000 
            84.340 0.000 84.340 0.180 
            84.750 0.180 84.750 0.000 
            87.000 0.000 87.000 0.180 
            87.410 0.180 87.410 0.000 
            88.540 0.000 88.540 0.180 
            88.950 0.180 88.950 0.000 
            91.200 0.000 91.200 0.180 
            91.610 0.180 91.610 0.000 
            92.740 0.000 92.740 0.180 
            93.150 0.180 93.150 0.000 
            95.400 0.000 95.400 0.180 
            95.810 0.180 95.810 0.000 
            96.940 0.000 96.940 0.180 
            97.350 0.180 97.350 0.000 
            99.600 0.000 99.600 0.180 
            100.010 0.180 100.010 0.000 
            101.140 0.000 101.140 0.180 
            101.550 0.180 101.550 0.000 
            103.800 0.000 103.800 0.180 
            104.210 0.180 104.210 0.000 
            105.340 0.000 105.340 0.180 
            105.750 0.180 105.750 0.000 
            108.000 0.000 108.000 0.180 
            108.410 0.180 108.410 0.000 
            109.540 0.000 109.540 0.180 
            109.950 0.180 109.950 0.000 
            112.200 0.000 112.200 0.180 
            112.610 0.180 112.610 0.000 
            113.740 0.000 113.740 0.180 
            114.150 0.180 114.150 0.000 
            116.400 0.000 116.400 0.180 
            116.810 0.180 116.810 0.000 
            117.940 0.000 117.940 0.180 
            118.350 0.180 118.350 0.000 
            120.600 0.000 120.600 0.180 
            121.010 0.180 121.010 0.000 
            122.140 0.000 122.140 0.180 
            122.550 0.180 122.550 0.000 
            124.800 0.000 124.800 0.180 
            125.210 0.180 125.210 0.000 
            126.340 0.000 126.340 0.180 
            126.750 0.180 126.750 0.000 
            129.000 0.000 129.000 0.180 
            129.410 0.180 129.410 0.000 
            130.540 0.000 130.540 0.180 
            130.950 0.180 130.950 0.000 
            133.200 0.000 133.200 0.180 
            133.610 0.180 133.610 0.000 
            134.740 0.000 134.740 0.180 
            135.150 0.180 135.150 0.000 
            137.400 0.000 137.400 0.180 
            137.810 0.180 137.810 0.000 
            138.940 0.000 138.940 0.180 
            139.350 0.180 139.350 0.000 
            141.600 0.000 141.600 0.180 
            142.010 0.180 142.010 0.000 
            143.140 0.000 143.140 0.180 
            143.550 0.180 143.550 0.000 
            145.800 0.000 145.800 0.180 
            146.210 0.180 146.210 0.000 
            147.340 0.000 147.340 0.180 
            147.750 0.180 147.750 0.000 
            150.000 0.000 150.000 0.180 
            150.410 0.180 150.410 0.000 
            151.540 0.000 151.540 0.180 
            151.950 0.180 151.950 0.000 
            154.200 0.000 154.200 0.180 
            154.610 0.180 154.610 0.000 
            155.740 0.000 155.740 0.180 
            156.150 0.180 156.150 0.000 
            158.400 0.000 158.400 0.180 
            158.810 0.180 158.810 0.000 
            159.940 0.000 159.940 0.180 
            160.350 0.180 160.350 0.000 
            162.600 0.000 162.600 0.180 
            163.010 0.180 163.010 0.000 
            164.140 0.000 164.140 0.180 
            164.550 0.180 164.550 0.000 
            166.800 0.000 166.800 0.180 
            167.210 0.180 167.210 0.000 
            168.340 0.000 168.340 0.180 
            168.750 0.180 168.750 0.000 
            171.000 0.000 171.000 0.180 
            171.410 0.180 171.410 0.000 
            172.540 0.000 172.540 0.180 
            172.950 0.180 172.950 0.000 
            175.200 0.000 175.200 0.180 
            175.610 0.180 175.610 0.000 
            176.740 0.000 176.740 0.180 
            177.150 0.180 177.150 0.000 
            179.400 0.000 179.400 0.180 
            179.810 0.180 179.810 0.000 
            180.940 0.000 180.940 0.180 
            181.350 0.180 181.350 0.000 
            183.600 0.000 183.600 0.180 
            184.010 0.180 184.010 0.000 
            185.140 0.000 185.140 0.180 
            185.550 0.180 185.550 0.000 
            187.800 0.000 187.800 0.180 
            188.210 0.180 188.210 0.000 
            189.340 0.000 189.340 0.180 
            189.750 0.180 189.750 0.000 
            192.000 0.000 192.000 0.180 
            192.410 0.180 192.410 0.000 
            193.540 0.000 193.540 0.180 
            193.950 0.180 193.950 0.000 
            196.200 0.000 196.200 0.180 
            196.610 0.180 196.610 0.000 
            197.740 0.000 197.740 0.180 
            198.150 0.180 198.150 0.000 
            200.400 0.000 200.400 0.180 
            200.810 0.180 200.810 0.000 
            201.940 0.000 201.940 0.180 
            202.350 0.180 202.350 0.000 
            204.600 0.000 204.600 0.180 
            205.010 0.180 205.010 0.000 
            206.140 0.000 206.140 0.180 
            206.550 0.180 206.550 0.000 
            208.800 0.000 208.800 0.180 
            209.210 0.180 209.210 0.000 
            210.340 0.000 210.340 0.180 
            210.750 0.180 210.750 0.000 
            213.000 0.000 213.000 0.180 
            213.410 0.180 213.410 0.000 
            214.540 0.000 214.540 0.180 
            214.950 0.180 214.950 0.000 
            217.200 0.000 217.200 0.180 
            217.610 0.180 217.610 0.000 
            218.740 0.000 218.740 0.180 
            219.150 0.180 219.150 0.000 
            221.400 0.000 221.400 0.180 
            221.810 0.180 221.810 0.000 
            222.940 0.000 222.940 0.180 
            223.350 0.180 223.350 0.000 
            225.600 0.000 225.600 0.180 
            226.010 0.180 226.010 0.000 
            227.140 0.000 227.140 0.180 
            227.550 0.180 227.550 0.000 
            229.800 0.000 229.800 0.180 
            230.210 0.180 230.210 0.000 
            231.340 0.000 231.340 0.180 
            231.750 0.180 231.750 0.000 
            234.000 0.000 234.000 0.180 
            234.410 0.180 234.410 0.000 
            235.540 0.000 235.540 0.180 
            235.950 0.180 235.950 0.000 
            238.200 0.000 238.200 0.180 
            238.610 0.180 238.610 0.000 
            239.740 0.000 239.740 0.180 
            240.150 0.180 240.150 0.000 
            242.400 0.000 242.400 0.180 
            242.810 0.180 242.810 0.000 
            243.940 0.000 243.940 0.180 
            244.350 0.180 244.350 0.000 
            246.600 0.000 246.600 0.180 
            247.010 0.180 247.010 0.000 
            248.140 0.000 248.140 0.180 
            248.550 0.180 248.550 0.000 
            250.800 0.000 250.800 0.180 
            251.210 0.180 251.210 0.000 
            252.340 0.000 252.340 0.180 
            252.750 0.180 252.750 0.000 
            255.000 0.000 255.000 0.180 
            255.410 0.180 255.410 0.000 
            256.540 0.000 256.540 0.180 
            256.950 0.180 256.950 0.000 
            259.200 0.000 259.200 0.180 
            259.610 0.180 259.610 0.000 
            260.740 0.000 260.740 0.180 
            261.150 0.180 261.150 0.000 
            263.400 0.000 263.400 0.180 
            263.810 0.180 263.810 0.000 
            264.940 0.000 264.940 0.180 
            265.350 0.180 265.350 0.000 
            267.600 0.000 267.600 0.180 
            268.010 0.180 268.010 0.000 
            269.140 0.000 269.140 0.180 
            269.550 0.180 269.550 0.000 
            274.550 0.000 274.550 0.180 
            274.960 0.180 274.960 0.000 
            275.080 0.000 275.080 0.180 
            275.490 0.180 275.490 0.000 
            275.900 0.000 275.900 0.180 
            276.310 0.180 276.310 0.000 
            276.480 0.000 276.480 0.180 
            276.890 0.180 276.890 0.000 
            277.540 0.000 277.540 0.180 
            277.950 0.180 277.950 0.000 
            278.085 0.000 278.085 0.180 
            278.495 0.180 278.495 0.000 
            278.615 0.000 278.615 0.180 
            279.025 0.180 279.025 0.000 
            279.145 0.000 279.145 0.180 
            279.555 0.180 279.555 0.000 
            279.675 0.000 279.675 0.180 
            280.085 0.180 280.085 0.000 
            280.205 0.000 280.205 0.180 
            280.615 0.180 280.615 0.000 
            280.865 0.000 280.865 0.180 
            281.275 0.180 281.275 0.000 
            281.990 0.000 281.990 0.180 
            282.400 0.180 282.400 0.000 
            289.610 0.000 289.610 0.180 
            290.020 0.180 290.020 0.000 
            290.300 0.000 290.300 0.180 
            290.710 0.180 290.710 0.000 
            293.275 0.000 293.275 0.180 
            293.685 0.180 293.685 0.000 
            293.990 0.000 293.990 0.180 
            294.400 0.180 294.400 0.000 
            299.150 0.000 299.150 0.180 
            299.560 0.180 299.560 0.000 
            300.690 0.000 300.690 0.180 
            301.100 0.180 301.100 0.000 
            303.350 0.000 303.350 0.180 
            303.760 0.180 303.760 0.000 
            304.890 0.000 304.890 0.180 
            305.300 0.180 305.300 0.000 
            307.550 0.000 307.550 0.180 
            307.960 0.180 307.960 0.000 
            309.090 0.000 309.090 0.180 
            309.500 0.180 309.500 0.000 
            311.750 0.000 311.750 0.180 
            312.160 0.180 312.160 0.000 
            313.290 0.000 313.290 0.180 
            313.700 0.180 313.700 0.000 
            315.950 0.000 315.950 0.180 
            316.360 0.180 316.360 0.000 
            317.490 0.000 317.490 0.180 
            317.900 0.180 317.900 0.000 
            320.150 0.000 320.150 0.180 
            320.560 0.180 320.560 0.000 
            321.690 0.000 321.690 0.180 
            322.100 0.180 322.100 0.000 
            324.350 0.000 324.350 0.180 
            324.760 0.180 324.760 0.000 
            325.890 0.000 325.890 0.180 
            326.300 0.180 326.300 0.000 
            328.550 0.000 328.550 0.180 
            328.960 0.180 328.960 0.000 
            330.090 0.000 330.090 0.180 
            330.500 0.180 330.500 0.000 
            332.750 0.000 332.750 0.180 
            333.160 0.180 333.160 0.000 
            334.290 0.000 334.290 0.180 
            334.700 0.180 334.700 0.000 
            336.950 0.000 336.950 0.180 
            337.360 0.180 337.360 0.000 
            338.490 0.000 338.490 0.180 
            338.900 0.180 338.900 0.000 
            341.150 0.000 341.150 0.180 
            341.560 0.180 341.560 0.000 
            342.690 0.000 342.690 0.180 
            343.100 0.180 343.100 0.000 
            345.350 0.000 345.350 0.180 
            345.760 0.180 345.760 0.000 
            346.890 0.000 346.890 0.180 
            347.300 0.180 347.300 0.000 
            349.550 0.000 349.550 0.180 
            349.960 0.180 349.960 0.000 
            351.090 0.000 351.090 0.180 
            351.500 0.180 351.500 0.000 
            353.750 0.000 353.750 0.180 
            354.160 0.180 354.160 0.000 
            355.290 0.000 355.290 0.180 
            355.700 0.180 355.700 0.000 
            357.950 0.000 357.950 0.180 
            358.360 0.180 358.360 0.000 
            359.490 0.000 359.490 0.180 
            359.900 0.180 359.900 0.000 
            362.150 0.000 362.150 0.180 
            362.560 0.180 362.560 0.000 
            363.690 0.000 363.690 0.180 
            364.100 0.180 364.100 0.000 
            366.350 0.000 366.350 0.180 
            366.760 0.180 366.760 0.000 
            367.890 0.000 367.890 0.180 
            368.300 0.180 368.300 0.000 
            370.550 0.000 370.550 0.180 
            370.960 0.180 370.960 0.000 
            372.090 0.000 372.090 0.180 
            372.500 0.180 372.500 0.000 
            374.750 0.000 374.750 0.180 
            375.160 0.180 375.160 0.000 
            376.290 0.000 376.290 0.180 
            376.700 0.180 376.700 0.000 
            378.950 0.000 378.950 0.180 
            379.360 0.180 379.360 0.000 
            380.490 0.000 380.490 0.180 
            380.900 0.180 380.900 0.000 
            383.150 0.000 383.150 0.180 
            383.560 0.180 383.560 0.000 
            384.690 0.000 384.690 0.180 
            385.100 0.180 385.100 0.000 
            387.350 0.000 387.350 0.180 
            387.760 0.180 387.760 0.000 
            388.890 0.000 388.890 0.180 
            389.300 0.180 389.300 0.000 
            391.550 0.000 391.550 0.180 
            391.960 0.180 391.960 0.000 
            393.090 0.000 393.090 0.180 
            393.500 0.180 393.500 0.000 
            395.750 0.000 395.750 0.180 
            396.160 0.180 396.160 0.000 
            397.290 0.000 397.290 0.180 
            397.700 0.180 397.700 0.000 
            399.950 0.000 399.950 0.180 
            400.360 0.180 400.360 0.000 
            401.490 0.000 401.490 0.180 
            401.900 0.180 401.900 0.000 
            404.150 0.000 404.150 0.180 
            404.560 0.180 404.560 0.000 
            405.690 0.000 405.690 0.180 
            406.100 0.180 406.100 0.000 
            408.350 0.000 408.350 0.180 
            408.760 0.180 408.760 0.000 
            409.890 0.000 409.890 0.180 
            410.300 0.180 410.300 0.000 
            412.550 0.000 412.550 0.180 
            412.960 0.180 412.960 0.000 
            414.090 0.000 414.090 0.180 
            414.500 0.180 414.500 0.000 
            416.750 0.000 416.750 0.180 
            417.160 0.180 417.160 0.000 
            418.290 0.000 418.290 0.180 
            418.700 0.180 418.700 0.000 
            420.950 0.000 420.950 0.180 
            421.360 0.180 421.360 0.000 
            422.490 0.000 422.490 0.180 
            422.900 0.180 422.900 0.000 
            425.150 0.000 425.150 0.180 
            425.560 0.180 425.560 0.000 
            426.690 0.000 426.690 0.180 
            427.100 0.180 427.100 0.000 
            429.350 0.000 429.350 0.180 
            429.760 0.180 429.760 0.000 
            430.890 0.000 430.890 0.180 
            431.300 0.180 431.300 0.000 
            433.550 0.000 433.550 0.180 
            433.960 0.180 433.960 0.000 
            435.090 0.000 435.090 0.180 
            435.500 0.180 435.500 0.000 
            437.750 0.000 437.750 0.180 
            438.160 0.180 438.160 0.000 
            439.290 0.000 439.290 0.180 
            439.700 0.180 439.700 0.000 
            441.950 0.000 441.950 0.180 
            442.360 0.180 442.360 0.000 
            443.490 0.000 443.490 0.180 
            443.900 0.180 443.900 0.000 
            446.150 0.000 446.150 0.180 
            446.560 0.180 446.560 0.000 
            447.690 0.000 447.690 0.180 
            448.100 0.180 448.100 0.000 
            450.350 0.000 450.350 0.180 
            450.760 0.180 450.760 0.000 
            451.890 0.000 451.890 0.180 
            452.300 0.180 452.300 0.000 
            454.550 0.000 454.550 0.180 
            454.960 0.180 454.960 0.000 
            456.090 0.000 456.090 0.180 
            456.500 0.180 456.500 0.000 
            458.750 0.000 458.750 0.180 
            459.160 0.180 459.160 0.000 
            460.290 0.000 460.290 0.180 
            460.700 0.180 460.700 0.000 
            462.950 0.000 462.950 0.180 
            463.360 0.180 463.360 0.000 
            464.490 0.000 464.490 0.180 
            464.900 0.180 464.900 0.000 
            467.150 0.000 467.150 0.180 
            467.560 0.180 467.560 0.000 
            468.690 0.000 468.690 0.180 
            469.100 0.180 469.100 0.000 
            471.350 0.000 471.350 0.180 
            471.760 0.180 471.760 0.000 
            472.890 0.000 472.890 0.180 
            473.300 0.180 473.300 0.000 
            475.550 0.000 475.550 0.180 
            475.960 0.180 475.960 0.000 
            477.090 0.000 477.090 0.180 
            477.500 0.180 477.500 0.000 
            479.750 0.000 479.750 0.180 
            480.160 0.180 480.160 0.000 
            481.290 0.000 481.290 0.180 
            481.700 0.180 481.700 0.000 
            483.950 0.000 483.950 0.180 
            484.360 0.180 484.360 0.000 
            485.490 0.000 485.490 0.180 
            485.900 0.180 485.900 0.000 
            488.150 0.000 488.150 0.180 
            488.560 0.180 488.560 0.000 
            489.690 0.000 489.690 0.180 
            490.100 0.180 490.100 0.000 
            492.350 0.000 492.350 0.180 
            492.760 0.180 492.760 0.000 
            493.890 0.000 493.890 0.180 
            494.300 0.180 494.300 0.000 
            496.550 0.000 496.550 0.180 
            496.960 0.180 496.960 0.000 
            498.090 0.000 498.090 0.180 
            498.500 0.180 498.500 0.000 
            500.750 0.000 500.750 0.180 
            501.160 0.180 501.160 0.000 
            502.290 0.000 502.290 0.180 
            502.700 0.180 502.700 0.000 
            504.950 0.000 504.950 0.180 
            505.360 0.180 505.360 0.000 
            506.490 0.000 506.490 0.180 
            506.900 0.180 506.900 0.000 
            509.150 0.000 509.150 0.180 
            509.560 0.180 509.560 0.000 
            510.690 0.000 510.690 0.180 
            511.100 0.180 511.100 0.000 
            513.350 0.000 513.350 0.180 
            513.760 0.180 513.760 0.000 
            514.890 0.000 514.890 0.180 
            515.300 0.180 515.300 0.000 
            517.550 0.000 517.550 0.180 
            517.960 0.180 517.960 0.000 
            519.090 0.000 519.090 0.180 
            519.500 0.180 519.500 0.000 
            521.750 0.000 521.750 0.180 
            522.160 0.180 522.160 0.000 
            523.290 0.000 523.290 0.180 
            523.700 0.180 523.700 0.000 
            525.950 0.000 525.950 0.180 
            526.360 0.180 526.360 0.000 
            527.490 0.000 527.490 0.180 
            527.900 0.180 527.900 0.000 
            530.150 0.000 530.150 0.180 
            530.560 0.180 530.560 0.000 
            531.690 0.000 531.690 0.180 
            532.100 0.180 532.100 0.000 
            534.350 0.000 534.350 0.180 
            534.760 0.180 534.760 0.000 
            535.890 0.000 535.890 0.180 
            536.300 0.180 536.300 0.000 
            538.550 0.000 538.550 0.180 
            538.960 0.180 538.960 0.000 
            540.090 0.000 540.090 0.180 
            540.500 0.180 540.500 0.000 
            542.750 0.000 542.750 0.180 
            543.160 0.180 543.160 0.000 
            544.290 0.000 544.290 0.180 
            544.700 0.180 544.700 0.000 
            546.950 0.000 546.950 0.180 
            547.360 0.180 547.360 0.000 
            548.490 0.000 548.490 0.180 
            548.900 0.180 548.900 0.000 
            551.150 0.000 551.150 0.180 
            551.560 0.180 551.560 0.000 
            552.690 0.000 552.690 0.180 
            553.100 0.180 553.100 0.000 
            555.350 0.000 555.350 0.180 
            555.760 0.180 555.760 0.000 
            556.890 0.000 556.890 0.180 
            557.300 0.180 557.300 0.000 
            559.550 0.000 559.550 0.180 
            559.960 0.180 559.960 0.000 
            561.090 0.000 561.090 0.180 
            561.500 0.180 561.500 0.000 
            563.750 0.000 563.750 0.180 
            564.160 0.180 564.160 0.000 
            565.290 0.000 565.290 0.180 
            565.700 0.180 565.700 0.000 
            567.630 0.000 ;
  LAYER VIA3 SPACING 0.110 ;
    RECT 0.000 0.000 567.630 58.535 ;
  LAYER MET4 SPACING 0.150 ;
    RECT 0.000 0.000 0.075 58.535 ;
    RECT 0.485 0.000 0.605 58.535 ;
    RECT 1.015 0.000 1.135 58.535 ;
    RECT 1.545 0.000 1.735 58.535 ;
    RECT 2.145 0.000 2.335 58.535 ;
    RECT 2.745 0.000 2.935 58.535 ;
    RECT 3.345 0.000 3.535 58.535 ;
    RECT 3.945 0.000 4.135 58.535 ;
    RECT 4.545 0.000 4.735 58.535 ;
    RECT 5.145 0.000 5.335 58.535 ;
    RECT 5.745 0.000 5.935 58.535 ;
    RECT 6.345 0.000 6.535 58.535 ;
    RECT 6.945 0.000 7.135 58.535 ;
    RECT 7.545 0.000 7.735 58.535 ;
    RECT 8.145 0.000 8.335 58.535 ;
    RECT 8.745 0.000 8.935 58.535 ;
    RECT 9.345 0.000 9.535 58.535 ;
    RECT 9.945 0.000 10.135 58.535 ;
    RECT 10.545 0.000 10.735 58.535 ;
    RECT 11.145 0.000 11.335 58.535 ;
    RECT 11.745 0.000 11.935 58.535 ;
    RECT 12.345 0.000 12.535 58.535 ;
    RECT 12.945 0.000 13.135 58.535 ;
    RECT 13.545 0.000 13.735 58.535 ;
    RECT 14.145 0.000 14.335 58.535 ;
    RECT 14.745 0.000 14.935 58.535 ;
    RECT 15.345 0.000 15.535 58.535 ;
    RECT 15.945 0.000 16.135 58.535 ;
    RECT 16.545 0.000 16.735 58.535 ;
    RECT 17.145 0.000 17.335 58.535 ;
    RECT 17.745 0.000 17.935 58.535 ;
    RECT 18.345 0.000 18.535 58.535 ;
    RECT 18.945 0.000 19.135 58.535 ;
    RECT 19.545 0.000 19.735 58.535 ;
    RECT 20.145 0.000 20.335 58.535 ;
    RECT 20.745 0.000 20.935 58.535 ;
    RECT 21.345 0.000 21.535 58.535 ;
    RECT 21.945 0.000 22.135 58.535 ;
    RECT 22.545 0.000 22.735 58.535 ;
    RECT 23.145 0.000 23.335 58.535 ;
    RECT 23.745 0.000 23.935 58.535 ;
    RECT 24.345 0.000 24.535 58.535 ;
    RECT 24.945 0.000 25.135 58.535 ;
    RECT 25.545 0.000 25.735 58.535 ;
    RECT 26.145 0.000 26.335 58.535 ;
    RECT 26.745 0.000 26.935 58.535 ;
    RECT 27.345 0.000 27.535 58.535 ;
    RECT 27.945 0.000 28.135 58.535 ;
    RECT 28.545 0.000 28.735 58.535 ;
    RECT 29.145 0.000 29.335 58.535 ;
    RECT 29.745 0.000 29.935 58.535 ;
    RECT 30.345 0.000 30.535 58.535 ;
    RECT 30.945 0.000 31.135 58.535 ;
    RECT 31.545 0.000 31.735 58.535 ;
    RECT 32.145 0.000 32.335 58.535 ;
    RECT 32.745 0.000 32.935 58.535 ;
    RECT 33.345 0.000 33.535 58.535 ;
    RECT 33.945 0.000 34.135 58.535 ;
    RECT 34.545 0.000 34.735 58.535 ;
    RECT 35.145 0.000 35.335 58.535 ;
    RECT 35.745 0.000 35.935 58.535 ;
    RECT 36.345 0.000 36.535 58.535 ;
    RECT 36.945 0.000 37.135 58.535 ;
    RECT 37.545 0.000 37.735 58.535 ;
    RECT 38.145 0.000 38.335 58.535 ;
    RECT 38.745 0.000 38.935 58.535 ;
    RECT 39.345 0.000 39.535 58.535 ;
    RECT 39.945 0.000 40.135 58.535 ;
    RECT 40.545 0.000 40.735 58.535 ;
    RECT 41.145 0.000 41.335 58.535 ;
    RECT 41.745 0.000 41.935 58.535 ;
    RECT 42.345 0.000 42.535 58.535 ;
    RECT 42.945 0.000 43.135 58.535 ;
    RECT 43.545 0.000 43.735 58.535 ;
    RECT 44.145 0.000 44.335 58.535 ;
    RECT 44.745 0.000 44.935 58.535 ;
    RECT 45.345 0.000 45.535 58.535 ;
    RECT 45.945 0.000 46.135 58.535 ;
    RECT 46.545 0.000 46.735 58.535 ;
    RECT 47.145 0.000 47.335 58.535 ;
    RECT 47.745 0.000 47.935 58.535 ;
    RECT 48.345 0.000 48.535 58.535 ;
    RECT 48.945 0.000 49.135 58.535 ;
    RECT 49.545 0.000 49.735 58.535 ;
    RECT 50.145 0.000 50.335 58.535 ;
    RECT 50.745 0.000 50.935 58.535 ;
    RECT 51.345 0.000 51.535 58.535 ;
    RECT 51.945 0.000 52.135 58.535 ;
    RECT 52.545 0.000 52.735 58.535 ;
    RECT 53.145 0.000 53.335 58.535 ;
    RECT 53.745 0.000 53.935 58.535 ;
    RECT 54.345 0.000 54.535 58.535 ;
    RECT 54.945 0.000 55.135 58.535 ;
    RECT 55.545 0.000 55.735 58.535 ;
    RECT 56.145 0.000 56.335 58.535 ;
    RECT 56.745 0.000 56.935 58.535 ;
    RECT 57.345 0.000 57.535 58.535 ;
    RECT 57.945 0.000 58.135 58.535 ;
    RECT 58.545 0.000 58.735 58.535 ;
    RECT 59.145 0.000 59.335 58.535 ;
    RECT 59.745 0.000 59.935 58.535 ;
    RECT 60.345 0.000 60.535 58.535 ;
    RECT 60.945 0.000 61.135 58.535 ;
    RECT 61.545 0.000 61.735 58.535 ;
    RECT 62.145 0.000 62.335 58.535 ;
    RECT 62.745 0.000 62.935 58.535 ;
    RECT 63.345 0.000 63.535 58.535 ;
    RECT 63.945 0.000 64.135 58.535 ;
    RECT 64.545 0.000 64.735 58.535 ;
    RECT 65.145 0.000 65.335 58.535 ;
    RECT 65.745 0.000 65.935 58.535 ;
    RECT 66.345 0.000 66.535 58.535 ;
    RECT 66.945 0.000 67.135 58.535 ;
    RECT 67.545 0.000 67.735 58.535 ;
    RECT 68.145 0.000 68.335 58.535 ;
    RECT 68.745 0.000 68.935 58.535 ;
    RECT 69.345 0.000 69.535 58.535 ;
    RECT 69.945 0.000 70.135 58.535 ;
    RECT 70.545 0.000 70.735 58.535 ;
    RECT 71.145 0.000 71.335 58.535 ;
    RECT 71.745 0.000 71.935 58.535 ;
    RECT 72.345 0.000 72.535 58.535 ;
    RECT 72.945 0.000 73.135 58.535 ;
    RECT 73.545 0.000 73.735 58.535 ;
    RECT 74.145 0.000 74.335 58.535 ;
    RECT 74.745 0.000 74.935 58.535 ;
    RECT 75.345 0.000 75.535 58.535 ;
    RECT 75.945 0.000 76.135 58.535 ;
    RECT 76.545 0.000 76.735 58.535 ;
    RECT 77.145 0.000 77.335 58.535 ;
    RECT 77.745 0.000 77.935 58.535 ;
    RECT 78.345 0.000 78.535 58.535 ;
    RECT 78.945 0.000 79.135 58.535 ;
    RECT 79.545 0.000 79.735 58.535 ;
    RECT 80.145 0.000 80.335 58.535 ;
    RECT 80.745 0.000 80.935 58.535 ;
    RECT 81.345 0.000 81.535 58.535 ;
    RECT 81.945 0.000 82.135 58.535 ;
    RECT 82.545 0.000 82.735 58.535 ;
    RECT 83.145 0.000 83.335 58.535 ;
    RECT 83.745 0.000 83.935 58.535 ;
    RECT 84.345 0.000 84.535 58.535 ;
    RECT 84.945 0.000 85.135 58.535 ;
    RECT 85.545 0.000 85.735 58.535 ;
    RECT 86.145 0.000 86.335 58.535 ;
    RECT 86.745 0.000 86.935 58.535 ;
    RECT 87.345 0.000 87.535 58.535 ;
    RECT 87.945 0.000 88.135 58.535 ;
    RECT 88.545 0.000 88.735 58.535 ;
    RECT 89.145 0.000 89.335 58.535 ;
    RECT 89.745 0.000 89.935 58.535 ;
    RECT 90.345 0.000 90.535 58.535 ;
    RECT 90.945 0.000 91.135 58.535 ;
    RECT 91.545 0.000 91.735 58.535 ;
    RECT 92.145 0.000 92.335 58.535 ;
    RECT 92.745 0.000 92.935 58.535 ;
    RECT 93.345 0.000 93.535 58.535 ;
    RECT 93.945 0.000 94.135 58.535 ;
    RECT 94.545 0.000 94.735 58.535 ;
    RECT 95.145 0.000 95.335 58.535 ;
    RECT 95.745 0.000 95.935 58.535 ;
    RECT 96.345 0.000 96.535 58.535 ;
    RECT 96.945 0.000 97.135 58.535 ;
    RECT 97.545 0.000 97.735 58.535 ;
    RECT 98.145 0.000 98.335 58.535 ;
    RECT 98.745 0.000 98.935 58.535 ;
    RECT 99.345 0.000 99.535 58.535 ;
    RECT 99.945 0.000 100.135 58.535 ;
    RECT 100.545 0.000 100.735 58.535 ;
    RECT 101.145 0.000 101.335 58.535 ;
    RECT 101.745 0.000 101.935 58.535 ;
    RECT 102.345 0.000 102.535 58.535 ;
    RECT 102.945 0.000 103.135 58.535 ;
    RECT 103.545 0.000 103.735 58.535 ;
    RECT 104.145 0.000 104.335 58.535 ;
    RECT 104.745 0.000 104.935 58.535 ;
    RECT 105.345 0.000 105.535 58.535 ;
    RECT 105.945 0.000 106.135 58.535 ;
    RECT 106.545 0.000 106.735 58.535 ;
    RECT 107.145 0.000 107.335 58.535 ;
    RECT 107.745 0.000 107.935 58.535 ;
    RECT 108.345 0.000 108.535 58.535 ;
    RECT 108.945 0.000 109.135 58.535 ;
    RECT 109.545 0.000 109.735 58.535 ;
    RECT 110.145 0.000 110.335 58.535 ;
    RECT 110.745 0.000 110.935 58.535 ;
    RECT 111.345 0.000 111.535 58.535 ;
    RECT 111.945 0.000 112.135 58.535 ;
    RECT 112.545 0.000 112.735 58.535 ;
    RECT 113.145 0.000 113.335 58.535 ;
    RECT 113.745 0.000 113.935 58.535 ;
    RECT 114.345 0.000 114.535 58.535 ;
    RECT 114.945 0.000 115.135 58.535 ;
    RECT 115.545 0.000 115.735 58.535 ;
    RECT 116.145 0.000 116.335 58.535 ;
    RECT 116.745 0.000 116.935 58.535 ;
    RECT 117.345 0.000 117.535 58.535 ;
    RECT 117.945 0.000 118.135 58.535 ;
    RECT 118.545 0.000 118.735 58.535 ;
    RECT 119.145 0.000 119.335 58.535 ;
    RECT 119.745 0.000 119.935 58.535 ;
    RECT 120.345 0.000 120.535 58.535 ;
    RECT 120.945 0.000 121.135 58.535 ;
    RECT 121.545 0.000 121.735 58.535 ;
    RECT 122.145 0.000 122.335 58.535 ;
    RECT 122.745 0.000 122.935 58.535 ;
    RECT 123.345 0.000 123.535 58.535 ;
    RECT 123.945 0.000 124.135 58.535 ;
    RECT 124.545 0.000 124.735 58.535 ;
    RECT 125.145 0.000 125.335 58.535 ;
    RECT 125.745 0.000 125.935 58.535 ;
    RECT 126.345 0.000 126.535 58.535 ;
    RECT 126.945 0.000 127.135 58.535 ;
    RECT 127.545 0.000 127.735 58.535 ;
    RECT 128.145 0.000 128.335 58.535 ;
    RECT 128.745 0.000 128.935 58.535 ;
    RECT 129.345 0.000 129.535 58.535 ;
    RECT 129.945 0.000 130.135 58.535 ;
    RECT 130.545 0.000 130.735 58.535 ;
    RECT 131.145 0.000 131.335 58.535 ;
    RECT 131.745 0.000 131.935 58.535 ;
    RECT 132.345 0.000 132.535 58.535 ;
    RECT 132.945 0.000 133.135 58.535 ;
    RECT 133.545 0.000 133.735 58.535 ;
    RECT 134.145 0.000 134.335 58.535 ;
    RECT 134.745 0.000 134.935 58.535 ;
    RECT 135.345 0.000 135.535 58.535 ;
    RECT 135.945 0.000 136.135 58.535 ;
    RECT 136.545 0.000 136.735 58.535 ;
    RECT 137.145 0.000 137.335 58.535 ;
    RECT 137.745 0.000 137.935 58.535 ;
    RECT 138.345 0.000 138.535 58.535 ;
    RECT 138.945 0.000 139.135 58.535 ;
    RECT 139.545 0.000 139.735 58.535 ;
    RECT 140.145 0.000 140.335 58.535 ;
    RECT 140.745 0.000 140.935 58.535 ;
    RECT 141.345 0.000 141.535 58.535 ;
    RECT 141.945 0.000 142.135 58.535 ;
    RECT 142.545 0.000 142.735 58.535 ;
    RECT 143.145 0.000 143.335 58.535 ;
    RECT 143.745 0.000 143.935 58.535 ;
    RECT 144.345 0.000 144.535 58.535 ;
    RECT 144.945 0.000 145.135 58.535 ;
    RECT 145.545 0.000 145.735 58.535 ;
    RECT 146.145 0.000 146.335 58.535 ;
    RECT 146.745 0.000 146.935 58.535 ;
    RECT 147.345 0.000 147.535 58.535 ;
    RECT 147.945 0.000 148.135 58.535 ;
    RECT 148.545 0.000 148.735 58.535 ;
    RECT 149.145 0.000 149.335 58.535 ;
    RECT 149.745 0.000 149.935 58.535 ;
    RECT 150.345 0.000 150.535 58.535 ;
    RECT 150.945 0.000 151.135 58.535 ;
    RECT 151.545 0.000 151.735 58.535 ;
    RECT 152.145 0.000 152.335 58.535 ;
    RECT 152.745 0.000 152.935 58.535 ;
    RECT 153.345 0.000 153.535 58.535 ;
    RECT 153.945 0.000 154.135 58.535 ;
    RECT 154.545 0.000 154.735 58.535 ;
    RECT 155.145 0.000 155.335 58.535 ;
    RECT 155.745 0.000 155.935 58.535 ;
    RECT 156.345 0.000 156.535 58.535 ;
    RECT 156.945 0.000 157.135 58.535 ;
    RECT 157.545 0.000 157.735 58.535 ;
    RECT 158.145 0.000 158.335 58.535 ;
    RECT 158.745 0.000 158.935 58.535 ;
    RECT 159.345 0.000 159.535 58.535 ;
    RECT 159.945 0.000 160.135 58.535 ;
    RECT 160.545 0.000 160.735 58.535 ;
    RECT 161.145 0.000 161.335 58.535 ;
    RECT 161.745 0.000 161.935 58.535 ;
    RECT 162.345 0.000 162.535 58.535 ;
    RECT 162.945 0.000 163.135 58.535 ;
    RECT 163.545 0.000 163.735 58.535 ;
    RECT 164.145 0.000 164.335 58.535 ;
    RECT 164.745 0.000 164.935 58.535 ;
    RECT 165.345 0.000 165.535 58.535 ;
    RECT 165.945 0.000 166.135 58.535 ;
    RECT 166.545 0.000 166.735 58.535 ;
    RECT 167.145 0.000 167.335 58.535 ;
    RECT 167.745 0.000 167.935 58.535 ;
    RECT 168.345 0.000 168.535 58.535 ;
    RECT 168.945 0.000 169.135 58.535 ;
    RECT 169.545 0.000 169.735 58.535 ;
    RECT 170.145 0.000 170.335 58.535 ;
    RECT 170.745 0.000 170.935 58.535 ;
    RECT 171.345 0.000 171.535 58.535 ;
    RECT 171.945 0.000 172.135 58.535 ;
    RECT 172.545 0.000 172.735 58.535 ;
    RECT 173.145 0.000 173.335 58.535 ;
    RECT 173.745 0.000 173.935 58.535 ;
    RECT 174.345 0.000 174.535 58.535 ;
    RECT 174.945 0.000 175.135 58.535 ;
    RECT 175.545 0.000 175.735 58.535 ;
    RECT 176.145 0.000 176.335 58.535 ;
    RECT 176.745 0.000 176.935 58.535 ;
    RECT 177.345 0.000 177.535 58.535 ;
    RECT 177.945 0.000 178.135 58.535 ;
    RECT 178.545 0.000 178.735 58.535 ;
    RECT 179.145 0.000 179.335 58.535 ;
    RECT 179.745 0.000 179.935 58.535 ;
    RECT 180.345 0.000 180.535 58.535 ;
    RECT 180.945 0.000 181.135 58.535 ;
    RECT 181.545 0.000 181.735 58.535 ;
    RECT 182.145 0.000 182.335 58.535 ;
    RECT 182.745 0.000 182.935 58.535 ;
    RECT 183.345 0.000 183.535 58.535 ;
    RECT 183.945 0.000 184.135 58.535 ;
    RECT 184.545 0.000 184.735 58.535 ;
    RECT 185.145 0.000 185.335 58.535 ;
    RECT 185.745 0.000 185.935 58.535 ;
    RECT 186.345 0.000 186.535 58.535 ;
    RECT 186.945 0.000 187.135 58.535 ;
    RECT 187.545 0.000 187.735 58.535 ;
    RECT 188.145 0.000 188.335 58.535 ;
    RECT 188.745 0.000 188.935 58.535 ;
    RECT 189.345 0.000 189.535 58.535 ;
    RECT 189.945 0.000 190.135 58.535 ;
    RECT 190.545 0.000 190.735 58.535 ;
    RECT 191.145 0.000 191.335 58.535 ;
    RECT 191.745 0.000 191.935 58.535 ;
    RECT 192.345 0.000 192.535 58.535 ;
    RECT 192.945 0.000 193.135 58.535 ;
    RECT 193.545 0.000 193.735 58.535 ;
    RECT 194.145 0.000 194.335 58.535 ;
    RECT 194.745 0.000 194.935 58.535 ;
    RECT 195.345 0.000 195.535 58.535 ;
    RECT 195.945 0.000 196.135 58.535 ;
    RECT 196.545 0.000 196.735 58.535 ;
    RECT 197.145 0.000 197.335 58.535 ;
    RECT 197.745 0.000 197.935 58.535 ;
    RECT 198.345 0.000 198.535 58.535 ;
    RECT 198.945 0.000 199.135 58.535 ;
    RECT 199.545 0.000 199.735 58.535 ;
    RECT 200.145 0.000 200.335 58.535 ;
    RECT 200.745 0.000 200.935 58.535 ;
    RECT 201.345 0.000 201.535 58.535 ;
    RECT 201.945 0.000 202.135 58.535 ;
    RECT 202.545 0.000 202.735 58.535 ;
    RECT 203.145 0.000 203.335 58.535 ;
    RECT 203.745 0.000 203.935 58.535 ;
    RECT 204.345 0.000 204.535 58.535 ;
    RECT 204.945 0.000 205.135 58.535 ;
    RECT 205.545 0.000 205.735 58.535 ;
    RECT 206.145 0.000 206.335 58.535 ;
    RECT 206.745 0.000 206.935 58.535 ;
    RECT 207.345 0.000 207.535 58.535 ;
    RECT 207.945 0.000 208.135 58.535 ;
    RECT 208.545 0.000 208.735 58.535 ;
    RECT 209.145 0.000 209.335 58.535 ;
    RECT 209.745 0.000 209.935 58.535 ;
    RECT 210.345 0.000 210.535 58.535 ;
    RECT 210.945 0.000 211.135 58.535 ;
    RECT 211.545 0.000 211.735 58.535 ;
    RECT 212.145 0.000 212.335 58.535 ;
    RECT 212.745 0.000 212.935 58.535 ;
    RECT 213.345 0.000 213.535 58.535 ;
    RECT 213.945 0.000 214.135 58.535 ;
    RECT 214.545 0.000 214.735 58.535 ;
    RECT 215.145 0.000 215.335 58.535 ;
    RECT 215.745 0.000 215.935 58.535 ;
    RECT 216.345 0.000 216.535 58.535 ;
    RECT 216.945 0.000 217.135 58.535 ;
    RECT 217.545 0.000 217.735 58.535 ;
    RECT 218.145 0.000 218.335 58.535 ;
    RECT 218.745 0.000 218.935 58.535 ;
    RECT 219.345 0.000 219.535 58.535 ;
    RECT 219.945 0.000 220.135 58.535 ;
    RECT 220.545 0.000 220.735 58.535 ;
    RECT 221.145 0.000 221.335 58.535 ;
    RECT 221.745 0.000 221.935 58.535 ;
    RECT 222.345 0.000 222.535 58.535 ;
    RECT 222.945 0.000 223.135 58.535 ;
    RECT 223.545 0.000 223.735 58.535 ;
    RECT 224.145 0.000 224.335 58.535 ;
    RECT 224.745 0.000 224.935 58.535 ;
    RECT 225.345 0.000 225.535 58.535 ;
    RECT 225.945 0.000 226.135 58.535 ;
    RECT 226.545 0.000 226.735 58.535 ;
    RECT 227.145 0.000 227.335 58.535 ;
    RECT 227.745 0.000 227.935 58.535 ;
    RECT 228.345 0.000 228.535 58.535 ;
    RECT 228.945 0.000 229.135 58.535 ;
    RECT 229.545 0.000 229.735 58.535 ;
    RECT 230.145 0.000 230.335 58.535 ;
    RECT 230.745 0.000 230.935 58.535 ;
    RECT 231.345 0.000 231.535 58.535 ;
    RECT 231.945 0.000 232.135 58.535 ;
    RECT 232.545 0.000 232.735 58.535 ;
    RECT 233.145 0.000 233.335 58.535 ;
    RECT 233.745 0.000 233.935 58.535 ;
    RECT 234.345 0.000 234.535 58.535 ;
    RECT 234.945 0.000 235.135 58.535 ;
    RECT 235.545 0.000 235.735 58.535 ;
    RECT 236.145 0.000 236.335 58.535 ;
    RECT 236.745 0.000 236.935 58.535 ;
    RECT 237.345 0.000 237.535 58.535 ;
    RECT 237.945 0.000 238.135 58.535 ;
    RECT 238.545 0.000 238.735 58.535 ;
    RECT 239.145 0.000 239.335 58.535 ;
    RECT 239.745 0.000 239.935 58.535 ;
    RECT 240.345 0.000 240.535 58.535 ;
    RECT 240.945 0.000 241.135 58.535 ;
    RECT 241.545 0.000 241.735 58.535 ;
    RECT 242.145 0.000 242.335 58.535 ;
    RECT 242.745 0.000 242.935 58.535 ;
    RECT 243.345 0.000 243.535 58.535 ;
    RECT 243.945 0.000 244.135 58.535 ;
    RECT 244.545 0.000 244.735 58.535 ;
    RECT 245.145 0.000 245.335 58.535 ;
    RECT 245.745 0.000 245.935 58.535 ;
    RECT 246.345 0.000 246.535 58.535 ;
    RECT 246.945 0.000 247.135 58.535 ;
    RECT 247.545 0.000 247.735 58.535 ;
    RECT 248.145 0.000 248.335 58.535 ;
    RECT 248.745 0.000 248.935 58.535 ;
    RECT 249.345 0.000 249.535 58.535 ;
    RECT 249.945 0.000 250.135 58.535 ;
    RECT 250.545 0.000 250.735 58.535 ;
    RECT 251.145 0.000 251.335 58.535 ;
    RECT 251.745 0.000 251.935 58.535 ;
    RECT 252.345 0.000 252.535 58.535 ;
    RECT 252.945 0.000 253.135 58.535 ;
    RECT 253.545 0.000 253.735 58.535 ;
    RECT 254.145 0.000 254.335 58.535 ;
    RECT 254.745 0.000 254.935 58.535 ;
    RECT 255.345 0.000 255.535 58.535 ;
    RECT 255.945 0.000 256.135 58.535 ;
    RECT 256.545 0.000 256.735 58.535 ;
    RECT 257.145 0.000 257.335 58.535 ;
    RECT 257.745 0.000 257.935 58.535 ;
    RECT 258.345 0.000 258.535 58.535 ;
    RECT 258.945 0.000 259.135 58.535 ;
    RECT 259.545 0.000 259.735 58.535 ;
    RECT 260.145 0.000 260.335 58.535 ;
    RECT 260.745 0.000 260.935 58.535 ;
    RECT 261.345 0.000 261.535 58.535 ;
    RECT 261.945 0.000 262.135 58.535 ;
    RECT 262.545 0.000 262.735 58.535 ;
    RECT 263.145 0.000 263.335 58.535 ;
    RECT 263.745 0.000 263.935 58.535 ;
    RECT 264.345 0.000 264.535 58.535 ;
    RECT 264.945 0.000 265.135 58.535 ;
    RECT 265.545 0.000 265.735 58.535 ;
    RECT 266.145 0.000 266.335 58.535 ;
    RECT 266.745 0.000 266.935 58.535 ;
    RECT 267.345 0.000 267.535 58.535 ;
    RECT 267.945 0.000 268.135 58.535 ;
    RECT 268.545 0.000 268.735 58.535 ;
    RECT 269.145 0.000 269.335 58.535 ;
    RECT 269.745 0.000 269.935 58.535 ;
    RECT 270.345 0.000 270.465 58.535 ;
    RECT 270.875 0.000 270.995 58.535 ;
    RECT 271.405 0.000 271.830 58.535 ;
    RECT 272.240 0.000 272.360 58.535 ;
    RECT 272.770 0.000 272.890 58.535 ;
    RECT 273.300 0.000 273.420 58.535 ;
    RECT 273.830 0.000 273.950 58.535 ;
    RECT 274.360 0.000 274.480 58.535 ;
    RECT 274.890 0.000 275.010 58.535 ;
    RECT 275.420 0.000 275.540 58.535 ;
    RECT 275.950 0.000 276.070 58.535 ;
    RECT 276.480 0.000 276.600 58.535 ;
    RECT 277.010 0.000 277.130 58.535 ;
    RECT 277.540 0.000 277.660 58.535 ;
    RECT 278.070 0.000 278.190 58.535 ;
    RECT 278.600 0.000 278.720 58.535 ;
    RECT 279.130 0.000 279.250 58.535 ;
    RECT 279.660 0.000 279.780 58.535 ;
    RECT 280.190 0.000 280.310 58.535 ;
    RECT 280.720 0.000 280.840 58.535 ;
    RECT 281.250 0.000 281.370 58.535 ;
    RECT 281.780 0.000 281.900 58.535 ;
    RECT 282.310 0.000 282.430 58.535 ;
    RECT 282.840 0.000 282.960 58.535 ;
    RECT 283.370 0.000 283.490 58.535 ;
    RECT 283.900 0.000 284.020 58.535 ;
    RECT 284.430 0.000 284.550 58.535 ;
    RECT 284.960 0.000 285.080 58.535 ;
    RECT 285.490 0.000 285.610 58.535 ;
    RECT 286.020 0.000 286.140 58.535 ;
    RECT 286.550 0.000 286.670 58.535 ;
    RECT 287.080 0.000 287.200 58.535 ;
    RECT 287.610 0.000 287.730 58.535 ;
    RECT 288.140 0.000 288.260 58.535 ;
    RECT 288.670 0.000 288.790 58.535 ;
    RECT 289.200 0.000 289.320 58.535 ;
    RECT 289.730 0.000 289.850 58.535 ;
    RECT 290.260 0.000 290.380 58.535 ;
    RECT 290.790 0.000 290.910 58.535 ;
    RECT 291.320 0.000 291.440 58.535 ;
    RECT 291.850 0.000 291.970 58.535 ;
    RECT 292.380 0.000 292.500 58.535 ;
    RECT 292.910 0.000 293.030 58.535 ;
    RECT 293.440 0.000 293.560 58.535 ;
    RECT 293.970 0.000 294.090 58.535 ;
    RECT 294.500 0.000 294.620 58.535 ;
    RECT 295.030 0.000 295.150 58.535 ;
    RECT 295.560 0.000 295.680 58.535 ;
    RECT 296.090 0.000 296.225 58.535 ;
    RECT 296.635 0.000 296.755 58.535 ;
    RECT 297.165 0.000 297.285 58.535 ;
    RECT 297.695 0.000 297.885 58.535 ;
    RECT 298.295 0.000 298.485 58.535 ;
    RECT 298.895 0.000 299.085 58.535 ;
    RECT 299.495 0.000 299.685 58.535 ;
    RECT 300.095 0.000 300.285 58.535 ;
    RECT 300.695 0.000 300.885 58.535 ;
    RECT 301.295 0.000 301.485 58.535 ;
    RECT 301.895 0.000 302.085 58.535 ;
    RECT 302.495 0.000 302.685 58.535 ;
    RECT 303.095 0.000 303.285 58.535 ;
    RECT 303.695 0.000 303.885 58.535 ;
    RECT 304.295 0.000 304.485 58.535 ;
    RECT 304.895 0.000 305.085 58.535 ;
    RECT 305.495 0.000 305.685 58.535 ;
    RECT 306.095 0.000 306.285 58.535 ;
    RECT 306.695 0.000 306.885 58.535 ;
    RECT 307.295 0.000 307.485 58.535 ;
    RECT 307.895 0.000 308.085 58.535 ;
    RECT 308.495 0.000 308.685 58.535 ;
    RECT 309.095 0.000 309.285 58.535 ;
    RECT 309.695 0.000 309.885 58.535 ;
    RECT 310.295 0.000 310.485 58.535 ;
    RECT 310.895 0.000 311.085 58.535 ;
    RECT 311.495 0.000 311.685 58.535 ;
    RECT 312.095 0.000 312.285 58.535 ;
    RECT 312.695 0.000 312.885 58.535 ;
    RECT 313.295 0.000 313.485 58.535 ;
    RECT 313.895 0.000 314.085 58.535 ;
    RECT 314.495 0.000 314.685 58.535 ;
    RECT 315.095 0.000 315.285 58.535 ;
    RECT 315.695 0.000 315.885 58.535 ;
    RECT 316.295 0.000 316.485 58.535 ;
    RECT 316.895 0.000 317.085 58.535 ;
    RECT 317.495 0.000 317.685 58.535 ;
    RECT 318.095 0.000 318.285 58.535 ;
    RECT 318.695 0.000 318.885 58.535 ;
    RECT 319.295 0.000 319.485 58.535 ;
    RECT 319.895 0.000 320.085 58.535 ;
    RECT 320.495 0.000 320.685 58.535 ;
    RECT 321.095 0.000 321.285 58.535 ;
    RECT 321.695 0.000 321.885 58.535 ;
    RECT 322.295 0.000 322.485 58.535 ;
    RECT 322.895 0.000 323.085 58.535 ;
    RECT 323.495 0.000 323.685 58.535 ;
    RECT 324.095 0.000 324.285 58.535 ;
    RECT 324.695 0.000 324.885 58.535 ;
    RECT 325.295 0.000 325.485 58.535 ;
    RECT 325.895 0.000 326.085 58.535 ;
    RECT 326.495 0.000 326.685 58.535 ;
    RECT 327.095 0.000 327.285 58.535 ;
    RECT 327.695 0.000 327.885 58.535 ;
    RECT 328.295 0.000 328.485 58.535 ;
    RECT 328.895 0.000 329.085 58.535 ;
    RECT 329.495 0.000 329.685 58.535 ;
    RECT 330.095 0.000 330.285 58.535 ;
    RECT 330.695 0.000 330.885 58.535 ;
    RECT 331.295 0.000 331.485 58.535 ;
    RECT 331.895 0.000 332.085 58.535 ;
    RECT 332.495 0.000 332.685 58.535 ;
    RECT 333.095 0.000 333.285 58.535 ;
    RECT 333.695 0.000 333.885 58.535 ;
    RECT 334.295 0.000 334.485 58.535 ;
    RECT 334.895 0.000 335.085 58.535 ;
    RECT 335.495 0.000 335.685 58.535 ;
    RECT 336.095 0.000 336.285 58.535 ;
    RECT 336.695 0.000 336.885 58.535 ;
    RECT 337.295 0.000 337.485 58.535 ;
    RECT 337.895 0.000 338.085 58.535 ;
    RECT 338.495 0.000 338.685 58.535 ;
    RECT 339.095 0.000 339.285 58.535 ;
    RECT 339.695 0.000 339.885 58.535 ;
    RECT 340.295 0.000 340.485 58.535 ;
    RECT 340.895 0.000 341.085 58.535 ;
    RECT 341.495 0.000 341.685 58.535 ;
    RECT 342.095 0.000 342.285 58.535 ;
    RECT 342.695 0.000 342.885 58.535 ;
    RECT 343.295 0.000 343.485 58.535 ;
    RECT 343.895 0.000 344.085 58.535 ;
    RECT 344.495 0.000 344.685 58.535 ;
    RECT 345.095 0.000 345.285 58.535 ;
    RECT 345.695 0.000 345.885 58.535 ;
    RECT 346.295 0.000 346.485 58.535 ;
    RECT 346.895 0.000 347.085 58.535 ;
    RECT 347.495 0.000 347.685 58.535 ;
    RECT 348.095 0.000 348.285 58.535 ;
    RECT 348.695 0.000 348.885 58.535 ;
    RECT 349.295 0.000 349.485 58.535 ;
    RECT 349.895 0.000 350.085 58.535 ;
    RECT 350.495 0.000 350.685 58.535 ;
    RECT 351.095 0.000 351.285 58.535 ;
    RECT 351.695 0.000 351.885 58.535 ;
    RECT 352.295 0.000 352.485 58.535 ;
    RECT 352.895 0.000 353.085 58.535 ;
    RECT 353.495 0.000 353.685 58.535 ;
    RECT 354.095 0.000 354.285 58.535 ;
    RECT 354.695 0.000 354.885 58.535 ;
    RECT 355.295 0.000 355.485 58.535 ;
    RECT 355.895 0.000 356.085 58.535 ;
    RECT 356.495 0.000 356.685 58.535 ;
    RECT 357.095 0.000 357.285 58.535 ;
    RECT 357.695 0.000 357.885 58.535 ;
    RECT 358.295 0.000 358.485 58.535 ;
    RECT 358.895 0.000 359.085 58.535 ;
    RECT 359.495 0.000 359.685 58.535 ;
    RECT 360.095 0.000 360.285 58.535 ;
    RECT 360.695 0.000 360.885 58.535 ;
    RECT 361.295 0.000 361.485 58.535 ;
    RECT 361.895 0.000 362.085 58.535 ;
    RECT 362.495 0.000 362.685 58.535 ;
    RECT 363.095 0.000 363.285 58.535 ;
    RECT 363.695 0.000 363.885 58.535 ;
    RECT 364.295 0.000 364.485 58.535 ;
    RECT 364.895 0.000 365.085 58.535 ;
    RECT 365.495 0.000 365.685 58.535 ;
    RECT 366.095 0.000 366.285 58.535 ;
    RECT 366.695 0.000 366.885 58.535 ;
    RECT 367.295 0.000 367.485 58.535 ;
    RECT 367.895 0.000 368.085 58.535 ;
    RECT 368.495 0.000 368.685 58.535 ;
    RECT 369.095 0.000 369.285 58.535 ;
    RECT 369.695 0.000 369.885 58.535 ;
    RECT 370.295 0.000 370.485 58.535 ;
    RECT 370.895 0.000 371.085 58.535 ;
    RECT 371.495 0.000 371.685 58.535 ;
    RECT 372.095 0.000 372.285 58.535 ;
    RECT 372.695 0.000 372.885 58.535 ;
    RECT 373.295 0.000 373.485 58.535 ;
    RECT 373.895 0.000 374.085 58.535 ;
    RECT 374.495 0.000 374.685 58.535 ;
    RECT 375.095 0.000 375.285 58.535 ;
    RECT 375.695 0.000 375.885 58.535 ;
    RECT 376.295 0.000 376.485 58.535 ;
    RECT 376.895 0.000 377.085 58.535 ;
    RECT 377.495 0.000 377.685 58.535 ;
    RECT 378.095 0.000 378.285 58.535 ;
    RECT 378.695 0.000 378.885 58.535 ;
    RECT 379.295 0.000 379.485 58.535 ;
    RECT 379.895 0.000 380.085 58.535 ;
    RECT 380.495 0.000 380.685 58.535 ;
    RECT 381.095 0.000 381.285 58.535 ;
    RECT 381.695 0.000 381.885 58.535 ;
    RECT 382.295 0.000 382.485 58.535 ;
    RECT 382.895 0.000 383.085 58.535 ;
    RECT 383.495 0.000 383.685 58.535 ;
    RECT 384.095 0.000 384.285 58.535 ;
    RECT 384.695 0.000 384.885 58.535 ;
    RECT 385.295 0.000 385.485 58.535 ;
    RECT 385.895 0.000 386.085 58.535 ;
    RECT 386.495 0.000 386.685 58.535 ;
    RECT 387.095 0.000 387.285 58.535 ;
    RECT 387.695 0.000 387.885 58.535 ;
    RECT 388.295 0.000 388.485 58.535 ;
    RECT 388.895 0.000 389.085 58.535 ;
    RECT 389.495 0.000 389.685 58.535 ;
    RECT 390.095 0.000 390.285 58.535 ;
    RECT 390.695 0.000 390.885 58.535 ;
    RECT 391.295 0.000 391.485 58.535 ;
    RECT 391.895 0.000 392.085 58.535 ;
    RECT 392.495 0.000 392.685 58.535 ;
    RECT 393.095 0.000 393.285 58.535 ;
    RECT 393.695 0.000 393.885 58.535 ;
    RECT 394.295 0.000 394.485 58.535 ;
    RECT 394.895 0.000 395.085 58.535 ;
    RECT 395.495 0.000 395.685 58.535 ;
    RECT 396.095 0.000 396.285 58.535 ;
    RECT 396.695 0.000 396.885 58.535 ;
    RECT 397.295 0.000 397.485 58.535 ;
    RECT 397.895 0.000 398.085 58.535 ;
    RECT 398.495 0.000 398.685 58.535 ;
    RECT 399.095 0.000 399.285 58.535 ;
    RECT 399.695 0.000 399.885 58.535 ;
    RECT 400.295 0.000 400.485 58.535 ;
    RECT 400.895 0.000 401.085 58.535 ;
    RECT 401.495 0.000 401.685 58.535 ;
    RECT 402.095 0.000 402.285 58.535 ;
    RECT 402.695 0.000 402.885 58.535 ;
    RECT 403.295 0.000 403.485 58.535 ;
    RECT 403.895 0.000 404.085 58.535 ;
    RECT 404.495 0.000 404.685 58.535 ;
    RECT 405.095 0.000 405.285 58.535 ;
    RECT 405.695 0.000 405.885 58.535 ;
    RECT 406.295 0.000 406.485 58.535 ;
    RECT 406.895 0.000 407.085 58.535 ;
    RECT 407.495 0.000 407.685 58.535 ;
    RECT 408.095 0.000 408.285 58.535 ;
    RECT 408.695 0.000 408.885 58.535 ;
    RECT 409.295 0.000 409.485 58.535 ;
    RECT 409.895 0.000 410.085 58.535 ;
    RECT 410.495 0.000 410.685 58.535 ;
    RECT 411.095 0.000 411.285 58.535 ;
    RECT 411.695 0.000 411.885 58.535 ;
    RECT 412.295 0.000 412.485 58.535 ;
    RECT 412.895 0.000 413.085 58.535 ;
    RECT 413.495 0.000 413.685 58.535 ;
    RECT 414.095 0.000 414.285 58.535 ;
    RECT 414.695 0.000 414.885 58.535 ;
    RECT 415.295 0.000 415.485 58.535 ;
    RECT 415.895 0.000 416.085 58.535 ;
    RECT 416.495 0.000 416.685 58.535 ;
    RECT 417.095 0.000 417.285 58.535 ;
    RECT 417.695 0.000 417.885 58.535 ;
    RECT 418.295 0.000 418.485 58.535 ;
    RECT 418.895 0.000 419.085 58.535 ;
    RECT 419.495 0.000 419.685 58.535 ;
    RECT 420.095 0.000 420.285 58.535 ;
    RECT 420.695 0.000 420.885 58.535 ;
    RECT 421.295 0.000 421.485 58.535 ;
    RECT 421.895 0.000 422.085 58.535 ;
    RECT 422.495 0.000 422.685 58.535 ;
    RECT 423.095 0.000 423.285 58.535 ;
    RECT 423.695 0.000 423.885 58.535 ;
    RECT 424.295 0.000 424.485 58.535 ;
    RECT 424.895 0.000 425.085 58.535 ;
    RECT 425.495 0.000 425.685 58.535 ;
    RECT 426.095 0.000 426.285 58.535 ;
    RECT 426.695 0.000 426.885 58.535 ;
    RECT 427.295 0.000 427.485 58.535 ;
    RECT 427.895 0.000 428.085 58.535 ;
    RECT 428.495 0.000 428.685 58.535 ;
    RECT 429.095 0.000 429.285 58.535 ;
    RECT 429.695 0.000 429.885 58.535 ;
    RECT 430.295 0.000 430.485 58.535 ;
    RECT 430.895 0.000 431.085 58.535 ;
    RECT 431.495 0.000 431.685 58.535 ;
    RECT 432.095 0.000 432.285 58.535 ;
    RECT 432.695 0.000 432.885 58.535 ;
    RECT 433.295 0.000 433.485 58.535 ;
    RECT 433.895 0.000 434.085 58.535 ;
    RECT 434.495 0.000 434.685 58.535 ;
    RECT 435.095 0.000 435.285 58.535 ;
    RECT 435.695 0.000 435.885 58.535 ;
    RECT 436.295 0.000 436.485 58.535 ;
    RECT 436.895 0.000 437.085 58.535 ;
    RECT 437.495 0.000 437.685 58.535 ;
    RECT 438.095 0.000 438.285 58.535 ;
    RECT 438.695 0.000 438.885 58.535 ;
    RECT 439.295 0.000 439.485 58.535 ;
    RECT 439.895 0.000 440.085 58.535 ;
    RECT 440.495 0.000 440.685 58.535 ;
    RECT 441.095 0.000 441.285 58.535 ;
    RECT 441.695 0.000 441.885 58.535 ;
    RECT 442.295 0.000 442.485 58.535 ;
    RECT 442.895 0.000 443.085 58.535 ;
    RECT 443.495 0.000 443.685 58.535 ;
    RECT 444.095 0.000 444.285 58.535 ;
    RECT 444.695 0.000 444.885 58.535 ;
    RECT 445.295 0.000 445.485 58.535 ;
    RECT 445.895 0.000 446.085 58.535 ;
    RECT 446.495 0.000 446.685 58.535 ;
    RECT 447.095 0.000 447.285 58.535 ;
    RECT 447.695 0.000 447.885 58.535 ;
    RECT 448.295 0.000 448.485 58.535 ;
    RECT 448.895 0.000 449.085 58.535 ;
    RECT 449.495 0.000 449.685 58.535 ;
    RECT 450.095 0.000 450.285 58.535 ;
    RECT 450.695 0.000 450.885 58.535 ;
    RECT 451.295 0.000 451.485 58.535 ;
    RECT 451.895 0.000 452.085 58.535 ;
    RECT 452.495 0.000 452.685 58.535 ;
    RECT 453.095 0.000 453.285 58.535 ;
    RECT 453.695 0.000 453.885 58.535 ;
    RECT 454.295 0.000 454.485 58.535 ;
    RECT 454.895 0.000 455.085 58.535 ;
    RECT 455.495 0.000 455.685 58.535 ;
    RECT 456.095 0.000 456.285 58.535 ;
    RECT 456.695 0.000 456.885 58.535 ;
    RECT 457.295 0.000 457.485 58.535 ;
    RECT 457.895 0.000 458.085 58.535 ;
    RECT 458.495 0.000 458.685 58.535 ;
    RECT 459.095 0.000 459.285 58.535 ;
    RECT 459.695 0.000 459.885 58.535 ;
    RECT 460.295 0.000 460.485 58.535 ;
    RECT 460.895 0.000 461.085 58.535 ;
    RECT 461.495 0.000 461.685 58.535 ;
    RECT 462.095 0.000 462.285 58.535 ;
    RECT 462.695 0.000 462.885 58.535 ;
    RECT 463.295 0.000 463.485 58.535 ;
    RECT 463.895 0.000 464.085 58.535 ;
    RECT 464.495 0.000 464.685 58.535 ;
    RECT 465.095 0.000 465.285 58.535 ;
    RECT 465.695 0.000 465.885 58.535 ;
    RECT 466.295 0.000 466.485 58.535 ;
    RECT 466.895 0.000 467.085 58.535 ;
    RECT 467.495 0.000 467.685 58.535 ;
    RECT 468.095 0.000 468.285 58.535 ;
    RECT 468.695 0.000 468.885 58.535 ;
    RECT 469.295 0.000 469.485 58.535 ;
    RECT 469.895 0.000 470.085 58.535 ;
    RECT 470.495 0.000 470.685 58.535 ;
    RECT 471.095 0.000 471.285 58.535 ;
    RECT 471.695 0.000 471.885 58.535 ;
    RECT 472.295 0.000 472.485 58.535 ;
    RECT 472.895 0.000 473.085 58.535 ;
    RECT 473.495 0.000 473.685 58.535 ;
    RECT 474.095 0.000 474.285 58.535 ;
    RECT 474.695 0.000 474.885 58.535 ;
    RECT 475.295 0.000 475.485 58.535 ;
    RECT 475.895 0.000 476.085 58.535 ;
    RECT 476.495 0.000 476.685 58.535 ;
    RECT 477.095 0.000 477.285 58.535 ;
    RECT 477.695 0.000 477.885 58.535 ;
    RECT 478.295 0.000 478.485 58.535 ;
    RECT 478.895 0.000 479.085 58.535 ;
    RECT 479.495 0.000 479.685 58.535 ;
    RECT 480.095 0.000 480.285 58.535 ;
    RECT 480.695 0.000 480.885 58.535 ;
    RECT 481.295 0.000 481.485 58.535 ;
    RECT 481.895 0.000 482.085 58.535 ;
    RECT 482.495 0.000 482.685 58.535 ;
    RECT 483.095 0.000 483.285 58.535 ;
    RECT 483.695 0.000 483.885 58.535 ;
    RECT 484.295 0.000 484.485 58.535 ;
    RECT 484.895 0.000 485.085 58.535 ;
    RECT 485.495 0.000 485.685 58.535 ;
    RECT 486.095 0.000 486.285 58.535 ;
    RECT 486.695 0.000 486.885 58.535 ;
    RECT 487.295 0.000 487.485 58.535 ;
    RECT 487.895 0.000 488.085 58.535 ;
    RECT 488.495 0.000 488.685 58.535 ;
    RECT 489.095 0.000 489.285 58.535 ;
    RECT 489.695 0.000 489.885 58.535 ;
    RECT 490.295 0.000 490.485 58.535 ;
    RECT 490.895 0.000 491.085 58.535 ;
    RECT 491.495 0.000 491.685 58.535 ;
    RECT 492.095 0.000 492.285 58.535 ;
    RECT 492.695 0.000 492.885 58.535 ;
    RECT 493.295 0.000 493.485 58.535 ;
    RECT 493.895 0.000 494.085 58.535 ;
    RECT 494.495 0.000 494.685 58.535 ;
    RECT 495.095 0.000 495.285 58.535 ;
    RECT 495.695 0.000 495.885 58.535 ;
    RECT 496.295 0.000 496.485 58.535 ;
    RECT 496.895 0.000 497.085 58.535 ;
    RECT 497.495 0.000 497.685 58.535 ;
    RECT 498.095 0.000 498.285 58.535 ;
    RECT 498.695 0.000 498.885 58.535 ;
    RECT 499.295 0.000 499.485 58.535 ;
    RECT 499.895 0.000 500.085 58.535 ;
    RECT 500.495 0.000 500.685 58.535 ;
    RECT 501.095 0.000 501.285 58.535 ;
    RECT 501.695 0.000 501.885 58.535 ;
    RECT 502.295 0.000 502.485 58.535 ;
    RECT 502.895 0.000 503.085 58.535 ;
    RECT 503.495 0.000 503.685 58.535 ;
    RECT 504.095 0.000 504.285 58.535 ;
    RECT 504.695 0.000 504.885 58.535 ;
    RECT 505.295 0.000 505.485 58.535 ;
    RECT 505.895 0.000 506.085 58.535 ;
    RECT 506.495 0.000 506.685 58.535 ;
    RECT 507.095 0.000 507.285 58.535 ;
    RECT 507.695 0.000 507.885 58.535 ;
    RECT 508.295 0.000 508.485 58.535 ;
    RECT 508.895 0.000 509.085 58.535 ;
    RECT 509.495 0.000 509.685 58.535 ;
    RECT 510.095 0.000 510.285 58.535 ;
    RECT 510.695 0.000 510.885 58.535 ;
    RECT 511.295 0.000 511.485 58.535 ;
    RECT 511.895 0.000 512.085 58.535 ;
    RECT 512.495 0.000 512.685 58.535 ;
    RECT 513.095 0.000 513.285 58.535 ;
    RECT 513.695 0.000 513.885 58.535 ;
    RECT 514.295 0.000 514.485 58.535 ;
    RECT 514.895 0.000 515.085 58.535 ;
    RECT 515.495 0.000 515.685 58.535 ;
    RECT 516.095 0.000 516.285 58.535 ;
    RECT 516.695 0.000 516.885 58.535 ;
    RECT 517.295 0.000 517.485 58.535 ;
    RECT 517.895 0.000 518.085 58.535 ;
    RECT 518.495 0.000 518.685 58.535 ;
    RECT 519.095 0.000 519.285 58.535 ;
    RECT 519.695 0.000 519.885 58.535 ;
    RECT 520.295 0.000 520.485 58.535 ;
    RECT 520.895 0.000 521.085 58.535 ;
    RECT 521.495 0.000 521.685 58.535 ;
    RECT 522.095 0.000 522.285 58.535 ;
    RECT 522.695 0.000 522.885 58.535 ;
    RECT 523.295 0.000 523.485 58.535 ;
    RECT 523.895 0.000 524.085 58.535 ;
    RECT 524.495 0.000 524.685 58.535 ;
    RECT 525.095 0.000 525.285 58.535 ;
    RECT 525.695 0.000 525.885 58.535 ;
    RECT 526.295 0.000 526.485 58.535 ;
    RECT 526.895 0.000 527.085 58.535 ;
    RECT 527.495 0.000 527.685 58.535 ;
    RECT 528.095 0.000 528.285 58.535 ;
    RECT 528.695 0.000 528.885 58.535 ;
    RECT 529.295 0.000 529.485 58.535 ;
    RECT 529.895 0.000 530.085 58.535 ;
    RECT 530.495 0.000 530.685 58.535 ;
    RECT 531.095 0.000 531.285 58.535 ;
    RECT 531.695 0.000 531.885 58.535 ;
    RECT 532.295 0.000 532.485 58.535 ;
    RECT 532.895 0.000 533.085 58.535 ;
    RECT 533.495 0.000 533.685 58.535 ;
    RECT 534.095 0.000 534.285 58.535 ;
    RECT 534.695 0.000 534.885 58.535 ;
    RECT 535.295 0.000 535.485 58.535 ;
    RECT 535.895 0.000 536.085 58.535 ;
    RECT 536.495 0.000 536.685 58.535 ;
    RECT 537.095 0.000 537.285 58.535 ;
    RECT 537.695 0.000 537.885 58.535 ;
    RECT 538.295 0.000 538.485 58.535 ;
    RECT 538.895 0.000 539.085 58.535 ;
    RECT 539.495 0.000 539.685 58.535 ;
    RECT 540.095 0.000 540.285 58.535 ;
    RECT 540.695 0.000 540.885 58.535 ;
    RECT 541.295 0.000 541.485 58.535 ;
    RECT 541.895 0.000 542.085 58.535 ;
    RECT 542.495 0.000 542.685 58.535 ;
    RECT 543.095 0.000 543.285 58.535 ;
    RECT 543.695 0.000 543.885 58.535 ;
    RECT 544.295 0.000 544.485 58.535 ;
    RECT 544.895 0.000 545.085 58.535 ;
    RECT 545.495 0.000 545.685 58.535 ;
    RECT 546.095 0.000 546.285 58.535 ;
    RECT 546.695 0.000 546.885 58.535 ;
    RECT 547.295 0.000 547.485 58.535 ;
    RECT 547.895 0.000 548.085 58.535 ;
    RECT 548.495 0.000 548.685 58.535 ;
    RECT 549.095 0.000 549.285 58.535 ;
    RECT 549.695 0.000 549.885 58.535 ;
    RECT 550.295 0.000 550.485 58.535 ;
    RECT 550.895 0.000 551.085 58.535 ;
    RECT 551.495 0.000 551.685 58.535 ;
    RECT 552.095 0.000 552.285 58.535 ;
    RECT 552.695 0.000 552.885 58.535 ;
    RECT 553.295 0.000 553.485 58.535 ;
    RECT 553.895 0.000 554.085 58.535 ;
    RECT 554.495 0.000 554.685 58.535 ;
    RECT 555.095 0.000 555.285 58.535 ;
    RECT 555.695 0.000 555.885 58.535 ;
    RECT 556.295 0.000 556.485 58.535 ;
    RECT 556.895 0.000 557.085 58.535 ;
    RECT 557.495 0.000 557.685 58.535 ;
    RECT 558.095 0.000 558.285 58.535 ;
    RECT 558.695 0.000 558.885 58.535 ;
    RECT 559.295 0.000 559.485 58.535 ;
    RECT 559.895 0.000 560.085 58.535 ;
    RECT 560.495 0.000 560.685 58.535 ;
    RECT 561.095 0.000 561.285 58.535 ;
    RECT 561.695 0.000 561.885 58.535 ;
    RECT 562.295 0.000 562.485 58.535 ;
    RECT 562.895 0.000 563.085 58.535 ;
    RECT 563.495 0.000 563.685 58.535 ;
    RECT 564.095 0.000 564.285 58.535 ;
    RECT 564.695 0.000 564.885 58.535 ;
    RECT 565.295 0.000 565.485 58.535 ;
    RECT 565.895 0.000 566.085 58.535 ;
    RECT 566.495 0.000 566.615 58.535 ;
    RECT 567.025 0.000 567.145 58.535 ;
    RECT 567.555 0.000 567.630 58.535 ;
END
END ics55_ecos_sram_256x128_m4_ww
END LIBRARY

